VERSION 5.8 ;
BUSBITCHARS "[]" ;
DIVIDERCHAR "/" ;
UNITS
    DATABASE MICRONS 1000 ;
END UNITS

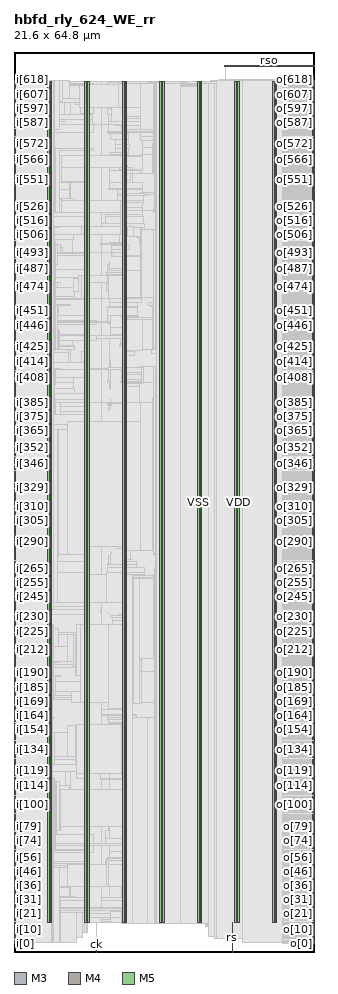
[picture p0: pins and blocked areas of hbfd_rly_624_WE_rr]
MACRO hbfd_rly_624_WE_rr
  FOREIGN hbfd_rly_624_WE_rr 0 0 ;
  CLASS BLOCK ;
  SIZE 21.6 BY 64.8 ;
  PIN ck
    DIRECTION INPUT ;
    USE SIGNAL ;
    PORT
      LAYER M3 ;
        RECT  5.904 0 5.922 0.038 ;
    END
    PORT
      LAYER M3 ;
        RECT  5.904 0.012 5.922 0.125 ;
    END
  END ck
  PIN i[0]
    DIRECTION INPUT ;
    USE SIGNAL ;
    PORT
      LAYER M4 ;
        RECT  0 0.624 0.084 0.648 ;
    END
  END i[0]
  PIN i[100]
    DIRECTION INPUT ;
    USE SIGNAL ;
    PORT
      LAYER M4 ;
        RECT  0 10.608 0.084 10.632 ;
    END
  END i[100]
  PIN i[101]
    DIRECTION INPUT ;
    USE SIGNAL ;
    PORT
      LAYER M4 ;
        RECT  0 10.704 0.084 10.728 ;
    END
  END i[101]
  PIN i[102]
    DIRECTION INPUT ;
    USE SIGNAL ;
    PORT
      LAYER M4 ;
        RECT  0 10.8 0.084 10.824 ;
    END
  END i[102]
  PIN i[103]
    DIRECTION INPUT ;
    USE SIGNAL ;
    PORT
      LAYER M4 ;
        RECT  0 10.896 0.084 10.92 ;
    END
  END i[103]
  PIN i[104]
    DIRECTION INPUT ;
    USE SIGNAL ;
    PORT
      LAYER M4 ;
        RECT  0 10.992 0.084 11.016 ;
    END
  END i[104]
  PIN i[105]
    DIRECTION INPUT ;
    USE SIGNAL ;
    PORT
      LAYER M4 ;
        RECT  0 11.088 0.084 11.112 ;
    END
  END i[105]
  PIN i[106]
    DIRECTION INPUT ;
    USE SIGNAL ;
    PORT
      LAYER M4 ;
        RECT  0 11.184 0.084 11.208 ;
    END
  END i[106]
  PIN i[107]
    DIRECTION INPUT ;
    USE SIGNAL ;
    PORT
      LAYER M4 ;
        RECT  0 11.328 0.084 11.352 ;
    END
  END i[107]
  PIN i[108]
    DIRECTION INPUT ;
    USE SIGNAL ;
    PORT
      LAYER M4 ;
        RECT  0 11.424 0.084 11.448 ;
    END
  END i[108]
  PIN i[109]
    DIRECTION INPUT ;
    USE SIGNAL ;
    PORT
      LAYER M4 ;
        RECT  0 11.52 0.084 11.544 ;
    END
  END i[109]
  PIN i[10]
    DIRECTION INPUT ;
    USE SIGNAL ;
    PORT
      LAYER M4 ;
        RECT  0 1.632 0.084 1.656 ;
    END
  END i[10]
  PIN i[110]
    DIRECTION INPUT ;
    USE SIGNAL ;
    PORT
      LAYER M4 ;
        RECT  0 11.616 0.084 11.64 ;
    END
  END i[110]
  PIN i[111]
    DIRECTION INPUT ;
    USE SIGNAL ;
    PORT
      LAYER M4 ;
        RECT  0 11.712 0.084 11.736 ;
    END
  END i[111]
  PIN i[112]
    DIRECTION INPUT ;
    USE SIGNAL ;
    PORT
      LAYER M4 ;
        RECT  0 11.808 0.084 11.832 ;
    END
  END i[112]
  PIN i[113]
    DIRECTION INPUT ;
    USE SIGNAL ;
    PORT
      LAYER M4 ;
        RECT  0 11.904 0.084 11.928 ;
    END
  END i[113]
  PIN i[114]
    DIRECTION INPUT ;
    USE SIGNAL ;
    PORT
      LAYER M4 ;
        RECT  0 12 0.084 12.024 ;
    END
  END i[114]
  PIN i[115]
    DIRECTION INPUT ;
    USE SIGNAL ;
    PORT
      LAYER M4 ;
        RECT  0 12.096 0.084 12.12 ;
    END
  END i[115]
  PIN i[116]
    DIRECTION INPUT ;
    USE SIGNAL ;
    PORT
      LAYER M4 ;
        RECT  0 12.192 0.084 12.216 ;
    END
  END i[116]
  PIN i[117]
    DIRECTION INPUT ;
    USE SIGNAL ;
    PORT
      LAYER M4 ;
        RECT  0 12.288 0.084 12.312 ;
    END
  END i[117]
  PIN i[118]
    DIRECTION INPUT ;
    USE SIGNAL ;
    PORT
      LAYER M4 ;
        RECT  0 12.384 0.084 12.408 ;
    END
  END i[118]
  PIN i[119]
    DIRECTION INPUT ;
    USE SIGNAL ;
    PORT
      LAYER M4 ;
        RECT  0 12.48 0.084 12.504 ;
    END
  END i[119]
  PIN i[11]
    DIRECTION INPUT ;
    USE SIGNAL ;
    PORT
      LAYER M4 ;
        RECT  0 1.728 0.084 1.752 ;
    END
  END i[11]
  PIN i[120]
    DIRECTION INPUT ;
    USE SIGNAL ;
    PORT
      LAYER M4 ;
        RECT  0 12.576 0.084 12.6 ;
    END
  END i[120]
  PIN i[121]
    DIRECTION INPUT ;
    USE SIGNAL ;
    PORT
      LAYER M4 ;
        RECT  0 12.72 0.084 12.744 ;
    END
  END i[121]
  PIN i[122]
    DIRECTION INPUT ;
    USE SIGNAL ;
    PORT
      LAYER M4 ;
        RECT  0 12.816 0.084 12.84 ;
    END
  END i[122]
  PIN i[123]
    DIRECTION INPUT ;
    USE SIGNAL ;
    PORT
      LAYER M4 ;
        RECT  0 12.912 0.084 12.936 ;
    END
  END i[123]
  PIN i[124]
    DIRECTION INPUT ;
    USE SIGNAL ;
    PORT
      LAYER M4 ;
        RECT  0 13.008 0.084 13.032 ;
    END
  END i[124]
  PIN i[125]
    DIRECTION INPUT ;
    USE SIGNAL ;
    PORT
      LAYER M4 ;
        RECT  0 13.104 0.084 13.128 ;
    END
  END i[125]
  PIN i[126]
    DIRECTION INPUT ;
    USE SIGNAL ;
    PORT
      LAYER M4 ;
        RECT  0 13.2 0.084 13.224 ;
    END
  END i[126]
  PIN i[127]
    DIRECTION INPUT ;
    USE SIGNAL ;
    PORT
      LAYER M4 ;
        RECT  0 13.296 0.084 13.32 ;
    END
  END i[127]
  PIN i[128]
    DIRECTION INPUT ;
    USE SIGNAL ;
    PORT
      LAYER M4 ;
        RECT  0 13.392 0.084 13.416 ;
    END
  END i[128]
  PIN i[129]
    DIRECTION INPUT ;
    USE SIGNAL ;
    PORT
      LAYER M4 ;
        RECT  0 13.488 0.084 13.512 ;
    END
  END i[129]
  PIN i[12]
    DIRECTION INPUT ;
    USE SIGNAL ;
    PORT
      LAYER M4 ;
        RECT  0 1.824 0.084 1.848 ;
    END
  END i[12]
  PIN i[130]
    DIRECTION INPUT ;
    USE SIGNAL ;
    PORT
      LAYER M4 ;
        RECT  0 13.584 0.084 13.608 ;
    END
  END i[130]
  PIN i[131]
    DIRECTION INPUT ;
    USE SIGNAL ;
    PORT
      LAYER M4 ;
        RECT  0 13.68 0.084 13.704 ;
    END
  END i[131]
  PIN i[132]
    DIRECTION INPUT ;
    USE SIGNAL ;
    PORT
      LAYER M4 ;
        RECT  0 13.776 0.084 13.8 ;
    END
  END i[132]
  PIN i[133]
    DIRECTION INPUT ;
    USE SIGNAL ;
    PORT
      LAYER M4 ;
        RECT  0 13.872 0.084 13.896 ;
    END
  END i[133]
  PIN i[134]
    DIRECTION INPUT ;
    USE SIGNAL ;
    PORT
      LAYER M4 ;
        RECT  0 14.016 0.084 14.04 ;
    END
  END i[134]
  PIN i[135]
    DIRECTION INPUT ;
    USE SIGNAL ;
    PORT
      LAYER M4 ;
        RECT  0 14.112 0.084 14.136 ;
    END
  END i[135]
  PIN i[136]
    DIRECTION INPUT ;
    USE SIGNAL ;
    PORT
      LAYER M4 ;
        RECT  0 14.208 0.084 14.232 ;
    END
  END i[136]
  PIN i[137]
    DIRECTION INPUT ;
    USE SIGNAL ;
    PORT
      LAYER M4 ;
        RECT  0 14.304 0.084 14.328 ;
    END
  END i[137]
  PIN i[138]
    DIRECTION INPUT ;
    USE SIGNAL ;
    PORT
      LAYER M4 ;
        RECT  0 14.4 0.084 14.424 ;
    END
  END i[138]
  PIN i[139]
    DIRECTION INPUT ;
    USE SIGNAL ;
    PORT
      LAYER M4 ;
        RECT  0 14.496 0.084 14.52 ;
    END
  END i[139]
  PIN i[13]
    DIRECTION INPUT ;
    USE SIGNAL ;
    PORT
      LAYER M4 ;
        RECT  0 1.92 0.084 1.944 ;
    END
  END i[13]
  PIN i[140]
    DIRECTION INPUT ;
    USE SIGNAL ;
    PORT
      LAYER M4 ;
        RECT  0 14.592 0.084 14.616 ;
    END
  END i[140]
  PIN i[141]
    DIRECTION INPUT ;
    USE SIGNAL ;
    PORT
      LAYER M4 ;
        RECT  0 14.688 0.084 14.712 ;
    END
  END i[141]
  PIN i[142]
    DIRECTION INPUT ;
    USE SIGNAL ;
    PORT
      LAYER M4 ;
        RECT  0 14.784 0.084 14.808 ;
    END
  END i[142]
  PIN i[143]
    DIRECTION INPUT ;
    USE SIGNAL ;
    PORT
      LAYER M4 ;
        RECT  0 14.88 0.084 14.904 ;
    END
  END i[143]
  PIN i[144]
    DIRECTION INPUT ;
    USE SIGNAL ;
    PORT
      LAYER M4 ;
        RECT  0 14.976 0.084 15 ;
    END
  END i[144]
  PIN i[145]
    DIRECTION INPUT ;
    USE SIGNAL ;
    PORT
      LAYER M4 ;
        RECT  0 15.072 0.084 15.096 ;
    END
  END i[145]
  PIN i[146]
    DIRECTION INPUT ;
    USE SIGNAL ;
    PORT
      LAYER M4 ;
        RECT  0 15.168 0.084 15.192 ;
    END
  END i[146]
  PIN i[147]
    DIRECTION INPUT ;
    USE SIGNAL ;
    PORT
      LAYER M4 ;
        RECT  0 15.312 0.084 15.336 ;
    END
  END i[147]
  PIN i[148]
    DIRECTION INPUT ;
    USE SIGNAL ;
    PORT
      LAYER M4 ;
        RECT  0 15.408 0.084 15.432 ;
    END
  END i[148]
  PIN i[149]
    DIRECTION INPUT ;
    USE SIGNAL ;
    PORT
      LAYER M4 ;
        RECT  0 15.504 0.084 15.528 ;
    END
  END i[149]
  PIN i[14]
    DIRECTION INPUT ;
    USE SIGNAL ;
    PORT
      LAYER M4 ;
        RECT  0 2.016 0.084 2.04 ;
    END
  END i[14]
  PIN i[150]
    DIRECTION INPUT ;
    USE SIGNAL ;
    PORT
      LAYER M4 ;
        RECT  0 15.6 0.084 15.624 ;
    END
  END i[150]
  PIN i[151]
    DIRECTION INPUT ;
    USE SIGNAL ;
    PORT
      LAYER M4 ;
        RECT  0 15.696 0.084 15.72 ;
    END
  END i[151]
  PIN i[152]
    DIRECTION INPUT ;
    USE SIGNAL ;
    PORT
      LAYER M4 ;
        RECT  0 15.792 0.084 15.816 ;
    END
  END i[152]
  PIN i[153]
    DIRECTION INPUT ;
    USE SIGNAL ;
    PORT
      LAYER M4 ;
        RECT  0 15.888 0.084 15.912 ;
    END
  END i[153]
  PIN i[154]
    DIRECTION INPUT ;
    USE SIGNAL ;
    PORT
      LAYER M4 ;
        RECT  0 15.984 0.084 16.008 ;
    END
  END i[154]
  PIN i[155]
    DIRECTION INPUT ;
    USE SIGNAL ;
    PORT
      LAYER M4 ;
        RECT  0 16.08 0.084 16.104 ;
    END
  END i[155]
  PIN i[156]
    DIRECTION INPUT ;
    USE SIGNAL ;
    PORT
      LAYER M4 ;
        RECT  0 16.176 0.084 16.2 ;
    END
  END i[156]
  PIN i[157]
    DIRECTION INPUT ;
    USE SIGNAL ;
    PORT
      LAYER M4 ;
        RECT  0 16.272 0.084 16.296 ;
    END
  END i[157]
  PIN i[158]
    DIRECTION INPUT ;
    USE SIGNAL ;
    PORT
      LAYER M4 ;
        RECT  0 16.368 0.084 16.392 ;
    END
  END i[158]
  PIN i[159]
    DIRECTION INPUT ;
    USE SIGNAL ;
    PORT
      LAYER M4 ;
        RECT  0 16.464 0.084 16.488 ;
    END
  END i[159]
  PIN i[15]
    DIRECTION INPUT ;
    USE SIGNAL ;
    PORT
      LAYER M4 ;
        RECT  0 2.112 0.084 2.136 ;
    END
  END i[15]
  PIN i[160]
    DIRECTION INPUT ;
    USE SIGNAL ;
    PORT
      LAYER M4 ;
        RECT  0 16.608 0.084 16.632 ;
    END
  END i[160]
  PIN i[161]
    DIRECTION INPUT ;
    USE SIGNAL ;
    PORT
      LAYER M4 ;
        RECT  0 16.704 0.084 16.728 ;
    END
  END i[161]
  PIN i[162]
    DIRECTION INPUT ;
    USE SIGNAL ;
    PORT
      LAYER M4 ;
        RECT  0 16.8 0.084 16.824 ;
    END
  END i[162]
  PIN i[163]
    DIRECTION INPUT ;
    USE SIGNAL ;
    PORT
      LAYER M4 ;
        RECT  0 16.896 0.084 16.92 ;
    END
  END i[163]
  PIN i[164]
    DIRECTION INPUT ;
    USE SIGNAL ;
    PORT
      LAYER M4 ;
        RECT  0 16.992 0.084 17.016 ;
    END
  END i[164]
  PIN i[165]
    DIRECTION INPUT ;
    USE SIGNAL ;
    PORT
      LAYER M4 ;
        RECT  0 17.088 0.084 17.112 ;
    END
  END i[165]
  PIN i[166]
    DIRECTION INPUT ;
    USE SIGNAL ;
    PORT
      LAYER M4 ;
        RECT  0 17.184 0.084 17.208 ;
    END
  END i[166]
  PIN i[167]
    DIRECTION INPUT ;
    USE SIGNAL ;
    PORT
      LAYER M4 ;
        RECT  0 17.28 0.084 17.304 ;
    END
  END i[167]
  PIN i[168]
    DIRECTION INPUT ;
    USE SIGNAL ;
    PORT
      LAYER M4 ;
        RECT  0 17.376 0.084 17.4 ;
    END
  END i[168]
  PIN i[169]
    DIRECTION INPUT ;
    USE SIGNAL ;
    PORT
      LAYER M4 ;
        RECT  0 17.472 0.084 17.496 ;
    END
  END i[169]
  PIN i[16]
    DIRECTION INPUT ;
    USE SIGNAL ;
    PORT
      LAYER M4 ;
        RECT  0 2.256 0.084 2.28 ;
    END
  END i[16]
  PIN i[170]
    DIRECTION INPUT ;
    USE SIGNAL ;
    PORT
      LAYER M4 ;
        RECT  0 17.568 0.084 17.592 ;
    END
  END i[170]
  PIN i[171]
    DIRECTION INPUT ;
    USE SIGNAL ;
    PORT
      LAYER M4 ;
        RECT  0 17.664 0.084 17.688 ;
    END
  END i[171]
  PIN i[172]
    DIRECTION INPUT ;
    USE SIGNAL ;
    PORT
      LAYER M4 ;
        RECT  0 17.76 0.084 17.784 ;
    END
  END i[172]
  PIN i[173]
    DIRECTION INPUT ;
    USE SIGNAL ;
    PORT
      LAYER M4 ;
        RECT  0 17.904 0.084 17.928 ;
    END
  END i[173]
  PIN i[174]
    DIRECTION INPUT ;
    USE SIGNAL ;
    PORT
      LAYER M4 ;
        RECT  0 18 0.084 18.024 ;
    END
  END i[174]
  PIN i[175]
    DIRECTION INPUT ;
    USE SIGNAL ;
    PORT
      LAYER M4 ;
        RECT  0 18.096 0.084 18.12 ;
    END
  END i[175]
  PIN i[176]
    DIRECTION INPUT ;
    USE SIGNAL ;
    PORT
      LAYER M4 ;
        RECT  0 18.192 0.084 18.216 ;
    END
  END i[176]
  PIN i[177]
    DIRECTION INPUT ;
    USE SIGNAL ;
    PORT
      LAYER M4 ;
        RECT  0 18.288 0.084 18.312 ;
    END
  END i[177]
  PIN i[178]
    DIRECTION INPUT ;
    USE SIGNAL ;
    PORT
      LAYER M4 ;
        RECT  0 18.384 0.084 18.408 ;
    END
  END i[178]
  PIN i[179]
    DIRECTION INPUT ;
    USE SIGNAL ;
    PORT
      LAYER M4 ;
        RECT  0 18.48 0.084 18.504 ;
    END
  END i[179]
  PIN i[17]
    DIRECTION INPUT ;
    USE SIGNAL ;
    PORT
      LAYER M4 ;
        RECT  0 2.352 0.084 2.376 ;
    END
  END i[17]
  PIN i[180]
    DIRECTION INPUT ;
    USE SIGNAL ;
    PORT
      LAYER M4 ;
        RECT  0 18.576 0.084 18.6 ;
    END
  END i[180]
  PIN i[181]
    DIRECTION INPUT ;
    USE SIGNAL ;
    PORT
      LAYER M4 ;
        RECT  0 18.672 0.084 18.696 ;
    END
  END i[181]
  PIN i[182]
    DIRECTION INPUT ;
    USE SIGNAL ;
    PORT
      LAYER M4 ;
        RECT  0 18.768 0.084 18.792 ;
    END
  END i[182]
  PIN i[183]
    DIRECTION INPUT ;
    USE SIGNAL ;
    PORT
      LAYER M4 ;
        RECT  0 18.864 0.084 18.888 ;
    END
  END i[183]
  PIN i[184]
    DIRECTION INPUT ;
    USE SIGNAL ;
    PORT
      LAYER M4 ;
        RECT  0 18.96 0.084 18.984 ;
    END
  END i[184]
  PIN i[185]
    DIRECTION INPUT ;
    USE SIGNAL ;
    PORT
      LAYER M4 ;
        RECT  0 19.056 0.084 19.08 ;
    END
  END i[185]
  PIN i[186]
    DIRECTION INPUT ;
    USE SIGNAL ;
    PORT
      LAYER M4 ;
        RECT  0 19.2 0.084 19.224 ;
    END
  END i[186]
  PIN i[187]
    DIRECTION INPUT ;
    USE SIGNAL ;
    PORT
      LAYER M4 ;
        RECT  0 19.296 0.084 19.32 ;
    END
  END i[187]
  PIN i[188]
    DIRECTION INPUT ;
    USE SIGNAL ;
    PORT
      LAYER M4 ;
        RECT  0 19.392 0.084 19.416 ;
    END
  END i[188]
  PIN i[189]
    DIRECTION INPUT ;
    USE SIGNAL ;
    PORT
      LAYER M4 ;
        RECT  0 19.488 0.084 19.512 ;
    END
  END i[189]
  PIN i[18]
    DIRECTION INPUT ;
    USE SIGNAL ;
    PORT
      LAYER M4 ;
        RECT  0 2.448 0.084 2.472 ;
    END
  END i[18]
  PIN i[190]
    DIRECTION INPUT ;
    USE SIGNAL ;
    PORT
      LAYER M4 ;
        RECT  0 19.584 0.084 19.608 ;
    END
  END i[190]
  PIN i[191]
    DIRECTION INPUT ;
    USE SIGNAL ;
    PORT
      LAYER M4 ;
        RECT  0 19.68 0.084 19.704 ;
    END
  END i[191]
  PIN i[192]
    DIRECTION INPUT ;
    USE SIGNAL ;
    PORT
      LAYER M4 ;
        RECT  0 19.776 0.084 19.8 ;
    END
  END i[192]
  PIN i[193]
    DIRECTION INPUT ;
    USE SIGNAL ;
    PORT
      LAYER M4 ;
        RECT  0 19.872 0.084 19.896 ;
    END
  END i[193]
  PIN i[194]
    DIRECTION INPUT ;
    USE SIGNAL ;
    PORT
      LAYER M4 ;
        RECT  0 19.968 0.084 19.992 ;
    END
  END i[194]
  PIN i[195]
    DIRECTION INPUT ;
    USE SIGNAL ;
    PORT
      LAYER M4 ;
        RECT  0 20.064 0.084 20.088 ;
    END
  END i[195]
  PIN i[196]
    DIRECTION INPUT ;
    USE SIGNAL ;
    PORT
      LAYER M4 ;
        RECT  0 20.16 0.084 20.184 ;
    END
  END i[196]
  PIN i[197]
    DIRECTION INPUT ;
    USE SIGNAL ;
    PORT
      LAYER M4 ;
        RECT  0 20.256 0.084 20.28 ;
    END
  END i[197]
  PIN i[198]
    DIRECTION INPUT ;
    USE SIGNAL ;
    PORT
      LAYER M4 ;
        RECT  0 20.352 0.084 20.376 ;
    END
  END i[198]
  PIN i[199]
    DIRECTION INPUT ;
    USE SIGNAL ;
    PORT
      LAYER M4 ;
        RECT  0 20.496 0.084 20.52 ;
    END
  END i[199]
  PIN i[19]
    DIRECTION INPUT ;
    USE SIGNAL ;
    PORT
      LAYER M4 ;
        RECT  0 2.544 0.084 2.568 ;
    END
  END i[19]
  PIN i[1]
    DIRECTION INPUT ;
    USE SIGNAL ;
    PORT
      LAYER M4 ;
        RECT  0 0.72 0.084 0.744 ;
    END
  END i[1]
  PIN i[200]
    DIRECTION INPUT ;
    USE SIGNAL ;
    PORT
      LAYER M4 ;
        RECT  0 20.592 0.084 20.616 ;
    END
  END i[200]
  PIN i[201]
    DIRECTION INPUT ;
    USE SIGNAL ;
    PORT
      LAYER M4 ;
        RECT  0 20.688 0.084 20.712 ;
    END
  END i[201]
  PIN i[202]
    DIRECTION INPUT ;
    USE SIGNAL ;
    PORT
      LAYER M4 ;
        RECT  0 20.784 0.084 20.808 ;
    END
  END i[202]
  PIN i[203]
    DIRECTION INPUT ;
    USE SIGNAL ;
    PORT
      LAYER M4 ;
        RECT  0 20.88 0.084 20.904 ;
    END
  END i[203]
  PIN i[204]
    DIRECTION INPUT ;
    USE SIGNAL ;
    PORT
      LAYER M4 ;
        RECT  0 20.976 0.084 21 ;
    END
  END i[204]
  PIN i[205]
    DIRECTION INPUT ;
    USE SIGNAL ;
    PORT
      LAYER M4 ;
        RECT  0 21.072 0.084 21.096 ;
    END
  END i[205]
  PIN i[206]
    DIRECTION INPUT ;
    USE SIGNAL ;
    PORT
      LAYER M4 ;
        RECT  0 21.168 0.084 21.192 ;
    END
  END i[206]
  PIN i[207]
    DIRECTION INPUT ;
    USE SIGNAL ;
    PORT
      LAYER M4 ;
        RECT  0 21.264 0.084 21.288 ;
    END
  END i[207]
  PIN i[208]
    DIRECTION INPUT ;
    USE SIGNAL ;
    PORT
      LAYER M4 ;
        RECT  0 21.36 0.084 21.384 ;
    END
  END i[208]
  PIN i[209]
    DIRECTION INPUT ;
    USE SIGNAL ;
    PORT
      LAYER M4 ;
        RECT  0 21.456 0.084 21.48 ;
    END
  END i[209]
  PIN i[20]
    DIRECTION INPUT ;
    USE SIGNAL ;
    PORT
      LAYER M4 ;
        RECT  0 2.64 0.084 2.664 ;
    END
  END i[20]
  PIN i[210]
    DIRECTION INPUT ;
    USE SIGNAL ;
    PORT
      LAYER M4 ;
        RECT  0 21.552 0.084 21.576 ;
    END
  END i[210]
  PIN i[211]
    DIRECTION INPUT ;
    USE SIGNAL ;
    PORT
      LAYER M4 ;
        RECT  0 21.648 0.084 21.672 ;
    END
  END i[211]
  PIN i[212]
    DIRECTION INPUT ;
    USE SIGNAL ;
    PORT
      LAYER M4 ;
        RECT  0 21.792 0.084 21.816 ;
    END
  END i[212]
  PIN i[213]
    DIRECTION INPUT ;
    USE SIGNAL ;
    PORT
      LAYER M4 ;
        RECT  0 21.888 0.084 21.912 ;
    END
  END i[213]
  PIN i[214]
    DIRECTION INPUT ;
    USE SIGNAL ;
    PORT
      LAYER M4 ;
        RECT  0 21.984 0.084 22.008 ;
    END
  END i[214]
  PIN i[215]
    DIRECTION INPUT ;
    USE SIGNAL ;
    PORT
      LAYER M4 ;
        RECT  0 22.08 0.084 22.104 ;
    END
  END i[215]
  PIN i[216]
    DIRECTION INPUT ;
    USE SIGNAL ;
    PORT
      LAYER M4 ;
        RECT  0 22.176 0.084 22.2 ;
    END
  END i[216]
  PIN i[217]
    DIRECTION INPUT ;
    USE SIGNAL ;
    PORT
      LAYER M4 ;
        RECT  0 22.272 0.084 22.296 ;
    END
  END i[217]
  PIN i[218]
    DIRECTION INPUT ;
    USE SIGNAL ;
    PORT
      LAYER M4 ;
        RECT  0 22.368 0.084 22.392 ;
    END
  END i[218]
  PIN i[219]
    DIRECTION INPUT ;
    USE SIGNAL ;
    PORT
      LAYER M4 ;
        RECT  0 22.464 0.084 22.488 ;
    END
  END i[219]
  PIN i[21]
    DIRECTION INPUT ;
    USE SIGNAL ;
    PORT
      LAYER M4 ;
        RECT  0 2.736 0.084 2.76 ;
    END
  END i[21]
  PIN i[220]
    DIRECTION INPUT ;
    USE SIGNAL ;
    PORT
      LAYER M4 ;
        RECT  0 22.56 0.084 22.584 ;
    END
  END i[220]
  PIN i[221]
    DIRECTION INPUT ;
    USE SIGNAL ;
    PORT
      LAYER M4 ;
        RECT  0 22.656 0.084 22.68 ;
    END
  END i[221]
  PIN i[222]
    DIRECTION INPUT ;
    USE SIGNAL ;
    PORT
      LAYER M4 ;
        RECT  0 22.752 0.084 22.776 ;
    END
  END i[222]
  PIN i[223]
    DIRECTION INPUT ;
    USE SIGNAL ;
    PORT
      LAYER M4 ;
        RECT  0 22.848 0.084 22.872 ;
    END
  END i[223]
  PIN i[224]
    DIRECTION INPUT ;
    USE SIGNAL ;
    PORT
      LAYER M4 ;
        RECT  0 22.944 0.084 22.968 ;
    END
  END i[224]
  PIN i[225]
    DIRECTION INPUT ;
    USE SIGNAL ;
    PORT
      LAYER M4 ;
        RECT  0 23.088 0.084 23.112 ;
    END
  END i[225]
  PIN i[226]
    DIRECTION INPUT ;
    USE SIGNAL ;
    PORT
      LAYER M4 ;
        RECT  0 23.184 0.084 23.208 ;
    END
  END i[226]
  PIN i[227]
    DIRECTION INPUT ;
    USE SIGNAL ;
    PORT
      LAYER M4 ;
        RECT  0 23.28 0.084 23.304 ;
    END
  END i[227]
  PIN i[228]
    DIRECTION INPUT ;
    USE SIGNAL ;
    PORT
      LAYER M4 ;
        RECT  0 23.376 0.084 23.4 ;
    END
  END i[228]
  PIN i[229]
    DIRECTION INPUT ;
    USE SIGNAL ;
    PORT
      LAYER M4 ;
        RECT  0 23.472 0.084 23.496 ;
    END
  END i[229]
  PIN i[22]
    DIRECTION INPUT ;
    USE SIGNAL ;
    PORT
      LAYER M4 ;
        RECT  0 2.832 0.084 2.856 ;
    END
  END i[22]
  PIN i[230]
    DIRECTION INPUT ;
    USE SIGNAL ;
    PORT
      LAYER M4 ;
        RECT  0 23.568 0.084 23.592 ;
    END
  END i[230]
  PIN i[231]
    DIRECTION INPUT ;
    USE SIGNAL ;
    PORT
      LAYER M4 ;
        RECT  0 23.664 0.084 23.688 ;
    END
  END i[231]
  PIN i[232]
    DIRECTION INPUT ;
    USE SIGNAL ;
    PORT
      LAYER M4 ;
        RECT  0 23.76 0.084 23.784 ;
    END
  END i[232]
  PIN i[233]
    DIRECTION INPUT ;
    USE SIGNAL ;
    PORT
      LAYER M4 ;
        RECT  0 23.856 0.084 23.88 ;
    END
  END i[233]
  PIN i[234]
    DIRECTION INPUT ;
    USE SIGNAL ;
    PORT
      LAYER M4 ;
        RECT  0 23.952 0.084 23.976 ;
    END
  END i[234]
  PIN i[235]
    DIRECTION INPUT ;
    USE SIGNAL ;
    PORT
      LAYER M4 ;
        RECT  0 24.048 0.084 24.072 ;
    END
  END i[235]
  PIN i[236]
    DIRECTION INPUT ;
    USE SIGNAL ;
    PORT
      LAYER M4 ;
        RECT  0 24.144 0.084 24.168 ;
    END
  END i[236]
  PIN i[237]
    DIRECTION INPUT ;
    USE SIGNAL ;
    PORT
      LAYER M4 ;
        RECT  0 24.24 0.084 24.264 ;
    END
  END i[237]
  PIN i[238]
    DIRECTION INPUT ;
    USE SIGNAL ;
    PORT
      LAYER M4 ;
        RECT  0 24.384 0.084 24.408 ;
    END
  END i[238]
  PIN i[239]
    DIRECTION INPUT ;
    USE SIGNAL ;
    PORT
      LAYER M4 ;
        RECT  0 24.48 0.084 24.504 ;
    END
  END i[239]
  PIN i[23]
    DIRECTION INPUT ;
    USE SIGNAL ;
    PORT
      LAYER M4 ;
        RECT  0 2.928 0.084 2.952 ;
    END
  END i[23]
  PIN i[240]
    DIRECTION INPUT ;
    USE SIGNAL ;
    PORT
      LAYER M4 ;
        RECT  0 24.576 0.084 24.6 ;
    END
  END i[240]
  PIN i[241]
    DIRECTION INPUT ;
    USE SIGNAL ;
    PORT
      LAYER M4 ;
        RECT  0 24.672 0.084 24.696 ;
    END
  END i[241]
  PIN i[242]
    DIRECTION INPUT ;
    USE SIGNAL ;
    PORT
      LAYER M4 ;
        RECT  0 24.768 0.084 24.792 ;
    END
  END i[242]
  PIN i[243]
    DIRECTION INPUT ;
    USE SIGNAL ;
    PORT
      LAYER M4 ;
        RECT  0 24.864 0.084 24.888 ;
    END
  END i[243]
  PIN i[244]
    DIRECTION INPUT ;
    USE SIGNAL ;
    PORT
      LAYER M4 ;
        RECT  0 24.96 0.084 24.984 ;
    END
  END i[244]
  PIN i[245]
    DIRECTION INPUT ;
    USE SIGNAL ;
    PORT
      LAYER M4 ;
        RECT  0 25.056 0.084 25.08 ;
    END
  END i[245]
  PIN i[246]
    DIRECTION INPUT ;
    USE SIGNAL ;
    PORT
      LAYER M4 ;
        RECT  0 25.152 0.084 25.176 ;
    END
  END i[246]
  PIN i[247]
    DIRECTION INPUT ;
    USE SIGNAL ;
    PORT
      LAYER M4 ;
        RECT  0 25.248 0.084 25.272 ;
    END
  END i[247]
  PIN i[248]
    DIRECTION INPUT ;
    USE SIGNAL ;
    PORT
      LAYER M4 ;
        RECT  0 25.344 0.084 25.368 ;
    END
  END i[248]
  PIN i[249]
    DIRECTION INPUT ;
    USE SIGNAL ;
    PORT
      LAYER M4 ;
        RECT  0 25.44 0.084 25.464 ;
    END
  END i[249]
  PIN i[24]
    DIRECTION INPUT ;
    USE SIGNAL ;
    PORT
      LAYER M4 ;
        RECT  0 3.024 0.084 3.048 ;
    END
  END i[24]
  PIN i[250]
    DIRECTION INPUT ;
    USE SIGNAL ;
    PORT
      LAYER M4 ;
        RECT  0 25.536 0.084 25.56 ;
    END
  END i[250]
  PIN i[251]
    DIRECTION INPUT ;
    USE SIGNAL ;
    PORT
      LAYER M4 ;
        RECT  0 25.68 0.084 25.704 ;
    END
  END i[251]
  PIN i[252]
    DIRECTION INPUT ;
    USE SIGNAL ;
    PORT
      LAYER M4 ;
        RECT  0 25.776 0.084 25.8 ;
    END
  END i[252]
  PIN i[253]
    DIRECTION INPUT ;
    USE SIGNAL ;
    PORT
      LAYER M4 ;
        RECT  0 25.872 0.084 25.896 ;
    END
  END i[253]
  PIN i[254]
    DIRECTION INPUT ;
    USE SIGNAL ;
    PORT
      LAYER M4 ;
        RECT  0 25.968 0.084 25.992 ;
    END
  END i[254]
  PIN i[255]
    DIRECTION INPUT ;
    USE SIGNAL ;
    PORT
      LAYER M4 ;
        RECT  0 26.064 0.084 26.088 ;
    END
  END i[255]
  PIN i[256]
    DIRECTION INPUT ;
    USE SIGNAL ;
    PORT
      LAYER M4 ;
        RECT  0 26.16 0.084 26.184 ;
    END
  END i[256]
  PIN i[257]
    DIRECTION INPUT ;
    USE SIGNAL ;
    PORT
      LAYER M4 ;
        RECT  0 26.256 0.084 26.28 ;
    END
  END i[257]
  PIN i[258]
    DIRECTION INPUT ;
    USE SIGNAL ;
    PORT
      LAYER M4 ;
        RECT  0 26.352 0.084 26.376 ;
    END
  END i[258]
  PIN i[259]
    DIRECTION INPUT ;
    USE SIGNAL ;
    PORT
      LAYER M4 ;
        RECT  0 26.448 0.084 26.472 ;
    END
  END i[259]
  PIN i[25]
    DIRECTION INPUT ;
    USE SIGNAL ;
    PORT
      LAYER M4 ;
        RECT  0 3.12 0.084 3.144 ;
    END
  END i[25]
  PIN i[260]
    DIRECTION INPUT ;
    USE SIGNAL ;
    PORT
      LAYER M4 ;
        RECT  0 26.544 0.084 26.568 ;
    END
  END i[260]
  PIN i[261]
    DIRECTION INPUT ;
    USE SIGNAL ;
    PORT
      LAYER M4 ;
        RECT  0 26.64 0.084 26.664 ;
    END
  END i[261]
  PIN i[262]
    DIRECTION INPUT ;
    USE SIGNAL ;
    PORT
      LAYER M4 ;
        RECT  0 26.736 0.084 26.76 ;
    END
  END i[262]
  PIN i[263]
    DIRECTION INPUT ;
    USE SIGNAL ;
    PORT
      LAYER M4 ;
        RECT  0 26.832 0.084 26.856 ;
    END
  END i[263]
  PIN i[264]
    DIRECTION INPUT ;
    USE SIGNAL ;
    PORT
      LAYER M4 ;
        RECT  0 26.976 0.084 27 ;
    END
  END i[264]
  PIN i[265]
    DIRECTION INPUT ;
    USE SIGNAL ;
    PORT
      LAYER M4 ;
        RECT  0 27.072 0.084 27.096 ;
    END
  END i[265]
  PIN i[266]
    DIRECTION INPUT ;
    USE SIGNAL ;
    PORT
      LAYER M4 ;
        RECT  0 27.168 0.084 27.192 ;
    END
  END i[266]
  PIN i[267]
    DIRECTION INPUT ;
    USE SIGNAL ;
    PORT
      LAYER M4 ;
        RECT  0 27.264 0.084 27.288 ;
    END
  END i[267]
  PIN i[268]
    DIRECTION INPUT ;
    USE SIGNAL ;
    PORT
      LAYER M4 ;
        RECT  0 27.36 0.084 27.384 ;
    END
  END i[268]
  PIN i[269]
    DIRECTION INPUT ;
    USE SIGNAL ;
    PORT
      LAYER M4 ;
        RECT  0 27.456 0.084 27.48 ;
    END
  END i[269]
  PIN i[26]
    DIRECTION INPUT ;
    USE SIGNAL ;
    PORT
      LAYER M4 ;
        RECT  0 3.216 0.084 3.24 ;
    END
  END i[26]
  PIN i[270]
    DIRECTION INPUT ;
    USE SIGNAL ;
    PORT
      LAYER M4 ;
        RECT  0 27.552 0.084 27.576 ;
    END
  END i[270]
  PIN i[271]
    DIRECTION INPUT ;
    USE SIGNAL ;
    PORT
      LAYER M4 ;
        RECT  0 27.648 0.084 27.672 ;
    END
  END i[271]
  PIN i[272]
    DIRECTION INPUT ;
    USE SIGNAL ;
    PORT
      LAYER M4 ;
        RECT  0 27.744 0.084 27.768 ;
    END
  END i[272]
  PIN i[273]
    DIRECTION INPUT ;
    USE SIGNAL ;
    PORT
      LAYER M4 ;
        RECT  0 27.84 0.084 27.864 ;
    END
  END i[273]
  PIN i[274]
    DIRECTION INPUT ;
    USE SIGNAL ;
    PORT
      LAYER M4 ;
        RECT  0 27.936 0.084 27.96 ;
    END
  END i[274]
  PIN i[275]
    DIRECTION INPUT ;
    USE SIGNAL ;
    PORT
      LAYER M4 ;
        RECT  0 28.032 0.084 28.056 ;
    END
  END i[275]
  PIN i[276]
    DIRECTION INPUT ;
    USE SIGNAL ;
    PORT
      LAYER M4 ;
        RECT  0 28.128 0.084 28.152 ;
    END
  END i[276]
  PIN i[277]
    DIRECTION INPUT ;
    USE SIGNAL ;
    PORT
      LAYER M4 ;
        RECT  0 28.272 0.084 28.296 ;
    END
  END i[277]
  PIN i[278]
    DIRECTION INPUT ;
    USE SIGNAL ;
    PORT
      LAYER M4 ;
        RECT  0 28.368 0.084 28.392 ;
    END
  END i[278]
  PIN i[279]
    DIRECTION INPUT ;
    USE SIGNAL ;
    PORT
      LAYER M4 ;
        RECT  0 28.464 0.084 28.488 ;
    END
  END i[279]
  PIN i[27]
    DIRECTION INPUT ;
    USE SIGNAL ;
    PORT
      LAYER M4 ;
        RECT  0 3.312 0.084 3.336 ;
    END
  END i[27]
  PIN i[280]
    DIRECTION INPUT ;
    USE SIGNAL ;
    PORT
      LAYER M4 ;
        RECT  0 28.56 0.084 28.584 ;
    END
  END i[280]
  PIN i[281]
    DIRECTION INPUT ;
    USE SIGNAL ;
    PORT
      LAYER M4 ;
        RECT  0 28.656 0.084 28.68 ;
    END
  END i[281]
  PIN i[282]
    DIRECTION INPUT ;
    USE SIGNAL ;
    PORT
      LAYER M4 ;
        RECT  0 28.752 0.084 28.776 ;
    END
  END i[282]
  PIN i[283]
    DIRECTION INPUT ;
    USE SIGNAL ;
    PORT
      LAYER M4 ;
        RECT  0 28.848 0.084 28.872 ;
    END
  END i[283]
  PIN i[284]
    DIRECTION INPUT ;
    USE SIGNAL ;
    PORT
      LAYER M4 ;
        RECT  0 28.944 0.084 28.968 ;
    END
  END i[284]
  PIN i[285]
    DIRECTION INPUT ;
    USE SIGNAL ;
    PORT
      LAYER M4 ;
        RECT  0 29.04 0.084 29.064 ;
    END
  END i[285]
  PIN i[286]
    DIRECTION INPUT ;
    USE SIGNAL ;
    PORT
      LAYER M4 ;
        RECT  0 29.136 0.084 29.16 ;
    END
  END i[286]
  PIN i[287]
    DIRECTION INPUT ;
    USE SIGNAL ;
    PORT
      LAYER M4 ;
        RECT  0 29.232 0.084 29.256 ;
    END
  END i[287]
  PIN i[288]
    DIRECTION INPUT ;
    USE SIGNAL ;
    PORT
      LAYER M4 ;
        RECT  0 29.328 0.084 29.352 ;
    END
  END i[288]
  PIN i[289]
    DIRECTION INPUT ;
    USE SIGNAL ;
    PORT
      LAYER M4 ;
        RECT  0 29.424 0.084 29.448 ;
    END
  END i[289]
  PIN i[28]
    DIRECTION INPUT ;
    USE SIGNAL ;
    PORT
      LAYER M4 ;
        RECT  0 3.408 0.084 3.432 ;
    END
  END i[28]
  PIN i[290]
    DIRECTION INPUT ;
    USE SIGNAL ;
    PORT
      LAYER M4 ;
        RECT  0 29.568 0.084 29.592 ;
    END
  END i[290]
  PIN i[291]
    DIRECTION INPUT ;
    USE SIGNAL ;
    PORT
      LAYER M4 ;
        RECT  0 29.664 0.084 29.688 ;
    END
  END i[291]
  PIN i[292]
    DIRECTION INPUT ;
    USE SIGNAL ;
    PORT
      LAYER M4 ;
        RECT  0 29.76 0.084 29.784 ;
    END
  END i[292]
  PIN i[293]
    DIRECTION INPUT ;
    USE SIGNAL ;
    PORT
      LAYER M4 ;
        RECT  0 29.856 0.084 29.88 ;
    END
  END i[293]
  PIN i[294]
    DIRECTION INPUT ;
    USE SIGNAL ;
    PORT
      LAYER M4 ;
        RECT  0 29.952 0.084 29.976 ;
    END
  END i[294]
  PIN i[295]
    DIRECTION INPUT ;
    USE SIGNAL ;
    PORT
      LAYER M4 ;
        RECT  0 30.048 0.084 30.072 ;
    END
  END i[295]
  PIN i[296]
    DIRECTION INPUT ;
    USE SIGNAL ;
    PORT
      LAYER M4 ;
        RECT  0 30.144 0.084 30.168 ;
    END
  END i[296]
  PIN i[297]
    DIRECTION INPUT ;
    USE SIGNAL ;
    PORT
      LAYER M4 ;
        RECT  0 30.24 0.084 30.264 ;
    END
  END i[297]
  PIN i[298]
    DIRECTION INPUT ;
    USE SIGNAL ;
    PORT
      LAYER M4 ;
        RECT  0 30.336 0.084 30.36 ;
    END
  END i[298]
  PIN i[299]
    DIRECTION INPUT ;
    USE SIGNAL ;
    PORT
      LAYER M4 ;
        RECT  0 30.432 0.084 30.456 ;
    END
  END i[299]
  PIN i[29]
    DIRECTION INPUT ;
    USE SIGNAL ;
    PORT
      LAYER M4 ;
        RECT  0 3.552 0.084 3.576 ;
    END
  END i[29]
  PIN i[2]
    DIRECTION INPUT ;
    USE SIGNAL ;
    PORT
      LAYER M4 ;
        RECT  0 0.816 0.084 0.84 ;
    END
  END i[2]
  PIN i[300]
    DIRECTION INPUT ;
    USE SIGNAL ;
    PORT
      LAYER M4 ;
        RECT  0 30.528 0.084 30.552 ;
    END
  END i[300]
  PIN i[301]
    DIRECTION INPUT ;
    USE SIGNAL ;
    PORT
      LAYER M4 ;
        RECT  0 30.624 0.084 30.648 ;
    END
  END i[301]
  PIN i[302]
    DIRECTION INPUT ;
    USE SIGNAL ;
    PORT
      LAYER M4 ;
        RECT  0 30.72 0.084 30.744 ;
    END
  END i[302]
  PIN i[303]
    DIRECTION INPUT ;
    USE SIGNAL ;
    PORT
      LAYER M4 ;
        RECT  0 30.864 0.084 30.888 ;
    END
  END i[303]
  PIN i[304]
    DIRECTION INPUT ;
    USE SIGNAL ;
    PORT
      LAYER M4 ;
        RECT  0 30.96 0.084 30.984 ;
    END
  END i[304]
  PIN i[305]
    DIRECTION INPUT ;
    USE SIGNAL ;
    PORT
      LAYER M4 ;
        RECT  0 31.056 0.084 31.08 ;
    END
  END i[305]
  PIN i[306]
    DIRECTION INPUT ;
    USE SIGNAL ;
    PORT
      LAYER M4 ;
        RECT  0 31.152 0.084 31.176 ;
    END
  END i[306]
  PIN i[307]
    DIRECTION INPUT ;
    USE SIGNAL ;
    PORT
      LAYER M4 ;
        RECT  0 31.248 0.084 31.272 ;
    END
  END i[307]
  PIN i[308]
    DIRECTION INPUT ;
    USE SIGNAL ;
    PORT
      LAYER M4 ;
        RECT  0 31.344 0.084 31.368 ;
    END
  END i[308]
  PIN i[309]
    DIRECTION INPUT ;
    USE SIGNAL ;
    PORT
      LAYER M4 ;
        RECT  0 31.44 0.084 31.464 ;
    END
  END i[309]
  PIN i[30]
    DIRECTION INPUT ;
    USE SIGNAL ;
    PORT
      LAYER M4 ;
        RECT  0 3.648 0.084 3.672 ;
    END
  END i[30]
  PIN i[310]
    DIRECTION INPUT ;
    USE SIGNAL ;
    PORT
      LAYER M4 ;
        RECT  0 31.536 0.084 31.56 ;
    END
  END i[310]
  PIN i[311]
    DIRECTION INPUT ;
    USE SIGNAL ;
    PORT
      LAYER M4 ;
        RECT  0 31.632 0.084 31.656 ;
    END
  END i[311]
  PIN i[312]
    DIRECTION INPUT ;
    USE SIGNAL ;
    PORT
      LAYER M4 ;
        RECT  0 31.728 0.084 31.752 ;
    END
  END i[312]
  PIN i[313]
    DIRECTION INPUT ;
    USE SIGNAL ;
    PORT
      LAYER M4 ;
        RECT  0 31.824 0.084 31.848 ;
    END
  END i[313]
  PIN i[314]
    DIRECTION INPUT ;
    USE SIGNAL ;
    PORT
      LAYER M4 ;
        RECT  0 31.92 0.084 31.944 ;
    END
  END i[314]
  PIN i[315]
    DIRECTION INPUT ;
    USE SIGNAL ;
    PORT
      LAYER M4 ;
        RECT  0 32.016 0.084 32.04 ;
    END
  END i[315]
  PIN i[316]
    DIRECTION INPUT ;
    USE SIGNAL ;
    PORT
      LAYER M4 ;
        RECT  0 32.16 0.084 32.184 ;
    END
  END i[316]
  PIN i[317]
    DIRECTION INPUT ;
    USE SIGNAL ;
    PORT
      LAYER M4 ;
        RECT  0 32.256 0.084 32.28 ;
    END
  END i[317]
  PIN i[318]
    DIRECTION INPUT ;
    USE SIGNAL ;
    PORT
      LAYER M4 ;
        RECT  0 32.352 0.084 32.376 ;
    END
  END i[318]
  PIN i[319]
    DIRECTION INPUT ;
    USE SIGNAL ;
    PORT
      LAYER M4 ;
        RECT  0 32.448 0.084 32.472 ;
    END
  END i[319]
  PIN i[31]
    DIRECTION INPUT ;
    USE SIGNAL ;
    PORT
      LAYER M4 ;
        RECT  0 3.744 0.084 3.768 ;
    END
  END i[31]
  PIN i[320]
    DIRECTION INPUT ;
    USE SIGNAL ;
    PORT
      LAYER M4 ;
        RECT  0 32.544 0.084 32.568 ;
    END
  END i[320]
  PIN i[321]
    DIRECTION INPUT ;
    USE SIGNAL ;
    PORT
      LAYER M4 ;
        RECT  0 32.64 0.084 32.664 ;
    END
  END i[321]
  PIN i[322]
    DIRECTION INPUT ;
    USE SIGNAL ;
    PORT
      LAYER M4 ;
        RECT  0 32.736 0.084 32.76 ;
    END
  END i[322]
  PIN i[323]
    DIRECTION INPUT ;
    USE SIGNAL ;
    PORT
      LAYER M4 ;
        RECT  0 32.832 0.084 32.856 ;
    END
  END i[323]
  PIN i[324]
    DIRECTION INPUT ;
    USE SIGNAL ;
    PORT
      LAYER M4 ;
        RECT  0 32.928 0.084 32.952 ;
    END
  END i[324]
  PIN i[325]
    DIRECTION INPUT ;
    USE SIGNAL ;
    PORT
      LAYER M4 ;
        RECT  0 33.024 0.084 33.048 ;
    END
  END i[325]
  PIN i[326]
    DIRECTION INPUT ;
    USE SIGNAL ;
    PORT
      LAYER M4 ;
        RECT  0 33.12 0.084 33.144 ;
    END
  END i[326]
  PIN i[327]
    DIRECTION INPUT ;
    USE SIGNAL ;
    PORT
      LAYER M4 ;
        RECT  0 33.216 0.084 33.24 ;
    END
  END i[327]
  PIN i[328]
    DIRECTION INPUT ;
    USE SIGNAL ;
    PORT
      LAYER M4 ;
        RECT  0 33.312 0.084 33.336 ;
    END
  END i[328]
  PIN i[329]
    DIRECTION INPUT ;
    USE SIGNAL ;
    PORT
      LAYER M4 ;
        RECT  0 33.456 0.084 33.48 ;
    END
  END i[329]
  PIN i[32]
    DIRECTION INPUT ;
    USE SIGNAL ;
    PORT
      LAYER M4 ;
        RECT  0 3.84 0.084 3.864 ;
    END
  END i[32]
  PIN i[330]
    DIRECTION INPUT ;
    USE SIGNAL ;
    PORT
      LAYER M4 ;
        RECT  0 33.552 0.084 33.576 ;
    END
  END i[330]
  PIN i[331]
    DIRECTION INPUT ;
    USE SIGNAL ;
    PORT
      LAYER M4 ;
        RECT  0 33.648 0.084 33.672 ;
    END
  END i[331]
  PIN i[332]
    DIRECTION INPUT ;
    USE SIGNAL ;
    PORT
      LAYER M4 ;
        RECT  0 33.744 0.084 33.768 ;
    END
  END i[332]
  PIN i[333]
    DIRECTION INPUT ;
    USE SIGNAL ;
    PORT
      LAYER M4 ;
        RECT  0 33.84 0.084 33.864 ;
    END
  END i[333]
  PIN i[334]
    DIRECTION INPUT ;
    USE SIGNAL ;
    PORT
      LAYER M4 ;
        RECT  0 33.936 0.084 33.96 ;
    END
  END i[334]
  PIN i[335]
    DIRECTION INPUT ;
    USE SIGNAL ;
    PORT
      LAYER M4 ;
        RECT  0 34.032 0.084 34.056 ;
    END
  END i[335]
  PIN i[336]
    DIRECTION INPUT ;
    USE SIGNAL ;
    PORT
      LAYER M4 ;
        RECT  0 34.128 0.084 34.152 ;
    END
  END i[336]
  PIN i[337]
    DIRECTION INPUT ;
    USE SIGNAL ;
    PORT
      LAYER M4 ;
        RECT  0 34.224 0.084 34.248 ;
    END
  END i[337]
  PIN i[338]
    DIRECTION INPUT ;
    USE SIGNAL ;
    PORT
      LAYER M4 ;
        RECT  0 34.32 0.084 34.344 ;
    END
  END i[338]
  PIN i[339]
    DIRECTION INPUT ;
    USE SIGNAL ;
    PORT
      LAYER M4 ;
        RECT  0 34.416 0.084 34.44 ;
    END
  END i[339]
  PIN i[33]
    DIRECTION INPUT ;
    USE SIGNAL ;
    PORT
      LAYER M4 ;
        RECT  0 3.936 0.084 3.96 ;
    END
  END i[33]
  PIN i[340]
    DIRECTION INPUT ;
    USE SIGNAL ;
    PORT
      LAYER M4 ;
        RECT  0 34.512 0.084 34.536 ;
    END
  END i[340]
  PIN i[341]
    DIRECTION INPUT ;
    USE SIGNAL ;
    PORT
      LAYER M4 ;
        RECT  0 34.608 0.084 34.632 ;
    END
  END i[341]
  PIN i[342]
    DIRECTION INPUT ;
    USE SIGNAL ;
    PORT
      LAYER M4 ;
        RECT  0 34.752 0.084 34.776 ;
    END
  END i[342]
  PIN i[343]
    DIRECTION INPUT ;
    USE SIGNAL ;
    PORT
      LAYER M4 ;
        RECT  0 34.848 0.084 34.872 ;
    END
  END i[343]
  PIN i[344]
    DIRECTION INPUT ;
    USE SIGNAL ;
    PORT
      LAYER M4 ;
        RECT  0 34.944 0.084 34.968 ;
    END
  END i[344]
  PIN i[345]
    DIRECTION INPUT ;
    USE SIGNAL ;
    PORT
      LAYER M4 ;
        RECT  0 35.04 0.084 35.064 ;
    END
  END i[345]
  PIN i[346]
    DIRECTION INPUT ;
    USE SIGNAL ;
    PORT
      LAYER M4 ;
        RECT  0 35.136 0.084 35.16 ;
    END
  END i[346]
  PIN i[347]
    DIRECTION INPUT ;
    USE SIGNAL ;
    PORT
      LAYER M4 ;
        RECT  0 35.232 0.084 35.256 ;
    END
  END i[347]
  PIN i[348]
    DIRECTION INPUT ;
    USE SIGNAL ;
    PORT
      LAYER M4 ;
        RECT  0 35.328 0.084 35.352 ;
    END
  END i[348]
  PIN i[349]
    DIRECTION INPUT ;
    USE SIGNAL ;
    PORT
      LAYER M4 ;
        RECT  0 35.424 0.084 35.448 ;
    END
  END i[349]
  PIN i[34]
    DIRECTION INPUT ;
    USE SIGNAL ;
    PORT
      LAYER M4 ;
        RECT  0 4.032 0.084 4.056 ;
    END
  END i[34]
  PIN i[350]
    DIRECTION INPUT ;
    USE SIGNAL ;
    PORT
      LAYER M4 ;
        RECT  0 35.52 0.084 35.544 ;
    END
  END i[350]
  PIN i[351]
    DIRECTION INPUT ;
    USE SIGNAL ;
    PORT
      LAYER M4 ;
        RECT  0 35.616 0.084 35.64 ;
    END
  END i[351]
  PIN i[352]
    DIRECTION INPUT ;
    USE SIGNAL ;
    PORT
      LAYER M4 ;
        RECT  0 35.712 0.084 35.736 ;
    END
  END i[352]
  PIN i[353]
    DIRECTION INPUT ;
    USE SIGNAL ;
    PORT
      LAYER M4 ;
        RECT  0 35.808 0.084 35.832 ;
    END
  END i[353]
  PIN i[354]
    DIRECTION INPUT ;
    USE SIGNAL ;
    PORT
      LAYER M4 ;
        RECT  0 35.904 0.084 35.928 ;
    END
  END i[354]
  PIN i[355]
    DIRECTION INPUT ;
    USE SIGNAL ;
    PORT
      LAYER M4 ;
        RECT  0 36.048 0.084 36.072 ;
    END
  END i[355]
  PIN i[356]
    DIRECTION INPUT ;
    USE SIGNAL ;
    PORT
      LAYER M4 ;
        RECT  0 36.144 0.084 36.168 ;
    END
  END i[356]
  PIN i[357]
    DIRECTION INPUT ;
    USE SIGNAL ;
    PORT
      LAYER M4 ;
        RECT  0 36.24 0.084 36.264 ;
    END
  END i[357]
  PIN i[358]
    DIRECTION INPUT ;
    USE SIGNAL ;
    PORT
      LAYER M4 ;
        RECT  0 36.336 0.084 36.36 ;
    END
  END i[358]
  PIN i[359]
    DIRECTION INPUT ;
    USE SIGNAL ;
    PORT
      LAYER M4 ;
        RECT  0 36.432 0.084 36.456 ;
    END
  END i[359]
  PIN i[35]
    DIRECTION INPUT ;
    USE SIGNAL ;
    PORT
      LAYER M4 ;
        RECT  0 4.128 0.084 4.152 ;
    END
  END i[35]
  PIN i[360]
    DIRECTION INPUT ;
    USE SIGNAL ;
    PORT
      LAYER M4 ;
        RECT  0 36.528 0.084 36.552 ;
    END
  END i[360]
  PIN i[361]
    DIRECTION INPUT ;
    USE SIGNAL ;
    PORT
      LAYER M4 ;
        RECT  0 36.624 0.084 36.648 ;
    END
  END i[361]
  PIN i[362]
    DIRECTION INPUT ;
    USE SIGNAL ;
    PORT
      LAYER M4 ;
        RECT  0 36.72 0.084 36.744 ;
    END
  END i[362]
  PIN i[363]
    DIRECTION INPUT ;
    USE SIGNAL ;
    PORT
      LAYER M4 ;
        RECT  0 36.816 0.084 36.84 ;
    END
  END i[363]
  PIN i[364]
    DIRECTION INPUT ;
    USE SIGNAL ;
    PORT
      LAYER M4 ;
        RECT  0 36.912 0.084 36.936 ;
    END
  END i[364]
  PIN i[365]
    DIRECTION INPUT ;
    USE SIGNAL ;
    PORT
      LAYER M4 ;
        RECT  0 37.008 0.084 37.032 ;
    END
  END i[365]
  PIN i[366]
    DIRECTION INPUT ;
    USE SIGNAL ;
    PORT
      LAYER M4 ;
        RECT  0 37.104 0.084 37.128 ;
    END
  END i[366]
  PIN i[367]
    DIRECTION INPUT ;
    USE SIGNAL ;
    PORT
      LAYER M4 ;
        RECT  0 37.2 0.084 37.224 ;
    END
  END i[367]
  PIN i[368]
    DIRECTION INPUT ;
    USE SIGNAL ;
    PORT
      LAYER M4 ;
        RECT  0 37.344 0.084 37.368 ;
    END
  END i[368]
  PIN i[369]
    DIRECTION INPUT ;
    USE SIGNAL ;
    PORT
      LAYER M4 ;
        RECT  0 37.44 0.084 37.464 ;
    END
  END i[369]
  PIN i[36]
    DIRECTION INPUT ;
    USE SIGNAL ;
    PORT
      LAYER M4 ;
        RECT  0 4.224 0.084 4.248 ;
    END
  END i[36]
  PIN i[370]
    DIRECTION INPUT ;
    USE SIGNAL ;
    PORT
      LAYER M4 ;
        RECT  0 37.536 0.084 37.56 ;
    END
  END i[370]
  PIN i[371]
    DIRECTION INPUT ;
    USE SIGNAL ;
    PORT
      LAYER M4 ;
        RECT  0 37.632 0.084 37.656 ;
    END
  END i[371]
  PIN i[372]
    DIRECTION INPUT ;
    USE SIGNAL ;
    PORT
      LAYER M4 ;
        RECT  0 37.728 0.084 37.752 ;
    END
  END i[372]
  PIN i[373]
    DIRECTION INPUT ;
    USE SIGNAL ;
    PORT
      LAYER M4 ;
        RECT  0 37.824 0.084 37.848 ;
    END
  END i[373]
  PIN i[374]
    DIRECTION INPUT ;
    USE SIGNAL ;
    PORT
      LAYER M4 ;
        RECT  0 37.92 0.084 37.944 ;
    END
  END i[374]
  PIN i[375]
    DIRECTION INPUT ;
    USE SIGNAL ;
    PORT
      LAYER M4 ;
        RECT  0 38.016 0.084 38.04 ;
    END
  END i[375]
  PIN i[376]
    DIRECTION INPUT ;
    USE SIGNAL ;
    PORT
      LAYER M4 ;
        RECT  0 38.112 0.084 38.136 ;
    END
  END i[376]
  PIN i[377]
    DIRECTION INPUT ;
    USE SIGNAL ;
    PORT
      LAYER M4 ;
        RECT  0 38.208 0.084 38.232 ;
    END
  END i[377]
  PIN i[378]
    DIRECTION INPUT ;
    USE SIGNAL ;
    PORT
      LAYER M4 ;
        RECT  0 38.304 0.084 38.328 ;
    END
  END i[378]
  PIN i[379]
    DIRECTION INPUT ;
    USE SIGNAL ;
    PORT
      LAYER M4 ;
        RECT  0 38.4 0.084 38.424 ;
    END
  END i[379]
  PIN i[37]
    DIRECTION INPUT ;
    USE SIGNAL ;
    PORT
      LAYER M4 ;
        RECT  0 4.32 0.084 4.344 ;
    END
  END i[37]
  PIN i[380]
    DIRECTION INPUT ;
    USE SIGNAL ;
    PORT
      LAYER M4 ;
        RECT  0 38.496 0.084 38.52 ;
    END
  END i[380]
  PIN i[381]
    DIRECTION INPUT ;
    USE SIGNAL ;
    PORT
      LAYER M4 ;
        RECT  0 38.64 0.084 38.664 ;
    END
  END i[381]
  PIN i[382]
    DIRECTION INPUT ;
    USE SIGNAL ;
    PORT
      LAYER M4 ;
        RECT  0 38.736 0.084 38.76 ;
    END
  END i[382]
  PIN i[383]
    DIRECTION INPUT ;
    USE SIGNAL ;
    PORT
      LAYER M4 ;
        RECT  0 38.832 0.084 38.856 ;
    END
  END i[383]
  PIN i[384]
    DIRECTION INPUT ;
    USE SIGNAL ;
    PORT
      LAYER M4 ;
        RECT  0 38.928 0.084 38.952 ;
    END
  END i[384]
  PIN i[385]
    DIRECTION INPUT ;
    USE SIGNAL ;
    PORT
      LAYER M4 ;
        RECT  0 39.024 0.084 39.048 ;
    END
  END i[385]
  PIN i[386]
    DIRECTION INPUT ;
    USE SIGNAL ;
    PORT
      LAYER M4 ;
        RECT  0 39.12 0.084 39.144 ;
    END
  END i[386]
  PIN i[387]
    DIRECTION INPUT ;
    USE SIGNAL ;
    PORT
      LAYER M4 ;
        RECT  0 39.216 0.084 39.24 ;
    END
  END i[387]
  PIN i[388]
    DIRECTION INPUT ;
    USE SIGNAL ;
    PORT
      LAYER M4 ;
        RECT  0 39.312 0.084 39.336 ;
    END
  END i[388]
  PIN i[389]
    DIRECTION INPUT ;
    USE SIGNAL ;
    PORT
      LAYER M4 ;
        RECT  0 39.408 0.084 39.432 ;
    END
  END i[389]
  PIN i[38]
    DIRECTION INPUT ;
    USE SIGNAL ;
    PORT
      LAYER M4 ;
        RECT  0 4.416 0.084 4.44 ;
    END
  END i[38]
  PIN i[390]
    DIRECTION INPUT ;
    USE SIGNAL ;
    PORT
      LAYER M4 ;
        RECT  0 39.504 0.084 39.528 ;
    END
  END i[390]
  PIN i[391]
    DIRECTION INPUT ;
    USE SIGNAL ;
    PORT
      LAYER M4 ;
        RECT  0 39.6 0.084 39.624 ;
    END
  END i[391]
  PIN i[392]
    DIRECTION INPUT ;
    USE SIGNAL ;
    PORT
      LAYER M4 ;
        RECT  0 39.696 0.084 39.72 ;
    END
  END i[392]
  PIN i[393]
    DIRECTION INPUT ;
    USE SIGNAL ;
    PORT
      LAYER M4 ;
        RECT  0 39.792 0.084 39.816 ;
    END
  END i[393]
  PIN i[394]
    DIRECTION INPUT ;
    USE SIGNAL ;
    PORT
      LAYER M4 ;
        RECT  0 39.936 0.084 39.96 ;
    END
  END i[394]
  PIN i[395]
    DIRECTION INPUT ;
    USE SIGNAL ;
    PORT
      LAYER M4 ;
        RECT  0 40.032 0.084 40.056 ;
    END
  END i[395]
  PIN i[396]
    DIRECTION INPUT ;
    USE SIGNAL ;
    PORT
      LAYER M4 ;
        RECT  0 40.128 0.084 40.152 ;
    END
  END i[396]
  PIN i[397]
    DIRECTION INPUT ;
    USE SIGNAL ;
    PORT
      LAYER M4 ;
        RECT  0 40.224 0.084 40.248 ;
    END
  END i[397]
  PIN i[398]
    DIRECTION INPUT ;
    USE SIGNAL ;
    PORT
      LAYER M4 ;
        RECT  0 40.32 0.084 40.344 ;
    END
  END i[398]
  PIN i[399]
    DIRECTION INPUT ;
    USE SIGNAL ;
    PORT
      LAYER M4 ;
        RECT  0 40.416 0.084 40.44 ;
    END
  END i[399]
  PIN i[39]
    DIRECTION INPUT ;
    USE SIGNAL ;
    PORT
      LAYER M4 ;
        RECT  0 4.512 0.084 4.536 ;
    END
  END i[39]
  PIN i[3]
    DIRECTION INPUT ;
    USE SIGNAL ;
    PORT
      LAYER M4 ;
        RECT  0 0.96 0.084 0.984 ;
    END
  END i[3]
  PIN i[400]
    DIRECTION INPUT ;
    USE SIGNAL ;
    PORT
      LAYER M4 ;
        RECT  0 40.512 0.084 40.536 ;
    END
  END i[400]
  PIN i[401]
    DIRECTION INPUT ;
    USE SIGNAL ;
    PORT
      LAYER M4 ;
        RECT  0 40.608 0.084 40.632 ;
    END
  END i[401]
  PIN i[402]
    DIRECTION INPUT ;
    USE SIGNAL ;
    PORT
      LAYER M4 ;
        RECT  0 40.704 0.084 40.728 ;
    END
  END i[402]
  PIN i[403]
    DIRECTION INPUT ;
    USE SIGNAL ;
    PORT
      LAYER M4 ;
        RECT  0 40.8 0.084 40.824 ;
    END
  END i[403]
  PIN i[404]
    DIRECTION INPUT ;
    USE SIGNAL ;
    PORT
      LAYER M4 ;
        RECT  0 40.896 0.084 40.92 ;
    END
  END i[404]
  PIN i[405]
    DIRECTION INPUT ;
    USE SIGNAL ;
    PORT
      LAYER M4 ;
        RECT  0 40.992 0.084 41.016 ;
    END
  END i[405]
  PIN i[406]
    DIRECTION INPUT ;
    USE SIGNAL ;
    PORT
      LAYER M4 ;
        RECT  0 41.088 0.084 41.112 ;
    END
  END i[406]
  PIN i[407]
    DIRECTION INPUT ;
    USE SIGNAL ;
    PORT
      LAYER M4 ;
        RECT  0 41.184 0.084 41.208 ;
    END
  END i[407]
  PIN i[408]
    DIRECTION INPUT ;
    USE SIGNAL ;
    PORT
      LAYER M4 ;
        RECT  0 41.328 0.084 41.352 ;
    END
  END i[408]
  PIN i[409]
    DIRECTION INPUT ;
    USE SIGNAL ;
    PORT
      LAYER M4 ;
        RECT  0 41.424 0.084 41.448 ;
    END
  END i[409]
  PIN i[40]
    DIRECTION INPUT ;
    USE SIGNAL ;
    PORT
      LAYER M4 ;
        RECT  0 4.608 0.084 4.632 ;
    END
  END i[40]
  PIN i[410]
    DIRECTION INPUT ;
    USE SIGNAL ;
    PORT
      LAYER M4 ;
        RECT  0 41.52 0.084 41.544 ;
    END
  END i[410]
  PIN i[411]
    DIRECTION INPUT ;
    USE SIGNAL ;
    PORT
      LAYER M4 ;
        RECT  0 41.616 0.084 41.64 ;
    END
  END i[411]
  PIN i[412]
    DIRECTION INPUT ;
    USE SIGNAL ;
    PORT
      LAYER M4 ;
        RECT  0 41.712 0.084 41.736 ;
    END
  END i[412]
  PIN i[413]
    DIRECTION INPUT ;
    USE SIGNAL ;
    PORT
      LAYER M4 ;
        RECT  0 41.808 0.084 41.832 ;
    END
  END i[413]
  PIN i[414]
    DIRECTION INPUT ;
    USE SIGNAL ;
    PORT
      LAYER M4 ;
        RECT  0 41.904 0.084 41.928 ;
    END
  END i[414]
  PIN i[415]
    DIRECTION INPUT ;
    USE SIGNAL ;
    PORT
      LAYER M4 ;
        RECT  0 42 0.084 42.024 ;
    END
  END i[415]
  PIN i[416]
    DIRECTION INPUT ;
    USE SIGNAL ;
    PORT
      LAYER M4 ;
        RECT  0 42.096 0.084 42.12 ;
    END
  END i[416]
  PIN i[417]
    DIRECTION INPUT ;
    USE SIGNAL ;
    PORT
      LAYER M4 ;
        RECT  0 42.192 0.084 42.216 ;
    END
  END i[417]
  PIN i[418]
    DIRECTION INPUT ;
    USE SIGNAL ;
    PORT
      LAYER M4 ;
        RECT  0 42.288 0.084 42.312 ;
    END
  END i[418]
  PIN i[419]
    DIRECTION INPUT ;
    USE SIGNAL ;
    PORT
      LAYER M4 ;
        RECT  0 42.384 0.084 42.408 ;
    END
  END i[419]
  PIN i[41]
    DIRECTION INPUT ;
    USE SIGNAL ;
    PORT
      LAYER M4 ;
        RECT  0 4.704 0.084 4.728 ;
    END
  END i[41]
  PIN i[420]
    DIRECTION INPUT ;
    USE SIGNAL ;
    PORT
      LAYER M4 ;
        RECT  0 42.48 0.084 42.504 ;
    END
  END i[420]
  PIN i[421]
    DIRECTION INPUT ;
    USE SIGNAL ;
    PORT
      LAYER M4 ;
        RECT  0 42.624 0.084 42.648 ;
    END
  END i[421]
  PIN i[422]
    DIRECTION INPUT ;
    USE SIGNAL ;
    PORT
      LAYER M4 ;
        RECT  0 42.72 0.084 42.744 ;
    END
  END i[422]
  PIN i[423]
    DIRECTION INPUT ;
    USE SIGNAL ;
    PORT
      LAYER M4 ;
        RECT  0 42.816 0.084 42.84 ;
    END
  END i[423]
  PIN i[424]
    DIRECTION INPUT ;
    USE SIGNAL ;
    PORT
      LAYER M4 ;
        RECT  0 42.912 0.084 42.936 ;
    END
  END i[424]
  PIN i[425]
    DIRECTION INPUT ;
    USE SIGNAL ;
    PORT
      LAYER M4 ;
        RECT  0 43.008 0.084 43.032 ;
    END
  END i[425]
  PIN i[426]
    DIRECTION INPUT ;
    USE SIGNAL ;
    PORT
      LAYER M4 ;
        RECT  0 43.104 0.084 43.128 ;
    END
  END i[426]
  PIN i[427]
    DIRECTION INPUT ;
    USE SIGNAL ;
    PORT
      LAYER M4 ;
        RECT  0 43.2 0.084 43.224 ;
    END
  END i[427]
  PIN i[428]
    DIRECTION INPUT ;
    USE SIGNAL ;
    PORT
      LAYER M4 ;
        RECT  0 43.296 0.084 43.32 ;
    END
  END i[428]
  PIN i[429]
    DIRECTION INPUT ;
    USE SIGNAL ;
    PORT
      LAYER M4 ;
        RECT  0 43.392 0.084 43.416 ;
    END
  END i[429]
  PIN i[42]
    DIRECTION INPUT ;
    USE SIGNAL ;
    PORT
      LAYER M4 ;
        RECT  0 4.848 0.084 4.872 ;
    END
  END i[42]
  PIN i[430]
    DIRECTION INPUT ;
    USE SIGNAL ;
    PORT
      LAYER M4 ;
        RECT  0 43.488 0.084 43.512 ;
    END
  END i[430]
  PIN i[431]
    DIRECTION INPUT ;
    USE SIGNAL ;
    PORT
      LAYER M4 ;
        RECT  0 43.584 0.084 43.608 ;
    END
  END i[431]
  PIN i[432]
    DIRECTION INPUT ;
    USE SIGNAL ;
    PORT
      LAYER M4 ;
        RECT  0 43.68 0.084 43.704 ;
    END
  END i[432]
  PIN i[433]
    DIRECTION INPUT ;
    USE SIGNAL ;
    PORT
      LAYER M4 ;
        RECT  0 43.776 0.084 43.8 ;
    END
  END i[433]
  PIN i[434]
    DIRECTION INPUT ;
    USE SIGNAL ;
    PORT
      LAYER M4 ;
        RECT  0 43.92 0.084 43.944 ;
    END
  END i[434]
  PIN i[435]
    DIRECTION INPUT ;
    USE SIGNAL ;
    PORT
      LAYER M4 ;
        RECT  0 44.016 0.084 44.04 ;
    END
  END i[435]
  PIN i[436]
    DIRECTION INPUT ;
    USE SIGNAL ;
    PORT
      LAYER M4 ;
        RECT  0 44.112 0.084 44.136 ;
    END
  END i[436]
  PIN i[437]
    DIRECTION INPUT ;
    USE SIGNAL ;
    PORT
      LAYER M4 ;
        RECT  0 44.208 0.084 44.232 ;
    END
  END i[437]
  PIN i[438]
    DIRECTION INPUT ;
    USE SIGNAL ;
    PORT
      LAYER M4 ;
        RECT  0 44.304 0.084 44.328 ;
    END
  END i[438]
  PIN i[439]
    DIRECTION INPUT ;
    USE SIGNAL ;
    PORT
      LAYER M4 ;
        RECT  0 44.4 0.084 44.424 ;
    END
  END i[439]
  PIN i[43]
    DIRECTION INPUT ;
    USE SIGNAL ;
    PORT
      LAYER M4 ;
        RECT  0 4.944 0.084 4.968 ;
    END
  END i[43]
  PIN i[440]
    DIRECTION INPUT ;
    USE SIGNAL ;
    PORT
      LAYER M4 ;
        RECT  0 44.496 0.084 44.52 ;
    END
  END i[440]
  PIN i[441]
    DIRECTION INPUT ;
    USE SIGNAL ;
    PORT
      LAYER M4 ;
        RECT  0 44.592 0.084 44.616 ;
    END
  END i[441]
  PIN i[442]
    DIRECTION INPUT ;
    USE SIGNAL ;
    PORT
      LAYER M4 ;
        RECT  0 44.688 0.084 44.712 ;
    END
  END i[442]
  PIN i[443]
    DIRECTION INPUT ;
    USE SIGNAL ;
    PORT
      LAYER M4 ;
        RECT  0 44.784 0.084 44.808 ;
    END
  END i[443]
  PIN i[444]
    DIRECTION INPUT ;
    USE SIGNAL ;
    PORT
      LAYER M4 ;
        RECT  0 44.88 0.084 44.904 ;
    END
  END i[444]
  PIN i[445]
    DIRECTION INPUT ;
    USE SIGNAL ;
    PORT
      LAYER M4 ;
        RECT  0 44.976 0.084 45 ;
    END
  END i[445]
  PIN i[446]
    DIRECTION INPUT ;
    USE SIGNAL ;
    PORT
      LAYER M4 ;
        RECT  0 45.072 0.084 45.096 ;
    END
  END i[446]
  PIN i[447]
    DIRECTION INPUT ;
    USE SIGNAL ;
    PORT
      LAYER M4 ;
        RECT  0 45.216 0.084 45.24 ;
    END
  END i[447]
  PIN i[448]
    DIRECTION INPUT ;
    USE SIGNAL ;
    PORT
      LAYER M4 ;
        RECT  0 45.312 0.084 45.336 ;
    END
  END i[448]
  PIN i[449]
    DIRECTION INPUT ;
    USE SIGNAL ;
    PORT
      LAYER M4 ;
        RECT  0 45.408 0.084 45.432 ;
    END
  END i[449]
  PIN i[44]
    DIRECTION INPUT ;
    USE SIGNAL ;
    PORT
      LAYER M4 ;
        RECT  0 5.04 0.084 5.064 ;
    END
  END i[44]
  PIN i[450]
    DIRECTION INPUT ;
    USE SIGNAL ;
    PORT
      LAYER M4 ;
        RECT  0 45.504 0.084 45.528 ;
    END
  END i[450]
  PIN i[451]
    DIRECTION INPUT ;
    USE SIGNAL ;
    PORT
      LAYER M4 ;
        RECT  0 45.6 0.084 45.624 ;
    END
  END i[451]
  PIN i[452]
    DIRECTION INPUT ;
    USE SIGNAL ;
    PORT
      LAYER M4 ;
        RECT  0 45.696 0.084 45.72 ;
    END
  END i[452]
  PIN i[453]
    DIRECTION INPUT ;
    USE SIGNAL ;
    PORT
      LAYER M4 ;
        RECT  0 45.792 0.084 45.816 ;
    END
  END i[453]
  PIN i[454]
    DIRECTION INPUT ;
    USE SIGNAL ;
    PORT
      LAYER M4 ;
        RECT  0 45.888 0.084 45.912 ;
    END
  END i[454]
  PIN i[455]
    DIRECTION INPUT ;
    USE SIGNAL ;
    PORT
      LAYER M4 ;
        RECT  0 45.984 0.084 46.008 ;
    END
  END i[455]
  PIN i[456]
    DIRECTION INPUT ;
    USE SIGNAL ;
    PORT
      LAYER M4 ;
        RECT  0 46.08 0.084 46.104 ;
    END
  END i[456]
  PIN i[457]
    DIRECTION INPUT ;
    USE SIGNAL ;
    PORT
      LAYER M4 ;
        RECT  0 46.176 0.084 46.2 ;
    END
  END i[457]
  PIN i[458]
    DIRECTION INPUT ;
    USE SIGNAL ;
    PORT
      LAYER M4 ;
        RECT  0 46.272 0.084 46.296 ;
    END
  END i[458]
  PIN i[459]
    DIRECTION INPUT ;
    USE SIGNAL ;
    PORT
      LAYER M4 ;
        RECT  0 46.368 0.084 46.392 ;
    END
  END i[459]
  PIN i[45]
    DIRECTION INPUT ;
    USE SIGNAL ;
    PORT
      LAYER M4 ;
        RECT  0 5.136 0.084 5.16 ;
    END
  END i[45]
  PIN i[460]
    DIRECTION INPUT ;
    USE SIGNAL ;
    PORT
      LAYER M4 ;
        RECT  0 46.512 0.084 46.536 ;
    END
  END i[460]
  PIN i[461]
    DIRECTION INPUT ;
    USE SIGNAL ;
    PORT
      LAYER M4 ;
        RECT  0 46.608 0.084 46.632 ;
    END
  END i[461]
  PIN i[462]
    DIRECTION INPUT ;
    USE SIGNAL ;
    PORT
      LAYER M4 ;
        RECT  0 46.704 0.084 46.728 ;
    END
  END i[462]
  PIN i[463]
    DIRECTION INPUT ;
    USE SIGNAL ;
    PORT
      LAYER M4 ;
        RECT  0 46.8 0.084 46.824 ;
    END
  END i[463]
  PIN i[464]
    DIRECTION INPUT ;
    USE SIGNAL ;
    PORT
      LAYER M4 ;
        RECT  0 46.896 0.084 46.92 ;
    END
  END i[464]
  PIN i[465]
    DIRECTION INPUT ;
    USE SIGNAL ;
    PORT
      LAYER M4 ;
        RECT  0 46.992 0.084 47.016 ;
    END
  END i[465]
  PIN i[466]
    DIRECTION INPUT ;
    USE SIGNAL ;
    PORT
      LAYER M4 ;
        RECT  0 47.088 0.084 47.112 ;
    END
  END i[466]
  PIN i[467]
    DIRECTION INPUT ;
    USE SIGNAL ;
    PORT
      LAYER M4 ;
        RECT  0 47.184 0.084 47.208 ;
    END
  END i[467]
  PIN i[468]
    DIRECTION INPUT ;
    USE SIGNAL ;
    PORT
      LAYER M4 ;
        RECT  0 47.28 0.084 47.304 ;
    END
  END i[468]
  PIN i[469]
    DIRECTION INPUT ;
    USE SIGNAL ;
    PORT
      LAYER M4 ;
        RECT  0 47.376 0.084 47.4 ;
    END
  END i[469]
  PIN i[46]
    DIRECTION INPUT ;
    USE SIGNAL ;
    PORT
      LAYER M4 ;
        RECT  0 5.232 0.084 5.256 ;
    END
  END i[46]
  PIN i[470]
    DIRECTION INPUT ;
    USE SIGNAL ;
    PORT
      LAYER M4 ;
        RECT  0 47.472 0.084 47.496 ;
    END
  END i[470]
  PIN i[471]
    DIRECTION INPUT ;
    USE SIGNAL ;
    PORT
      LAYER M4 ;
        RECT  0 47.568 0.084 47.592 ;
    END
  END i[471]
  PIN i[472]
    DIRECTION INPUT ;
    USE SIGNAL ;
    PORT
      LAYER M4 ;
        RECT  0 47.664 0.084 47.688 ;
    END
  END i[472]
  PIN i[473]
    DIRECTION INPUT ;
    USE SIGNAL ;
    PORT
      LAYER M4 ;
        RECT  0 47.808 0.084 47.832 ;
    END
  END i[473]
  PIN i[474]
    DIRECTION INPUT ;
    USE SIGNAL ;
    PORT
      LAYER M4 ;
        RECT  0 47.904 0.084 47.928 ;
    END
  END i[474]
  PIN i[475]
    DIRECTION INPUT ;
    USE SIGNAL ;
    PORT
      LAYER M4 ;
        RECT  0 48 0.084 48.024 ;
    END
  END i[475]
  PIN i[476]
    DIRECTION INPUT ;
    USE SIGNAL ;
    PORT
      LAYER M4 ;
        RECT  0 48.096 0.084 48.12 ;
    END
  END i[476]
  PIN i[477]
    DIRECTION INPUT ;
    USE SIGNAL ;
    PORT
      LAYER M4 ;
        RECT  0 48.192 0.084 48.216 ;
    END
  END i[477]
  PIN i[478]
    DIRECTION INPUT ;
    USE SIGNAL ;
    PORT
      LAYER M4 ;
        RECT  0 48.288 0.084 48.312 ;
    END
  END i[478]
  PIN i[479]
    DIRECTION INPUT ;
    USE SIGNAL ;
    PORT
      LAYER M4 ;
        RECT  0 48.384 0.084 48.408 ;
    END
  END i[479]
  PIN i[47]
    DIRECTION INPUT ;
    USE SIGNAL ;
    PORT
      LAYER M4 ;
        RECT  0 5.328 0.084 5.352 ;
    END
  END i[47]
  PIN i[480]
    DIRECTION INPUT ;
    USE SIGNAL ;
    PORT
      LAYER M4 ;
        RECT  0 48.48 0.084 48.504 ;
    END
  END i[480]
  PIN i[481]
    DIRECTION INPUT ;
    USE SIGNAL ;
    PORT
      LAYER M4 ;
        RECT  0 48.576 0.084 48.6 ;
    END
  END i[481]
  PIN i[482]
    DIRECTION INPUT ;
    USE SIGNAL ;
    PORT
      LAYER M4 ;
        RECT  0 48.672 0.084 48.696 ;
    END
  END i[482]
  PIN i[483]
    DIRECTION INPUT ;
    USE SIGNAL ;
    PORT
      LAYER M4 ;
        RECT  0 48.768 0.084 48.792 ;
    END
  END i[483]
  PIN i[484]
    DIRECTION INPUT ;
    USE SIGNAL ;
    PORT
      LAYER M4 ;
        RECT  0 48.864 0.084 48.888 ;
    END
  END i[484]
  PIN i[485]
    DIRECTION INPUT ;
    USE SIGNAL ;
    PORT
      LAYER M4 ;
        RECT  0 48.96 0.084 48.984 ;
    END
  END i[485]
  PIN i[486]
    DIRECTION INPUT ;
    USE SIGNAL ;
    PORT
      LAYER M4 ;
        RECT  0 49.104 0.084 49.128 ;
    END
  END i[486]
  PIN i[487]
    DIRECTION INPUT ;
    USE SIGNAL ;
    PORT
      LAYER M4 ;
        RECT  0 49.2 0.084 49.224 ;
    END
  END i[487]
  PIN i[488]
    DIRECTION INPUT ;
    USE SIGNAL ;
    PORT
      LAYER M4 ;
        RECT  0 49.296 0.084 49.32 ;
    END
  END i[488]
  PIN i[489]
    DIRECTION INPUT ;
    USE SIGNAL ;
    PORT
      LAYER M4 ;
        RECT  0 49.392 0.084 49.416 ;
    END
  END i[489]
  PIN i[48]
    DIRECTION INPUT ;
    USE SIGNAL ;
    PORT
      LAYER M4 ;
        RECT  0 5.424 0.084 5.448 ;
    END
  END i[48]
  PIN i[490]
    DIRECTION INPUT ;
    USE SIGNAL ;
    PORT
      LAYER M4 ;
        RECT  0 49.488 0.084 49.512 ;
    END
  END i[490]
  PIN i[491]
    DIRECTION INPUT ;
    USE SIGNAL ;
    PORT
      LAYER M4 ;
        RECT  0 49.584 0.084 49.608 ;
    END
  END i[491]
  PIN i[492]
    DIRECTION INPUT ;
    USE SIGNAL ;
    PORT
      LAYER M4 ;
        RECT  0 49.68 0.084 49.704 ;
    END
  END i[492]
  PIN i[493]
    DIRECTION INPUT ;
    USE SIGNAL ;
    PORT
      LAYER M4 ;
        RECT  0 49.776 0.084 49.8 ;
    END
  END i[493]
  PIN i[494]
    DIRECTION INPUT ;
    USE SIGNAL ;
    PORT
      LAYER M4 ;
        RECT  0 49.872 0.084 49.896 ;
    END
  END i[494]
  PIN i[495]
    DIRECTION INPUT ;
    USE SIGNAL ;
    PORT
      LAYER M4 ;
        RECT  0 49.968 0.084 49.992 ;
    END
  END i[495]
  PIN i[496]
    DIRECTION INPUT ;
    USE SIGNAL ;
    PORT
      LAYER M4 ;
        RECT  0 50.064 0.084 50.088 ;
    END
  END i[496]
  PIN i[497]
    DIRECTION INPUT ;
    USE SIGNAL ;
    PORT
      LAYER M4 ;
        RECT  0 50.16 0.084 50.184 ;
    END
  END i[497]
  PIN i[498]
    DIRECTION INPUT ;
    USE SIGNAL ;
    PORT
      LAYER M4 ;
        RECT  0 50.256 0.084 50.28 ;
    END
  END i[498]
  PIN i[499]
    DIRECTION INPUT ;
    USE SIGNAL ;
    PORT
      LAYER M4 ;
        RECT  0 50.4 0.084 50.424 ;
    END
  END i[499]
  PIN i[49]
    DIRECTION INPUT ;
    USE SIGNAL ;
    PORT
      LAYER M4 ;
        RECT  0 5.52 0.084 5.544 ;
    END
  END i[49]
  PIN i[4]
    DIRECTION INPUT ;
    USE SIGNAL ;
    PORT
      LAYER M4 ;
        RECT  0 1.056 0.084 1.08 ;
    END
  END i[4]
  PIN i[500]
    DIRECTION INPUT ;
    USE SIGNAL ;
    PORT
      LAYER M4 ;
        RECT  0 50.496 0.084 50.52 ;
    END
  END i[500]
  PIN i[501]
    DIRECTION INPUT ;
    USE SIGNAL ;
    PORT
      LAYER M4 ;
        RECT  0 50.592 0.084 50.616 ;
    END
  END i[501]
  PIN i[502]
    DIRECTION INPUT ;
    USE SIGNAL ;
    PORT
      LAYER M4 ;
        RECT  0 50.688 0.084 50.712 ;
    END
  END i[502]
  PIN i[503]
    DIRECTION INPUT ;
    USE SIGNAL ;
    PORT
      LAYER M4 ;
        RECT  0 50.784 0.084 50.808 ;
    END
  END i[503]
  PIN i[504]
    DIRECTION INPUT ;
    USE SIGNAL ;
    PORT
      LAYER M4 ;
        RECT  0 50.88 0.084 50.904 ;
    END
  END i[504]
  PIN i[505]
    DIRECTION INPUT ;
    USE SIGNAL ;
    PORT
      LAYER M4 ;
        RECT  0 50.976 0.084 51 ;
    END
  END i[505]
  PIN i[506]
    DIRECTION INPUT ;
    USE SIGNAL ;
    PORT
      LAYER M4 ;
        RECT  0 51.072 0.084 51.096 ;
    END
  END i[506]
  PIN i[507]
    DIRECTION INPUT ;
    USE SIGNAL ;
    PORT
      LAYER M4 ;
        RECT  0 51.168 0.084 51.192 ;
    END
  END i[507]
  PIN i[508]
    DIRECTION INPUT ;
    USE SIGNAL ;
    PORT
      LAYER M4 ;
        RECT  0 51.264 0.084 51.288 ;
    END
  END i[508]
  PIN i[509]
    DIRECTION INPUT ;
    USE SIGNAL ;
    PORT
      LAYER M4 ;
        RECT  0 51.36 0.084 51.384 ;
    END
  END i[509]
  PIN i[50]
    DIRECTION INPUT ;
    USE SIGNAL ;
    PORT
      LAYER M4 ;
        RECT  0 5.616 0.084 5.64 ;
    END
  END i[50]
  PIN i[510]
    DIRECTION INPUT ;
    USE SIGNAL ;
    PORT
      LAYER M4 ;
        RECT  0 51.456 0.084 51.48 ;
    END
  END i[510]
  PIN i[511]
    DIRECTION INPUT ;
    USE SIGNAL ;
    PORT
      LAYER M4 ;
        RECT  0 51.552 0.084 51.576 ;
    END
  END i[511]
  PIN i[512]
    DIRECTION INPUT ;
    USE SIGNAL ;
    PORT
      LAYER M4 ;
        RECT  0 51.696 0.084 51.72 ;
    END
  END i[512]
  PIN i[513]
    DIRECTION INPUT ;
    USE SIGNAL ;
    PORT
      LAYER M4 ;
        RECT  0 51.792 0.084 51.816 ;
    END
  END i[513]
  PIN i[514]
    DIRECTION INPUT ;
    USE SIGNAL ;
    PORT
      LAYER M4 ;
        RECT  0 51.888 0.084 51.912 ;
    END
  END i[514]
  PIN i[515]
    DIRECTION INPUT ;
    USE SIGNAL ;
    PORT
      LAYER M4 ;
        RECT  0 51.984 0.084 52.008 ;
    END
  END i[515]
  PIN i[516]
    DIRECTION INPUT ;
    USE SIGNAL ;
    PORT
      LAYER M4 ;
        RECT  0 52.08 0.084 52.104 ;
    END
  END i[516]
  PIN i[517]
    DIRECTION INPUT ;
    USE SIGNAL ;
    PORT
      LAYER M4 ;
        RECT  0 52.176 0.084 52.2 ;
    END
  END i[517]
  PIN i[518]
    DIRECTION INPUT ;
    USE SIGNAL ;
    PORT
      LAYER M4 ;
        RECT  0 52.272 0.084 52.296 ;
    END
  END i[518]
  PIN i[519]
    DIRECTION INPUT ;
    USE SIGNAL ;
    PORT
      LAYER M4 ;
        RECT  0 52.368 0.084 52.392 ;
    END
  END i[519]
  PIN i[51]
    DIRECTION INPUT ;
    USE SIGNAL ;
    PORT
      LAYER M4 ;
        RECT  0 5.712 0.084 5.736 ;
    END
  END i[51]
  PIN i[520]
    DIRECTION INPUT ;
    USE SIGNAL ;
    PORT
      LAYER M4 ;
        RECT  0 52.464 0.084 52.488 ;
    END
  END i[520]
  PIN i[521]
    DIRECTION INPUT ;
    USE SIGNAL ;
    PORT
      LAYER M4 ;
        RECT  0 52.56 0.084 52.584 ;
    END
  END i[521]
  PIN i[522]
    DIRECTION INPUT ;
    USE SIGNAL ;
    PORT
      LAYER M4 ;
        RECT  0 52.656 0.084 52.68 ;
    END
  END i[522]
  PIN i[523]
    DIRECTION INPUT ;
    USE SIGNAL ;
    PORT
      LAYER M4 ;
        RECT  0 52.752 0.084 52.776 ;
    END
  END i[523]
  PIN i[524]
    DIRECTION INPUT ;
    USE SIGNAL ;
    PORT
      LAYER M4 ;
        RECT  0 52.848 0.084 52.872 ;
    END
  END i[524]
  PIN i[525]
    DIRECTION INPUT ;
    USE SIGNAL ;
    PORT
      LAYER M4 ;
        RECT  0 52.992 0.084 53.016 ;
    END
  END i[525]
  PIN i[526]
    DIRECTION INPUT ;
    USE SIGNAL ;
    PORT
      LAYER M4 ;
        RECT  0 53.088 0.084 53.112 ;
    END
  END i[526]
  PIN i[527]
    DIRECTION INPUT ;
    USE SIGNAL ;
    PORT
      LAYER M4 ;
        RECT  0 53.184 0.084 53.208 ;
    END
  END i[527]
  PIN i[528]
    DIRECTION INPUT ;
    USE SIGNAL ;
    PORT
      LAYER M4 ;
        RECT  0 53.28 0.084 53.304 ;
    END
  END i[528]
  PIN i[529]
    DIRECTION INPUT ;
    USE SIGNAL ;
    PORT
      LAYER M4 ;
        RECT  0 53.376 0.084 53.4 ;
    END
  END i[529]
  PIN i[52]
    DIRECTION INPUT ;
    USE SIGNAL ;
    PORT
      LAYER M4 ;
        RECT  0 5.808 0.084 5.832 ;
    END
  END i[52]
  PIN i[530]
    DIRECTION INPUT ;
    USE SIGNAL ;
    PORT
      LAYER M4 ;
        RECT  0 53.472 0.084 53.496 ;
    END
  END i[530]
  PIN i[531]
    DIRECTION INPUT ;
    USE SIGNAL ;
    PORT
      LAYER M4 ;
        RECT  0 53.568 0.084 53.592 ;
    END
  END i[531]
  PIN i[532]
    DIRECTION INPUT ;
    USE SIGNAL ;
    PORT
      LAYER M4 ;
        RECT  0 53.664 0.084 53.688 ;
    END
  END i[532]
  PIN i[533]
    DIRECTION INPUT ;
    USE SIGNAL ;
    PORT
      LAYER M4 ;
        RECT  0 53.76 0.084 53.784 ;
    END
  END i[533]
  PIN i[534]
    DIRECTION INPUT ;
    USE SIGNAL ;
    PORT
      LAYER M4 ;
        RECT  0 53.856 0.084 53.88 ;
    END
  END i[534]
  PIN i[535]
    DIRECTION INPUT ;
    USE SIGNAL ;
    PORT
      LAYER M4 ;
        RECT  0 53.952 0.084 53.976 ;
    END
  END i[535]
  PIN i[536]
    DIRECTION INPUT ;
    USE SIGNAL ;
    PORT
      LAYER M4 ;
        RECT  0 54.048 0.084 54.072 ;
    END
  END i[536]
  PIN i[537]
    DIRECTION INPUT ;
    USE SIGNAL ;
    PORT
      LAYER M4 ;
        RECT  0 54.144 0.084 54.168 ;
    END
  END i[537]
  PIN i[538]
    DIRECTION INPUT ;
    USE SIGNAL ;
    PORT
      LAYER M4 ;
        RECT  0 54.288 0.084 54.312 ;
    END
  END i[538]
  PIN i[539]
    DIRECTION INPUT ;
    USE SIGNAL ;
    PORT
      LAYER M4 ;
        RECT  0 54.384 0.084 54.408 ;
    END
  END i[539]
  PIN i[53]
    DIRECTION INPUT ;
    USE SIGNAL ;
    PORT
      LAYER M4 ;
        RECT  0 5.904 0.084 5.928 ;
    END
  END i[53]
  PIN i[540]
    DIRECTION INPUT ;
    USE SIGNAL ;
    PORT
      LAYER M4 ;
        RECT  0 54.48 0.084 54.504 ;
    END
  END i[540]
  PIN i[541]
    DIRECTION INPUT ;
    USE SIGNAL ;
    PORT
      LAYER M4 ;
        RECT  0 54.576 0.084 54.6 ;
    END
  END i[541]
  PIN i[542]
    DIRECTION INPUT ;
    USE SIGNAL ;
    PORT
      LAYER M4 ;
        RECT  0 54.672 0.084 54.696 ;
    END
  END i[542]
  PIN i[543]
    DIRECTION INPUT ;
    USE SIGNAL ;
    PORT
      LAYER M4 ;
        RECT  0 54.768 0.084 54.792 ;
    END
  END i[543]
  PIN i[544]
    DIRECTION INPUT ;
    USE SIGNAL ;
    PORT
      LAYER M4 ;
        RECT  0 54.864 0.084 54.888 ;
    END
  END i[544]
  PIN i[545]
    DIRECTION INPUT ;
    USE SIGNAL ;
    PORT
      LAYER M4 ;
        RECT  0 54.96 0.084 54.984 ;
    END
  END i[545]
  PIN i[546]
    DIRECTION INPUT ;
    USE SIGNAL ;
    PORT
      LAYER M4 ;
        RECT  0 55.056 0.084 55.08 ;
    END
  END i[546]
  PIN i[547]
    DIRECTION INPUT ;
    USE SIGNAL ;
    PORT
      LAYER M4 ;
        RECT  0 55.152 0.084 55.176 ;
    END
  END i[547]
  PIN i[548]
    DIRECTION INPUT ;
    USE SIGNAL ;
    PORT
      LAYER M4 ;
        RECT  0 55.248 0.084 55.272 ;
    END
  END i[548]
  PIN i[549]
    DIRECTION INPUT ;
    USE SIGNAL ;
    PORT
      LAYER M4 ;
        RECT  0 55.344 0.084 55.368 ;
    END
  END i[549]
  PIN i[54]
    DIRECTION INPUT ;
    USE SIGNAL ;
    PORT
      LAYER M4 ;
        RECT  0 6 0.084 6.024 ;
    END
  END i[54]
  PIN i[550]
    DIRECTION INPUT ;
    USE SIGNAL ;
    PORT
      LAYER M4 ;
        RECT  0 55.44 0.084 55.464 ;
    END
  END i[550]
  PIN i[551]
    DIRECTION INPUT ;
    USE SIGNAL ;
    PORT
      LAYER M4 ;
        RECT  0 55.584 0.084 55.608 ;
    END
  END i[551]
  PIN i[552]
    DIRECTION INPUT ;
    USE SIGNAL ;
    PORT
      LAYER M4 ;
        RECT  0 55.68 0.084 55.704 ;
    END
  END i[552]
  PIN i[553]
    DIRECTION INPUT ;
    USE SIGNAL ;
    PORT
      LAYER M4 ;
        RECT  0 55.776 0.084 55.8 ;
    END
  END i[553]
  PIN i[554]
    DIRECTION INPUT ;
    USE SIGNAL ;
    PORT
      LAYER M4 ;
        RECT  0 55.872 0.084 55.896 ;
    END
  END i[554]
  PIN i[555]
    DIRECTION INPUT ;
    USE SIGNAL ;
    PORT
      LAYER M4 ;
        RECT  0 55.968 0.084 55.992 ;
    END
  END i[555]
  PIN i[556]
    DIRECTION INPUT ;
    USE SIGNAL ;
    PORT
      LAYER M4 ;
        RECT  0 56.064 0.084 56.088 ;
    END
  END i[556]
  PIN i[557]
    DIRECTION INPUT ;
    USE SIGNAL ;
    PORT
      LAYER M4 ;
        RECT  0 56.16 0.084 56.184 ;
    END
  END i[557]
  PIN i[558]
    DIRECTION INPUT ;
    USE SIGNAL ;
    PORT
      LAYER M4 ;
        RECT  0 56.256 0.084 56.28 ;
    END
  END i[558]
  PIN i[559]
    DIRECTION INPUT ;
    USE SIGNAL ;
    PORT
      LAYER M4 ;
        RECT  0 56.352 0.084 56.376 ;
    END
  END i[559]
  PIN i[55]
    DIRECTION INPUT ;
    USE SIGNAL ;
    PORT
      LAYER M4 ;
        RECT  0 6.144 0.084 6.168 ;
    END
  END i[55]
  PIN i[560]
    DIRECTION INPUT ;
    USE SIGNAL ;
    PORT
      LAYER M4 ;
        RECT  0 56.448 0.084 56.472 ;
    END
  END i[560]
  PIN i[561]
    DIRECTION INPUT ;
    USE SIGNAL ;
    PORT
      LAYER M4 ;
        RECT  0 56.544 0.084 56.568 ;
    END
  END i[561]
  PIN i[562]
    DIRECTION INPUT ;
    USE SIGNAL ;
    PORT
      LAYER M4 ;
        RECT  0 56.64 0.084 56.664 ;
    END
  END i[562]
  PIN i[563]
    DIRECTION INPUT ;
    USE SIGNAL ;
    PORT
      LAYER M4 ;
        RECT  0 56.736 0.084 56.76 ;
    END
  END i[563]
  PIN i[564]
    DIRECTION INPUT ;
    USE SIGNAL ;
    PORT
      LAYER M4 ;
        RECT  0 56.88 0.084 56.904 ;
    END
  END i[564]
  PIN i[565]
    DIRECTION INPUT ;
    USE SIGNAL ;
    PORT
      LAYER M4 ;
        RECT  0 56.976 0.084 57 ;
    END
  END i[565]
  PIN i[566]
    DIRECTION INPUT ;
    USE SIGNAL ;
    PORT
      LAYER M4 ;
        RECT  0 57.072 0.084 57.096 ;
    END
  END i[566]
  PIN i[567]
    DIRECTION INPUT ;
    USE SIGNAL ;
    PORT
      LAYER M4 ;
        RECT  0 57.168 0.084 57.192 ;
    END
  END i[567]
  PIN i[568]
    DIRECTION INPUT ;
    USE SIGNAL ;
    PORT
      LAYER M4 ;
        RECT  0 57.264 0.084 57.288 ;
    END
  END i[568]
  PIN i[569]
    DIRECTION INPUT ;
    USE SIGNAL ;
    PORT
      LAYER M4 ;
        RECT  0 57.36 0.084 57.384 ;
    END
  END i[569]
  PIN i[56]
    DIRECTION INPUT ;
    USE SIGNAL ;
    PORT
      LAYER M4 ;
        RECT  0 6.24 0.084 6.264 ;
    END
  END i[56]
  PIN i[570]
    DIRECTION INPUT ;
    USE SIGNAL ;
    PORT
      LAYER M4 ;
        RECT  0 57.456 0.084 57.48 ;
    END
  END i[570]
  PIN i[571]
    DIRECTION INPUT ;
    USE SIGNAL ;
    PORT
      LAYER M4 ;
        RECT  0 57.552 0.084 57.576 ;
    END
  END i[571]
  PIN i[572]
    DIRECTION INPUT ;
    USE SIGNAL ;
    PORT
      LAYER M4 ;
        RECT  0 57.648 0.084 57.672 ;
    END
  END i[572]
  PIN i[573]
    DIRECTION INPUT ;
    USE SIGNAL ;
    PORT
      LAYER M4 ;
        RECT  0 57.744 0.084 57.768 ;
    END
  END i[573]
  PIN i[574]
    DIRECTION INPUT ;
    USE SIGNAL ;
    PORT
      LAYER M4 ;
        RECT  0 57.84 0.084 57.864 ;
    END
  END i[574]
  PIN i[575]
    DIRECTION INPUT ;
    USE SIGNAL ;
    PORT
      LAYER M4 ;
        RECT  0 57.936 0.084 57.96 ;
    END
  END i[575]
  PIN i[576]
    DIRECTION INPUT ;
    USE SIGNAL ;
    PORT
      LAYER M4 ;
        RECT  0 58.032 0.084 58.056 ;
    END
  END i[576]
  PIN i[577]
    DIRECTION INPUT ;
    USE SIGNAL ;
    PORT
      LAYER M4 ;
        RECT  0 58.176 0.084 58.2 ;
    END
  END i[577]
  PIN i[578]
    DIRECTION INPUT ;
    USE SIGNAL ;
    PORT
      LAYER M4 ;
        RECT  0 58.272 0.084 58.296 ;
    END
  END i[578]
  PIN i[579]
    DIRECTION INPUT ;
    USE SIGNAL ;
    PORT
      LAYER M4 ;
        RECT  0 58.368 0.084 58.392 ;
    END
  END i[579]
  PIN i[57]
    DIRECTION INPUT ;
    USE SIGNAL ;
    PORT
      LAYER M4 ;
        RECT  0 6.336 0.084 6.36 ;
    END
  END i[57]
  PIN i[580]
    DIRECTION INPUT ;
    USE SIGNAL ;
    PORT
      LAYER M4 ;
        RECT  0 58.464 0.084 58.488 ;
    END
  END i[580]
  PIN i[581]
    DIRECTION INPUT ;
    USE SIGNAL ;
    PORT
      LAYER M4 ;
        RECT  0 58.56 0.084 58.584 ;
    END
  END i[581]
  PIN i[582]
    DIRECTION INPUT ;
    USE SIGNAL ;
    PORT
      LAYER M4 ;
        RECT  0 58.656 0.084 58.68 ;
    END
  END i[582]
  PIN i[583]
    DIRECTION INPUT ;
    USE SIGNAL ;
    PORT
      LAYER M4 ;
        RECT  0 58.752 0.084 58.776 ;
    END
  END i[583]
  PIN i[584]
    DIRECTION INPUT ;
    USE SIGNAL ;
    PORT
      LAYER M4 ;
        RECT  0 58.848 0.084 58.872 ;
    END
  END i[584]
  PIN i[585]
    DIRECTION INPUT ;
    USE SIGNAL ;
    PORT
      LAYER M4 ;
        RECT  0 58.944 0.084 58.968 ;
    END
  END i[585]
  PIN i[586]
    DIRECTION INPUT ;
    USE SIGNAL ;
    PORT
      LAYER M4 ;
        RECT  0 59.04 0.084 59.064 ;
    END
  END i[586]
  PIN i[587]
    DIRECTION INPUT ;
    USE SIGNAL ;
    PORT
      LAYER M4 ;
        RECT  0 59.136 0.084 59.16 ;
    END
  END i[587]
  PIN i[588]
    DIRECTION INPUT ;
    USE SIGNAL ;
    PORT
      LAYER M4 ;
        RECT  0 59.232 0.084 59.256 ;
    END
  END i[588]
  PIN i[589]
    DIRECTION INPUT ;
    USE SIGNAL ;
    PORT
      LAYER M4 ;
        RECT  0 59.328 0.084 59.352 ;
    END
  END i[589]
  PIN i[58]
    DIRECTION INPUT ;
    USE SIGNAL ;
    PORT
      LAYER M4 ;
        RECT  0 6.432 0.084 6.456 ;
    END
  END i[58]
  PIN i[590]
    DIRECTION INPUT ;
    USE SIGNAL ;
    PORT
      LAYER M4 ;
        RECT  0 59.472 0.084 59.496 ;
    END
  END i[590]
  PIN i[591]
    DIRECTION INPUT ;
    USE SIGNAL ;
    PORT
      LAYER M4 ;
        RECT  0 59.568 0.084 59.592 ;
    END
  END i[591]
  PIN i[592]
    DIRECTION INPUT ;
    USE SIGNAL ;
    PORT
      LAYER M4 ;
        RECT  0 59.664 0.084 59.688 ;
    END
  END i[592]
  PIN i[593]
    DIRECTION INPUT ;
    USE SIGNAL ;
    PORT
      LAYER M4 ;
        RECT  0 59.76 0.084 59.784 ;
    END
  END i[593]
  PIN i[594]
    DIRECTION INPUT ;
    USE SIGNAL ;
    PORT
      LAYER M4 ;
        RECT  0 59.856 0.084 59.88 ;
    END
  END i[594]
  PIN i[595]
    DIRECTION INPUT ;
    USE SIGNAL ;
    PORT
      LAYER M4 ;
        RECT  0 59.952 0.084 59.976 ;
    END
  END i[595]
  PIN i[596]
    DIRECTION INPUT ;
    USE SIGNAL ;
    PORT
      LAYER M4 ;
        RECT  0 60.048 0.084 60.072 ;
    END
  END i[596]
  PIN i[597]
    DIRECTION INPUT ;
    USE SIGNAL ;
    PORT
      LAYER M4 ;
        RECT  0 60.144 0.084 60.168 ;
    END
  END i[597]
  PIN i[598]
    DIRECTION INPUT ;
    USE SIGNAL ;
    PORT
      LAYER M4 ;
        RECT  0 60.24 0.084 60.264 ;
    END
  END i[598]
  PIN i[599]
    DIRECTION INPUT ;
    USE SIGNAL ;
    PORT
      LAYER M4 ;
        RECT  0 60.336 0.084 60.36 ;
    END
  END i[599]
  PIN i[59]
    DIRECTION INPUT ;
    USE SIGNAL ;
    PORT
      LAYER M4 ;
        RECT  0 6.528 0.084 6.552 ;
    END
  END i[59]
  PIN i[5]
    DIRECTION INPUT ;
    USE SIGNAL ;
    PORT
      LAYER M4 ;
        RECT  0 1.152 0.084 1.176 ;
    END
  END i[5]
  PIN i[600]
    DIRECTION INPUT ;
    USE SIGNAL ;
    PORT
      LAYER M4 ;
        RECT  0 60.432 0.084 60.456 ;
    END
  END i[600]
  PIN i[601]
    DIRECTION INPUT ;
    USE SIGNAL ;
    PORT
      LAYER M4 ;
        RECT  0 60.528 0.084 60.552 ;
    END
  END i[601]
  PIN i[602]
    DIRECTION INPUT ;
    USE SIGNAL ;
    PORT
      LAYER M4 ;
        RECT  0 60.624 0.084 60.648 ;
    END
  END i[602]
  PIN i[603]
    DIRECTION INPUT ;
    USE SIGNAL ;
    PORT
      LAYER M4 ;
        RECT  0 60.768 0.084 60.792 ;
    END
  END i[603]
  PIN i[604]
    DIRECTION INPUT ;
    USE SIGNAL ;
    PORT
      LAYER M4 ;
        RECT  0 60.864 0.084 60.888 ;
    END
  END i[604]
  PIN i[605]
    DIRECTION INPUT ;
    USE SIGNAL ;
    PORT
      LAYER M4 ;
        RECT  0 60.96 0.084 60.984 ;
    END
  END i[605]
  PIN i[606]
    DIRECTION INPUT ;
    USE SIGNAL ;
    PORT
      LAYER M4 ;
        RECT  0 61.056 0.084 61.08 ;
    END
  END i[606]
  PIN i[607]
    DIRECTION INPUT ;
    USE SIGNAL ;
    PORT
      LAYER M4 ;
        RECT  0 61.152 0.084 61.176 ;
    END
  END i[607]
  PIN i[608]
    DIRECTION INPUT ;
    USE SIGNAL ;
    PORT
      LAYER M4 ;
        RECT  0 61.248 0.084 61.272 ;
    END
  END i[608]
  PIN i[609]
    DIRECTION INPUT ;
    USE SIGNAL ;
    PORT
      LAYER M4 ;
        RECT  0 61.344 0.084 61.368 ;
    END
  END i[609]
  PIN i[60]
    DIRECTION INPUT ;
    USE SIGNAL ;
    PORT
      LAYER M4 ;
        RECT  0 6.624 0.084 6.648 ;
    END
  END i[60]
  PIN i[610]
    DIRECTION INPUT ;
    USE SIGNAL ;
    PORT
      LAYER M4 ;
        RECT  0 61.44 0.084 61.464 ;
    END
  END i[610]
  PIN i[611]
    DIRECTION INPUT ;
    USE SIGNAL ;
    PORT
      LAYER M4 ;
        RECT  0 61.536 0.084 61.56 ;
    END
  END i[611]
  PIN i[612]
    DIRECTION INPUT ;
    USE SIGNAL ;
    PORT
      LAYER M4 ;
        RECT  0 61.632 0.084 61.656 ;
    END
  END i[612]
  PIN i[613]
    DIRECTION INPUT ;
    USE SIGNAL ;
    PORT
      LAYER M4 ;
        RECT  0 61.728 0.084 61.752 ;
    END
  END i[613]
  PIN i[614]
    DIRECTION INPUT ;
    USE SIGNAL ;
    PORT
      LAYER M4 ;
        RECT  0 61.824 0.084 61.848 ;
    END
  END i[614]
  PIN i[615]
    DIRECTION INPUT ;
    USE SIGNAL ;
    PORT
      LAYER M4 ;
        RECT  0 61.92 0.084 61.944 ;
    END
  END i[615]
  PIN i[616]
    DIRECTION INPUT ;
    USE SIGNAL ;
    PORT
      LAYER M4 ;
        RECT  0 62.064 0.084 62.088 ;
    END
  END i[616]
  PIN i[617]
    DIRECTION INPUT ;
    USE SIGNAL ;
    PORT
      LAYER M4 ;
        RECT  0 62.16 0.084 62.184 ;
    END
  END i[617]
  PIN i[618]
    DIRECTION INPUT ;
    USE SIGNAL ;
    PORT
      LAYER M4 ;
        RECT  0 62.256 0.084 62.28 ;
    END
  END i[618]
  PIN i[619]
    DIRECTION INPUT ;
    USE SIGNAL ;
    PORT
      LAYER M4 ;
        RECT  0 62.352 0.084 62.376 ;
    END
  END i[619]
  PIN i[61]
    DIRECTION INPUT ;
    USE SIGNAL ;
    PORT
      LAYER M4 ;
        RECT  0 6.72 0.084 6.744 ;
    END
  END i[61]
  PIN i[620]
    DIRECTION INPUT ;
    USE SIGNAL ;
    PORT
      LAYER M4 ;
        RECT  0 62.448 0.084 62.472 ;
    END
  END i[620]
  PIN i[621]
    DIRECTION INPUT ;
    USE SIGNAL ;
    PORT
      LAYER M4 ;
        RECT  0 62.544 0.084 62.568 ;
    END
  END i[621]
  PIN i[622]
    DIRECTION INPUT ;
    USE SIGNAL ;
    PORT
      LAYER M4 ;
        RECT  0 62.64 0.084 62.664 ;
    END
  END i[622]
  PIN i[623]
    DIRECTION INPUT ;
    USE SIGNAL ;
    PORT
      LAYER M4 ;
        RECT  0 62.736 0.084 62.76 ;
    END
  END i[623]
  PIN i[62]
    DIRECTION INPUT ;
    USE SIGNAL ;
    PORT
      LAYER M4 ;
        RECT  0 6.816 0.084 6.84 ;
    END
  END i[62]
  PIN i[63]
    DIRECTION INPUT ;
    USE SIGNAL ;
    PORT
      LAYER M4 ;
        RECT  0 6.912 0.084 6.936 ;
    END
  END i[63]
  PIN i[64]
    DIRECTION INPUT ;
    USE SIGNAL ;
    PORT
      LAYER M4 ;
        RECT  0 7.008 0.084 7.032 ;
    END
  END i[64]
  PIN i[65]
    DIRECTION INPUT ;
    USE SIGNAL ;
    PORT
      LAYER M4 ;
        RECT  0 7.104 0.084 7.128 ;
    END
  END i[65]
  PIN i[66]
    DIRECTION INPUT ;
    USE SIGNAL ;
    PORT
      LAYER M4 ;
        RECT  0 7.2 0.084 7.224 ;
    END
  END i[66]
  PIN i[67]
    DIRECTION INPUT ;
    USE SIGNAL ;
    PORT
      LAYER M4 ;
        RECT  0 7.296 0.084 7.32 ;
    END
  END i[67]
  PIN i[68]
    DIRECTION INPUT ;
    USE SIGNAL ;
    PORT
      LAYER M4 ;
        RECT  0 7.44 0.084 7.464 ;
    END
  END i[68]
  PIN i[69]
    DIRECTION INPUT ;
    USE SIGNAL ;
    PORT
      LAYER M4 ;
        RECT  0 7.536 0.084 7.56 ;
    END
  END i[69]
  PIN i[6]
    DIRECTION INPUT ;
    USE SIGNAL ;
    PORT
      LAYER M4 ;
        RECT  0 1.248 0.084 1.272 ;
    END
  END i[6]
  PIN i[70]
    DIRECTION INPUT ;
    USE SIGNAL ;
    PORT
      LAYER M4 ;
        RECT  0 7.632 0.084 7.656 ;
    END
  END i[70]
  PIN i[71]
    DIRECTION INPUT ;
    USE SIGNAL ;
    PORT
      LAYER M4 ;
        RECT  0 7.728 0.084 7.752 ;
    END
  END i[71]
  PIN i[72]
    DIRECTION INPUT ;
    USE SIGNAL ;
    PORT
      LAYER M4 ;
        RECT  0 7.824 0.084 7.848 ;
    END
  END i[72]
  PIN i[73]
    DIRECTION INPUT ;
    USE SIGNAL ;
    PORT
      LAYER M4 ;
        RECT  0 7.92 0.084 7.944 ;
    END
  END i[73]
  PIN i[74]
    DIRECTION INPUT ;
    USE SIGNAL ;
    PORT
      LAYER M4 ;
        RECT  0 8.016 0.084 8.04 ;
    END
  END i[74]
  PIN i[75]
    DIRECTION INPUT ;
    USE SIGNAL ;
    PORT
      LAYER M4 ;
        RECT  0 8.112 0.084 8.136 ;
    END
  END i[75]
  PIN i[76]
    DIRECTION INPUT ;
    USE SIGNAL ;
    PORT
      LAYER M4 ;
        RECT  0 8.208 0.084 8.232 ;
    END
  END i[76]
  PIN i[77]
    DIRECTION INPUT ;
    USE SIGNAL ;
    PORT
      LAYER M4 ;
        RECT  0 8.304 0.084 8.328 ;
    END
  END i[77]
  PIN i[78]
    DIRECTION INPUT ;
    USE SIGNAL ;
    PORT
      LAYER M4 ;
        RECT  0 8.4 0.084 8.424 ;
    END
  END i[78]
  PIN i[79]
    DIRECTION INPUT ;
    USE SIGNAL ;
    PORT
      LAYER M4 ;
        RECT  0 8.496 0.084 8.52 ;
    END
  END i[79]
  PIN i[7]
    DIRECTION INPUT ;
    USE SIGNAL ;
    PORT
      LAYER M4 ;
        RECT  0 1.344 0.084 1.368 ;
    END
  END i[7]
  PIN i[80]
    DIRECTION INPUT ;
    USE SIGNAL ;
    PORT
      LAYER M4 ;
        RECT  0 8.592 0.084 8.616 ;
    END
  END i[80]
  PIN i[81]
    DIRECTION INPUT ;
    USE SIGNAL ;
    PORT
      LAYER M4 ;
        RECT  0 8.736 0.084 8.76 ;
    END
  END i[81]
  PIN i[82]
    DIRECTION INPUT ;
    USE SIGNAL ;
    PORT
      LAYER M4 ;
        RECT  0 8.832 0.084 8.856 ;
    END
  END i[82]
  PIN i[83]
    DIRECTION INPUT ;
    USE SIGNAL ;
    PORT
      LAYER M4 ;
        RECT  0 8.928 0.084 8.952 ;
    END
  END i[83]
  PIN i[84]
    DIRECTION INPUT ;
    USE SIGNAL ;
    PORT
      LAYER M4 ;
        RECT  0 9.024 0.084 9.048 ;
    END
  END i[84]
  PIN i[85]
    DIRECTION INPUT ;
    USE SIGNAL ;
    PORT
      LAYER M4 ;
        RECT  0 9.12 0.084 9.144 ;
    END
  END i[85]
  PIN i[86]
    DIRECTION INPUT ;
    USE SIGNAL ;
    PORT
      LAYER M4 ;
        RECT  0 9.216 0.084 9.24 ;
    END
  END i[86]
  PIN i[87]
    DIRECTION INPUT ;
    USE SIGNAL ;
    PORT
      LAYER M4 ;
        RECT  0 9.312 0.084 9.336 ;
    END
  END i[87]
  PIN i[88]
    DIRECTION INPUT ;
    USE SIGNAL ;
    PORT
      LAYER M4 ;
        RECT  0 9.408 0.084 9.432 ;
    END
  END i[88]
  PIN i[89]
    DIRECTION INPUT ;
    USE SIGNAL ;
    PORT
      LAYER M4 ;
        RECT  0 9.504 0.084 9.528 ;
    END
  END i[89]
  PIN i[8]
    DIRECTION INPUT ;
    USE SIGNAL ;
    PORT
      LAYER M4 ;
        RECT  0 1.44 0.084 1.464 ;
    END
  END i[8]
  PIN i[90]
    DIRECTION INPUT ;
    USE SIGNAL ;
    PORT
      LAYER M4 ;
        RECT  0 9.6 0.084 9.624 ;
    END
  END i[90]
  PIN i[91]
    DIRECTION INPUT ;
    USE SIGNAL ;
    PORT
      LAYER M4 ;
        RECT  0 9.696 0.084 9.72 ;
    END
  END i[91]
  PIN i[92]
    DIRECTION INPUT ;
    USE SIGNAL ;
    PORT
      LAYER M4 ;
        RECT  0 9.792 0.084 9.816 ;
    END
  END i[92]
  PIN i[93]
    DIRECTION INPUT ;
    USE SIGNAL ;
    PORT
      LAYER M4 ;
        RECT  0 9.888 0.084 9.912 ;
    END
  END i[93]
  PIN i[94]
    DIRECTION INPUT ;
    USE SIGNAL ;
    PORT
      LAYER M4 ;
        RECT  0 10.032 0.084 10.056 ;
    END
  END i[94]
  PIN i[95]
    DIRECTION INPUT ;
    USE SIGNAL ;
    PORT
      LAYER M4 ;
        RECT  0 10.128 0.084 10.152 ;
    END
  END i[95]
  PIN i[96]
    DIRECTION INPUT ;
    USE SIGNAL ;
    PORT
      LAYER M4 ;
        RECT  0 10.224 0.084 10.248 ;
    END
  END i[96]
  PIN i[97]
    DIRECTION INPUT ;
    USE SIGNAL ;
    PORT
      LAYER M4 ;
        RECT  0 10.32 0.084 10.344 ;
    END
  END i[97]
  PIN i[98]
    DIRECTION INPUT ;
    USE SIGNAL ;
    PORT
      LAYER M4 ;
        RECT  0 10.416 0.084 10.44 ;
    END
  END i[98]
  PIN i[99]
    DIRECTION INPUT ;
    USE SIGNAL ;
    PORT
      LAYER M4 ;
        RECT  0 10.512 0.084 10.536 ;
    END
  END i[99]
  PIN i[9]
    DIRECTION INPUT ;
    USE SIGNAL ;
    PORT
      LAYER M4 ;
        RECT  0 1.536 0.084 1.56 ;
    END
  END i[9]
  PIN o[0]
    DIRECTION OUTPUT ;
    USE SIGNAL ;
    PORT
      LAYER M4 ;
        RECT  21.516 0.624 21.6 0.648 ;
    END
  END o[0]
  PIN o[100]
    DIRECTION OUTPUT ;
    USE SIGNAL ;
    PORT
      LAYER M4 ;
        RECT  21.516 10.608 21.6 10.632 ;
    END
  END o[100]
  PIN o[101]
    DIRECTION OUTPUT ;
    USE SIGNAL ;
    PORT
      LAYER M4 ;
        RECT  21.516 10.704 21.6 10.728 ;
    END
  END o[101]
  PIN o[102]
    DIRECTION OUTPUT ;
    USE SIGNAL ;
    PORT
      LAYER M4 ;
        RECT  21.516 10.8 21.6 10.824 ;
    END
  END o[102]
  PIN o[103]
    DIRECTION OUTPUT ;
    USE SIGNAL ;
    PORT
      LAYER M4 ;
        RECT  21.516 10.896 21.6 10.92 ;
    END
  END o[103]
  PIN o[104]
    DIRECTION OUTPUT ;
    USE SIGNAL ;
    PORT
      LAYER M4 ;
        RECT  21.516 10.992 21.6 11.016 ;
    END
  END o[104]
  PIN o[105]
    DIRECTION OUTPUT ;
    USE SIGNAL ;
    PORT
      LAYER M4 ;
        RECT  21.516 11.088 21.6 11.112 ;
    END
  END o[105]
  PIN o[106]
    DIRECTION OUTPUT ;
    USE SIGNAL ;
    PORT
      LAYER M4 ;
        RECT  21.516 11.184 21.6 11.208 ;
    END
  END o[106]
  PIN o[107]
    DIRECTION OUTPUT ;
    USE SIGNAL ;
    PORT
      LAYER M4 ;
        RECT  21.516 11.328 21.6 11.352 ;
    END
  END o[107]
  PIN o[108]
    DIRECTION OUTPUT ;
    USE SIGNAL ;
    PORT
      LAYER M4 ;
        RECT  21.516 11.424 21.6 11.448 ;
    END
  END o[108]
  PIN o[109]
    DIRECTION OUTPUT ;
    USE SIGNAL ;
    PORT
      LAYER M4 ;
        RECT  21.516 11.52 21.6 11.544 ;
    END
  END o[109]
  PIN o[10]
    DIRECTION OUTPUT ;
    USE SIGNAL ;
    PORT
      LAYER M4 ;
        RECT  21.516 1.632 21.6 1.656 ;
    END
  END o[10]
  PIN o[110]
    DIRECTION OUTPUT ;
    USE SIGNAL ;
    PORT
      LAYER M4 ;
        RECT  21.516 11.616 21.6 11.64 ;
    END
  END o[110]
  PIN o[111]
    DIRECTION OUTPUT ;
    USE SIGNAL ;
    PORT
      LAYER M4 ;
        RECT  21.516 11.712 21.6 11.736 ;
    END
  END o[111]
  PIN o[112]
    DIRECTION OUTPUT ;
    USE SIGNAL ;
    PORT
      LAYER M4 ;
        RECT  21.516 11.808 21.6 11.832 ;
    END
  END o[112]
  PIN o[113]
    DIRECTION OUTPUT ;
    USE SIGNAL ;
    PORT
      LAYER M4 ;
        RECT  21.516 11.904 21.6 11.928 ;
    END
  END o[113]
  PIN o[114]
    DIRECTION OUTPUT ;
    USE SIGNAL ;
    PORT
      LAYER M4 ;
        RECT  21.516 12 21.6 12.024 ;
    END
  END o[114]
  PIN o[115]
    DIRECTION OUTPUT ;
    USE SIGNAL ;
    PORT
      LAYER M4 ;
        RECT  21.516 12.096 21.6 12.12 ;
    END
  END o[115]
  PIN o[116]
    DIRECTION OUTPUT ;
    USE SIGNAL ;
    PORT
      LAYER M4 ;
        RECT  21.516 12.192 21.6 12.216 ;
    END
  END o[116]
  PIN o[117]
    DIRECTION OUTPUT ;
    USE SIGNAL ;
    PORT
      LAYER M4 ;
        RECT  21.516 12.288 21.6 12.312 ;
    END
  END o[117]
  PIN o[118]
    DIRECTION OUTPUT ;
    USE SIGNAL ;
    PORT
      LAYER M4 ;
        RECT  21.516 12.384 21.6 12.408 ;
    END
  END o[118]
  PIN o[119]
    DIRECTION OUTPUT ;
    USE SIGNAL ;
    PORT
      LAYER M4 ;
        RECT  21.516 12.48 21.6 12.504 ;
    END
  END o[119]
  PIN o[11]
    DIRECTION OUTPUT ;
    USE SIGNAL ;
    PORT
      LAYER M4 ;
        RECT  21.516 1.728 21.6 1.752 ;
    END
  END o[11]
  PIN o[120]
    DIRECTION OUTPUT ;
    USE SIGNAL ;
    PORT
      LAYER M4 ;
        RECT  21.516 12.576 21.6 12.6 ;
    END
  END o[120]
  PIN o[121]
    DIRECTION OUTPUT ;
    USE SIGNAL ;
    PORT
      LAYER M4 ;
        RECT  21.516 12.72 21.6 12.744 ;
    END
  END o[121]
  PIN o[122]
    DIRECTION OUTPUT ;
    USE SIGNAL ;
    PORT
      LAYER M4 ;
        RECT  21.516 12.816 21.6 12.84 ;
    END
  END o[122]
  PIN o[123]
    DIRECTION OUTPUT ;
    USE SIGNAL ;
    PORT
      LAYER M4 ;
        RECT  21.516 12.912 21.6 12.936 ;
    END
  END o[123]
  PIN o[124]
    DIRECTION OUTPUT ;
    USE SIGNAL ;
    PORT
      LAYER M4 ;
        RECT  21.516 13.008 21.6 13.032 ;
    END
  END o[124]
  PIN o[125]
    DIRECTION OUTPUT ;
    USE SIGNAL ;
    PORT
      LAYER M4 ;
        RECT  21.516 13.104 21.6 13.128 ;
    END
  END o[125]
  PIN o[126]
    DIRECTION OUTPUT ;
    USE SIGNAL ;
    PORT
      LAYER M4 ;
        RECT  21.516 13.2 21.6 13.224 ;
    END
  END o[126]
  PIN o[127]
    DIRECTION OUTPUT ;
    USE SIGNAL ;
    PORT
      LAYER M4 ;
        RECT  21.516 13.296 21.6 13.32 ;
    END
  END o[127]
  PIN o[128]
    DIRECTION OUTPUT ;
    USE SIGNAL ;
    PORT
      LAYER M4 ;
        RECT  21.516 13.392 21.6 13.416 ;
    END
  END o[128]
  PIN o[129]
    DIRECTION OUTPUT ;
    USE SIGNAL ;
    PORT
      LAYER M4 ;
        RECT  21.516 13.488 21.6 13.512 ;
    END
  END o[129]
  PIN o[12]
    DIRECTION OUTPUT ;
    USE SIGNAL ;
    PORT
      LAYER M4 ;
        RECT  21.516 1.824 21.6 1.848 ;
    END
  END o[12]
  PIN o[130]
    DIRECTION OUTPUT ;
    USE SIGNAL ;
    PORT
      LAYER M4 ;
        RECT  21.516 13.584 21.6 13.608 ;
    END
  END o[130]
  PIN o[131]
    DIRECTION OUTPUT ;
    USE SIGNAL ;
    PORT
      LAYER M4 ;
        RECT  21.516 13.68 21.6 13.704 ;
    END
  END o[131]
  PIN o[132]
    DIRECTION OUTPUT ;
    USE SIGNAL ;
    PORT
      LAYER M4 ;
        RECT  21.516 13.776 21.6 13.8 ;
    END
  END o[132]
  PIN o[133]
    DIRECTION OUTPUT ;
    USE SIGNAL ;
    PORT
      LAYER M4 ;
        RECT  21.516 13.872 21.6 13.896 ;
    END
  END o[133]
  PIN o[134]
    DIRECTION OUTPUT ;
    USE SIGNAL ;
    PORT
      LAYER M4 ;
        RECT  21.516 14.016 21.6 14.04 ;
    END
  END o[134]
  PIN o[135]
    DIRECTION OUTPUT ;
    USE SIGNAL ;
    PORT
      LAYER M4 ;
        RECT  21.516 14.112 21.6 14.136 ;
    END
  END o[135]
  PIN o[136]
    DIRECTION OUTPUT ;
    USE SIGNAL ;
    PORT
      LAYER M4 ;
        RECT  21.516 14.208 21.6 14.232 ;
    END
  END o[136]
  PIN o[137]
    DIRECTION OUTPUT ;
    USE SIGNAL ;
    PORT
      LAYER M4 ;
        RECT  21.516 14.304 21.6 14.328 ;
    END
  END o[137]
  PIN o[138]
    DIRECTION OUTPUT ;
    USE SIGNAL ;
    PORT
      LAYER M4 ;
        RECT  21.516 14.4 21.6 14.424 ;
    END
  END o[138]
  PIN o[139]
    DIRECTION OUTPUT ;
    USE SIGNAL ;
    PORT
      LAYER M4 ;
        RECT  21.516 14.496 21.6 14.52 ;
    END
  END o[139]
  PIN o[13]
    DIRECTION OUTPUT ;
    USE SIGNAL ;
    PORT
      LAYER M4 ;
        RECT  21.516 1.92 21.6 1.944 ;
    END
  END o[13]
  PIN o[140]
    DIRECTION OUTPUT ;
    USE SIGNAL ;
    PORT
      LAYER M4 ;
        RECT  21.516 14.592 21.6 14.616 ;
    END
  END o[140]
  PIN o[141]
    DIRECTION OUTPUT ;
    USE SIGNAL ;
    PORT
      LAYER M4 ;
        RECT  21.516 14.688 21.6 14.712 ;
    END
  END o[141]
  PIN o[142]
    DIRECTION OUTPUT ;
    USE SIGNAL ;
    PORT
      LAYER M4 ;
        RECT  21.516 14.784 21.6 14.808 ;
    END
  END o[142]
  PIN o[143]
    DIRECTION OUTPUT ;
    USE SIGNAL ;
    PORT
      LAYER M4 ;
        RECT  21.516 14.88 21.6 14.904 ;
    END
  END o[143]
  PIN o[144]
    DIRECTION OUTPUT ;
    USE SIGNAL ;
    PORT
      LAYER M4 ;
        RECT  21.516 14.976 21.6 15 ;
    END
  END o[144]
  PIN o[145]
    DIRECTION OUTPUT ;
    USE SIGNAL ;
    PORT
      LAYER M4 ;
        RECT  21.516 15.072 21.6 15.096 ;
    END
  END o[145]
  PIN o[146]
    DIRECTION OUTPUT ;
    USE SIGNAL ;
    PORT
      LAYER M4 ;
        RECT  21.516 15.168 21.6 15.192 ;
    END
  END o[146]
  PIN o[147]
    DIRECTION OUTPUT ;
    USE SIGNAL ;
    PORT
      LAYER M4 ;
        RECT  21.516 15.312 21.6 15.336 ;
    END
  END o[147]
  PIN o[148]
    DIRECTION OUTPUT ;
    USE SIGNAL ;
    PORT
      LAYER M4 ;
        RECT  21.516 15.408 21.6 15.432 ;
    END
  END o[148]
  PIN o[149]
    DIRECTION OUTPUT ;
    USE SIGNAL ;
    PORT
      LAYER M4 ;
        RECT  21.516 15.504 21.6 15.528 ;
    END
  END o[149]
  PIN o[14]
    DIRECTION OUTPUT ;
    USE SIGNAL ;
    PORT
      LAYER M4 ;
        RECT  21.516 2.016 21.6 2.04 ;
    END
  END o[14]
  PIN o[150]
    DIRECTION OUTPUT ;
    USE SIGNAL ;
    PORT
      LAYER M4 ;
        RECT  21.516 15.6 21.6 15.624 ;
    END
  END o[150]
  PIN o[151]
    DIRECTION OUTPUT ;
    USE SIGNAL ;
    PORT
      LAYER M4 ;
        RECT  21.516 15.696 21.6 15.72 ;
    END
  END o[151]
  PIN o[152]
    DIRECTION OUTPUT ;
    USE SIGNAL ;
    PORT
      LAYER M4 ;
        RECT  21.516 15.792 21.6 15.816 ;
    END
  END o[152]
  PIN o[153]
    DIRECTION OUTPUT ;
    USE SIGNAL ;
    PORT
      LAYER M4 ;
        RECT  21.516 15.888 21.6 15.912 ;
    END
  END o[153]
  PIN o[154]
    DIRECTION OUTPUT ;
    USE SIGNAL ;
    PORT
      LAYER M4 ;
        RECT  21.516 15.984 21.6 16.008 ;
    END
  END o[154]
  PIN o[155]
    DIRECTION OUTPUT ;
    USE SIGNAL ;
    PORT
      LAYER M4 ;
        RECT  21.516 16.08 21.6 16.104 ;
    END
  END o[155]
  PIN o[156]
    DIRECTION OUTPUT ;
    USE SIGNAL ;
    PORT
      LAYER M4 ;
        RECT  21.516 16.176 21.6 16.2 ;
    END
  END o[156]
  PIN o[157]
    DIRECTION OUTPUT ;
    USE SIGNAL ;
    PORT
      LAYER M4 ;
        RECT  21.516 16.272 21.6 16.296 ;
    END
  END o[157]
  PIN o[158]
    DIRECTION OUTPUT ;
    USE SIGNAL ;
    PORT
      LAYER M4 ;
        RECT  21.516 16.368 21.6 16.392 ;
    END
  END o[158]
  PIN o[159]
    DIRECTION OUTPUT ;
    USE SIGNAL ;
    PORT
      LAYER M4 ;
        RECT  21.516 16.464 21.6 16.488 ;
    END
  END o[159]
  PIN o[15]
    DIRECTION OUTPUT ;
    USE SIGNAL ;
    PORT
      LAYER M4 ;
        RECT  21.516 2.112 21.6 2.136 ;
    END
  END o[15]
  PIN o[160]
    DIRECTION OUTPUT ;
    USE SIGNAL ;
    PORT
      LAYER M4 ;
        RECT  21.516 16.608 21.6 16.632 ;
    END
  END o[160]
  PIN o[161]
    DIRECTION OUTPUT ;
    USE SIGNAL ;
    PORT
      LAYER M4 ;
        RECT  21.516 16.704 21.6 16.728 ;
    END
  END o[161]
  PIN o[162]
    DIRECTION OUTPUT ;
    USE SIGNAL ;
    PORT
      LAYER M4 ;
        RECT  21.516 16.8 21.6 16.824 ;
    END
  END o[162]
  PIN o[163]
    DIRECTION OUTPUT ;
    USE SIGNAL ;
    PORT
      LAYER M4 ;
        RECT  21.516 16.896 21.6 16.92 ;
    END
  END o[163]
  PIN o[164]
    DIRECTION OUTPUT ;
    USE SIGNAL ;
    PORT
      LAYER M4 ;
        RECT  21.516 16.992 21.6 17.016 ;
    END
  END o[164]
  PIN o[165]
    DIRECTION OUTPUT ;
    USE SIGNAL ;
    PORT
      LAYER M4 ;
        RECT  21.516 17.088 21.6 17.112 ;
    END
  END o[165]
  PIN o[166]
    DIRECTION OUTPUT ;
    USE SIGNAL ;
    PORT
      LAYER M4 ;
        RECT  21.516 17.184 21.6 17.208 ;
    END
  END o[166]
  PIN o[167]
    DIRECTION OUTPUT ;
    USE SIGNAL ;
    PORT
      LAYER M4 ;
        RECT  21.516 17.28 21.6 17.304 ;
    END
  END o[167]
  PIN o[168]
    DIRECTION OUTPUT ;
    USE SIGNAL ;
    PORT
      LAYER M4 ;
        RECT  21.516 17.376 21.6 17.4 ;
    END
  END o[168]
  PIN o[169]
    DIRECTION OUTPUT ;
    USE SIGNAL ;
    PORT
      LAYER M4 ;
        RECT  21.516 17.472 21.6 17.496 ;
    END
  END o[169]
  PIN o[16]
    DIRECTION OUTPUT ;
    USE SIGNAL ;
    PORT
      LAYER M4 ;
        RECT  21.516 2.256 21.6 2.28 ;
    END
  END o[16]
  PIN o[170]
    DIRECTION OUTPUT ;
    USE SIGNAL ;
    PORT
      LAYER M4 ;
        RECT  21.516 17.568 21.6 17.592 ;
    END
  END o[170]
  PIN o[171]
    DIRECTION OUTPUT ;
    USE SIGNAL ;
    PORT
      LAYER M4 ;
        RECT  21.516 17.664 21.6 17.688 ;
    END
  END o[171]
  PIN o[172]
    DIRECTION OUTPUT ;
    USE SIGNAL ;
    PORT
      LAYER M4 ;
        RECT  21.516 17.76 21.6 17.784 ;
    END
  END o[172]
  PIN o[173]
    DIRECTION OUTPUT ;
    USE SIGNAL ;
    PORT
      LAYER M4 ;
        RECT  21.516 17.904 21.6 17.928 ;
    END
  END o[173]
  PIN o[174]
    DIRECTION OUTPUT ;
    USE SIGNAL ;
    PORT
      LAYER M4 ;
        RECT  21.516 18 21.6 18.024 ;
    END
  END o[174]
  PIN o[175]
    DIRECTION OUTPUT ;
    USE SIGNAL ;
    PORT
      LAYER M4 ;
        RECT  21.516 18.096 21.6 18.12 ;
    END
  END o[175]
  PIN o[176]
    DIRECTION OUTPUT ;
    USE SIGNAL ;
    PORT
      LAYER M4 ;
        RECT  21.516 18.192 21.6 18.216 ;
    END
  END o[176]
  PIN o[177]
    DIRECTION OUTPUT ;
    USE SIGNAL ;
    PORT
      LAYER M4 ;
        RECT  21.516 18.288 21.6 18.312 ;
    END
  END o[177]
  PIN o[178]
    DIRECTION OUTPUT ;
    USE SIGNAL ;
    PORT
      LAYER M4 ;
        RECT  21.516 18.384 21.6 18.408 ;
    END
  END o[178]
  PIN o[179]
    DIRECTION OUTPUT ;
    USE SIGNAL ;
    PORT
      LAYER M4 ;
        RECT  21.516 18.48 21.6 18.504 ;
    END
  END o[179]
  PIN o[17]
    DIRECTION OUTPUT ;
    USE SIGNAL ;
    PORT
      LAYER M4 ;
        RECT  21.516 2.352 21.6 2.376 ;
    END
  END o[17]
  PIN o[180]
    DIRECTION OUTPUT ;
    USE SIGNAL ;
    PORT
      LAYER M4 ;
        RECT  21.516 18.576 21.6 18.6 ;
    END
  END o[180]
  PIN o[181]
    DIRECTION OUTPUT ;
    USE SIGNAL ;
    PORT
      LAYER M4 ;
        RECT  21.516 18.672 21.6 18.696 ;
    END
  END o[181]
  PIN o[182]
    DIRECTION OUTPUT ;
    USE SIGNAL ;
    PORT
      LAYER M4 ;
        RECT  21.516 18.768 21.6 18.792 ;
    END
  END o[182]
  PIN o[183]
    DIRECTION OUTPUT ;
    USE SIGNAL ;
    PORT
      LAYER M4 ;
        RECT  21.516 18.864 21.6 18.888 ;
    END
  END o[183]
  PIN o[184]
    DIRECTION OUTPUT ;
    USE SIGNAL ;
    PORT
      LAYER M4 ;
        RECT  21.516 18.96 21.6 18.984 ;
    END
  END o[184]
  PIN o[185]
    DIRECTION OUTPUT ;
    USE SIGNAL ;
    PORT
      LAYER M4 ;
        RECT  21.516 19.056 21.6 19.08 ;
    END
  END o[185]
  PIN o[186]
    DIRECTION OUTPUT ;
    USE SIGNAL ;
    PORT
      LAYER M4 ;
        RECT  21.516 19.2 21.6 19.224 ;
    END
  END o[186]
  PIN o[187]
    DIRECTION OUTPUT ;
    USE SIGNAL ;
    PORT
      LAYER M4 ;
        RECT  21.516 19.296 21.6 19.32 ;
    END
  END o[187]
  PIN o[188]
    DIRECTION OUTPUT ;
    USE SIGNAL ;
    PORT
      LAYER M4 ;
        RECT  21.516 19.392 21.6 19.416 ;
    END
  END o[188]
  PIN o[189]
    DIRECTION OUTPUT ;
    USE SIGNAL ;
    PORT
      LAYER M4 ;
        RECT  21.516 19.488 21.6 19.512 ;
    END
  END o[189]
  PIN o[18]
    DIRECTION OUTPUT ;
    USE SIGNAL ;
    PORT
      LAYER M4 ;
        RECT  21.516 2.448 21.6 2.472 ;
    END
  END o[18]
  PIN o[190]
    DIRECTION OUTPUT ;
    USE SIGNAL ;
    PORT
      LAYER M4 ;
        RECT  21.516 19.584 21.6 19.608 ;
    END
  END o[190]
  PIN o[191]
    DIRECTION OUTPUT ;
    USE SIGNAL ;
    PORT
      LAYER M4 ;
        RECT  21.516 19.68 21.6 19.704 ;
    END
  END o[191]
  PIN o[192]
    DIRECTION OUTPUT ;
    USE SIGNAL ;
    PORT
      LAYER M4 ;
        RECT  21.516 19.776 21.6 19.8 ;
    END
  END o[192]
  PIN o[193]
    DIRECTION OUTPUT ;
    USE SIGNAL ;
    PORT
      LAYER M4 ;
        RECT  21.516 19.872 21.6 19.896 ;
    END
  END o[193]
  PIN o[194]
    DIRECTION OUTPUT ;
    USE SIGNAL ;
    PORT
      LAYER M4 ;
        RECT  21.516 19.968 21.6 19.992 ;
    END
  END o[194]
  PIN o[195]
    DIRECTION OUTPUT ;
    USE SIGNAL ;
    PORT
      LAYER M4 ;
        RECT  21.516 20.064 21.6 20.088 ;
    END
  END o[195]
  PIN o[196]
    DIRECTION OUTPUT ;
    USE SIGNAL ;
    PORT
      LAYER M4 ;
        RECT  21.516 20.16 21.6 20.184 ;
    END
  END o[196]
  PIN o[197]
    DIRECTION OUTPUT ;
    USE SIGNAL ;
    PORT
      LAYER M4 ;
        RECT  21.516 20.256 21.6 20.28 ;
    END
  END o[197]
  PIN o[198]
    DIRECTION OUTPUT ;
    USE SIGNAL ;
    PORT
      LAYER M4 ;
        RECT  21.516 20.352 21.6 20.376 ;
    END
  END o[198]
  PIN o[199]
    DIRECTION OUTPUT ;
    USE SIGNAL ;
    PORT
      LAYER M4 ;
        RECT  21.516 20.496 21.6 20.52 ;
    END
  END o[199]
  PIN o[19]
    DIRECTION OUTPUT ;
    USE SIGNAL ;
    PORT
      LAYER M4 ;
        RECT  21.516 2.544 21.6 2.568 ;
    END
  END o[19]
  PIN o[1]
    DIRECTION OUTPUT ;
    USE SIGNAL ;
    PORT
      LAYER M4 ;
        RECT  21.516 0.72 21.6 0.744 ;
    END
  END o[1]
  PIN o[200]
    DIRECTION OUTPUT ;
    USE SIGNAL ;
    PORT
      LAYER M4 ;
        RECT  21.516 20.592 21.6 20.616 ;
    END
  END o[200]
  PIN o[201]
    DIRECTION OUTPUT ;
    USE SIGNAL ;
    PORT
      LAYER M4 ;
        RECT  21.516 20.688 21.6 20.712 ;
    END
  END o[201]
  PIN o[202]
    DIRECTION OUTPUT ;
    USE SIGNAL ;
    PORT
      LAYER M4 ;
        RECT  21.516 20.784 21.6 20.808 ;
    END
  END o[202]
  PIN o[203]
    DIRECTION OUTPUT ;
    USE SIGNAL ;
    PORT
      LAYER M4 ;
        RECT  21.516 20.88 21.6 20.904 ;
    END
  END o[203]
  PIN o[204]
    DIRECTION OUTPUT ;
    USE SIGNAL ;
    PORT
      LAYER M4 ;
        RECT  21.516 20.976 21.6 21 ;
    END
  END o[204]
  PIN o[205]
    DIRECTION OUTPUT ;
    USE SIGNAL ;
    PORT
      LAYER M4 ;
        RECT  21.516 21.072 21.6 21.096 ;
    END
  END o[205]
  PIN o[206]
    DIRECTION OUTPUT ;
    USE SIGNAL ;
    PORT
      LAYER M4 ;
        RECT  21.516 21.168 21.6 21.192 ;
    END
  END o[206]
  PIN o[207]
    DIRECTION OUTPUT ;
    USE SIGNAL ;
    PORT
      LAYER M4 ;
        RECT  21.516 21.264 21.6 21.288 ;
    END
  END o[207]
  PIN o[208]
    DIRECTION OUTPUT ;
    USE SIGNAL ;
    PORT
      LAYER M4 ;
        RECT  21.516 21.36 21.6 21.384 ;
    END
  END o[208]
  PIN o[209]
    DIRECTION OUTPUT ;
    USE SIGNAL ;
    PORT
      LAYER M4 ;
        RECT  21.516 21.456 21.6 21.48 ;
    END
  END o[209]
  PIN o[20]
    DIRECTION OUTPUT ;
    USE SIGNAL ;
    PORT
      LAYER M4 ;
        RECT  21.516 2.64 21.6 2.664 ;
    END
  END o[20]
  PIN o[210]
    DIRECTION OUTPUT ;
    USE SIGNAL ;
    PORT
      LAYER M4 ;
        RECT  21.516 21.552 21.6 21.576 ;
    END
  END o[210]
  PIN o[211]
    DIRECTION OUTPUT ;
    USE SIGNAL ;
    PORT
      LAYER M4 ;
        RECT  21.516 21.648 21.6 21.672 ;
    END
  END o[211]
  PIN o[212]
    DIRECTION OUTPUT ;
    USE SIGNAL ;
    PORT
      LAYER M4 ;
        RECT  21.516 21.792 21.6 21.816 ;
    END
  END o[212]
  PIN o[213]
    DIRECTION OUTPUT ;
    USE SIGNAL ;
    PORT
      LAYER M4 ;
        RECT  21.516 21.888 21.6 21.912 ;
    END
  END o[213]
  PIN o[214]
    DIRECTION OUTPUT ;
    USE SIGNAL ;
    PORT
      LAYER M4 ;
        RECT  21.516 21.984 21.6 22.008 ;
    END
  END o[214]
  PIN o[215]
    DIRECTION OUTPUT ;
    USE SIGNAL ;
    PORT
      LAYER M4 ;
        RECT  21.516 22.08 21.6 22.104 ;
    END
  END o[215]
  PIN o[216]
    DIRECTION OUTPUT ;
    USE SIGNAL ;
    PORT
      LAYER M4 ;
        RECT  21.516 22.176 21.6 22.2 ;
    END
  END o[216]
  PIN o[217]
    DIRECTION OUTPUT ;
    USE SIGNAL ;
    PORT
      LAYER M4 ;
        RECT  21.516 22.272 21.6 22.296 ;
    END
  END o[217]
  PIN o[218]
    DIRECTION OUTPUT ;
    USE SIGNAL ;
    PORT
      LAYER M4 ;
        RECT  21.516 22.368 21.6 22.392 ;
    END
  END o[218]
  PIN o[219]
    DIRECTION OUTPUT ;
    USE SIGNAL ;
    PORT
      LAYER M4 ;
        RECT  21.516 22.464 21.6 22.488 ;
    END
  END o[219]
  PIN o[21]
    DIRECTION OUTPUT ;
    USE SIGNAL ;
    PORT
      LAYER M4 ;
        RECT  21.516 2.736 21.6 2.76 ;
    END
  END o[21]
  PIN o[220]
    DIRECTION OUTPUT ;
    USE SIGNAL ;
    PORT
      LAYER M4 ;
        RECT  21.516 22.56 21.6 22.584 ;
    END
  END o[220]
  PIN o[221]
    DIRECTION OUTPUT ;
    USE SIGNAL ;
    PORT
      LAYER M4 ;
        RECT  21.516 22.656 21.6 22.68 ;
    END
  END o[221]
  PIN o[222]
    DIRECTION OUTPUT ;
    USE SIGNAL ;
    PORT
      LAYER M4 ;
        RECT  21.516 22.752 21.6 22.776 ;
    END
  END o[222]
  PIN o[223]
    DIRECTION OUTPUT ;
    USE SIGNAL ;
    PORT
      LAYER M4 ;
        RECT  21.516 22.848 21.6 22.872 ;
    END
  END o[223]
  PIN o[224]
    DIRECTION OUTPUT ;
    USE SIGNAL ;
    PORT
      LAYER M4 ;
        RECT  21.516 22.944 21.6 22.968 ;
    END
  END o[224]
  PIN o[225]
    DIRECTION OUTPUT ;
    USE SIGNAL ;
    PORT
      LAYER M4 ;
        RECT  21.516 23.088 21.6 23.112 ;
    END
  END o[225]
  PIN o[226]
    DIRECTION OUTPUT ;
    USE SIGNAL ;
    PORT
      LAYER M4 ;
        RECT  21.516 23.184 21.6 23.208 ;
    END
  END o[226]
  PIN o[227]
    DIRECTION OUTPUT ;
    USE SIGNAL ;
    PORT
      LAYER M4 ;
        RECT  21.516 23.28 21.6 23.304 ;
    END
  END o[227]
  PIN o[228]
    DIRECTION OUTPUT ;
    USE SIGNAL ;
    PORT
      LAYER M4 ;
        RECT  21.516 23.376 21.6 23.4 ;
    END
  END o[228]
  PIN o[229]
    DIRECTION OUTPUT ;
    USE SIGNAL ;
    PORT
      LAYER M4 ;
        RECT  21.516 23.472 21.6 23.496 ;
    END
  END o[229]
  PIN o[22]
    DIRECTION OUTPUT ;
    USE SIGNAL ;
    PORT
      LAYER M4 ;
        RECT  21.516 2.832 21.6 2.856 ;
    END
  END o[22]
  PIN o[230]
    DIRECTION OUTPUT ;
    USE SIGNAL ;
    PORT
      LAYER M4 ;
        RECT  21.516 23.568 21.6 23.592 ;
    END
  END o[230]
  PIN o[231]
    DIRECTION OUTPUT ;
    USE SIGNAL ;
    PORT
      LAYER M4 ;
        RECT  21.516 23.664 21.6 23.688 ;
    END
  END o[231]
  PIN o[232]
    DIRECTION OUTPUT ;
    USE SIGNAL ;
    PORT
      LAYER M4 ;
        RECT  21.516 23.76 21.6 23.784 ;
    END
  END o[232]
  PIN o[233]
    DIRECTION OUTPUT ;
    USE SIGNAL ;
    PORT
      LAYER M4 ;
        RECT  21.516 23.856 21.6 23.88 ;
    END
  END o[233]
  PIN o[234]
    DIRECTION OUTPUT ;
    USE SIGNAL ;
    PORT
      LAYER M4 ;
        RECT  21.516 23.952 21.6 23.976 ;
    END
  END o[234]
  PIN o[235]
    DIRECTION OUTPUT ;
    USE SIGNAL ;
    PORT
      LAYER M4 ;
        RECT  21.516 24.048 21.6 24.072 ;
    END
  END o[235]
  PIN o[236]
    DIRECTION OUTPUT ;
    USE SIGNAL ;
    PORT
      LAYER M4 ;
        RECT  21.516 24.144 21.6 24.168 ;
    END
  END o[236]
  PIN o[237]
    DIRECTION OUTPUT ;
    USE SIGNAL ;
    PORT
      LAYER M4 ;
        RECT  21.516 24.24 21.6 24.264 ;
    END
  END o[237]
  PIN o[238]
    DIRECTION OUTPUT ;
    USE SIGNAL ;
    PORT
      LAYER M4 ;
        RECT  21.516 24.384 21.6 24.408 ;
    END
  END o[238]
  PIN o[239]
    DIRECTION OUTPUT ;
    USE SIGNAL ;
    PORT
      LAYER M4 ;
        RECT  21.516 24.48 21.6 24.504 ;
    END
  END o[239]
  PIN o[23]
    DIRECTION OUTPUT ;
    USE SIGNAL ;
    PORT
      LAYER M4 ;
        RECT  21.516 2.928 21.6 2.952 ;
    END
  END o[23]
  PIN o[240]
    DIRECTION OUTPUT ;
    USE SIGNAL ;
    PORT
      LAYER M4 ;
        RECT  21.516 24.576 21.6 24.6 ;
    END
  END o[240]
  PIN o[241]
    DIRECTION OUTPUT ;
    USE SIGNAL ;
    PORT
      LAYER M4 ;
        RECT  21.516 24.672 21.6 24.696 ;
    END
  END o[241]
  PIN o[242]
    DIRECTION OUTPUT ;
    USE SIGNAL ;
    PORT
      LAYER M4 ;
        RECT  21.516 24.768 21.6 24.792 ;
    END
  END o[242]
  PIN o[243]
    DIRECTION OUTPUT ;
    USE SIGNAL ;
    PORT
      LAYER M4 ;
        RECT  21.516 24.864 21.6 24.888 ;
    END
  END o[243]
  PIN o[244]
    DIRECTION OUTPUT ;
    USE SIGNAL ;
    PORT
      LAYER M4 ;
        RECT  21.516 24.96 21.6 24.984 ;
    END
  END o[244]
  PIN o[245]
    DIRECTION OUTPUT ;
    USE SIGNAL ;
    PORT
      LAYER M4 ;
        RECT  21.516 25.056 21.6 25.08 ;
    END
  END o[245]
  PIN o[246]
    DIRECTION OUTPUT ;
    USE SIGNAL ;
    PORT
      LAYER M4 ;
        RECT  21.516 25.152 21.6 25.176 ;
    END
  END o[246]
  PIN o[247]
    DIRECTION OUTPUT ;
    USE SIGNAL ;
    PORT
      LAYER M4 ;
        RECT  21.516 25.248 21.6 25.272 ;
    END
  END o[247]
  PIN o[248]
    DIRECTION OUTPUT ;
    USE SIGNAL ;
    PORT
      LAYER M4 ;
        RECT  21.516 25.344 21.6 25.368 ;
    END
  END o[248]
  PIN o[249]
    DIRECTION OUTPUT ;
    USE SIGNAL ;
    PORT
      LAYER M4 ;
        RECT  21.516 25.44 21.6 25.464 ;
    END
  END o[249]
  PIN o[24]
    DIRECTION OUTPUT ;
    USE SIGNAL ;
    PORT
      LAYER M4 ;
        RECT  21.516 3.024 21.6 3.048 ;
    END
  END o[24]
  PIN o[250]
    DIRECTION OUTPUT ;
    USE SIGNAL ;
    PORT
      LAYER M4 ;
        RECT  21.516 25.536 21.6 25.56 ;
    END
  END o[250]
  PIN o[251]
    DIRECTION OUTPUT ;
    USE SIGNAL ;
    PORT
      LAYER M4 ;
        RECT  21.516 25.68 21.6 25.704 ;
    END
  END o[251]
  PIN o[252]
    DIRECTION OUTPUT ;
    USE SIGNAL ;
    PORT
      LAYER M4 ;
        RECT  21.516 25.776 21.6 25.8 ;
    END
  END o[252]
  PIN o[253]
    DIRECTION OUTPUT ;
    USE SIGNAL ;
    PORT
      LAYER M4 ;
        RECT  21.516 25.872 21.6 25.896 ;
    END
  END o[253]
  PIN o[254]
    DIRECTION OUTPUT ;
    USE SIGNAL ;
    PORT
      LAYER M4 ;
        RECT  21.516 25.968 21.6 25.992 ;
    END
  END o[254]
  PIN o[255]
    DIRECTION OUTPUT ;
    USE SIGNAL ;
    PORT
      LAYER M4 ;
        RECT  21.516 26.064 21.6 26.088 ;
    END
  END o[255]
  PIN o[256]
    DIRECTION OUTPUT ;
    USE SIGNAL ;
    PORT
      LAYER M4 ;
        RECT  21.516 26.16 21.6 26.184 ;
    END
  END o[256]
  PIN o[257]
    DIRECTION OUTPUT ;
    USE SIGNAL ;
    PORT
      LAYER M4 ;
        RECT  21.516 26.256 21.6 26.28 ;
    END
  END o[257]
  PIN o[258]
    DIRECTION OUTPUT ;
    USE SIGNAL ;
    PORT
      LAYER M4 ;
        RECT  21.516 26.352 21.6 26.376 ;
    END
  END o[258]
  PIN o[259]
    DIRECTION OUTPUT ;
    USE SIGNAL ;
    PORT
      LAYER M4 ;
        RECT  21.516 26.448 21.6 26.472 ;
    END
  END o[259]
  PIN o[25]
    DIRECTION OUTPUT ;
    USE SIGNAL ;
    PORT
      LAYER M4 ;
        RECT  21.516 3.12 21.6 3.144 ;
    END
  END o[25]
  PIN o[260]
    DIRECTION OUTPUT ;
    USE SIGNAL ;
    PORT
      LAYER M4 ;
        RECT  21.516 26.544 21.6 26.568 ;
    END
  END o[260]
  PIN o[261]
    DIRECTION OUTPUT ;
    USE SIGNAL ;
    PORT
      LAYER M4 ;
        RECT  21.516 26.64 21.6 26.664 ;
    END
  END o[261]
  PIN o[262]
    DIRECTION OUTPUT ;
    USE SIGNAL ;
    PORT
      LAYER M4 ;
        RECT  21.516 26.736 21.6 26.76 ;
    END
  END o[262]
  PIN o[263]
    DIRECTION OUTPUT ;
    USE SIGNAL ;
    PORT
      LAYER M4 ;
        RECT  21.516 26.832 21.6 26.856 ;
    END
  END o[263]
  PIN o[264]
    DIRECTION OUTPUT ;
    USE SIGNAL ;
    PORT
      LAYER M4 ;
        RECT  21.516 26.976 21.6 27 ;
    END
  END o[264]
  PIN o[265]
    DIRECTION OUTPUT ;
    USE SIGNAL ;
    PORT
      LAYER M4 ;
        RECT  21.516 27.072 21.6 27.096 ;
    END
  END o[265]
  PIN o[266]
    DIRECTION OUTPUT ;
    USE SIGNAL ;
    PORT
      LAYER M4 ;
        RECT  21.516 27.168 21.6 27.192 ;
    END
  END o[266]
  PIN o[267]
    DIRECTION OUTPUT ;
    USE SIGNAL ;
    PORT
      LAYER M4 ;
        RECT  21.516 27.264 21.6 27.288 ;
    END
  END o[267]
  PIN o[268]
    DIRECTION OUTPUT ;
    USE SIGNAL ;
    PORT
      LAYER M4 ;
        RECT  21.516 27.36 21.6 27.384 ;
    END
  END o[268]
  PIN o[269]
    DIRECTION OUTPUT ;
    USE SIGNAL ;
    PORT
      LAYER M4 ;
        RECT  21.516 27.456 21.6 27.48 ;
    END
  END o[269]
  PIN o[26]
    DIRECTION OUTPUT ;
    USE SIGNAL ;
    PORT
      LAYER M4 ;
        RECT  21.516 3.216 21.6 3.24 ;
    END
  END o[26]
  PIN o[270]
    DIRECTION OUTPUT ;
    USE SIGNAL ;
    PORT
      LAYER M4 ;
        RECT  21.516 27.552 21.6 27.576 ;
    END
  END o[270]
  PIN o[271]
    DIRECTION OUTPUT ;
    USE SIGNAL ;
    PORT
      LAYER M4 ;
        RECT  21.516 27.648 21.6 27.672 ;
    END
  END o[271]
  PIN o[272]
    DIRECTION OUTPUT ;
    USE SIGNAL ;
    PORT
      LAYER M4 ;
        RECT  21.516 27.744 21.6 27.768 ;
    END
  END o[272]
  PIN o[273]
    DIRECTION OUTPUT ;
    USE SIGNAL ;
    PORT
      LAYER M4 ;
        RECT  21.516 27.84 21.6 27.864 ;
    END
  END o[273]
  PIN o[274]
    DIRECTION OUTPUT ;
    USE SIGNAL ;
    PORT
      LAYER M4 ;
        RECT  21.516 27.936 21.6 27.96 ;
    END
  END o[274]
  PIN o[275]
    DIRECTION OUTPUT ;
    USE SIGNAL ;
    PORT
      LAYER M4 ;
        RECT  21.516 28.032 21.6 28.056 ;
    END
  END o[275]
  PIN o[276]
    DIRECTION OUTPUT ;
    USE SIGNAL ;
    PORT
      LAYER M4 ;
        RECT  21.516 28.128 21.6 28.152 ;
    END
  END o[276]
  PIN o[277]
    DIRECTION OUTPUT ;
    USE SIGNAL ;
    PORT
      LAYER M4 ;
        RECT  21.516 28.272 21.6 28.296 ;
    END
  END o[277]
  PIN o[278]
    DIRECTION OUTPUT ;
    USE SIGNAL ;
    PORT
      LAYER M4 ;
        RECT  21.516 28.368 21.6 28.392 ;
    END
  END o[278]
  PIN o[279]
    DIRECTION OUTPUT ;
    USE SIGNAL ;
    PORT
      LAYER M4 ;
        RECT  21.516 28.464 21.6 28.488 ;
    END
  END o[279]
  PIN o[27]
    DIRECTION OUTPUT ;
    USE SIGNAL ;
    PORT
      LAYER M4 ;
        RECT  21.516 3.312 21.6 3.336 ;
    END
  END o[27]
  PIN o[280]
    DIRECTION OUTPUT ;
    USE SIGNAL ;
    PORT
      LAYER M4 ;
        RECT  21.516 28.56 21.6 28.584 ;
    END
  END o[280]
  PIN o[281]
    DIRECTION OUTPUT ;
    USE SIGNAL ;
    PORT
      LAYER M4 ;
        RECT  21.516 28.656 21.6 28.68 ;
    END
  END o[281]
  PIN o[282]
    DIRECTION OUTPUT ;
    USE SIGNAL ;
    PORT
      LAYER M4 ;
        RECT  21.516 28.752 21.6 28.776 ;
    END
  END o[282]
  PIN o[283]
    DIRECTION OUTPUT ;
    USE SIGNAL ;
    PORT
      LAYER M4 ;
        RECT  21.516 28.848 21.6 28.872 ;
    END
  END o[283]
  PIN o[284]
    DIRECTION OUTPUT ;
    USE SIGNAL ;
    PORT
      LAYER M4 ;
        RECT  21.516 28.944 21.6 28.968 ;
    END
  END o[284]
  PIN o[285]
    DIRECTION OUTPUT ;
    USE SIGNAL ;
    PORT
      LAYER M4 ;
        RECT  21.516 29.04 21.6 29.064 ;
    END
  END o[285]
  PIN o[286]
    DIRECTION OUTPUT ;
    USE SIGNAL ;
    PORT
      LAYER M4 ;
        RECT  21.516 29.136 21.6 29.16 ;
    END
  END o[286]
  PIN o[287]
    DIRECTION OUTPUT ;
    USE SIGNAL ;
    PORT
      LAYER M4 ;
        RECT  21.516 29.232 21.6 29.256 ;
    END
  END o[287]
  PIN o[288]
    DIRECTION OUTPUT ;
    USE SIGNAL ;
    PORT
      LAYER M4 ;
        RECT  21.516 29.328 21.6 29.352 ;
    END
  END o[288]
  PIN o[289]
    DIRECTION OUTPUT ;
    USE SIGNAL ;
    PORT
      LAYER M4 ;
        RECT  21.516 29.424 21.6 29.448 ;
    END
  END o[289]
  PIN o[28]
    DIRECTION OUTPUT ;
    USE SIGNAL ;
    PORT
      LAYER M4 ;
        RECT  21.516 3.408 21.6 3.432 ;
    END
  END o[28]
  PIN o[290]
    DIRECTION OUTPUT ;
    USE SIGNAL ;
    PORT
      LAYER M4 ;
        RECT  21.516 29.568 21.6 29.592 ;
    END
  END o[290]
  PIN o[291]
    DIRECTION OUTPUT ;
    USE SIGNAL ;
    PORT
      LAYER M4 ;
        RECT  21.516 29.664 21.6 29.688 ;
    END
  END o[291]
  PIN o[292]
    DIRECTION OUTPUT ;
    USE SIGNAL ;
    PORT
      LAYER M4 ;
        RECT  21.516 29.76 21.6 29.784 ;
    END
  END o[292]
  PIN o[293]
    DIRECTION OUTPUT ;
    USE SIGNAL ;
    PORT
      LAYER M4 ;
        RECT  21.516 29.856 21.6 29.88 ;
    END
  END o[293]
  PIN o[294]
    DIRECTION OUTPUT ;
    USE SIGNAL ;
    PORT
      LAYER M4 ;
        RECT  21.516 29.952 21.6 29.976 ;
    END
  END o[294]
  PIN o[295]
    DIRECTION OUTPUT ;
    USE SIGNAL ;
    PORT
      LAYER M4 ;
        RECT  21.516 30.048 21.6 30.072 ;
    END
  END o[295]
  PIN o[296]
    DIRECTION OUTPUT ;
    USE SIGNAL ;
    PORT
      LAYER M4 ;
        RECT  21.516 30.144 21.6 30.168 ;
    END
  END o[296]
  PIN o[297]
    DIRECTION OUTPUT ;
    USE SIGNAL ;
    PORT
      LAYER M4 ;
        RECT  21.516 30.24 21.6 30.264 ;
    END
  END o[297]
  PIN o[298]
    DIRECTION OUTPUT ;
    USE SIGNAL ;
    PORT
      LAYER M4 ;
        RECT  21.516 30.336 21.6 30.36 ;
    END
  END o[298]
  PIN o[299]
    DIRECTION OUTPUT ;
    USE SIGNAL ;
    PORT
      LAYER M4 ;
        RECT  21.516 30.432 21.6 30.456 ;
    END
  END o[299]
  PIN o[29]
    DIRECTION OUTPUT ;
    USE SIGNAL ;
    PORT
      LAYER M4 ;
        RECT  21.516 3.552 21.6 3.576 ;
    END
  END o[29]
  PIN o[2]
    DIRECTION OUTPUT ;
    USE SIGNAL ;
    PORT
      LAYER M4 ;
        RECT  21.516 0.816 21.6 0.84 ;
    END
  END o[2]
  PIN o[300]
    DIRECTION OUTPUT ;
    USE SIGNAL ;
    PORT
      LAYER M4 ;
        RECT  21.516 30.528 21.6 30.552 ;
    END
  END o[300]
  PIN o[301]
    DIRECTION OUTPUT ;
    USE SIGNAL ;
    PORT
      LAYER M4 ;
        RECT  21.516 30.624 21.6 30.648 ;
    END
  END o[301]
  PIN o[302]
    DIRECTION OUTPUT ;
    USE SIGNAL ;
    PORT
      LAYER M4 ;
        RECT  21.516 30.72 21.6 30.744 ;
    END
  END o[302]
  PIN o[303]
    DIRECTION OUTPUT ;
    USE SIGNAL ;
    PORT
      LAYER M4 ;
        RECT  21.516 30.864 21.6 30.888 ;
    END
  END o[303]
  PIN o[304]
    DIRECTION OUTPUT ;
    USE SIGNAL ;
    PORT
      LAYER M4 ;
        RECT  21.516 30.96 21.6 30.984 ;
    END
  END o[304]
  PIN o[305]
    DIRECTION OUTPUT ;
    USE SIGNAL ;
    PORT
      LAYER M4 ;
        RECT  21.516 31.056 21.6 31.08 ;
    END
  END o[305]
  PIN o[306]
    DIRECTION OUTPUT ;
    USE SIGNAL ;
    PORT
      LAYER M4 ;
        RECT  21.516 31.152 21.6 31.176 ;
    END
  END o[306]
  PIN o[307]
    DIRECTION OUTPUT ;
    USE SIGNAL ;
    PORT
      LAYER M4 ;
        RECT  21.516 31.248 21.6 31.272 ;
    END
  END o[307]
  PIN o[308]
    DIRECTION OUTPUT ;
    USE SIGNAL ;
    PORT
      LAYER M4 ;
        RECT  21.516 31.344 21.6 31.368 ;
    END
  END o[308]
  PIN o[309]
    DIRECTION OUTPUT ;
    USE SIGNAL ;
    PORT
      LAYER M4 ;
        RECT  21.516 31.44 21.6 31.464 ;
    END
  END o[309]
  PIN o[30]
    DIRECTION OUTPUT ;
    USE SIGNAL ;
    PORT
      LAYER M4 ;
        RECT  21.516 3.648 21.6 3.672 ;
    END
  END o[30]
  PIN o[310]
    DIRECTION OUTPUT ;
    USE SIGNAL ;
    PORT
      LAYER M4 ;
        RECT  21.516 31.536 21.6 31.56 ;
    END
  END o[310]
  PIN o[311]
    DIRECTION OUTPUT ;
    USE SIGNAL ;
    PORT
      LAYER M4 ;
        RECT  21.516 31.632 21.6 31.656 ;
    END
  END o[311]
  PIN o[312]
    DIRECTION OUTPUT ;
    USE SIGNAL ;
    PORT
      LAYER M4 ;
        RECT  21.516 31.728 21.6 31.752 ;
    END
  END o[312]
  PIN o[313]
    DIRECTION OUTPUT ;
    USE SIGNAL ;
    PORT
      LAYER M4 ;
        RECT  21.516 31.824 21.6 31.848 ;
    END
  END o[313]
  PIN o[314]
    DIRECTION OUTPUT ;
    USE SIGNAL ;
    PORT
      LAYER M4 ;
        RECT  21.516 31.92 21.6 31.944 ;
    END
  END o[314]
  PIN o[315]
    DIRECTION OUTPUT ;
    USE SIGNAL ;
    PORT
      LAYER M4 ;
        RECT  21.516 32.016 21.6 32.04 ;
    END
  END o[315]
  PIN o[316]
    DIRECTION OUTPUT ;
    USE SIGNAL ;
    PORT
      LAYER M4 ;
        RECT  21.516 32.16 21.6 32.184 ;
    END
  END o[316]
  PIN o[317]
    DIRECTION OUTPUT ;
    USE SIGNAL ;
    PORT
      LAYER M4 ;
        RECT  21.516 32.256 21.6 32.28 ;
    END
  END o[317]
  PIN o[318]
    DIRECTION OUTPUT ;
    USE SIGNAL ;
    PORT
      LAYER M4 ;
        RECT  21.516 32.352 21.6 32.376 ;
    END
  END o[318]
  PIN o[319]
    DIRECTION OUTPUT ;
    USE SIGNAL ;
    PORT
      LAYER M4 ;
        RECT  21.516 32.448 21.6 32.472 ;
    END
  END o[319]
  PIN o[31]
    DIRECTION OUTPUT ;
    USE SIGNAL ;
    PORT
      LAYER M4 ;
        RECT  21.516 3.744 21.6 3.768 ;
    END
  END o[31]
  PIN o[320]
    DIRECTION OUTPUT ;
    USE SIGNAL ;
    PORT
      LAYER M4 ;
        RECT  21.516 32.544 21.6 32.568 ;
    END
  END o[320]
  PIN o[321]
    DIRECTION OUTPUT ;
    USE SIGNAL ;
    PORT
      LAYER M4 ;
        RECT  21.516 32.64 21.6 32.664 ;
    END
  END o[321]
  PIN o[322]
    DIRECTION OUTPUT ;
    USE SIGNAL ;
    PORT
      LAYER M4 ;
        RECT  21.516 32.736 21.6 32.76 ;
    END
  END o[322]
  PIN o[323]
    DIRECTION OUTPUT ;
    USE SIGNAL ;
    PORT
      LAYER M4 ;
        RECT  21.516 32.832 21.6 32.856 ;
    END
  END o[323]
  PIN o[324]
    DIRECTION OUTPUT ;
    USE SIGNAL ;
    PORT
      LAYER M4 ;
        RECT  21.516 32.928 21.6 32.952 ;
    END
  END o[324]
  PIN o[325]
    DIRECTION OUTPUT ;
    USE SIGNAL ;
    PORT
      LAYER M4 ;
        RECT  21.516 33.024 21.6 33.048 ;
    END
  END o[325]
  PIN o[326]
    DIRECTION OUTPUT ;
    USE SIGNAL ;
    PORT
      LAYER M4 ;
        RECT  21.516 33.12 21.6 33.144 ;
    END
  END o[326]
  PIN o[327]
    DIRECTION OUTPUT ;
    USE SIGNAL ;
    PORT
      LAYER M4 ;
        RECT  21.516 33.216 21.6 33.24 ;
    END
  END o[327]
  PIN o[328]
    DIRECTION OUTPUT ;
    USE SIGNAL ;
    PORT
      LAYER M4 ;
        RECT  21.516 33.312 21.6 33.336 ;
    END
  END o[328]
  PIN o[329]
    DIRECTION OUTPUT ;
    USE SIGNAL ;
    PORT
      LAYER M4 ;
        RECT  21.516 33.456 21.6 33.48 ;
    END
  END o[329]
  PIN o[32]
    DIRECTION OUTPUT ;
    USE SIGNAL ;
    PORT
      LAYER M4 ;
        RECT  21.516 3.84 21.6 3.864 ;
    END
  END o[32]
  PIN o[330]
    DIRECTION OUTPUT ;
    USE SIGNAL ;
    PORT
      LAYER M4 ;
        RECT  21.516 33.552 21.6 33.576 ;
    END
  END o[330]
  PIN o[331]
    DIRECTION OUTPUT ;
    USE SIGNAL ;
    PORT
      LAYER M4 ;
        RECT  21.516 33.648 21.6 33.672 ;
    END
  END o[331]
  PIN o[332]
    DIRECTION OUTPUT ;
    USE SIGNAL ;
    PORT
      LAYER M4 ;
        RECT  21.516 33.744 21.6 33.768 ;
    END
  END o[332]
  PIN o[333]
    DIRECTION OUTPUT ;
    USE SIGNAL ;
    PORT
      LAYER M4 ;
        RECT  21.516 33.84 21.6 33.864 ;
    END
  END o[333]
  PIN o[334]
    DIRECTION OUTPUT ;
    USE SIGNAL ;
    PORT
      LAYER M4 ;
        RECT  21.516 33.936 21.6 33.96 ;
    END
  END o[334]
  PIN o[335]
    DIRECTION OUTPUT ;
    USE SIGNAL ;
    PORT
      LAYER M4 ;
        RECT  21.516 34.032 21.6 34.056 ;
    END
  END o[335]
  PIN o[336]
    DIRECTION OUTPUT ;
    USE SIGNAL ;
    PORT
      LAYER M4 ;
        RECT  21.516 34.128 21.6 34.152 ;
    END
  END o[336]
  PIN o[337]
    DIRECTION OUTPUT ;
    USE SIGNAL ;
    PORT
      LAYER M4 ;
        RECT  21.516 34.224 21.6 34.248 ;
    END
  END o[337]
  PIN o[338]
    DIRECTION OUTPUT ;
    USE SIGNAL ;
    PORT
      LAYER M4 ;
        RECT  21.516 34.32 21.6 34.344 ;
    END
  END o[338]
  PIN o[339]
    DIRECTION OUTPUT ;
    USE SIGNAL ;
    PORT
      LAYER M4 ;
        RECT  21.516 34.416 21.6 34.44 ;
    END
  END o[339]
  PIN o[33]
    DIRECTION OUTPUT ;
    USE SIGNAL ;
    PORT
      LAYER M4 ;
        RECT  21.516 3.936 21.6 3.96 ;
    END
  END o[33]
  PIN o[340]
    DIRECTION OUTPUT ;
    USE SIGNAL ;
    PORT
      LAYER M4 ;
        RECT  21.516 34.512 21.6 34.536 ;
    END
  END o[340]
  PIN o[341]
    DIRECTION OUTPUT ;
    USE SIGNAL ;
    PORT
      LAYER M4 ;
        RECT  21.516 34.608 21.6 34.632 ;
    END
  END o[341]
  PIN o[342]
    DIRECTION OUTPUT ;
    USE SIGNAL ;
    PORT
      LAYER M4 ;
        RECT  21.516 34.752 21.6 34.776 ;
    END
  END o[342]
  PIN o[343]
    DIRECTION OUTPUT ;
    USE SIGNAL ;
    PORT
      LAYER M4 ;
        RECT  21.516 34.848 21.6 34.872 ;
    END
  END o[343]
  PIN o[344]
    DIRECTION OUTPUT ;
    USE SIGNAL ;
    PORT
      LAYER M4 ;
        RECT  21.516 34.944 21.6 34.968 ;
    END
  END o[344]
  PIN o[345]
    DIRECTION OUTPUT ;
    USE SIGNAL ;
    PORT
      LAYER M4 ;
        RECT  21.516 35.04 21.6 35.064 ;
    END
  END o[345]
  PIN o[346]
    DIRECTION OUTPUT ;
    USE SIGNAL ;
    PORT
      LAYER M4 ;
        RECT  21.516 35.136 21.6 35.16 ;
    END
  END o[346]
  PIN o[347]
    DIRECTION OUTPUT ;
    USE SIGNAL ;
    PORT
      LAYER M4 ;
        RECT  21.516 35.232 21.6 35.256 ;
    END
  END o[347]
  PIN o[348]
    DIRECTION OUTPUT ;
    USE SIGNAL ;
    PORT
      LAYER M4 ;
        RECT  21.516 35.328 21.6 35.352 ;
    END
  END o[348]
  PIN o[349]
    DIRECTION OUTPUT ;
    USE SIGNAL ;
    PORT
      LAYER M4 ;
        RECT  21.516 35.424 21.6 35.448 ;
    END
  END o[349]
  PIN o[34]
    DIRECTION OUTPUT ;
    USE SIGNAL ;
    PORT
      LAYER M4 ;
        RECT  21.516 4.032 21.6 4.056 ;
    END
  END o[34]
  PIN o[350]
    DIRECTION OUTPUT ;
    USE SIGNAL ;
    PORT
      LAYER M4 ;
        RECT  21.516 35.52 21.6 35.544 ;
    END
  END o[350]
  PIN o[351]
    DIRECTION OUTPUT ;
    USE SIGNAL ;
    PORT
      LAYER M4 ;
        RECT  21.516 35.616 21.6 35.64 ;
    END
  END o[351]
  PIN o[352]
    DIRECTION OUTPUT ;
    USE SIGNAL ;
    PORT
      LAYER M4 ;
        RECT  21.516 35.712 21.6 35.736 ;
    END
  END o[352]
  PIN o[353]
    DIRECTION OUTPUT ;
    USE SIGNAL ;
    PORT
      LAYER M4 ;
        RECT  21.516 35.808 21.6 35.832 ;
    END
  END o[353]
  PIN o[354]
    DIRECTION OUTPUT ;
    USE SIGNAL ;
    PORT
      LAYER M4 ;
        RECT  21.516 35.904 21.6 35.928 ;
    END
  END o[354]
  PIN o[355]
    DIRECTION OUTPUT ;
    USE SIGNAL ;
    PORT
      LAYER M4 ;
        RECT  21.516 36.048 21.6 36.072 ;
    END
  END o[355]
  PIN o[356]
    DIRECTION OUTPUT ;
    USE SIGNAL ;
    PORT
      LAYER M4 ;
        RECT  21.516 36.144 21.6 36.168 ;
    END
  END o[356]
  PIN o[357]
    DIRECTION OUTPUT ;
    USE SIGNAL ;
    PORT
      LAYER M4 ;
        RECT  21.516 36.24 21.6 36.264 ;
    END
  END o[357]
  PIN o[358]
    DIRECTION OUTPUT ;
    USE SIGNAL ;
    PORT
      LAYER M4 ;
        RECT  21.516 36.336 21.6 36.36 ;
    END
  END o[358]
  PIN o[359]
    DIRECTION OUTPUT ;
    USE SIGNAL ;
    PORT
      LAYER M4 ;
        RECT  21.516 36.432 21.6 36.456 ;
    END
  END o[359]
  PIN o[35]
    DIRECTION OUTPUT ;
    USE SIGNAL ;
    PORT
      LAYER M4 ;
        RECT  21.516 4.128 21.6 4.152 ;
    END
  END o[35]
  PIN o[360]
    DIRECTION OUTPUT ;
    USE SIGNAL ;
    PORT
      LAYER M4 ;
        RECT  21.516 36.528 21.6 36.552 ;
    END
  END o[360]
  PIN o[361]
    DIRECTION OUTPUT ;
    USE SIGNAL ;
    PORT
      LAYER M4 ;
        RECT  21.516 36.624 21.6 36.648 ;
    END
  END o[361]
  PIN o[362]
    DIRECTION OUTPUT ;
    USE SIGNAL ;
    PORT
      LAYER M4 ;
        RECT  21.516 36.72 21.6 36.744 ;
    END
  END o[362]
  PIN o[363]
    DIRECTION OUTPUT ;
    USE SIGNAL ;
    PORT
      LAYER M4 ;
        RECT  21.516 36.816 21.6 36.84 ;
    END
  END o[363]
  PIN o[364]
    DIRECTION OUTPUT ;
    USE SIGNAL ;
    PORT
      LAYER M4 ;
        RECT  21.516 36.912 21.6 36.936 ;
    END
  END o[364]
  PIN o[365]
    DIRECTION OUTPUT ;
    USE SIGNAL ;
    PORT
      LAYER M4 ;
        RECT  21.516 37.008 21.6 37.032 ;
    END
  END o[365]
  PIN o[366]
    DIRECTION OUTPUT ;
    USE SIGNAL ;
    PORT
      LAYER M4 ;
        RECT  21.516 37.104 21.6 37.128 ;
    END
  END o[366]
  PIN o[367]
    DIRECTION OUTPUT ;
    USE SIGNAL ;
    PORT
      LAYER M4 ;
        RECT  21.516 37.2 21.6 37.224 ;
    END
  END o[367]
  PIN o[368]
    DIRECTION OUTPUT ;
    USE SIGNAL ;
    PORT
      LAYER M4 ;
        RECT  21.516 37.344 21.6 37.368 ;
    END
  END o[368]
  PIN o[369]
    DIRECTION OUTPUT ;
    USE SIGNAL ;
    PORT
      LAYER M4 ;
        RECT  21.516 37.44 21.6 37.464 ;
    END
  END o[369]
  PIN o[36]
    DIRECTION OUTPUT ;
    USE SIGNAL ;
    PORT
      LAYER M4 ;
        RECT  21.516 4.224 21.6 4.248 ;
    END
  END o[36]
  PIN o[370]
    DIRECTION OUTPUT ;
    USE SIGNAL ;
    PORT
      LAYER M4 ;
        RECT  21.516 37.536 21.6 37.56 ;
    END
  END o[370]
  PIN o[371]
    DIRECTION OUTPUT ;
    USE SIGNAL ;
    PORT
      LAYER M4 ;
        RECT  21.516 37.632 21.6 37.656 ;
    END
  END o[371]
  PIN o[372]
    DIRECTION OUTPUT ;
    USE SIGNAL ;
    PORT
      LAYER M4 ;
        RECT  21.516 37.728 21.6 37.752 ;
    END
  END o[372]
  PIN o[373]
    DIRECTION OUTPUT ;
    USE SIGNAL ;
    PORT
      LAYER M4 ;
        RECT  21.516 37.824 21.6 37.848 ;
    END
  END o[373]
  PIN o[374]
    DIRECTION OUTPUT ;
    USE SIGNAL ;
    PORT
      LAYER M4 ;
        RECT  21.516 37.92 21.6 37.944 ;
    END
  END o[374]
  PIN o[375]
    DIRECTION OUTPUT ;
    USE SIGNAL ;
    PORT
      LAYER M4 ;
        RECT  21.516 38.016 21.6 38.04 ;
    END
  END o[375]
  PIN o[376]
    DIRECTION OUTPUT ;
    USE SIGNAL ;
    PORT
      LAYER M4 ;
        RECT  21.516 38.112 21.6 38.136 ;
    END
  END o[376]
  PIN o[377]
    DIRECTION OUTPUT ;
    USE SIGNAL ;
    PORT
      LAYER M4 ;
        RECT  21.516 38.208 21.6 38.232 ;
    END
  END o[377]
  PIN o[378]
    DIRECTION OUTPUT ;
    USE SIGNAL ;
    PORT
      LAYER M4 ;
        RECT  21.516 38.304 21.6 38.328 ;
    END
  END o[378]
  PIN o[379]
    DIRECTION OUTPUT ;
    USE SIGNAL ;
    PORT
      LAYER M4 ;
        RECT  21.516 38.4 21.6 38.424 ;
    END
  END o[379]
  PIN o[37]
    DIRECTION OUTPUT ;
    USE SIGNAL ;
    PORT
      LAYER M4 ;
        RECT  21.516 4.32 21.6 4.344 ;
    END
  END o[37]
  PIN o[380]
    DIRECTION OUTPUT ;
    USE SIGNAL ;
    PORT
      LAYER M4 ;
        RECT  21.516 38.496 21.6 38.52 ;
    END
  END o[380]
  PIN o[381]
    DIRECTION OUTPUT ;
    USE SIGNAL ;
    PORT
      LAYER M4 ;
        RECT  21.516 38.64 21.6 38.664 ;
    END
  END o[381]
  PIN o[382]
    DIRECTION OUTPUT ;
    USE SIGNAL ;
    PORT
      LAYER M4 ;
        RECT  21.516 38.736 21.6 38.76 ;
    END
  END o[382]
  PIN o[383]
    DIRECTION OUTPUT ;
    USE SIGNAL ;
    PORT
      LAYER M4 ;
        RECT  21.516 38.832 21.6 38.856 ;
    END
  END o[383]
  PIN o[384]
    DIRECTION OUTPUT ;
    USE SIGNAL ;
    PORT
      LAYER M4 ;
        RECT  21.516 38.928 21.6 38.952 ;
    END
  END o[384]
  PIN o[385]
    DIRECTION OUTPUT ;
    USE SIGNAL ;
    PORT
      LAYER M4 ;
        RECT  21.516 39.024 21.6 39.048 ;
    END
  END o[385]
  PIN o[386]
    DIRECTION OUTPUT ;
    USE SIGNAL ;
    PORT
      LAYER M4 ;
        RECT  21.516 39.12 21.6 39.144 ;
    END
  END o[386]
  PIN o[387]
    DIRECTION OUTPUT ;
    USE SIGNAL ;
    PORT
      LAYER M4 ;
        RECT  21.516 39.216 21.6 39.24 ;
    END
  END o[387]
  PIN o[388]
    DIRECTION OUTPUT ;
    USE SIGNAL ;
    PORT
      LAYER M4 ;
        RECT  21.516 39.312 21.6 39.336 ;
    END
  END o[388]
  PIN o[389]
    DIRECTION OUTPUT ;
    USE SIGNAL ;
    PORT
      LAYER M4 ;
        RECT  21.516 39.408 21.6 39.432 ;
    END
  END o[389]
  PIN o[38]
    DIRECTION OUTPUT ;
    USE SIGNAL ;
    PORT
      LAYER M4 ;
        RECT  21.516 4.416 21.6 4.44 ;
    END
  END o[38]
  PIN o[390]
    DIRECTION OUTPUT ;
    USE SIGNAL ;
    PORT
      LAYER M4 ;
        RECT  21.516 39.504 21.6 39.528 ;
    END
  END o[390]
  PIN o[391]
    DIRECTION OUTPUT ;
    USE SIGNAL ;
    PORT
      LAYER M4 ;
        RECT  21.516 39.6 21.6 39.624 ;
    END
  END o[391]
  PIN o[392]
    DIRECTION OUTPUT ;
    USE SIGNAL ;
    PORT
      LAYER M4 ;
        RECT  21.516 39.696 21.6 39.72 ;
    END
  END o[392]
  PIN o[393]
    DIRECTION OUTPUT ;
    USE SIGNAL ;
    PORT
      LAYER M4 ;
        RECT  21.516 39.792 21.6 39.816 ;
    END
  END o[393]
  PIN o[394]
    DIRECTION OUTPUT ;
    USE SIGNAL ;
    PORT
      LAYER M4 ;
        RECT  21.516 39.936 21.6 39.96 ;
    END
  END o[394]
  PIN o[395]
    DIRECTION OUTPUT ;
    USE SIGNAL ;
    PORT
      LAYER M4 ;
        RECT  21.516 40.032 21.6 40.056 ;
    END
  END o[395]
  PIN o[396]
    DIRECTION OUTPUT ;
    USE SIGNAL ;
    PORT
      LAYER M4 ;
        RECT  21.516 40.128 21.6 40.152 ;
    END
  END o[396]
  PIN o[397]
    DIRECTION OUTPUT ;
    USE SIGNAL ;
    PORT
      LAYER M4 ;
        RECT  21.516 40.224 21.6 40.248 ;
    END
  END o[397]
  PIN o[398]
    DIRECTION OUTPUT ;
    USE SIGNAL ;
    PORT
      LAYER M4 ;
        RECT  21.516 40.32 21.6 40.344 ;
    END
  END o[398]
  PIN o[399]
    DIRECTION OUTPUT ;
    USE SIGNAL ;
    PORT
      LAYER M4 ;
        RECT  21.516 40.416 21.6 40.44 ;
    END
  END o[399]
  PIN o[39]
    DIRECTION OUTPUT ;
    USE SIGNAL ;
    PORT
      LAYER M4 ;
        RECT  21.516 4.512 21.6 4.536 ;
    END
  END o[39]
  PIN o[3]
    DIRECTION OUTPUT ;
    USE SIGNAL ;
    PORT
      LAYER M4 ;
        RECT  21.516 0.96 21.6 0.984 ;
    END
  END o[3]
  PIN o[400]
    DIRECTION OUTPUT ;
    USE SIGNAL ;
    PORT
      LAYER M4 ;
        RECT  21.516 40.512 21.6 40.536 ;
    END
  END o[400]
  PIN o[401]
    DIRECTION OUTPUT ;
    USE SIGNAL ;
    PORT
      LAYER M4 ;
        RECT  21.516 40.608 21.6 40.632 ;
    END
  END o[401]
  PIN o[402]
    DIRECTION OUTPUT ;
    USE SIGNAL ;
    PORT
      LAYER M4 ;
        RECT  21.516 40.704 21.6 40.728 ;
    END
  END o[402]
  PIN o[403]
    DIRECTION OUTPUT ;
    USE SIGNAL ;
    PORT
      LAYER M4 ;
        RECT  21.516 40.8 21.6 40.824 ;
    END
  END o[403]
  PIN o[404]
    DIRECTION OUTPUT ;
    USE SIGNAL ;
    PORT
      LAYER M4 ;
        RECT  21.516 40.896 21.6 40.92 ;
    END
  END o[404]
  PIN o[405]
    DIRECTION OUTPUT ;
    USE SIGNAL ;
    PORT
      LAYER M4 ;
        RECT  21.516 40.992 21.6 41.016 ;
    END
  END o[405]
  PIN o[406]
    DIRECTION OUTPUT ;
    USE SIGNAL ;
    PORT
      LAYER M4 ;
        RECT  21.516 41.088 21.6 41.112 ;
    END
  END o[406]
  PIN o[407]
    DIRECTION OUTPUT ;
    USE SIGNAL ;
    PORT
      LAYER M4 ;
        RECT  21.516 41.184 21.6 41.208 ;
    END
  END o[407]
  PIN o[408]
    DIRECTION OUTPUT ;
    USE SIGNAL ;
    PORT
      LAYER M4 ;
        RECT  21.516 41.328 21.6 41.352 ;
    END
  END o[408]
  PIN o[409]
    DIRECTION OUTPUT ;
    USE SIGNAL ;
    PORT
      LAYER M4 ;
        RECT  21.516 41.424 21.6 41.448 ;
    END
  END o[409]
  PIN o[40]
    DIRECTION OUTPUT ;
    USE SIGNAL ;
    PORT
      LAYER M4 ;
        RECT  21.516 4.608 21.6 4.632 ;
    END
  END o[40]
  PIN o[410]
    DIRECTION OUTPUT ;
    USE SIGNAL ;
    PORT
      LAYER M4 ;
        RECT  21.516 41.52 21.6 41.544 ;
    END
  END o[410]
  PIN o[411]
    DIRECTION OUTPUT ;
    USE SIGNAL ;
    PORT
      LAYER M4 ;
        RECT  21.516 41.616 21.6 41.64 ;
    END
  END o[411]
  PIN o[412]
    DIRECTION OUTPUT ;
    USE SIGNAL ;
    PORT
      LAYER M4 ;
        RECT  21.516 41.712 21.6 41.736 ;
    END
  END o[412]
  PIN o[413]
    DIRECTION OUTPUT ;
    USE SIGNAL ;
    PORT
      LAYER M4 ;
        RECT  21.516 41.808 21.6 41.832 ;
    END
  END o[413]
  PIN o[414]
    DIRECTION OUTPUT ;
    USE SIGNAL ;
    PORT
      LAYER M4 ;
        RECT  21.516 41.904 21.6 41.928 ;
    END
  END o[414]
  PIN o[415]
    DIRECTION OUTPUT ;
    USE SIGNAL ;
    PORT
      LAYER M4 ;
        RECT  21.516 42 21.6 42.024 ;
    END
  END o[415]
  PIN o[416]
    DIRECTION OUTPUT ;
    USE SIGNAL ;
    PORT
      LAYER M4 ;
        RECT  21.516 42.096 21.6 42.12 ;
    END
  END o[416]
  PIN o[417]
    DIRECTION OUTPUT ;
    USE SIGNAL ;
    PORT
      LAYER M4 ;
        RECT  21.516 42.192 21.6 42.216 ;
    END
  END o[417]
  PIN o[418]
    DIRECTION OUTPUT ;
    USE SIGNAL ;
    PORT
      LAYER M4 ;
        RECT  21.516 42.288 21.6 42.312 ;
    END
  END o[418]
  PIN o[419]
    DIRECTION OUTPUT ;
    USE SIGNAL ;
    PORT
      LAYER M4 ;
        RECT  21.516 42.384 21.6 42.408 ;
    END
  END o[419]
  PIN o[41]
    DIRECTION OUTPUT ;
    USE SIGNAL ;
    PORT
      LAYER M4 ;
        RECT  21.516 4.704 21.6 4.728 ;
    END
  END o[41]
  PIN o[420]
    DIRECTION OUTPUT ;
    USE SIGNAL ;
    PORT
      LAYER M4 ;
        RECT  21.516 42.48 21.6 42.504 ;
    END
  END o[420]
  PIN o[421]
    DIRECTION OUTPUT ;
    USE SIGNAL ;
    PORT
      LAYER M4 ;
        RECT  21.516 42.624 21.6 42.648 ;
    END
  END o[421]
  PIN o[422]
    DIRECTION OUTPUT ;
    USE SIGNAL ;
    PORT
      LAYER M4 ;
        RECT  21.516 42.72 21.6 42.744 ;
    END
  END o[422]
  PIN o[423]
    DIRECTION OUTPUT ;
    USE SIGNAL ;
    PORT
      LAYER M4 ;
        RECT  21.516 42.816 21.6 42.84 ;
    END
  END o[423]
  PIN o[424]
    DIRECTION OUTPUT ;
    USE SIGNAL ;
    PORT
      LAYER M4 ;
        RECT  21.516 42.912 21.6 42.936 ;
    END
  END o[424]
  PIN o[425]
    DIRECTION OUTPUT ;
    USE SIGNAL ;
    PORT
      LAYER M4 ;
        RECT  21.516 43.008 21.6 43.032 ;
    END
  END o[425]
  PIN o[426]
    DIRECTION OUTPUT ;
    USE SIGNAL ;
    PORT
      LAYER M4 ;
        RECT  21.516 43.104 21.6 43.128 ;
    END
  END o[426]
  PIN o[427]
    DIRECTION OUTPUT ;
    USE SIGNAL ;
    PORT
      LAYER M4 ;
        RECT  21.516 43.2 21.6 43.224 ;
    END
  END o[427]
  PIN o[428]
    DIRECTION OUTPUT ;
    USE SIGNAL ;
    PORT
      LAYER M4 ;
        RECT  21.516 43.296 21.6 43.32 ;
    END
  END o[428]
  PIN o[429]
    DIRECTION OUTPUT ;
    USE SIGNAL ;
    PORT
      LAYER M4 ;
        RECT  21.516 43.392 21.6 43.416 ;
    END
  END o[429]
  PIN o[42]
    DIRECTION OUTPUT ;
    USE SIGNAL ;
    PORT
      LAYER M4 ;
        RECT  21.516 4.848 21.6 4.872 ;
    END
  END o[42]
  PIN o[430]
    DIRECTION OUTPUT ;
    USE SIGNAL ;
    PORT
      LAYER M4 ;
        RECT  21.516 43.488 21.6 43.512 ;
    END
  END o[430]
  PIN o[431]
    DIRECTION OUTPUT ;
    USE SIGNAL ;
    PORT
      LAYER M4 ;
        RECT  21.516 43.584 21.6 43.608 ;
    END
  END o[431]
  PIN o[432]
    DIRECTION OUTPUT ;
    USE SIGNAL ;
    PORT
      LAYER M4 ;
        RECT  21.516 43.68 21.6 43.704 ;
    END
  END o[432]
  PIN o[433]
    DIRECTION OUTPUT ;
    USE SIGNAL ;
    PORT
      LAYER M4 ;
        RECT  21.516 43.776 21.6 43.8 ;
    END
  END o[433]
  PIN o[434]
    DIRECTION OUTPUT ;
    USE SIGNAL ;
    PORT
      LAYER M4 ;
        RECT  21.516 43.92 21.6 43.944 ;
    END
  END o[434]
  PIN o[435]
    DIRECTION OUTPUT ;
    USE SIGNAL ;
    PORT
      LAYER M4 ;
        RECT  21.516 44.016 21.6 44.04 ;
    END
  END o[435]
  PIN o[436]
    DIRECTION OUTPUT ;
    USE SIGNAL ;
    PORT
      LAYER M4 ;
        RECT  21.516 44.112 21.6 44.136 ;
    END
  END o[436]
  PIN o[437]
    DIRECTION OUTPUT ;
    USE SIGNAL ;
    PORT
      LAYER M4 ;
        RECT  21.516 44.208 21.6 44.232 ;
    END
  END o[437]
  PIN o[438]
    DIRECTION OUTPUT ;
    USE SIGNAL ;
    PORT
      LAYER M4 ;
        RECT  21.516 44.304 21.6 44.328 ;
    END
  END o[438]
  PIN o[439]
    DIRECTION OUTPUT ;
    USE SIGNAL ;
    PORT
      LAYER M4 ;
        RECT  21.516 44.4 21.6 44.424 ;
    END
  END o[439]
  PIN o[43]
    DIRECTION OUTPUT ;
    USE SIGNAL ;
    PORT
      LAYER M4 ;
        RECT  21.516 4.944 21.6 4.968 ;
    END
  END o[43]
  PIN o[440]
    DIRECTION OUTPUT ;
    USE SIGNAL ;
    PORT
      LAYER M4 ;
        RECT  21.516 44.496 21.6 44.52 ;
    END
  END o[440]
  PIN o[441]
    DIRECTION OUTPUT ;
    USE SIGNAL ;
    PORT
      LAYER M4 ;
        RECT  21.516 44.592 21.6 44.616 ;
    END
  END o[441]
  PIN o[442]
    DIRECTION OUTPUT ;
    USE SIGNAL ;
    PORT
      LAYER M4 ;
        RECT  21.516 44.688 21.6 44.712 ;
    END
  END o[442]
  PIN o[443]
    DIRECTION OUTPUT ;
    USE SIGNAL ;
    PORT
      LAYER M4 ;
        RECT  21.516 44.784 21.6 44.808 ;
    END
  END o[443]
  PIN o[444]
    DIRECTION OUTPUT ;
    USE SIGNAL ;
    PORT
      LAYER M4 ;
        RECT  21.516 44.88 21.6 44.904 ;
    END
  END o[444]
  PIN o[445]
    DIRECTION OUTPUT ;
    USE SIGNAL ;
    PORT
      LAYER M4 ;
        RECT  21.516 44.976 21.6 45 ;
    END
  END o[445]
  PIN o[446]
    DIRECTION OUTPUT ;
    USE SIGNAL ;
    PORT
      LAYER M4 ;
        RECT  21.516 45.072 21.6 45.096 ;
    END
  END o[446]
  PIN o[447]
    DIRECTION OUTPUT ;
    USE SIGNAL ;
    PORT
      LAYER M4 ;
        RECT  21.516 45.216 21.6 45.24 ;
    END
  END o[447]
  PIN o[448]
    DIRECTION OUTPUT ;
    USE SIGNAL ;
    PORT
      LAYER M4 ;
        RECT  21.516 45.312 21.6 45.336 ;
    END
  END o[448]
  PIN o[449]
    DIRECTION OUTPUT ;
    USE SIGNAL ;
    PORT
      LAYER M4 ;
        RECT  21.516 45.408 21.6 45.432 ;
    END
  END o[449]
  PIN o[44]
    DIRECTION OUTPUT ;
    USE SIGNAL ;
    PORT
      LAYER M4 ;
        RECT  21.516 5.04 21.6 5.064 ;
    END
  END o[44]
  PIN o[450]
    DIRECTION OUTPUT ;
    USE SIGNAL ;
    PORT
      LAYER M4 ;
        RECT  21.516 45.504 21.6 45.528 ;
    END
  END o[450]
  PIN o[451]
    DIRECTION OUTPUT ;
    USE SIGNAL ;
    PORT
      LAYER M4 ;
        RECT  21.516 45.6 21.6 45.624 ;
    END
  END o[451]
  PIN o[452]
    DIRECTION OUTPUT ;
    USE SIGNAL ;
    PORT
      LAYER M4 ;
        RECT  21.516 45.696 21.6 45.72 ;
    END
  END o[452]
  PIN o[453]
    DIRECTION OUTPUT ;
    USE SIGNAL ;
    PORT
      LAYER M4 ;
        RECT  21.516 45.792 21.6 45.816 ;
    END
  END o[453]
  PIN o[454]
    DIRECTION OUTPUT ;
    USE SIGNAL ;
    PORT
      LAYER M4 ;
        RECT  21.516 45.888 21.6 45.912 ;
    END
  END o[454]
  PIN o[455]
    DIRECTION OUTPUT ;
    USE SIGNAL ;
    PORT
      LAYER M4 ;
        RECT  21.516 45.984 21.6 46.008 ;
    END
  END o[455]
  PIN o[456]
    DIRECTION OUTPUT ;
    USE SIGNAL ;
    PORT
      LAYER M4 ;
        RECT  21.516 46.08 21.6 46.104 ;
    END
  END o[456]
  PIN o[457]
    DIRECTION OUTPUT ;
    USE SIGNAL ;
    PORT
      LAYER M4 ;
        RECT  21.516 46.176 21.6 46.2 ;
    END
  END o[457]
  PIN o[458]
    DIRECTION OUTPUT ;
    USE SIGNAL ;
    PORT
      LAYER M4 ;
        RECT  21.516 46.272 21.6 46.296 ;
    END
  END o[458]
  PIN o[459]
    DIRECTION OUTPUT ;
    USE SIGNAL ;
    PORT
      LAYER M4 ;
        RECT  21.516 46.368 21.6 46.392 ;
    END
  END o[459]
  PIN o[45]
    DIRECTION OUTPUT ;
    USE SIGNAL ;
    PORT
      LAYER M4 ;
        RECT  21.516 5.136 21.6 5.16 ;
    END
  END o[45]
  PIN o[460]
    DIRECTION OUTPUT ;
    USE SIGNAL ;
    PORT
      LAYER M4 ;
        RECT  21.516 46.512 21.6 46.536 ;
    END
  END o[460]
  PIN o[461]
    DIRECTION OUTPUT ;
    USE SIGNAL ;
    PORT
      LAYER M4 ;
        RECT  21.516 46.608 21.6 46.632 ;
    END
  END o[461]
  PIN o[462]
    DIRECTION OUTPUT ;
    USE SIGNAL ;
    PORT
      LAYER M4 ;
        RECT  21.516 46.704 21.6 46.728 ;
    END
  END o[462]
  PIN o[463]
    DIRECTION OUTPUT ;
    USE SIGNAL ;
    PORT
      LAYER M4 ;
        RECT  21.516 46.8 21.6 46.824 ;
    END
  END o[463]
  PIN o[464]
    DIRECTION OUTPUT ;
    USE SIGNAL ;
    PORT
      LAYER M4 ;
        RECT  21.516 46.896 21.6 46.92 ;
    END
  END o[464]
  PIN o[465]
    DIRECTION OUTPUT ;
    USE SIGNAL ;
    PORT
      LAYER M4 ;
        RECT  21.516 46.992 21.6 47.016 ;
    END
  END o[465]
  PIN o[466]
    DIRECTION OUTPUT ;
    USE SIGNAL ;
    PORT
      LAYER M4 ;
        RECT  21.516 47.088 21.6 47.112 ;
    END
  END o[466]
  PIN o[467]
    DIRECTION OUTPUT ;
    USE SIGNAL ;
    PORT
      LAYER M4 ;
        RECT  21.516 47.184 21.6 47.208 ;
    END
  END o[467]
  PIN o[468]
    DIRECTION OUTPUT ;
    USE SIGNAL ;
    PORT
      LAYER M4 ;
        RECT  21.516 47.28 21.6 47.304 ;
    END
  END o[468]
  PIN o[469]
    DIRECTION OUTPUT ;
    USE SIGNAL ;
    PORT
      LAYER M4 ;
        RECT  21.516 47.376 21.6 47.4 ;
    END
  END o[469]
  PIN o[46]
    DIRECTION OUTPUT ;
    USE SIGNAL ;
    PORT
      LAYER M4 ;
        RECT  21.516 5.232 21.6 5.256 ;
    END
  END o[46]
  PIN o[470]
    DIRECTION OUTPUT ;
    USE SIGNAL ;
    PORT
      LAYER M4 ;
        RECT  21.516 47.472 21.6 47.496 ;
    END
  END o[470]
  PIN o[471]
    DIRECTION OUTPUT ;
    USE SIGNAL ;
    PORT
      LAYER M4 ;
        RECT  21.516 47.568 21.6 47.592 ;
    END
  END o[471]
  PIN o[472]
    DIRECTION OUTPUT ;
    USE SIGNAL ;
    PORT
      LAYER M4 ;
        RECT  21.516 47.664 21.6 47.688 ;
    END
  END o[472]
  PIN o[473]
    DIRECTION OUTPUT ;
    USE SIGNAL ;
    PORT
      LAYER M4 ;
        RECT  21.516 47.808 21.6 47.832 ;
    END
  END o[473]
  PIN o[474]
    DIRECTION OUTPUT ;
    USE SIGNAL ;
    PORT
      LAYER M4 ;
        RECT  21.516 47.904 21.6 47.928 ;
    END
  END o[474]
  PIN o[475]
    DIRECTION OUTPUT ;
    USE SIGNAL ;
    PORT
      LAYER M4 ;
        RECT  21.516 48 21.6 48.024 ;
    END
  END o[475]
  PIN o[476]
    DIRECTION OUTPUT ;
    USE SIGNAL ;
    PORT
      LAYER M4 ;
        RECT  21.516 48.096 21.6 48.12 ;
    END
  END o[476]
  PIN o[477]
    DIRECTION OUTPUT ;
    USE SIGNAL ;
    PORT
      LAYER M4 ;
        RECT  21.516 48.192 21.6 48.216 ;
    END
  END o[477]
  PIN o[478]
    DIRECTION OUTPUT ;
    USE SIGNAL ;
    PORT
      LAYER M4 ;
        RECT  21.516 48.288 21.6 48.312 ;
    END
  END o[478]
  PIN o[479]
    DIRECTION OUTPUT ;
    USE SIGNAL ;
    PORT
      LAYER M4 ;
        RECT  21.516 48.384 21.6 48.408 ;
    END
  END o[479]
  PIN o[47]
    DIRECTION OUTPUT ;
    USE SIGNAL ;
    PORT
      LAYER M4 ;
        RECT  21.516 5.328 21.6 5.352 ;
    END
  END o[47]
  PIN o[480]
    DIRECTION OUTPUT ;
    USE SIGNAL ;
    PORT
      LAYER M4 ;
        RECT  21.516 48.48 21.6 48.504 ;
    END
  END o[480]
  PIN o[481]
    DIRECTION OUTPUT ;
    USE SIGNAL ;
    PORT
      LAYER M4 ;
        RECT  21.516 48.576 21.6 48.6 ;
    END
  END o[481]
  PIN o[482]
    DIRECTION OUTPUT ;
    USE SIGNAL ;
    PORT
      LAYER M4 ;
        RECT  21.516 48.672 21.6 48.696 ;
    END
  END o[482]
  PIN o[483]
    DIRECTION OUTPUT ;
    USE SIGNAL ;
    PORT
      LAYER M4 ;
        RECT  21.516 48.768 21.6 48.792 ;
    END
  END o[483]
  PIN o[484]
    DIRECTION OUTPUT ;
    USE SIGNAL ;
    PORT
      LAYER M4 ;
        RECT  21.516 48.864 21.6 48.888 ;
    END
  END o[484]
  PIN o[485]
    DIRECTION OUTPUT ;
    USE SIGNAL ;
    PORT
      LAYER M4 ;
        RECT  21.516 48.96 21.6 48.984 ;
    END
  END o[485]
  PIN o[486]
    DIRECTION OUTPUT ;
    USE SIGNAL ;
    PORT
      LAYER M4 ;
        RECT  21.516 49.104 21.6 49.128 ;
    END
  END o[486]
  PIN o[487]
    DIRECTION OUTPUT ;
    USE SIGNAL ;
    PORT
      LAYER M4 ;
        RECT  21.516 49.2 21.6 49.224 ;
    END
  END o[487]
  PIN o[488]
    DIRECTION OUTPUT ;
    USE SIGNAL ;
    PORT
      LAYER M4 ;
        RECT  21.516 49.296 21.6 49.32 ;
    END
  END o[488]
  PIN o[489]
    DIRECTION OUTPUT ;
    USE SIGNAL ;
    PORT
      LAYER M4 ;
        RECT  21.516 49.392 21.6 49.416 ;
    END
  END o[489]
  PIN o[48]
    DIRECTION OUTPUT ;
    USE SIGNAL ;
    PORT
      LAYER M4 ;
        RECT  21.516 5.424 21.6 5.448 ;
    END
  END o[48]
  PIN o[490]
    DIRECTION OUTPUT ;
    USE SIGNAL ;
    PORT
      LAYER M4 ;
        RECT  21.516 49.488 21.6 49.512 ;
    END
  END o[490]
  PIN o[491]
    DIRECTION OUTPUT ;
    USE SIGNAL ;
    PORT
      LAYER M4 ;
        RECT  21.516 49.584 21.6 49.608 ;
    END
  END o[491]
  PIN o[492]
    DIRECTION OUTPUT ;
    USE SIGNAL ;
    PORT
      LAYER M4 ;
        RECT  21.516 49.68 21.6 49.704 ;
    END
  END o[492]
  PIN o[493]
    DIRECTION OUTPUT ;
    USE SIGNAL ;
    PORT
      LAYER M4 ;
        RECT  21.516 49.776 21.6 49.8 ;
    END
  END o[493]
  PIN o[494]
    DIRECTION OUTPUT ;
    USE SIGNAL ;
    PORT
      LAYER M4 ;
        RECT  21.516 49.872 21.6 49.896 ;
    END
  END o[494]
  PIN o[495]
    DIRECTION OUTPUT ;
    USE SIGNAL ;
    PORT
      LAYER M4 ;
        RECT  21.516 49.968 21.6 49.992 ;
    END
  END o[495]
  PIN o[496]
    DIRECTION OUTPUT ;
    USE SIGNAL ;
    PORT
      LAYER M4 ;
        RECT  21.516 50.064 21.6 50.088 ;
    END
  END o[496]
  PIN o[497]
    DIRECTION OUTPUT ;
    USE SIGNAL ;
    PORT
      LAYER M4 ;
        RECT  21.516 50.16 21.6 50.184 ;
    END
  END o[497]
  PIN o[498]
    DIRECTION OUTPUT ;
    USE SIGNAL ;
    PORT
      LAYER M4 ;
        RECT  21.516 50.256 21.6 50.28 ;
    END
  END o[498]
  PIN o[499]
    DIRECTION OUTPUT ;
    USE SIGNAL ;
    PORT
      LAYER M4 ;
        RECT  21.516 50.4 21.6 50.424 ;
    END
  END o[499]
  PIN o[49]
    DIRECTION OUTPUT ;
    USE SIGNAL ;
    PORT
      LAYER M4 ;
        RECT  21.516 5.52 21.6 5.544 ;
    END
  END o[49]
  PIN o[4]
    DIRECTION OUTPUT ;
    USE SIGNAL ;
    PORT
      LAYER M4 ;
        RECT  21.516 1.056 21.6 1.08 ;
    END
  END o[4]
  PIN o[500]
    DIRECTION OUTPUT ;
    USE SIGNAL ;
    PORT
      LAYER M4 ;
        RECT  21.516 50.496 21.6 50.52 ;
    END
  END o[500]
  PIN o[501]
    DIRECTION OUTPUT ;
    USE SIGNAL ;
    PORT
      LAYER M4 ;
        RECT  21.516 50.592 21.6 50.616 ;
    END
  END o[501]
  PIN o[502]
    DIRECTION OUTPUT ;
    USE SIGNAL ;
    PORT
      LAYER M4 ;
        RECT  21.516 50.688 21.6 50.712 ;
    END
  END o[502]
  PIN o[503]
    DIRECTION OUTPUT ;
    USE SIGNAL ;
    PORT
      LAYER M4 ;
        RECT  21.516 50.784 21.6 50.808 ;
    END
  END o[503]
  PIN o[504]
    DIRECTION OUTPUT ;
    USE SIGNAL ;
    PORT
      LAYER M4 ;
        RECT  21.516 50.88 21.6 50.904 ;
    END
  END o[504]
  PIN o[505]
    DIRECTION OUTPUT ;
    USE SIGNAL ;
    PORT
      LAYER M4 ;
        RECT  21.516 50.976 21.6 51 ;
    END
  END o[505]
  PIN o[506]
    DIRECTION OUTPUT ;
    USE SIGNAL ;
    PORT
      LAYER M4 ;
        RECT  21.516 51.072 21.6 51.096 ;
    END
  END o[506]
  PIN o[507]
    DIRECTION OUTPUT ;
    USE SIGNAL ;
    PORT
      LAYER M4 ;
        RECT  21.516 51.168 21.6 51.192 ;
    END
  END o[507]
  PIN o[508]
    DIRECTION OUTPUT ;
    USE SIGNAL ;
    PORT
      LAYER M4 ;
        RECT  21.516 51.264 21.6 51.288 ;
    END
  END o[508]
  PIN o[509]
    DIRECTION OUTPUT ;
    USE SIGNAL ;
    PORT
      LAYER M4 ;
        RECT  21.516 51.36 21.6 51.384 ;
    END
  END o[509]
  PIN o[50]
    DIRECTION OUTPUT ;
    USE SIGNAL ;
    PORT
      LAYER M4 ;
        RECT  21.516 5.616 21.6 5.64 ;
    END
  END o[50]
  PIN o[510]
    DIRECTION OUTPUT ;
    USE SIGNAL ;
    PORT
      LAYER M4 ;
        RECT  21.516 51.456 21.6 51.48 ;
    END
  END o[510]
  PIN o[511]
    DIRECTION OUTPUT ;
    USE SIGNAL ;
    PORT
      LAYER M4 ;
        RECT  21.516 51.552 21.6 51.576 ;
    END
  END o[511]
  PIN o[512]
    DIRECTION OUTPUT ;
    USE SIGNAL ;
    PORT
      LAYER M4 ;
        RECT  21.516 51.696 21.6 51.72 ;
    END
  END o[512]
  PIN o[513]
    DIRECTION OUTPUT ;
    USE SIGNAL ;
    PORT
      LAYER M4 ;
        RECT  21.516 51.792 21.6 51.816 ;
    END
  END o[513]
  PIN o[514]
    DIRECTION OUTPUT ;
    USE SIGNAL ;
    PORT
      LAYER M4 ;
        RECT  21.516 51.888 21.6 51.912 ;
    END
  END o[514]
  PIN o[515]
    DIRECTION OUTPUT ;
    USE SIGNAL ;
    PORT
      LAYER M4 ;
        RECT  21.516 51.984 21.6 52.008 ;
    END
  END o[515]
  PIN o[516]
    DIRECTION OUTPUT ;
    USE SIGNAL ;
    PORT
      LAYER M4 ;
        RECT  21.516 52.08 21.6 52.104 ;
    END
  END o[516]
  PIN o[517]
    DIRECTION OUTPUT ;
    USE SIGNAL ;
    PORT
      LAYER M4 ;
        RECT  21.516 52.176 21.6 52.2 ;
    END
  END o[517]
  PIN o[518]
    DIRECTION OUTPUT ;
    USE SIGNAL ;
    PORT
      LAYER M4 ;
        RECT  21.516 52.272 21.6 52.296 ;
    END
  END o[518]
  PIN o[519]
    DIRECTION OUTPUT ;
    USE SIGNAL ;
    PORT
      LAYER M4 ;
        RECT  21.516 52.368 21.6 52.392 ;
    END
  END o[519]
  PIN o[51]
    DIRECTION OUTPUT ;
    USE SIGNAL ;
    PORT
      LAYER M4 ;
        RECT  21.516 5.712 21.6 5.736 ;
    END
  END o[51]
  PIN o[520]
    DIRECTION OUTPUT ;
    USE SIGNAL ;
    PORT
      LAYER M4 ;
        RECT  21.516 52.464 21.6 52.488 ;
    END
  END o[520]
  PIN o[521]
    DIRECTION OUTPUT ;
    USE SIGNAL ;
    PORT
      LAYER M4 ;
        RECT  21.516 52.56 21.6 52.584 ;
    END
  END o[521]
  PIN o[522]
    DIRECTION OUTPUT ;
    USE SIGNAL ;
    PORT
      LAYER M4 ;
        RECT  21.516 52.656 21.6 52.68 ;
    END
  END o[522]
  PIN o[523]
    DIRECTION OUTPUT ;
    USE SIGNAL ;
    PORT
      LAYER M4 ;
        RECT  21.516 52.752 21.6 52.776 ;
    END
  END o[523]
  PIN o[524]
    DIRECTION OUTPUT ;
    USE SIGNAL ;
    PORT
      LAYER M4 ;
        RECT  21.516 52.848 21.6 52.872 ;
    END
  END o[524]
  PIN o[525]
    DIRECTION OUTPUT ;
    USE SIGNAL ;
    PORT
      LAYER M4 ;
        RECT  21.516 52.992 21.6 53.016 ;
    END
  END o[525]
  PIN o[526]
    DIRECTION OUTPUT ;
    USE SIGNAL ;
    PORT
      LAYER M4 ;
        RECT  21.516 53.088 21.6 53.112 ;
    END
  END o[526]
  PIN o[527]
    DIRECTION OUTPUT ;
    USE SIGNAL ;
    PORT
      LAYER M4 ;
        RECT  21.516 53.184 21.6 53.208 ;
    END
  END o[527]
  PIN o[528]
    DIRECTION OUTPUT ;
    USE SIGNAL ;
    PORT
      LAYER M4 ;
        RECT  21.516 53.28 21.6 53.304 ;
    END
  END o[528]
  PIN o[529]
    DIRECTION OUTPUT ;
    USE SIGNAL ;
    PORT
      LAYER M4 ;
        RECT  21.516 53.376 21.6 53.4 ;
    END
  END o[529]
  PIN o[52]
    DIRECTION OUTPUT ;
    USE SIGNAL ;
    PORT
      LAYER M4 ;
        RECT  21.516 5.808 21.6 5.832 ;
    END
  END o[52]
  PIN o[530]
    DIRECTION OUTPUT ;
    USE SIGNAL ;
    PORT
      LAYER M4 ;
        RECT  21.516 53.472 21.6 53.496 ;
    END
  END o[530]
  PIN o[531]
    DIRECTION OUTPUT ;
    USE SIGNAL ;
    PORT
      LAYER M4 ;
        RECT  21.516 53.568 21.6 53.592 ;
    END
  END o[531]
  PIN o[532]
    DIRECTION OUTPUT ;
    USE SIGNAL ;
    PORT
      LAYER M4 ;
        RECT  21.516 53.664 21.6 53.688 ;
    END
  END o[532]
  PIN o[533]
    DIRECTION OUTPUT ;
    USE SIGNAL ;
    PORT
      LAYER M4 ;
        RECT  21.516 53.76 21.6 53.784 ;
    END
  END o[533]
  PIN o[534]
    DIRECTION OUTPUT ;
    USE SIGNAL ;
    PORT
      LAYER M4 ;
        RECT  21.516 53.856 21.6 53.88 ;
    END
  END o[534]
  PIN o[535]
    DIRECTION OUTPUT ;
    USE SIGNAL ;
    PORT
      LAYER M4 ;
        RECT  21.516 53.952 21.6 53.976 ;
    END
  END o[535]
  PIN o[536]
    DIRECTION OUTPUT ;
    USE SIGNAL ;
    PORT
      LAYER M4 ;
        RECT  21.516 54.048 21.6 54.072 ;
    END
  END o[536]
  PIN o[537]
    DIRECTION OUTPUT ;
    USE SIGNAL ;
    PORT
      LAYER M4 ;
        RECT  21.516 54.144 21.6 54.168 ;
    END
  END o[537]
  PIN o[538]
    DIRECTION OUTPUT ;
    USE SIGNAL ;
    PORT
      LAYER M4 ;
        RECT  21.516 54.288 21.6 54.312 ;
    END
  END o[538]
  PIN o[539]
    DIRECTION OUTPUT ;
    USE SIGNAL ;
    PORT
      LAYER M4 ;
        RECT  21.516 54.384 21.6 54.408 ;
    END
  END o[539]
  PIN o[53]
    DIRECTION OUTPUT ;
    USE SIGNAL ;
    PORT
      LAYER M4 ;
        RECT  21.516 5.904 21.6 5.928 ;
    END
  END o[53]
  PIN o[540]
    DIRECTION OUTPUT ;
    USE SIGNAL ;
    PORT
      LAYER M4 ;
        RECT  21.516 54.48 21.6 54.504 ;
    END
  END o[540]
  PIN o[541]
    DIRECTION OUTPUT ;
    USE SIGNAL ;
    PORT
      LAYER M4 ;
        RECT  21.516 54.576 21.6 54.6 ;
    END
  END o[541]
  PIN o[542]
    DIRECTION OUTPUT ;
    USE SIGNAL ;
    PORT
      LAYER M4 ;
        RECT  21.516 54.672 21.6 54.696 ;
    END
  END o[542]
  PIN o[543]
    DIRECTION OUTPUT ;
    USE SIGNAL ;
    PORT
      LAYER M4 ;
        RECT  21.516 54.768 21.6 54.792 ;
    END
  END o[543]
  PIN o[544]
    DIRECTION OUTPUT ;
    USE SIGNAL ;
    PORT
      LAYER M4 ;
        RECT  21.516 54.864 21.6 54.888 ;
    END
  END o[544]
  PIN o[545]
    DIRECTION OUTPUT ;
    USE SIGNAL ;
    PORT
      LAYER M4 ;
        RECT  21.516 54.96 21.6 54.984 ;
    END
  END o[545]
  PIN o[546]
    DIRECTION OUTPUT ;
    USE SIGNAL ;
    PORT
      LAYER M4 ;
        RECT  21.516 55.056 21.6 55.08 ;
    END
  END o[546]
  PIN o[547]
    DIRECTION OUTPUT ;
    USE SIGNAL ;
    PORT
      LAYER M4 ;
        RECT  21.516 55.152 21.6 55.176 ;
    END
  END o[547]
  PIN o[548]
    DIRECTION OUTPUT ;
    USE SIGNAL ;
    PORT
      LAYER M4 ;
        RECT  21.516 55.248 21.6 55.272 ;
    END
  END o[548]
  PIN o[549]
    DIRECTION OUTPUT ;
    USE SIGNAL ;
    PORT
      LAYER M4 ;
        RECT  21.516 55.344 21.6 55.368 ;
    END
  END o[549]
  PIN o[54]
    DIRECTION OUTPUT ;
    USE SIGNAL ;
    PORT
      LAYER M4 ;
        RECT  21.516 6 21.6 6.024 ;
    END
  END o[54]
  PIN o[550]
    DIRECTION OUTPUT ;
    USE SIGNAL ;
    PORT
      LAYER M4 ;
        RECT  21.516 55.44 21.6 55.464 ;
    END
  END o[550]
  PIN o[551]
    DIRECTION OUTPUT ;
    USE SIGNAL ;
    PORT
      LAYER M4 ;
        RECT  21.516 55.584 21.6 55.608 ;
    END
  END o[551]
  PIN o[552]
    DIRECTION OUTPUT ;
    USE SIGNAL ;
    PORT
      LAYER M4 ;
        RECT  21.516 55.68 21.6 55.704 ;
    END
  END o[552]
  PIN o[553]
    DIRECTION OUTPUT ;
    USE SIGNAL ;
    PORT
      LAYER M4 ;
        RECT  21.516 55.776 21.6 55.8 ;
    END
  END o[553]
  PIN o[554]
    DIRECTION OUTPUT ;
    USE SIGNAL ;
    PORT
      LAYER M4 ;
        RECT  21.516 55.872 21.6 55.896 ;
    END
  END o[554]
  PIN o[555]
    DIRECTION OUTPUT ;
    USE SIGNAL ;
    PORT
      LAYER M4 ;
        RECT  21.516 55.968 21.6 55.992 ;
    END
  END o[555]
  PIN o[556]
    DIRECTION OUTPUT ;
    USE SIGNAL ;
    PORT
      LAYER M4 ;
        RECT  21.516 56.064 21.6 56.088 ;
    END
  END o[556]
  PIN o[557]
    DIRECTION OUTPUT ;
    USE SIGNAL ;
    PORT
      LAYER M4 ;
        RECT  21.516 56.16 21.6 56.184 ;
    END
  END o[557]
  PIN o[558]
    DIRECTION OUTPUT ;
    USE SIGNAL ;
    PORT
      LAYER M4 ;
        RECT  21.516 56.256 21.6 56.28 ;
    END
  END o[558]
  PIN o[559]
    DIRECTION OUTPUT ;
    USE SIGNAL ;
    PORT
      LAYER M4 ;
        RECT  21.516 56.352 21.6 56.376 ;
    END
  END o[559]
  PIN o[55]
    DIRECTION OUTPUT ;
    USE SIGNAL ;
    PORT
      LAYER M4 ;
        RECT  21.516 6.144 21.6 6.168 ;
    END
  END o[55]
  PIN o[560]
    DIRECTION OUTPUT ;
    USE SIGNAL ;
    PORT
      LAYER M4 ;
        RECT  21.516 56.448 21.6 56.472 ;
    END
  END o[560]
  PIN o[561]
    DIRECTION OUTPUT ;
    USE SIGNAL ;
    PORT
      LAYER M4 ;
        RECT  21.516 56.544 21.6 56.568 ;
    END
  END o[561]
  PIN o[562]
    DIRECTION OUTPUT ;
    USE SIGNAL ;
    PORT
      LAYER M4 ;
        RECT  21.516 56.64 21.6 56.664 ;
    END
  END o[562]
  PIN o[563]
    DIRECTION OUTPUT ;
    USE SIGNAL ;
    PORT
      LAYER M4 ;
        RECT  21.516 56.736 21.6 56.76 ;
    END
  END o[563]
  PIN o[564]
    DIRECTION OUTPUT ;
    USE SIGNAL ;
    PORT
      LAYER M4 ;
        RECT  21.516 56.88 21.6 56.904 ;
    END
  END o[564]
  PIN o[565]
    DIRECTION OUTPUT ;
    USE SIGNAL ;
    PORT
      LAYER M4 ;
        RECT  21.516 56.976 21.6 57 ;
    END
  END o[565]
  PIN o[566]
    DIRECTION OUTPUT ;
    USE SIGNAL ;
    PORT
      LAYER M4 ;
        RECT  21.516 57.072 21.6 57.096 ;
    END
  END o[566]
  PIN o[567]
    DIRECTION OUTPUT ;
    USE SIGNAL ;
    PORT
      LAYER M4 ;
        RECT  21.516 57.168 21.6 57.192 ;
    END
  END o[567]
  PIN o[568]
    DIRECTION OUTPUT ;
    USE SIGNAL ;
    PORT
      LAYER M4 ;
        RECT  21.516 57.264 21.6 57.288 ;
    END
  END o[568]
  PIN o[569]
    DIRECTION OUTPUT ;
    USE SIGNAL ;
    PORT
      LAYER M4 ;
        RECT  21.516 57.36 21.6 57.384 ;
    END
  END o[569]
  PIN o[56]
    DIRECTION OUTPUT ;
    USE SIGNAL ;
    PORT
      LAYER M4 ;
        RECT  21.516 6.24 21.6 6.264 ;
    END
  END o[56]
  PIN o[570]
    DIRECTION OUTPUT ;
    USE SIGNAL ;
    PORT
      LAYER M4 ;
        RECT  21.516 57.456 21.6 57.48 ;
    END
  END o[570]
  PIN o[571]
    DIRECTION OUTPUT ;
    USE SIGNAL ;
    PORT
      LAYER M4 ;
        RECT  21.516 57.552 21.6 57.576 ;
    END
  END o[571]
  PIN o[572]
    DIRECTION OUTPUT ;
    USE SIGNAL ;
    PORT
      LAYER M4 ;
        RECT  21.516 57.648 21.6 57.672 ;
    END
  END o[572]
  PIN o[573]
    DIRECTION OUTPUT ;
    USE SIGNAL ;
    PORT
      LAYER M4 ;
        RECT  21.516 57.744 21.6 57.768 ;
    END
  END o[573]
  PIN o[574]
    DIRECTION OUTPUT ;
    USE SIGNAL ;
    PORT
      LAYER M4 ;
        RECT  21.516 57.84 21.6 57.864 ;
    END
  END o[574]
  PIN o[575]
    DIRECTION OUTPUT ;
    USE SIGNAL ;
    PORT
      LAYER M4 ;
        RECT  21.516 57.936 21.6 57.96 ;
    END
  END o[575]
  PIN o[576]
    DIRECTION OUTPUT ;
    USE SIGNAL ;
    PORT
      LAYER M4 ;
        RECT  21.516 58.032 21.6 58.056 ;
    END
  END o[576]
  PIN o[577]
    DIRECTION OUTPUT ;
    USE SIGNAL ;
    PORT
      LAYER M4 ;
        RECT  21.516 58.176 21.6 58.2 ;
    END
  END o[577]
  PIN o[578]
    DIRECTION OUTPUT ;
    USE SIGNAL ;
    PORT
      LAYER M4 ;
        RECT  21.516 58.272 21.6 58.296 ;
    END
  END o[578]
  PIN o[579]
    DIRECTION OUTPUT ;
    USE SIGNAL ;
    PORT
      LAYER M4 ;
        RECT  21.516 58.368 21.6 58.392 ;
    END
  END o[579]
  PIN o[57]
    DIRECTION OUTPUT ;
    USE SIGNAL ;
    PORT
      LAYER M4 ;
        RECT  21.516 6.336 21.6 6.36 ;
    END
  END o[57]
  PIN o[580]
    DIRECTION OUTPUT ;
    USE SIGNAL ;
    PORT
      LAYER M4 ;
        RECT  21.516 58.464 21.6 58.488 ;
    END
  END o[580]
  PIN o[581]
    DIRECTION OUTPUT ;
    USE SIGNAL ;
    PORT
      LAYER M4 ;
        RECT  21.516 58.56 21.6 58.584 ;
    END
  END o[581]
  PIN o[582]
    DIRECTION OUTPUT ;
    USE SIGNAL ;
    PORT
      LAYER M4 ;
        RECT  21.516 58.656 21.6 58.68 ;
    END
  END o[582]
  PIN o[583]
    DIRECTION OUTPUT ;
    USE SIGNAL ;
    PORT
      LAYER M4 ;
        RECT  21.516 58.752 21.6 58.776 ;
    END
  END o[583]
  PIN o[584]
    DIRECTION OUTPUT ;
    USE SIGNAL ;
    PORT
      LAYER M4 ;
        RECT  21.516 58.848 21.6 58.872 ;
    END
  END o[584]
  PIN o[585]
    DIRECTION OUTPUT ;
    USE SIGNAL ;
    PORT
      LAYER M4 ;
        RECT  21.516 58.944 21.6 58.968 ;
    END
  END o[585]
  PIN o[586]
    DIRECTION OUTPUT ;
    USE SIGNAL ;
    PORT
      LAYER M4 ;
        RECT  21.516 59.04 21.6 59.064 ;
    END
  END o[586]
  PIN o[587]
    DIRECTION OUTPUT ;
    USE SIGNAL ;
    PORT
      LAYER M4 ;
        RECT  21.516 59.136 21.6 59.16 ;
    END
  END o[587]
  PIN o[588]
    DIRECTION OUTPUT ;
    USE SIGNAL ;
    PORT
      LAYER M4 ;
        RECT  21.516 59.232 21.6 59.256 ;
    END
  END o[588]
  PIN o[589]
    DIRECTION OUTPUT ;
    USE SIGNAL ;
    PORT
      LAYER M4 ;
        RECT  21.516 59.328 21.6 59.352 ;
    END
  END o[589]
  PIN o[58]
    DIRECTION OUTPUT ;
    USE SIGNAL ;
    PORT
      LAYER M4 ;
        RECT  21.516 6.432 21.6 6.456 ;
    END
  END o[58]
  PIN o[590]
    DIRECTION OUTPUT ;
    USE SIGNAL ;
    PORT
      LAYER M4 ;
        RECT  21.516 59.472 21.6 59.496 ;
    END
  END o[590]
  PIN o[591]
    DIRECTION OUTPUT ;
    USE SIGNAL ;
    PORT
      LAYER M4 ;
        RECT  21.516 59.568 21.6 59.592 ;
    END
  END o[591]
  PIN o[592]
    DIRECTION OUTPUT ;
    USE SIGNAL ;
    PORT
      LAYER M4 ;
        RECT  21.516 59.664 21.6 59.688 ;
    END
  END o[592]
  PIN o[593]
    DIRECTION OUTPUT ;
    USE SIGNAL ;
    PORT
      LAYER M4 ;
        RECT  21.516 59.76 21.6 59.784 ;
    END
  END o[593]
  PIN o[594]
    DIRECTION OUTPUT ;
    USE SIGNAL ;
    PORT
      LAYER M4 ;
        RECT  21.516 59.856 21.6 59.88 ;
    END
  END o[594]
  PIN o[595]
    DIRECTION OUTPUT ;
    USE SIGNAL ;
    PORT
      LAYER M4 ;
        RECT  21.516 59.952 21.6 59.976 ;
    END
  END o[595]
  PIN o[596]
    DIRECTION OUTPUT ;
    USE SIGNAL ;
    PORT
      LAYER M4 ;
        RECT  21.516 60.048 21.6 60.072 ;
    END
  END o[596]
  PIN o[597]
    DIRECTION OUTPUT ;
    USE SIGNAL ;
    PORT
      LAYER M4 ;
        RECT  21.516 60.144 21.6 60.168 ;
    END
  END o[597]
  PIN o[598]
    DIRECTION OUTPUT ;
    USE SIGNAL ;
    PORT
      LAYER M4 ;
        RECT  21.516 60.24 21.6 60.264 ;
    END
  END o[598]
  PIN o[599]
    DIRECTION OUTPUT ;
    USE SIGNAL ;
    PORT
      LAYER M4 ;
        RECT  21.516 60.336 21.6 60.36 ;
    END
  END o[599]
  PIN o[59]
    DIRECTION OUTPUT ;
    USE SIGNAL ;
    PORT
      LAYER M4 ;
        RECT  21.516 6.528 21.6 6.552 ;
    END
  END o[59]
  PIN o[5]
    DIRECTION OUTPUT ;
    USE SIGNAL ;
    PORT
      LAYER M4 ;
        RECT  21.516 1.152 21.6 1.176 ;
    END
  END o[5]
  PIN o[600]
    DIRECTION OUTPUT ;
    USE SIGNAL ;
    PORT
      LAYER M4 ;
        RECT  21.516 60.432 21.6 60.456 ;
    END
  END o[600]
  PIN o[601]
    DIRECTION OUTPUT ;
    USE SIGNAL ;
    PORT
      LAYER M4 ;
        RECT  21.516 60.528 21.6 60.552 ;
    END
  END o[601]
  PIN o[602]
    DIRECTION OUTPUT ;
    USE SIGNAL ;
    PORT
      LAYER M4 ;
        RECT  21.516 60.624 21.6 60.648 ;
    END
  END o[602]
  PIN o[603]
    DIRECTION OUTPUT ;
    USE SIGNAL ;
    PORT
      LAYER M4 ;
        RECT  21.516 60.768 21.6 60.792 ;
    END
  END o[603]
  PIN o[604]
    DIRECTION OUTPUT ;
    USE SIGNAL ;
    PORT
      LAYER M4 ;
        RECT  21.516 60.864 21.6 60.888 ;
    END
  END o[604]
  PIN o[605]
    DIRECTION OUTPUT ;
    USE SIGNAL ;
    PORT
      LAYER M4 ;
        RECT  21.516 60.96 21.6 60.984 ;
    END
  END o[605]
  PIN o[606]
    DIRECTION OUTPUT ;
    USE SIGNAL ;
    PORT
      LAYER M4 ;
        RECT  21.516 61.056 21.6 61.08 ;
    END
  END o[606]
  PIN o[607]
    DIRECTION OUTPUT ;
    USE SIGNAL ;
    PORT
      LAYER M4 ;
        RECT  21.516 61.152 21.6 61.176 ;
    END
  END o[607]
  PIN o[608]
    DIRECTION OUTPUT ;
    USE SIGNAL ;
    PORT
      LAYER M4 ;
        RECT  21.516 61.248 21.6 61.272 ;
    END
  END o[608]
  PIN o[609]
    DIRECTION OUTPUT ;
    USE SIGNAL ;
    PORT
      LAYER M4 ;
        RECT  21.516 61.344 21.6 61.368 ;
    END
  END o[609]
  PIN o[60]
    DIRECTION OUTPUT ;
    USE SIGNAL ;
    PORT
      LAYER M4 ;
        RECT  21.516 6.624 21.6 6.648 ;
    END
  END o[60]
  PIN o[610]
    DIRECTION OUTPUT ;
    USE SIGNAL ;
    PORT
      LAYER M4 ;
        RECT  21.516 61.44 21.6 61.464 ;
    END
  END o[610]
  PIN o[611]
    DIRECTION OUTPUT ;
    USE SIGNAL ;
    PORT
      LAYER M4 ;
        RECT  21.516 61.536 21.6 61.56 ;
    END
  END o[611]
  PIN o[612]
    DIRECTION OUTPUT ;
    USE SIGNAL ;
    PORT
      LAYER M4 ;
        RECT  21.516 61.632 21.6 61.656 ;
    END
  END o[612]
  PIN o[613]
    DIRECTION OUTPUT ;
    USE SIGNAL ;
    PORT
      LAYER M4 ;
        RECT  21.516 61.728 21.6 61.752 ;
    END
  END o[613]
  PIN o[614]
    DIRECTION OUTPUT ;
    USE SIGNAL ;
    PORT
      LAYER M4 ;
        RECT  21.516 61.824 21.6 61.848 ;
    END
  END o[614]
  PIN o[615]
    DIRECTION OUTPUT ;
    USE SIGNAL ;
    PORT
      LAYER M4 ;
        RECT  21.516 61.92 21.6 61.944 ;
    END
  END o[615]
  PIN o[616]
    DIRECTION OUTPUT ;
    USE SIGNAL ;
    PORT
      LAYER M4 ;
        RECT  21.516 62.064 21.6 62.088 ;
    END
  END o[616]
  PIN o[617]
    DIRECTION OUTPUT ;
    USE SIGNAL ;
    PORT
      LAYER M4 ;
        RECT  21.516 62.16 21.6 62.184 ;
    END
  END o[617]
  PIN o[618]
    DIRECTION OUTPUT ;
    USE SIGNAL ;
    PORT
      LAYER M4 ;
        RECT  21.516 62.256 21.6 62.28 ;
    END
  END o[618]
  PIN o[619]
    DIRECTION OUTPUT ;
    USE SIGNAL ;
    PORT
      LAYER M4 ;
        RECT  21.516 62.352 21.6 62.376 ;
    END
  END o[619]
  PIN o[61]
    DIRECTION OUTPUT ;
    USE SIGNAL ;
    PORT
      LAYER M4 ;
        RECT  21.516 6.72 21.6 6.744 ;
    END
  END o[61]
  PIN o[620]
    DIRECTION OUTPUT ;
    USE SIGNAL ;
    PORT
      LAYER M4 ;
        RECT  21.516 62.448 21.6 62.472 ;
    END
  END o[620]
  PIN o[621]
    DIRECTION OUTPUT ;
    USE SIGNAL ;
    PORT
      LAYER M4 ;
        RECT  21.516 62.544 21.6 62.568 ;
    END
  END o[621]
  PIN o[622]
    DIRECTION OUTPUT ;
    USE SIGNAL ;
    PORT
      LAYER M4 ;
        RECT  21.516 62.64 21.6 62.664 ;
    END
  END o[622]
  PIN o[623]
    DIRECTION OUTPUT ;
    USE SIGNAL ;
    PORT
      LAYER M4 ;
        RECT  21.516 62.736 21.6 62.76 ;
    END
  END o[623]
  PIN o[62]
    DIRECTION OUTPUT ;
    USE SIGNAL ;
    PORT
      LAYER M4 ;
        RECT  21.516 6.816 21.6 6.84 ;
    END
  END o[62]
  PIN o[63]
    DIRECTION OUTPUT ;
    USE SIGNAL ;
    PORT
      LAYER M4 ;
        RECT  21.516 6.912 21.6 6.936 ;
    END
  END o[63]
  PIN o[64]
    DIRECTION OUTPUT ;
    USE SIGNAL ;
    PORT
      LAYER M4 ;
        RECT  21.516 7.008 21.6 7.032 ;
    END
  END o[64]
  PIN o[65]
    DIRECTION OUTPUT ;
    USE SIGNAL ;
    PORT
      LAYER M4 ;
        RECT  21.516 7.104 21.6 7.128 ;
    END
  END o[65]
  PIN o[66]
    DIRECTION OUTPUT ;
    USE SIGNAL ;
    PORT
      LAYER M4 ;
        RECT  21.516 7.2 21.6 7.224 ;
    END
  END o[66]
  PIN o[67]
    DIRECTION OUTPUT ;
    USE SIGNAL ;
    PORT
      LAYER M4 ;
        RECT  21.516 7.296 21.6 7.32 ;
    END
  END o[67]
  PIN o[68]
    DIRECTION OUTPUT ;
    USE SIGNAL ;
    PORT
      LAYER M4 ;
        RECT  21.516 7.44 21.6 7.464 ;
    END
  END o[68]
  PIN o[69]
    DIRECTION OUTPUT ;
    USE SIGNAL ;
    PORT
      LAYER M4 ;
        RECT  21.516 7.536 21.6 7.56 ;
    END
  END o[69]
  PIN o[6]
    DIRECTION OUTPUT ;
    USE SIGNAL ;
    PORT
      LAYER M4 ;
        RECT  21.516 1.248 21.6 1.272 ;
    END
  END o[6]
  PIN o[70]
    DIRECTION OUTPUT ;
    USE SIGNAL ;
    PORT
      LAYER M4 ;
        RECT  21.516 7.632 21.6 7.656 ;
    END
  END o[70]
  PIN o[71]
    DIRECTION OUTPUT ;
    USE SIGNAL ;
    PORT
      LAYER M4 ;
        RECT  21.516 7.728 21.6 7.752 ;
    END
  END o[71]
  PIN o[72]
    DIRECTION OUTPUT ;
    USE SIGNAL ;
    PORT
      LAYER M4 ;
        RECT  21.516 7.824 21.6 7.848 ;
    END
  END o[72]
  PIN o[73]
    DIRECTION OUTPUT ;
    USE SIGNAL ;
    PORT
      LAYER M4 ;
        RECT  21.516 7.92 21.6 7.944 ;
    END
  END o[73]
  PIN o[74]
    DIRECTION OUTPUT ;
    USE SIGNAL ;
    PORT
      LAYER M4 ;
        RECT  21.516 8.016 21.6 8.04 ;
    END
  END o[74]
  PIN o[75]
    DIRECTION OUTPUT ;
    USE SIGNAL ;
    PORT
      LAYER M4 ;
        RECT  21.516 8.112 21.6 8.136 ;
    END
  END o[75]
  PIN o[76]
    DIRECTION OUTPUT ;
    USE SIGNAL ;
    PORT
      LAYER M4 ;
        RECT  21.516 8.208 21.6 8.232 ;
    END
  END o[76]
  PIN o[77]
    DIRECTION OUTPUT ;
    USE SIGNAL ;
    PORT
      LAYER M4 ;
        RECT  21.516 8.304 21.6 8.328 ;
    END
  END o[77]
  PIN o[78]
    DIRECTION OUTPUT ;
    USE SIGNAL ;
    PORT
      LAYER M4 ;
        RECT  21.516 8.4 21.6 8.424 ;
    END
  END o[78]
  PIN o[79]
    DIRECTION OUTPUT ;
    USE SIGNAL ;
    PORT
      LAYER M4 ;
        RECT  21.516 8.496 21.6 8.52 ;
    END
  END o[79]
  PIN o[7]
    DIRECTION OUTPUT ;
    USE SIGNAL ;
    PORT
      LAYER M4 ;
        RECT  21.516 1.344 21.6 1.368 ;
    END
  END o[7]
  PIN o[80]
    DIRECTION OUTPUT ;
    USE SIGNAL ;
    PORT
      LAYER M4 ;
        RECT  21.516 8.592 21.6 8.616 ;
    END
  END o[80]
  PIN o[81]
    DIRECTION OUTPUT ;
    USE SIGNAL ;
    PORT
      LAYER M4 ;
        RECT  21.516 8.736 21.6 8.76 ;
    END
  END o[81]
  PIN o[82]
    DIRECTION OUTPUT ;
    USE SIGNAL ;
    PORT
      LAYER M4 ;
        RECT  21.516 8.832 21.6 8.856 ;
    END
  END o[82]
  PIN o[83]
    DIRECTION OUTPUT ;
    USE SIGNAL ;
    PORT
      LAYER M4 ;
        RECT  21.516 8.928 21.6 8.952 ;
    END
  END o[83]
  PIN o[84]
    DIRECTION OUTPUT ;
    USE SIGNAL ;
    PORT
      LAYER M4 ;
        RECT  21.516 9.024 21.6 9.048 ;
    END
  END o[84]
  PIN o[85]
    DIRECTION OUTPUT ;
    USE SIGNAL ;
    PORT
      LAYER M4 ;
        RECT  21.516 9.12 21.6 9.144 ;
    END
  END o[85]
  PIN o[86]
    DIRECTION OUTPUT ;
    USE SIGNAL ;
    PORT
      LAYER M4 ;
        RECT  21.516 9.216 21.6 9.24 ;
    END
  END o[86]
  PIN o[87]
    DIRECTION OUTPUT ;
    USE SIGNAL ;
    PORT
      LAYER M4 ;
        RECT  21.516 9.312 21.6 9.336 ;
    END
  END o[87]
  PIN o[88]
    DIRECTION OUTPUT ;
    USE SIGNAL ;
    PORT
      LAYER M4 ;
        RECT  21.516 9.408 21.6 9.432 ;
    END
  END o[88]
  PIN o[89]
    DIRECTION OUTPUT ;
    USE SIGNAL ;
    PORT
      LAYER M4 ;
        RECT  21.516 9.504 21.6 9.528 ;
    END
  END o[89]
  PIN o[8]
    DIRECTION OUTPUT ;
    USE SIGNAL ;
    PORT
      LAYER M4 ;
        RECT  21.516 1.44 21.6 1.464 ;
    END
  END o[8]
  PIN o[90]
    DIRECTION OUTPUT ;
    USE SIGNAL ;
    PORT
      LAYER M4 ;
        RECT  21.516 9.6 21.6 9.624 ;
    END
  END o[90]
  PIN o[91]
    DIRECTION OUTPUT ;
    USE SIGNAL ;
    PORT
      LAYER M4 ;
        RECT  21.516 9.696 21.6 9.72 ;
    END
  END o[91]
  PIN o[92]
    DIRECTION OUTPUT ;
    USE SIGNAL ;
    PORT
      LAYER M4 ;
        RECT  21.516 9.792 21.6 9.816 ;
    END
  END o[92]
  PIN o[93]
    DIRECTION OUTPUT ;
    USE SIGNAL ;
    PORT
      LAYER M4 ;
        RECT  21.516 9.888 21.6 9.912 ;
    END
  END o[93]
  PIN o[94]
    DIRECTION OUTPUT ;
    USE SIGNAL ;
    PORT
      LAYER M4 ;
        RECT  21.516 10.032 21.6 10.056 ;
    END
  END o[94]
  PIN o[95]
    DIRECTION OUTPUT ;
    USE SIGNAL ;
    PORT
      LAYER M4 ;
        RECT  21.516 10.128 21.6 10.152 ;
    END
  END o[95]
  PIN o[96]
    DIRECTION OUTPUT ;
    USE SIGNAL ;
    PORT
      LAYER M4 ;
        RECT  21.516 10.224 21.6 10.248 ;
    END
  END o[96]
  PIN o[97]
    DIRECTION OUTPUT ;
    USE SIGNAL ;
    PORT
      LAYER M4 ;
        RECT  21.516 10.32 21.6 10.344 ;
    END
  END o[97]
  PIN o[98]
    DIRECTION OUTPUT ;
    USE SIGNAL ;
    PORT
      LAYER M4 ;
        RECT  21.516 10.416 21.6 10.44 ;
    END
  END o[98]
  PIN o[99]
    DIRECTION OUTPUT ;
    USE SIGNAL ;
    PORT
      LAYER M4 ;
        RECT  21.516 10.512 21.6 10.536 ;
    END
  END o[99]
  PIN o[9]
    DIRECTION OUTPUT ;
    USE SIGNAL ;
    PORT
      LAYER M4 ;
        RECT  21.516 1.536 21.6 1.56 ;
    END
  END o[9]
  PIN rs
    DIRECTION INPUT ;
    USE SIGNAL ;
    PORT
      LAYER M5 ;
        RECT  15.696 0 15.72 0.084 ;
    END
    PORT
      LAYER M5 ;
        RECT  15.696 0.016 15.72 2.137 ;
    END
  END rs
  PIN rso
    DIRECTION OUTPUT ;
    USE SIGNAL ;
    PORT
      LAYER M4 ;
        RECT  21.516 63.792 21.6 63.816 ;
    END
    PORT
      LAYER M4 ;
        RECT  15.181 63.792 21.564 63.816 ;
    END
  END rso
  PIN VDD
    DIRECTION INOUT ;
    USE POWER ;
    PORT
      LAYER M5 ;
        RECT  18.792 2.151 18.912 62.649 ;
        RECT  16.092 2.151 16.212 62.649 ;
        RECT  13.392 2.151 13.512 62.649 ;
        RECT  10.692 2.151 10.812 62.649 ;
        RECT  7.992 2.151 8.112 62.649 ;
        RECT  5.292 2.151 5.412 62.649 ;
        RECT  2.592 2.151 2.712 62.649 ;
    END
  END VDD
  PIN VSS
    DIRECTION INOUT ;
    USE GROUND ;
    PORT
      LAYER M5 ;
        RECT  18.6 2.137 18.72 62.663 ;
        RECT  15.9 2.137 16.02 62.663 ;
        RECT  13.2 2.137 13.32 62.663 ;
        RECT  10.5 2.137 10.62 62.663 ;
        RECT  7.8 2.137 7.92 62.663 ;
        RECT  5.1 2.137 5.22 62.663 ;
        RECT  2.4 2.137 2.52 62.663 ;
    END
  END VSS
  # OT_OBS_CLOSED layer=M5 d_um=1.536 added=194
  OBS
    LAYER RVTN ;
     RECT  2.16 2.16 19.44 2.295 ;
     RECT  2.16 2.565 19.44 2.835 ;
     RECT  2.16 3.105 19.44 3.375 ;
     RECT  2.16 3.645 19.44 3.915 ;
     RECT  2.16 4.185 19.44 4.455 ;
     RECT  2.16 4.725 19.44 4.995 ;
     RECT  2.16 5.265 19.44 5.535 ;
     RECT  2.16 5.805 19.44 6.075 ;
     RECT  2.16 6.345 19.44 6.615 ;
     RECT  2.16 6.885 19.44 7.155 ;
     RECT  2.16 7.425 19.44 7.695 ;
     RECT  2.16 7.965 19.44 8.235 ;
     RECT  2.16 8.505 19.44 8.775 ;
     RECT  2.16 9.045 19.44 9.315 ;
     RECT  2.16 9.585 19.44 9.855 ;
     RECT  2.16 10.125 19.44 10.395 ;
     RECT  2.16 10.665 19.44 10.935 ;
     RECT  2.16 11.205 19.44 11.475 ;
     RECT  2.16 11.745 19.44 12.015 ;
     RECT  2.16 12.285 19.44 12.555 ;
     RECT  2.16 12.825 19.44 13.095 ;
     RECT  2.16 13.365 19.44 13.635 ;
     RECT  2.16 13.905 19.44 14.175 ;
     RECT  2.16 14.445 19.44 14.715 ;
     RECT  2.16 14.985 19.44 15.255 ;
     RECT  2.16 15.525 19.44 15.795 ;
     RECT  2.16 16.065 19.44 16.335 ;
     RECT  2.16 16.605 19.44 16.875 ;
     RECT  2.16 17.145 19.44 17.415 ;
     RECT  2.16 17.685 19.44 17.955 ;
     RECT  2.16 18.225 19.44 18.495 ;
     RECT  2.16 18.765 19.44 19.035 ;
     RECT  2.16 19.305 19.44 19.575 ;
     RECT  2.16 19.845 19.44 20.115 ;
     RECT  2.16 20.385 19.44 20.655 ;
     RECT  2.16 20.925 19.44 21.195 ;
     RECT  2.16 21.465 19.44 21.735 ;
     RECT  2.16 22.005 19.44 22.275 ;
     RECT  2.16 22.545 19.44 22.815 ;
     RECT  2.16 23.085 19.44 23.355 ;
     RECT  2.16 23.625 19.44 23.895 ;
     RECT  2.16 24.165 19.44 24.435 ;
     RECT  2.16 24.705 19.44 24.975 ;
     RECT  2.16 25.245 19.44 25.515 ;
     RECT  2.16 25.785 19.44 26.055 ;
     RECT  2.16 26.325 19.44 26.595 ;
     RECT  2.16 26.865 19.44 27.135 ;
     RECT  2.16 27.405 19.44 27.675 ;
     RECT  2.16 27.945 19.44 28.215 ;
     RECT  2.16 28.485 19.44 28.755 ;
     RECT  2.16 29.025 19.44 29.295 ;
     RECT  2.16 29.565 19.44 29.835 ;
     RECT  2.16 30.105 19.44 30.375 ;
     RECT  2.16 30.645 19.44 30.915 ;
     RECT  2.16 31.185 19.44 31.455 ;
     RECT  2.16 31.725 19.44 31.995 ;
     RECT  2.16 32.265 19.44 32.535 ;
     RECT  2.16 32.805 19.44 33.075 ;
     RECT  2.16 33.345 19.44 33.615 ;
     RECT  2.16 33.885 19.44 34.155 ;
     RECT  2.16 34.425 19.44 34.695 ;
     RECT  2.16 34.965 19.44 35.235 ;
     RECT  2.16 35.505 19.44 35.775 ;
     RECT  2.16 36.045 19.44 36.315 ;
     RECT  2.16 36.585 19.44 36.855 ;
     RECT  2.16 37.125 19.44 37.395 ;
     RECT  2.16 37.665 19.44 37.935 ;
     RECT  2.16 38.205 19.44 38.475 ;
     RECT  2.16 38.745 19.44 39.015 ;
     RECT  2.16 39.285 19.44 39.555 ;
     RECT  2.16 39.825 19.44 40.095 ;
     RECT  2.16 40.365 19.44 40.635 ;
     RECT  2.16 40.905 19.44 41.175 ;
     RECT  2.16 41.445 19.44 41.715 ;
     RECT  2.16 41.985 19.44 42.255 ;
     RECT  2.16 42.525 19.44 42.795 ;
     RECT  2.16 43.065 19.44 43.335 ;
     RECT  2.16 43.605 19.44 43.875 ;
     RECT  2.16 44.145 19.44 44.415 ;
     RECT  2.16 44.685 19.44 44.955 ;
     RECT  2.16 45.225 19.44 45.495 ;
     RECT  2.16 45.765 19.44 46.035 ;
     RECT  2.16 46.305 19.44 46.575 ;
     RECT  2.16 46.845 19.44 47.115 ;
     RECT  2.16 47.385 19.44 47.655 ;
     RECT  2.16 47.925 19.44 48.195 ;
     RECT  2.16 48.465 19.44 48.735 ;
     RECT  2.16 49.005 19.44 49.275 ;
     RECT  2.16 49.545 19.44 49.815 ;
     RECT  2.16 50.085 19.44 50.355 ;
     RECT  2.16 50.625 19.44 50.895 ;
     RECT  2.16 51.165 19.44 51.435 ;
     RECT  2.16 51.705 19.44 51.975 ;
     RECT  2.16 52.245 19.44 52.515 ;
     RECT  2.16 52.785 19.44 53.055 ;
     RECT  2.16 53.325 19.44 53.595 ;
     RECT  2.16 53.865 19.44 54.135 ;
     RECT  2.16 54.405 19.44 54.675 ;
     RECT  2.16 54.945 19.44 55.215 ;
     RECT  2.16 55.485 19.44 55.755 ;
     RECT  2.16 56.025 19.44 56.295 ;
     RECT  2.16 56.565 19.44 56.835 ;
     RECT  2.16 57.105 19.44 57.375 ;
     RECT  2.16 57.645 19.44 57.915 ;
     RECT  2.16 58.185 19.44 58.455 ;
     RECT  2.16 58.725 19.44 58.995 ;
     RECT  2.16 59.265 19.44 59.535 ;
     RECT  2.16 59.805 19.44 60.075 ;
     RECT  2.16 60.345 19.44 60.615 ;
     RECT  2.16 60.885 19.44 61.155 ;
     RECT  2.16 61.425 19.44 61.695 ;
     RECT  2.16 61.965 19.44 62.235 ;
     RECT  2.16 62.505 19.44 62.64 ;
    LAYER RVTP ;
     RECT  2.16 2.295 19.44 2.565 ;
     RECT  2.16 2.835 19.44 3.105 ;
     RECT  2.16 3.375 19.44 3.645 ;
     RECT  2.16 3.915 19.44 4.185 ;
     RECT  2.16 4.455 19.44 4.725 ;
     RECT  2.16 4.995 19.44 5.265 ;
     RECT  2.16 5.535 19.44 5.805 ;
     RECT  2.16 6.075 19.44 6.345 ;
     RECT  2.16 6.615 19.44 6.885 ;
     RECT  2.16 7.155 19.44 7.425 ;
     RECT  2.16 7.695 19.44 7.965 ;
     RECT  2.16 8.235 19.44 8.505 ;
     RECT  2.16 8.775 19.44 9.045 ;
     RECT  2.16 9.315 19.44 9.585 ;
     RECT  2.16 9.855 19.44 10.125 ;
     RECT  2.16 10.395 19.44 10.665 ;
     RECT  2.16 10.935 19.44 11.205 ;
     RECT  2.16 11.475 19.44 11.745 ;
     RECT  2.16 12.015 19.44 12.285 ;
     RECT  2.16 12.555 19.44 12.825 ;
     RECT  2.16 13.095 19.44 13.365 ;
     RECT  2.16 13.635 19.44 13.905 ;
     RECT  2.16 14.175 19.44 14.445 ;
     RECT  2.16 14.715 19.44 14.985 ;
     RECT  2.16 15.255 19.44 15.525 ;
     RECT  2.16 15.795 19.44 16.065 ;
     RECT  2.16 16.335 19.44 16.605 ;
     RECT  2.16 16.875 19.44 17.145 ;
     RECT  2.16 17.415 19.44 17.685 ;
     RECT  2.16 17.955 19.44 18.225 ;
     RECT  2.16 18.495 19.44 18.765 ;
     RECT  2.16 19.035 19.44 19.305 ;
     RECT  2.16 19.575 19.44 19.845 ;
     RECT  2.16 20.115 19.44 20.385 ;
     RECT  2.16 20.655 19.44 20.925 ;
     RECT  2.16 21.195 19.44 21.465 ;
     RECT  2.16 21.735 19.44 22.005 ;
     RECT  2.16 22.275 19.44 22.545 ;
     RECT  2.16 22.815 19.44 23.085 ;
     RECT  2.16 23.355 19.44 23.625 ;
     RECT  2.16 23.895 19.44 24.165 ;
     RECT  2.16 24.435 19.44 24.705 ;
     RECT  2.16 24.975 19.44 25.245 ;
     RECT  2.16 25.515 19.44 25.785 ;
     RECT  2.16 26.055 19.44 26.325 ;
     RECT  2.16 26.595 19.44 26.865 ;
     RECT  2.16 27.135 19.44 27.405 ;
     RECT  2.16 27.675 19.44 27.945 ;
     RECT  2.16 28.215 19.44 28.485 ;
     RECT  2.16 28.755 19.44 29.025 ;
     RECT  2.16 29.295 19.44 29.565 ;
     RECT  2.16 29.835 19.44 30.105 ;
     RECT  2.16 30.375 19.44 30.645 ;
     RECT  2.16 30.915 19.44 31.185 ;
     RECT  2.16 31.455 19.44 31.725 ;
     RECT  2.16 31.995 19.44 32.265 ;
     RECT  2.16 32.535 19.44 32.805 ;
     RECT  2.16 33.075 19.44 33.345 ;
     RECT  2.16 33.615 19.44 33.885 ;
     RECT  2.16 34.155 19.44 34.425 ;
     RECT  2.16 34.695 19.44 34.965 ;
     RECT  2.16 35.235 19.44 35.505 ;
     RECT  2.16 35.775 19.44 36.045 ;
     RECT  2.16 36.315 19.44 36.585 ;
     RECT  2.16 36.855 19.44 37.125 ;
     RECT  2.16 37.395 19.44 37.665 ;
     RECT  2.16 37.935 19.44 38.205 ;
     RECT  2.16 38.475 19.44 38.745 ;
     RECT  2.16 39.015 19.44 39.285 ;
     RECT  2.16 39.555 19.44 39.825 ;
     RECT  2.16 40.095 19.44 40.365 ;
     RECT  2.16 40.635 19.44 40.905 ;
     RECT  2.16 41.175 19.44 41.445 ;
     RECT  2.16 41.715 19.44 41.985 ;
     RECT  2.16 42.255 19.44 42.525 ;
     RECT  2.16 42.795 19.44 43.065 ;
     RECT  2.16 43.335 19.44 43.605 ;
     RECT  2.16 43.875 19.44 44.145 ;
     RECT  2.16 44.415 19.44 44.685 ;
     RECT  2.16 44.955 19.44 45.225 ;
     RECT  2.16 45.495 19.44 45.765 ;
     RECT  2.16 46.035 19.44 46.305 ;
     RECT  2.16 46.575 19.44 46.845 ;
     RECT  2.16 47.115 19.44 47.385 ;
     RECT  2.16 47.655 19.44 47.925 ;
     RECT  2.16 48.195 19.44 48.465 ;
     RECT  2.16 48.735 19.44 49.005 ;
     RECT  2.16 49.275 19.44 49.545 ;
     RECT  2.16 49.815 19.44 50.085 ;
     RECT  2.16 50.355 19.44 50.625 ;
     RECT  2.16 50.895 19.44 51.165 ;
     RECT  2.16 51.435 19.44 51.705 ;
     RECT  2.16 51.975 19.44 52.245 ;
     RECT  2.16 52.515 19.44 52.785 ;
     RECT  2.16 53.055 19.44 53.325 ;
     RECT  2.16 53.595 19.44 53.865 ;
     RECT  2.16 54.135 19.44 54.405 ;
     RECT  2.16 54.675 19.44 54.945 ;
     RECT  2.16 55.215 19.44 55.485 ;
     RECT  2.16 55.755 19.44 56.025 ;
     RECT  2.16 56.295 19.44 56.565 ;
     RECT  2.16 56.835 19.44 57.105 ;
     RECT  2.16 57.375 19.44 57.645 ;
     RECT  2.16 57.915 19.44 58.185 ;
     RECT  2.16 58.455 19.44 58.725 ;
     RECT  2.16 58.995 19.44 59.265 ;
     RECT  2.16 59.535 19.44 59.805 ;
     RECT  2.16 60.075 19.44 60.345 ;
     RECT  2.16 60.615 19.44 60.885 ;
     RECT  2.16 61.155 19.44 61.425 ;
     RECT  2.16 61.695 19.44 61.965 ;
     RECT  2.16 62.235 19.44 62.505 ;
    LAYER M1 ;
     RECT  2.16 2.151 19.44 62.649 ;
    LAYER M2 ;
     RECT  0.103 3.312 0.175 3.33 ;
     RECT  0.103 35.091 0.203 35.424 ;
     RECT  0.103 30.654 0.211 30.672 ;
     RECT  0.211 30.654 0.239 30.978 ;
     RECT  0.139 62.442 0.239 62.532 ;
     RECT  0.103 7.704 0.347 7.722 ;
     RECT  0.211 14.76 0.347 14.778 ;
     RECT  0.203 35.316 0.347 35.424 ;
     RECT  0.103 52.254 0.347 52.272 ;
     RECT  0.175 3.312 0.383 3.87 ;
     RECT  0.211 45.81 0.383 45.828 ;
     RECT  0.175 55.692 0.383 55.71 ;
     RECT  0.239 62.442 0.383 62.46 ;
     RECT  0.383 3.312 1.687 3.33 ;
     RECT  1.687 3.114 1.723 3.33 ;
     RECT  1.723 3.114 2.16 3.708 ;
     RECT  0.103 17.082 2.16 17.1 ;
     RECT  2.155 24.642 2.16 24.66 ;
     RECT  0.239 30.96 2.16 30.978 ;
     RECT  2.16 2.151 2.839 62.649 ;
     RECT  2.839 1.962 3.055 62.649 ;
     RECT  3.055 1.962 4.091 62.694 ;
     RECT  4.091 2.034 5.099 62.694 ;
     RECT  5.099 2.106 6.287 62.694 ;
     RECT  6.287 2.151 10.363 62.694 ;
     RECT  10.363 2.034 13.783 62.694 ;
     RECT  13.783 1.836 14.143 62.694 ;
     RECT  14.143 1.836 14.359 62.73 ;
     RECT  14.359 1.152 14.495 62.73 ;
     RECT  14.495 1.764 14.827 62.73 ;
     RECT  14.827 1.764 16.051 62.802 ;
     RECT  16.051 1.728 18.527 62.802 ;
     RECT  18.527 1.764 19.679 62.802 ;
     RECT  19.679 1.764 19.823 59.184 ;
     RECT  19.823 1.764 19.895 58.914 ;
     RECT  19.895 1.764 19.931 52.848 ;
     RECT  19.895 53.766 19.931 58.914 ;
     RECT  19.931 3.816 19.967 52.848 ;
     RECT  19.679 59.976 19.967 62.802 ;
     RECT  19.931 1.764 20.039 2.826 ;
     RECT  19.967 22.986 20.183 52.848 ;
     RECT  19.931 53.766 20.219 58.104 ;
     RECT  19.967 60.786 20.219 62.694 ;
     RECT  19.967 3.816 20.255 22.194 ;
     RECT  20.255 20.826 20.399 22.194 ;
     RECT  20.255 3.816 20.435 20.034 ;
     RECT  20.399 20.826 20.435 21.762 ;
     RECT  20.183 22.986 20.435 40.284 ;
     RECT  19.931 58.896 20.435 58.914 ;
     RECT  20.435 3.816 20.471 14.544 ;
     RECT  20.435 15.426 20.471 19.224 ;
     RECT  20.435 22.986 20.471 23.544 ;
     RECT  20.435 24.336 20.471 40.284 ;
     RECT  20.183 41.076 20.471 52.848 ;
     RECT  20.219 60.786 20.471 61.884 ;
     RECT  20.471 3.816 20.507 8.964 ;
     RECT  20.471 9.756 20.507 14.544 ;
     RECT  20.471 15.696 20.507 19.224 ;
     RECT  20.435 20.826 20.507 21.564 ;
     RECT  20.471 24.336 20.507 24.894 ;
     RECT  20.471 25.686 20.507 34.614 ;
     RECT  20.471 44.316 20.507 47.844 ;
     RECT  20.471 48.978 20.507 49.302 ;
     RECT  20.471 50.166 20.507 52.776 ;
     RECT  20.219 53.766 20.507 56.664 ;
     RECT  19.967 59.976 20.507 59.994 ;
     RECT  20.507 4.266 20.543 8.964 ;
     RECT  20.507 9.756 20.543 14.436 ;
     RECT  20.507 15.696 20.543 17.406 ;
     RECT  20.507 21.546 20.543 21.564 ;
     RECT  20.507 25.686 20.543 26.964 ;
     RECT  20.507 27.918 20.543 29.052 ;
     RECT  20.507 31.806 20.543 34.416 ;
     RECT  20.471 41.076 20.543 43.524 ;
     RECT  20.507 48.978 20.543 48.996 ;
     RECT  20.507 54.036 20.543 55.134 ;
     RECT  20.039 1.764 20.579 2.754 ;
     RECT  20.507 44.46 20.579 47.682 ;
     RECT  20.507 51.336 20.579 52.776 ;
     RECT  20.543 31.806 20.615 34.074 ;
     RECT  20.471 61.164 21.235 61.884 ;
     RECT  20.543 9.756 21.335 14.274 ;
     RECT  20.615 31.806 21.335 32.292 ;
     RECT  20.471 35.514 21.335 40.284 ;
     RECT  21.235 61.011 21.335 61.884 ;
     RECT  21.335 35.514 21.371 39.114 ;
     RECT  20.543 41.076 21.371 42.012 ;
     RECT  20.435 20.016 21.379 20.034 ;
     RECT  20.507 24.336 21.379 24.624 ;
     RECT  20.543 25.686 21.379 25.704 ;
     RECT  20.507 18.666 21.407 19.134 ;
     RECT  21.371 35.514 21.407 38.808 ;
     RECT  20.543 43.236 21.407 43.524 ;
     RECT  21.379 24.336 21.415 25.704 ;
     RECT  20.543 28.386 21.415 28.404 ;
     RECT  21.335 61.164 21.415 61.884 ;
     RECT  20.219 62.676 21.415 62.694 ;
     RECT  21.335 10.521 21.443 14.274 ;
     RECT  21.379 19.971 21.443 20.034 ;
     RECT  21.407 35.514 21.443 37.044 ;
     RECT  21.371 41.076 21.443 41.094 ;
     RECT  20.507 50.4 21.443 50.454 ;
     RECT  20.219 57.42 21.443 58.104 ;
     RECT  20.579 2.376 21.479 2.754 ;
     RECT  20.543 4.356 21.479 8.964 ;
     RECT  21.443 10.521 21.479 11.808 ;
     RECT  20.543 15.696 21.479 16.866 ;
     RECT  21.407 18.936 21.479 19.134 ;
     RECT  21.443 19.971 21.479 19.989 ;
     RECT  20.471 22.986 21.479 23.382 ;
     RECT  21.415 24.336 21.479 25.776 ;
     RECT  20.543 26.766 21.479 26.964 ;
     RECT  20.507 30.276 21.479 30.402 ;
     RECT  21.335 32.202 21.479 32.292 ;
     RECT  20.615 33.156 21.479 34.074 ;
     RECT  21.443 35.514 21.479 36.504 ;
     RECT  21.335 40.104 21.479 40.284 ;
     RECT  21.371 41.994 21.479 42.012 ;
     RECT  20.579 44.496 21.479 47.682 ;
     RECT  20.579 51.336 21.479 52.614 ;
     RECT  20.543 55.116 21.479 55.134 ;
     RECT  20.507 56.196 21.479 56.664 ;
     RECT  21.443 57.42 21.479 58.014 ;
     RECT  21.415 61.164 21.479 62.694 ;
     RECT  21.479 2.574 21.515 2.754 ;
     RECT  21.479 4.356 21.515 4.374 ;
     RECT  21.479 5.31 21.515 5.526 ;
     RECT  21.479 6.624 21.515 7.146 ;
     RECT  21.479 8.244 21.515 8.964 ;
     RECT  21.335 9.756 21.515 9.774 ;
     RECT  21.479 10.521 21.515 10.539 ;
     RECT  21.479 11.376 21.515 11.808 ;
     RECT  21.443 12.996 21.515 14.274 ;
     RECT  21.479 15.696 21.515 15.714 ;
     RECT  21.479 16.506 21.515 16.524 ;
     RECT  21.479 18.936 21.515 18.954 ;
     RECT  21.479 22.986 21.515 23.004 ;
     RECT  21.479 24.336 21.515 24.354 ;
     RECT  21.479 25.758 21.515 25.776 ;
     RECT  21.479 26.766 21.515 26.784 ;
     RECT  21.415 28.386 21.515 28.854 ;
     RECT  21.479 30.384 21.515 30.402 ;
     RECT  21.479 32.274 21.515 32.292 ;
     RECT  21.479 33.318 21.515 33.336 ;
     RECT  21.479 35.514 21.515 35.532 ;
     RECT  21.479 36.486 21.515 36.504 ;
     RECT  21.407 38.106 21.515 38.808 ;
     RECT  21.479 40.104 21.515 40.122 ;
     RECT  21.407 43.236 21.515 43.254 ;
     RECT  21.479 44.496 21.515 46.224 ;
     RECT  21.479 47.088 21.515 47.682 ;
     RECT  21.443 50.436 21.515 50.454 ;
     RECT  21.479 51.876 21.515 52.614 ;
     RECT  20.543 54.036 21.515 54.054 ;
     RECT  21.479 56.646 21.515 56.664 ;
     RECT  21.479 57.42 21.515 57.708 ;
     RECT  21.479 61.866 21.515 62.496 ;
     RECT  21.515 2.574 21.587 2.592 ;
     RECT  21.515 5.31 21.587 5.328 ;
     RECT  21.343 49.59 21.587 49.608 ;
     RECT  21.515 51.876 21.587 51.894 ;
    LAYER M3 ;
     RECT  4.5 0.715 4.518 0.811 ;
     RECT  19.368 0.619 19.386 0.811 ;
     RECT  3.852 0.811 4.518 0.955 ;
     RECT  3.708 0.955 4.518 1.051 ;
     RECT  14.472 0.955 14.49 1.147 ;
     RECT  16.452 0.715 16.47 1.243 ;
     RECT  17.496 1.051 17.514 1.243 ;
     RECT  3.708 1.051 4.95 1.435 ;
     RECT  14.004 1.147 14.49 1.435 ;
     RECT  16.452 1.243 17.514 1.531 ;
     RECT  3.708 1.435 5.274 1.627 ;
     RECT  16.452 1.531 17.55 1.627 ;
     RECT  1.692 1.531 1.71 1.723 ;
     RECT  16.452 1.627 17.586 1.723 ;
     RECT  18.72 0.811 19.386 1.723 ;
     RECT  20.484 1.723 20.502 1.759 ;
     RECT  1.692 1.723 2.322 1.819 ;
     RECT  3.168 1.627 5.274 1.819 ;
     RECT  14.004 1.435 15.174 1.831 ;
     RECT  16.056 1.723 17.586 1.876 ;
     RECT  18.504 1.723 19.386 1.915 ;
     RECT  20.484 1.759 20.574 1.915 ;
     RECT  13.788 1.831 15.174 1.921 ;
     RECT  16.056 1.876 17.622 1.921 ;
     RECT  21.492 1.819 21.51 1.963 ;
     RECT  13.788 1.921 17.622 1.993 ;
     RECT  18.504 1.915 20.574 1.993 ;
     RECT  13.788 1.993 20.574 2.065 ;
     RECT  12.06 2.059 12.438 2.101 ;
     RECT  0.108 0.619 0.126 2.107 ;
     RECT  7.776 2.059 7.794 2.143 ;
     RECT  10.368 2.029 10.386 2.143 ;
     RECT  6.264 2.101 6.282 2.191 ;
     RECT  7.776 2.143 7.905 2.227 ;
     RECT  0.108 2.107 0.342 2.285 ;
     RECT  7.776 2.227 8.442 2.299 ;
     RECT  11.772 2.101 12.438 2.299 ;
     RECT  13.176 2.065 20.574 2.299 ;
     RECT  7.776 2.299 8.694 2.335 ;
     RECT  9.576 2.299 9.594 2.335 ;
     RECT  10.368 2.143 10.605 2.335 ;
     RECT  11.376 2.299 20.574 2.335 ;
     RECT  6.264 2.191 6.93 2.371 ;
     RECT  1.692 1.819 5.274 2.413 ;
     RECT  6.264 2.371 6.966 2.488 ;
     RECT  7.776 2.335 20.574 2.488 ;
     RECT  21.42 1.963 21.51 2.539 ;
     RECT  21.312 2.539 21.51 2.569 ;
     RECT  1.692 2.413 5.397 2.641 ;
     RECT  6.264 2.488 20.574 2.641 ;
     RECT  21.312 2.569 21.582 2.765 ;
     RECT  21.42 2.765 21.582 2.813 ;
     RECT  1.692 2.641 20.574 2.957 ;
     RECT  1.692 2.957 20.538 3.137 ;
     RECT  1.728 3.137 20.538 3.209 ;
     RECT  0.108 2.285 0.234 3.211 ;
     RECT  0.108 3.211 0.342 3.335 ;
     RECT  21.456 2.813 21.582 3.643 ;
     RECT  6.264 3.209 20.538 3.691 ;
     RECT  1.728 3.209 5.397 3.713 ;
     RECT  21.42 3.643 21.582 3.739 ;
     RECT  0.144 3.335 0.342 3.847 ;
     RECT  2.268 3.713 5.397 3.947 ;
     RECT  6.264 3.691 20.61 3.947 ;
     RECT  0.144 3.847 0.378 3.965 ;
     RECT  2.268 3.947 4.338 3.983 ;
     RECT  21.384 3.739 21.582 4.315 ;
     RECT  21.348 4.315 21.582 4.493 ;
     RECT  7.704 3.947 20.61 4.637 ;
     RECT  2.268 3.983 3.978 4.649 ;
     RECT  7.704 4.637 20.574 4.765 ;
     RECT  6.264 3.947 6.858 4.793 ;
     RECT  5.115 3.947 5.397 4.801 ;
     RECT  6.588 4.793 6.858 4.919 ;
     RECT  6.66 4.919 6.858 4.927 ;
     RECT  7.632 4.765 20.574 4.927 ;
     RECT  6.66 4.927 20.574 4.955 ;
     RECT  0.324 4.843 0.342 4.973 ;
     RECT  6.804 4.955 20.574 5.063 ;
     RECT  21.384 4.493 21.582 5.323 ;
     RECT  21.348 5.323 21.582 5.333 ;
     RECT  2.268 4.649 3.906 5.419 ;
     RECT  2.232 5.419 3.906 5.431 ;
     RECT  5.115 4.801 5.742 5.431 ;
     RECT  0.144 5.323 0.162 5.501 ;
     RECT  4.86 5.431 5.742 5.549 ;
     RECT  2.232 5.431 3.978 5.603 ;
     RECT  6.804 5.063 20.538 5.701 ;
     RECT  5.115 5.549 5.742 5.773 ;
     RECT  6.768 5.701 20.538 5.773 ;
     RECT  5.115 5.773 20.538 5.999 ;
     RECT  0.324 5.899 0.342 6.029 ;
     RECT  5.115 5.999 19.062 6.035 ;
     RECT  2.304 5.603 3.978 6.043 ;
     RECT  2.304 6.043 4.086 6.241 ;
     RECT  6.264 6.035 19.062 6.305 ;
     RECT  2.304 6.241 4.122 6.385 ;
     RECT  5.115 6.035 5.397 6.385 ;
     RECT  2.304 6.385 5.397 6.523 ;
     RECT  21.348 5.333 21.51 6.523 ;
     RECT  6.552 6.305 19.062 6.575 ;
     RECT  6.66 6.575 19.062 6.701 ;
     RECT  6.696 6.701 19.062 6.809 ;
     RECT  21.312 6.523 21.51 7.151 ;
     RECT  2.268 6.523 5.397 7.195 ;
     RECT  21.312 7.151 21.474 7.195 ;
     RECT  6.84 6.809 19.062 7.231 ;
     RECT  19.836 5.999 20.538 7.231 ;
     RECT  0.144 7.291 0.162 7.531 ;
     RECT  0.144 7.531 0.342 7.627 ;
     RECT  2.268 7.195 5.742 7.663 ;
     RECT  6.84 7.231 20.538 7.663 ;
     RECT  2.268 7.663 20.538 7.691 ;
     RECT  0.108 7.627 0.342 7.727 ;
     RECT  2.268 7.691 20.466 7.799 ;
     RECT  21.276 7.195 21.474 8.011 ;
     RECT  6.552 7.799 20.466 8.195 ;
     RECT  0.144 7.727 0.342 8.285 ;
     RECT  2.268 7.799 5.742 8.465 ;
     RECT  21.276 8.011 21.51 8.621 ;
     RECT  6.552 8.195 6.858 8.735 ;
     RECT  6.768 8.735 6.858 9.013 ;
     RECT  7.815 8.195 20.466 9.013 ;
     RECT  0.324 8.285 0.342 9.053 ;
     RECT  2.268 8.465 5.397 9.211 ;
     RECT  21.312 8.621 21.51 9.499 ;
     RECT  6.768 9.013 20.466 9.509 ;
     RECT  2.268 9.211 5.742 9.545 ;
     RECT  4.536 9.545 5.742 9.581 ;
     RECT  9 9.509 20.466 9.581 ;
     RECT  4.68 9.581 5.742 9.661 ;
     RECT  6.768 9.509 8.154 9.661 ;
     RECT  9.072 9.581 20.466 9.851 ;
     RECT  4.68 9.661 8.154 9.923 ;
     RECT  20.196 9.851 20.466 9.931 ;
     RECT  20.196 9.931 20.538 10.121 ;
     RECT  0.324 10.027 0.342 10.157 ;
     RECT  2.268 9.545 3.726 10.315 ;
     RECT  4.68 9.923 5.397 10.315 ;
     RECT  2.268 10.315 5.397 10.427 ;
     RECT  9.072 9.851 19.314 10.435 ;
     RECT  21.276 9.499 21.51 10.637 ;
     RECT  6.372 9.923 8.154 10.661 ;
     RECT  6.768 10.661 8.154 10.669 ;
     RECT  9 10.435 19.314 10.733 ;
     RECT  21.312 10.637 21.51 10.733 ;
     RECT  9.9 10.733 19.314 10.795 ;
     RECT  6.768 10.669 8.226 10.939 ;
     RECT  9 10.733 9.162 10.939 ;
     RECT  20.52 10.121 20.538 11.011 ;
     RECT  9.9 10.795 19.71 11.213 ;
     RECT  2.304 10.427 5.397 11.309 ;
     RECT  21.348 10.733 21.51 11.309 ;
     RECT  2.304 11.309 4.086 11.399 ;
     RECT  6.768 10.939 9.162 11.407 ;
     RECT  6.696 11.407 9.162 11.453 ;
     RECT  6.804 11.453 9.162 11.507 ;
     RECT  10.152 11.213 19.71 11.551 ;
     RECT  20.484 11.011 20.538 11.551 ;
     RECT  6.804 11.507 8.406 11.693 ;
     RECT  6.876 11.693 8.406 11.705 ;
     RECT  2.304 11.399 4.014 11.975 ;
     RECT  0.144 10.363 0.162 11.981 ;
     RECT  10.152 11.551 20.538 11.983 ;
     RECT  21.384 11.309 21.51 12.029 ;
     RECT  9.18 11.947 9.198 12.091 ;
     RECT  10.116 11.983 20.538 12.091 ;
     RECT  21.384 12.029 21.438 12.235 ;
     RECT  9.18 12.091 20.538 12.281 ;
     RECT  6.876 11.705 8.298 12.451 ;
     RECT  5.115 11.309 5.397 12.487 ;
     RECT  6.228 12.451 8.298 12.515 ;
     RECT  9.18 12.281 20.502 12.56 ;
     RECT  21.348 12.235 21.438 12.571 ;
     RECT  7.776 12.515 8.298 12.631 ;
     RECT  21.24 12.571 21.438 12.749 ;
     RECT  9.936 12.56 20.502 12.821 ;
     RECT  6.228 12.515 6.894 12.893 ;
     RECT  2.304 11.975 3.69 13.003 ;
     RECT  2.268 13.003 3.69 13.027 ;
     RECT  4.464 12.487 5.397 13.027 ;
     RECT  7.776 12.631 9.162 13.085 ;
     RECT  6.696 12.893 6.894 13.261 ;
     RECT  6.696 13.261 7.038 13.433 ;
     RECT  2.268 13.027 5.397 13.483 ;
     RECT  6.732 13.433 7.038 13.567 ;
     RECT  7.776 13.085 8.694 13.567 ;
     RECT  6.732 13.567 8.694 13.595 ;
     RECT  6.732 13.595 8.097 13.631 ;
     RECT  10.044 12.821 20.502 13.675 ;
     RECT  21.492 12.907 21.51 13.771 ;
     RECT  2.232 13.483 5.397 13.865 ;
     RECT  21.42 13.771 21.51 14.011 ;
     RECT  8.856 13.867 9.162 14.045 ;
     RECT  2.268 13.865 5.397 14.099 ;
     RECT  21.348 14.011 21.51 14.141 ;
     RECT  6.84 13.631 8.097 14.377 ;
     RECT  10.044 13.675 20.538 14.377 ;
     RECT  5.115 14.099 5.397 14.521 ;
     RECT  6.804 14.377 8.097 14.521 ;
     RECT  8.856 14.045 9.018 14.521 ;
     RECT  0.324 14.587 0.342 14.683 ;
     RECT  9.936 14.377 20.538 14.755 ;
     RECT  0.216 14.683 0.342 14.813 ;
     RECT  9.9 14.755 20.538 14.909 ;
     RECT  2.268 14.099 4.05 14.923 ;
     RECT  5.115 14.521 5.742 14.945 ;
     RECT  6.804 14.521 9.018 14.953 ;
     RECT  6.768 14.953 9.018 15.061 ;
     RECT  2.268 14.923 4.158 15.187 ;
     RECT  5.115 14.945 5.397 15.187 ;
     RECT  21.42 14.141 21.51 15.211 ;
     RECT  0.144 15.067 0.162 15.293 ;
     RECT  2.268 15.187 5.397 15.592 ;
     RECT  10.224 14.909 20.538 15.595 ;
     RECT  6.768 15.061 9.198 15.727 ;
     RECT  2.232 15.592 5.397 15.755 ;
     RECT  6.732 15.727 9.198 15.787 ;
     RECT  10.224 15.595 20.574 15.787 ;
     RECT  0.216 15.691 0.342 15.821 ;
     RECT  6.732 15.787 20.574 15.827 ;
     RECT  0.216 15.821 0.234 15.917 ;
     RECT  21.348 15.211 21.51 16.027 ;
     RECT  6.768 15.827 20.574 16.075 ;
     RECT  21.312 16.027 21.51 16.075 ;
     RECT  6.768 16.075 21.51 16.301 ;
     RECT  21.312 16.301 21.51 16.397 ;
     RECT  6.768 16.301 20.538 16.439 ;
     RECT  10.008 16.439 20.538 16.529 ;
     RECT  21.348 16.397 21.51 16.529 ;
     RECT  6.768 16.439 9.234 16.541 ;
     RECT  6.768 16.541 9.162 16.771 ;
     RECT  10.116 16.529 20.538 16.835 ;
     RECT  6.732 16.771 9.162 16.877 ;
     RECT  6.732 16.877 8.838 17.041 ;
     RECT  6.264 17.041 8.838 17.105 ;
     RECT  0.108 17.077 0.126 17.117 ;
     RECT  10.152 16.835 20.538 17.339 ;
     RECT  21.348 16.529 21.474 17.371 ;
     RECT  19.872 17.339 20.538 17.411 ;
     RECT  6.264 17.105 8.55 17.483 ;
     RECT  6.84 17.483 8.55 17.549 ;
     RECT  7.092 17.549 8.55 17.651 ;
     RECT  21.348 17.371 21.51 17.755 ;
     RECT  7.164 17.651 8.55 17.899 ;
     RECT  7.164 17.899 9.162 17.947 ;
     RECT  19.872 17.411 20.502 18.091 ;
     RECT  7.164 17.947 9.234 18.173 ;
     RECT  8.82 18.173 9.234 18.185 ;
     RECT  2.268 15.755 5.397 18.187 ;
     RECT  2.196 18.187 5.397 18.293 ;
     RECT  9.036 18.185 9.234 18.427 ;
     RECT  0.144 18.283 0.162 18.461 ;
     RECT  2.268 18.293 5.397 18.491 ;
     RECT  21.276 17.755 21.51 18.509 ;
     RECT  9.036 18.427 9.27 18.571 ;
     RECT  10.152 17.339 19.062 18.571 ;
     RECT  9.036 18.571 19.062 18.619 ;
     RECT  19.836 18.091 20.502 18.619 ;
     RECT  7.164 18.173 8.097 18.667 ;
     RECT  21.348 18.509 21.51 18.701 ;
     RECT  6.732 18.667 8.097 18.797 ;
     RECT  9.036 18.619 20.502 18.931 ;
     RECT  21.384 18.701 21.51 18.959 ;
     RECT  0.216 18.859 0.342 18.989 ;
     RECT  0.216 18.989 0.234 19.133 ;
     RECT  21.384 18.959 21.474 19.139 ;
     RECT  8.82 18.931 20.502 19.291 ;
     RECT  2.304 18.491 5.397 19.483 ;
     RECT  6.516 19.381 6.534 19.543 ;
     RECT  7.38 18.797 8.097 19.543 ;
     RECT  8.82 19.291 20.538 19.607 ;
     RECT  10.08 19.607 20.538 19.679 ;
     RECT  6.516 19.543 8.097 19.813 ;
     RECT  8.82 19.607 9.234 19.813 ;
     RECT  6.516 19.813 9.234 19.921 ;
     RECT  21.384 19.139 21.438 19.96 ;
     RECT  21.384 19.96 21.474 19.997 ;
     RECT  6.264 19.921 9.234 20.039 ;
     RECT  21.384 19.997 21.438 20.059 ;
     RECT  6.264 20.039 9.198 20.075 ;
     RECT  6.768 20.075 9.198 20.189 ;
     RECT  21.312 20.059 21.438 20.189 ;
     RECT  6.768 20.189 9.162 20.309 ;
     RECT  10.152 19.679 20.538 20.381 ;
     RECT  6.768 20.309 6.894 20.462 ;
     RECT  2.268 19.483 5.397 20.491 ;
     RECT  6.804 20.462 6.894 20.615 ;
     RECT  2.232 20.491 5.397 20.687 ;
     RECT  6.84 20.615 6.894 21.091 ;
     RECT  7.815 20.309 9.162 21.091 ;
     RECT  0.144 20.923 0.162 21.101 ;
     RECT  10.26 20.381 20.538 21.163 ;
     RECT  10.26 21.163 20.574 21.271 ;
     RECT  21.42 20.189 21.438 21.355 ;
     RECT  6.84 21.091 9.162 21.451 ;
     RECT  10.008 21.271 20.574 21.451 ;
     RECT  6.84 21.451 20.574 21.461 ;
     RECT  21.312 21.355 21.438 21.547 ;
     RECT  19.8 21.461 20.574 21.787 ;
     RECT  21.312 21.547 21.51 21.787 ;
     RECT  6.84 21.461 19.026 21.965 ;
     RECT  0.324 21.547 0.342 22.012 ;
     RECT  19.8 21.787 21.51 22.013 ;
     RECT  6.84 21.965 6.858 22.027 ;
     RECT  6.804 22.027 6.858 22.081 ;
     RECT  6.768 22.081 6.858 22.109 ;
     RECT  0.18 22.012 0.342 22.205 ;
     RECT  7.704 21.965 19.026 22.235 ;
     RECT  6.768 22.109 6.822 22.315 ;
     RECT  21.348 22.013 21.51 22.397 ;
     RECT  7.815 22.235 19.026 22.459 ;
     RECT  19.8 22.013 20.61 22.459 ;
     RECT  7.815 22.459 20.61 22.469 ;
     RECT  6.696 22.315 6.822 22.513 ;
     RECT  6.516 22.513 6.822 22.649 ;
     RECT  0.324 22.205 0.342 22.781 ;
     RECT  19.872 22.469 20.61 22.781 ;
     RECT  6.804 22.649 6.822 22.811 ;
     RECT  2.268 20.687 5.397 22.843 ;
     RECT  2.268 22.843 5.49 23.021 ;
     RECT  19.872 22.781 20.574 23.081 ;
     RECT  6.84 22.987 6.858 23.117 ;
     RECT  19.872 23.081 20.538 23.351 ;
     RECT  7.056 23.287 7.074 23.431 ;
     RECT  7.815 22.469 19.134 23.431 ;
     RECT  21.384 22.397 21.51 23.789 ;
     RECT  7.056 23.431 19.134 23.851 ;
     RECT  19.872 23.351 20.502 23.851 ;
     RECT  7.056 23.851 20.502 24.097 ;
     RECT  6.912 24.097 20.502 24.233 ;
     RECT  7.524 24.233 20.502 24.269 ;
     RECT  0.324 24.235 0.342 24.283 ;
     RECT  2.268 23.021 5.397 24.283 ;
     RECT  7.815 24.269 19.098 24.359 ;
     RECT  21.42 23.789 21.51 24.359 ;
     RECT  0.144 24.283 0.342 24.413 ;
     RECT  6.768 24.367 6.786 24.467 ;
     RECT  9.108 24.359 9.45 24.503 ;
     RECT  10.224 24.359 19.098 24.509 ;
     RECT  2.16 24.283 5.397 24.665 ;
     RECT  6.228 24.475 6.246 24.665 ;
     RECT  21.42 24.359 21.474 24.667 ;
     RECT  2.196 24.665 5.397 24.893 ;
     RECT  9.108 24.503 9.234 24.941 ;
     RECT  0.144 24.413 0.162 24.989 ;
     RECT  21.24 24.667 21.474 24.989 ;
     RECT  10.26 24.509 19.098 25.003 ;
     RECT  19.836 24.269 20.502 25.003 ;
     RECT  21.312 24.989 21.474 25.085 ;
     RECT  9.108 24.941 9.162 25.169 ;
     RECT  7.815 24.359 8.298 25.195 ;
     RECT  10.26 25.003 20.502 25.243 ;
     RECT  2.232 24.893 5.397 25.277 ;
     RECT  7.815 25.195 8.982 25.285 ;
     RECT  10.224 25.243 20.502 25.349 ;
     RECT  7.2 25.285 8.982 25.411 ;
     RECT  10.26 25.349 20.502 25.435 ;
     RECT  21.384 25.085 21.474 25.675 ;
     RECT  6.912 25.411 8.982 25.753 ;
     RECT  6.768 25.753 8.982 25.979 ;
     RECT  7.704 25.979 8.982 25.997 ;
     RECT  10.26 25.435 20.538 26.051 ;
     RECT  21.384 25.675 21.51 26.093 ;
     RECT  7.815 25.997 8.982 26.095 ;
     RECT  6.768 25.979 6.93 26.131 ;
     RECT  7.815 26.095 9.234 26.131 ;
     RECT  10.26 26.051 20.502 26.198 ;
     RECT  6.264 26.131 6.93 26.357 ;
     RECT  21.42 26.093 21.51 26.477 ;
     RECT  0.144 26.443 0.162 26.621 ;
     RECT  2.268 25.277 5.397 26.635 ;
     RECT  7.815 26.131 9.378 26.671 ;
     RECT  10.188 26.198 20.502 26.671 ;
     RECT  2.232 26.635 5.397 26.672 ;
     RECT  21.456 26.477 21.51 26.789 ;
     RECT  21.456 26.789 21.474 26.969 ;
     RECT  7.815 26.671 20.502 26.971 ;
     RECT  7.815 26.971 20.538 27.131 ;
     RECT  6.84 26.357 6.93 27.139 ;
     RECT  7.815 27.131 9.378 27.139 ;
     RECT  6.84 27.139 9.378 27.163 ;
     RECT  2.268 26.672 5.397 27.167 ;
     RECT  6.696 27.163 9.378 27.341 ;
     RECT  21.312 27.355 21.33 27.485 ;
     RECT  10.116 27.131 20.538 27.599 ;
     RECT  6.732 27.341 9.378 27.707 ;
     RECT  6.732 27.707 8.802 27.869 ;
     RECT  6.732 27.869 7.002 27.905 ;
     RECT  21.384 27.739 21.402 27.917 ;
     RECT  6.732 27.905 6.966 27.941 ;
     RECT  2.304 27.167 5.397 28.123 ;
     RECT  7.815 27.869 8.802 28.139 ;
     RECT  7.815 28.139 8.55 28.247 ;
     RECT  0.144 27.739 0.162 28.253 ;
     RECT  6.768 27.941 6.966 28.445 ;
     RECT  2.268 28.123 5.397 28.589 ;
     RECT  10.188 27.599 20.538 28.651 ;
     RECT  6.948 28.445 6.966 28.687 ;
     RECT  6.948 28.687 7.038 28.715 ;
     RECT  10.044 28.651 20.538 28.733 ;
     RECT  21.492 27.931 21.51 28.795 ;
     RECT  7.02 28.715 7.038 28.859 ;
     RECT  21.42 28.795 21.51 28.859 ;
     RECT  10.116 28.733 20.538 29.062 ;
     RECT  7.815 28.247 8.406 29.065 ;
     RECT  7.38 29.065 8.406 29.335 ;
     RECT  9.144 28.939 9.162 29.335 ;
     RECT  10.116 29.062 20.502 29.497 ;
     RECT  7.38 29.335 9.162 29.563 ;
     RECT  10.08 29.497 20.502 29.563 ;
     RECT  0.324 28.651 0.342 29.597 ;
     RECT  7.38 29.563 20.502 29.597 ;
     RECT  21.492 28.859 21.51 29.659 ;
     RECT  7.38 29.597 9.486 29.731 ;
     RECT  6.84 29.731 9.486 29.795 ;
     RECT  6.84 29.795 6.966 29.867 ;
     RECT  7.815 29.795 9.486 30.077 ;
     RECT  7.815 30.077 8.226 30.101 ;
     RECT  8.964 30.077 9.486 30.379 ;
     RECT  10.26 29.597 20.502 30.379 ;
     RECT  0.144 30.235 0.162 30.523 ;
     RECT  6.948 29.867 6.966 30.577 ;
     RECT  7.815 30.101 8.097 30.577 ;
     RECT  0.144 30.523 0.342 30.619 ;
     RECT  0.108 30.619 0.342 30.653 ;
     RECT  0.108 30.653 0.27 30.677 ;
     RECT  6.948 30.577 8.097 30.713 ;
     RECT  0.144 30.677 0.27 30.749 ;
     RECT  6.948 30.713 6.966 30.763 ;
     RECT  7.815 30.713 8.097 30.955 ;
     RECT  8.964 30.379 20.502 30.955 ;
     RECT  0.144 30.749 0.234 31.085 ;
     RECT  6.696 30.763 6.966 31.261 ;
     RECT  21.312 29.659 21.51 31.339 ;
     RECT  6.264 31.261 6.966 31.415 ;
     RECT  6.804 31.415 6.966 31.459 ;
     RECT  7.815 30.955 20.502 31.459 ;
     RECT  0.216 31.085 0.234 31.627 ;
     RECT  0.216 31.627 0.342 31.757 ;
     RECT  0.216 31.757 0.234 31.853 ;
     RECT  6.804 31.459 20.502 32.197 ;
     RECT  6.732 32.197 20.502 32.251 ;
     RECT  2.304 28.589 5.397 32.341 ;
     RECT  2.304 32.341 5.706 32.347 ;
     RECT  6.66 32.251 20.502 32.443 ;
     RECT  21.276 31.339 21.51 32.443 ;
     RECT  2.268 32.347 5.706 32.467 ;
     RECT  0.144 32.299 0.162 32.477 ;
     RECT  6.66 32.443 21.51 32.477 ;
     RECT  6.804 32.477 21.51 32.495 ;
     RECT  2.268 32.467 5.742 32.567 ;
     RECT  9.324 32.495 21.51 32.567 ;
     RECT  2.304 32.567 5.742 32.837 ;
     RECT  6.804 32.495 8.406 33.259 ;
     RECT  6.768 33.259 8.406 33.305 ;
     RECT  6.84 33.305 8.406 33.341 ;
     RECT  21.312 32.567 21.51 33.341 ;
     RECT  9.324 32.567 20.502 33.355 ;
     RECT  2.304 32.837 5.706 33.377 ;
     RECT  2.304 33.377 5.397 33.451 ;
     RECT  7.416 33.341 8.406 33.485 ;
     RECT  7.815 33.485 8.406 33.547 ;
     RECT  9.144 33.355 20.502 33.547 ;
     RECT  21.312 33.341 21.474 33.581 ;
     RECT  7.815 33.547 20.502 33.739 ;
     RECT  2.232 33.451 5.397 33.845 ;
     RECT  21.42 33.581 21.474 34.079 ;
     RECT  0.324 32.923 0.342 34.157 ;
     RECT  7.815 33.739 20.538 34.231 ;
     RECT  21.42 34.079 21.438 34.315 ;
     RECT  7.776 34.231 20.538 34.421 ;
     RECT  21.348 34.315 21.438 34.493 ;
     RECT  6.804 34.357 6.822 34.501 ;
     RECT  6.804 34.501 6.894 34.591 ;
     RECT  7.776 34.421 20.502 34.591 ;
     RECT  6.804 34.591 20.502 34.619 ;
     RECT  21.42 34.493 21.438 34.843 ;
     RECT  0.108 34.843 0.126 34.891 ;
     RECT  0.108 34.891 0.198 35.131 ;
     RECT  2.268 33.845 5.397 35.213 ;
     RECT  6.804 34.619 20.466 35.267 ;
     RECT  21.42 34.843 21.51 35.323 ;
     RECT  6.804 35.267 6.822 35.339 ;
     RECT  7.815 35.267 20.466 35.357 ;
     RECT  10.008 35.357 20.466 35.419 ;
     RECT  0.108 35.131 0.342 35.429 ;
     RECT  7.815 35.357 8.982 35.429 ;
     RECT  7.815 35.429 8.802 35.465 ;
     RECT  0.18 35.429 0.342 35.837 ;
     RECT  10.008 35.419 20.502 35.969 ;
     RECT  2.268 35.213 3.978 36.005 ;
     RECT  21.384 35.323 21.51 36.043 ;
     RECT  2.304 36.005 3.978 36.211 ;
     RECT  7.815 35.465 8.73 36.235 ;
     RECT  12.888 35.969 20.502 36.239 ;
     RECT  10.008 35.969 12.114 36.247 ;
     RECT  7.632 36.235 9.09 36.275 ;
     RECT  21.312 36.043 21.51 36.509 ;
     RECT  7.815 36.275 9.09 36.517 ;
     RECT  20.232 36.239 20.502 36.517 ;
     RECT  2.304 36.211 4.338 36.589 ;
     RECT  5.115 35.213 5.397 36.589 ;
     RECT  9.936 36.247 12.114 36.625 ;
     RECT  9.9 36.625 12.114 36.763 ;
     RECT  12.888 36.239 19.314 36.763 ;
     RECT  0.324 35.837 0.342 36.845 ;
     RECT  6.912 36.553 6.93 36.859 ;
     RECT  7.815 36.517 9.126 36.859 ;
     RECT  9.9 36.763 19.314 36.859 ;
     RECT  6.804 36.859 6.93 36.959 ;
     RECT  6.84 36.959 6.93 37.051 ;
     RECT  7.815 36.859 19.314 37.051 ;
     RECT  20.232 36.517 20.574 37.099 ;
     RECT  21.312 36.509 21.438 37.099 ;
     RECT  2.304 36.589 5.397 37.192 ;
     RECT  6.84 37.051 19.314 37.291 ;
     RECT  20.232 37.099 21.438 37.291 ;
     RECT  6.84 37.291 21.438 37.339 ;
     RECT  6.84 37.339 21.51 37.469 ;
     RECT  7.776 37.469 21.51 37.565 ;
     RECT  21.312 37.565 21.51 37.613 ;
     RECT  6.84 37.469 6.966 37.867 ;
     RECT  7.776 37.565 20.538 37.895 ;
     RECT  7.815 37.895 20.538 37.931 ;
     RECT  2.268 37.192 5.397 37.967 ;
     RECT  6.768 37.867 6.966 37.967 ;
     RECT  0.144 37.387 0.162 37.997 ;
     RECT  6.948 37.967 6.966 38.129 ;
     RECT  7.815 37.931 8.19 38.129 ;
     RECT  9 37.931 20.538 38.189 ;
     RECT  9.072 38.189 20.538 38.471 ;
     RECT  0.324 38.299 0.342 38.525 ;
     RECT  2.304 37.967 5.397 38.713 ;
     RECT  21.348 37.613 21.51 38.731 ;
     RECT  2.268 38.713 5.397 38.923 ;
     RECT  6.768 38.911 6.786 39.091 ;
     RECT  2.232 38.923 5.397 39.245 ;
     RECT  6.768 39.091 6.93 39.325 ;
     RECT  9.072 38.471 9.234 39.341 ;
     RECT  6.768 39.325 7.002 39.451 ;
     RECT  6.732 39.451 7.002 39.515 ;
     RECT  21.312 38.731 21.51 39.551 ;
     RECT  6.732 39.515 6.966 39.581 ;
     RECT  10.116 38.471 20.538 39.757 ;
     RECT  2.268 39.245 5.397 39.785 ;
     RECT  9.972 39.757 20.538 39.821 ;
     RECT  6.948 39.581 6.966 39.857 ;
     RECT  0.324 39.931 0.342 40.027 ;
     RECT  0.216 40.027 0.342 40.061 ;
     RECT  21.348 39.551 21.51 40.127 ;
     RECT  2.304 39.785 5.397 40.199 ;
     RECT  0.216 40.061 0.234 40.205 ;
     RECT  2.304 40.199 4.338 40.559 ;
     RECT  6.912 40.531 6.93 40.603 ;
     RECT  7.815 38.129 8.097 40.711 ;
     RECT  9.036 39.595 9.054 40.711 ;
     RECT  21.348 40.127 21.474 40.795 ;
     RECT  7.815 40.711 9.054 40.909 ;
     RECT  10.044 39.821 20.538 40.973 ;
     RECT  2.304 40.559 4.302 40.981 ;
     RECT  6.876 40.603 6.93 40.981 ;
     RECT  7.815 40.909 9.27 40.981 ;
     RECT  19.836 40.973 20.538 40.987 ;
     RECT  2.268 40.981 4.302 41.021 ;
     RECT  10.044 40.973 19.026 41.071 ;
     RECT  19.836 40.987 20.574 41.083 ;
     RECT  21.312 40.795 21.474 41.083 ;
     RECT  7.668 40.981 9.27 41.099 ;
     RECT  5.115 40.199 5.397 41.143 ;
     RECT  6.732 40.981 6.93 41.171 ;
     RECT  0.324 41.083 0.342 41.213 ;
     RECT  7.74 41.099 9.27 41.251 ;
     RECT  10.008 41.071 19.026 41.251 ;
     RECT  2.304 41.021 4.302 41.341 ;
     RECT  5.112 41.143 5.397 41.341 ;
     RECT  0.144 41.371 0.162 41.549 ;
     RECT  7.74 41.251 19.026 41.549 ;
     RECT  19.836 41.083 21.474 41.611 ;
     RECT  7.74 41.549 8.097 41.899 ;
     RECT  7.704 41.899 8.097 41.945 ;
     RECT  6.768 41.171 6.93 41.947 ;
     RECT  19.836 41.611 21.51 41.981 ;
     RECT  21.276 41.981 21.51 42.029 ;
     RECT  6.732 41.947 6.93 42.077 ;
     RECT  9.036 41.549 19.026 42.125 ;
     RECT  9.36 42.125 9.378 42.173 ;
     RECT  10.152 42.125 19.026 42.179 ;
     RECT  10.26 42.179 19.026 42.223 ;
     RECT  19.836 41.981 20.538 42.223 ;
     RECT  10.26 42.223 20.538 42.269 ;
     RECT  21.312 42.029 21.51 42.317 ;
     RECT  2.304 41.341 5.397 42.449 ;
     RECT  10.296 42.269 20.538 42.557 ;
     RECT  6.84 42.077 6.93 42.629 ;
     RECT  7.815 41.945 8.097 42.961 ;
     RECT  10.296 42.557 20.502 43.105 ;
     RECT  2.304 42.449 3.942 43.195 ;
     RECT  7.815 42.961 8.694 43.231 ;
     RECT  4.824 42.449 5.397 43.259 ;
     RECT  7.776 43.231 8.694 43.339 ;
     RECT  2.268 43.195 3.942 43.411 ;
     RECT  7.776 43.339 9.018 43.411 ;
     RECT  9.864 43.105 20.502 43.411 ;
     RECT  5.076 43.259 5.397 43.529 ;
     RECT  21.384 42.317 21.51 43.529 ;
     RECT  7.776 43.411 20.502 43.579 ;
     RECT  2.268 43.411 4.338 43.601 ;
     RECT  7.776 43.579 20.538 43.609 ;
     RECT  2.304 43.601 4.338 43.673 ;
     RECT  7.596 43.609 20.538 43.709 ;
     RECT  7.668 43.709 20.538 43.835 ;
     RECT  5.115 43.529 5.397 44.059 ;
     RECT  6.84 42.629 6.858 44.221 ;
     RECT  5.115 44.059 5.922 44.375 ;
     RECT  0.144 43.675 0.162 44.381 ;
     RECT  6.768 44.221 6.858 44.383 ;
     RECT  6.12 44.383 6.858 44.411 ;
     RECT  8.856 43.835 20.538 44.411 ;
     RECT  6.12 44.411 6.138 44.429 ;
     RECT  2.304 43.673 4.23 44.455 ;
     RECT  5.115 44.375 5.397 44.455 ;
     RECT  9 44.411 20.538 44.455 ;
     RECT  7.668 43.835 8.097 44.491 ;
     RECT  21.42 43.529 21.51 44.491 ;
     RECT  0.18 44.491 0.45 44.669 ;
     RECT  0.18 44.669 0.378 44.717 ;
     RECT  0.18 44.717 0.342 44.909 ;
     RECT  6.912 44.491 8.097 44.951 ;
     RECT  9 44.455 20.574 45.101 ;
     RECT  2.304 44.455 5.397 45.193 ;
     RECT  21.384 44.491 21.51 45.259 ;
     RECT  6.912 44.951 6.93 45.265 ;
     RECT  9 45.101 20.538 45.293 ;
     RECT  2.304 45.193 5.922 45.301 ;
     RECT  6.732 45.265 6.93 45.301 ;
     RECT  7.815 44.951 8.097 45.301 ;
     RECT  9 45.293 20.502 45.301 ;
     RECT  2.304 45.301 6.93 45.403 ;
     RECT  2.268 45.403 6.93 45.419 ;
     RECT  2.268 45.419 5.958 45.491 ;
     RECT  7.815 45.301 20.502 45.689 ;
     RECT  7.815 45.689 8.946 45.725 ;
     RECT  7.815 45.725 8.874 45.769 ;
     RECT  0.144 45.307 0.162 45.787 ;
     RECT  21.348 45.259 21.51 45.787 ;
     RECT  2.268 45.491 5.397 45.797 ;
     RECT  0.144 45.787 0.234 45.805 ;
     RECT  6.732 45.419 6.93 45.841 ;
     RECT  7.704 45.769 8.874 45.841 ;
     RECT  0.144 45.805 0.378 46.013 ;
     RECT  21.312 45.787 21.51 46.157 ;
     RECT  6.732 45.841 8.874 46.409 ;
     RECT  9.972 45.689 20.502 46.471 ;
     RECT  6.804 46.409 8.874 46.499 ;
     RECT  9.9 46.471 20.502 46.543 ;
     RECT  0.144 46.013 0.342 46.637 ;
     RECT  0.144 46.637 0.162 46.733 ;
     RECT  9.684 46.543 20.502 46.769 ;
     RECT  6.84 46.499 8.874 46.777 ;
     RECT  21.384 46.157 21.51 46.877 ;
     RECT  2.304 45.797 5.397 46.987 ;
     RECT  2.268 46.987 5.397 47.069 ;
     RECT  6.84 46.777 9.162 47.075 ;
     RECT  2.268 47.069 4.338 47.183 ;
     RECT  6.84 47.075 8.838 47.183 ;
     RECT  6.84 47.183 8.55 47.587 ;
     RECT  6.732 47.587 8.55 47.623 ;
     RECT  21.42 46.877 21.51 47.659 ;
     RECT  21.348 47.659 21.51 47.687 ;
     RECT  2.304 47.183 4.338 47.857 ;
     RECT  5.076 47.069 5.397 47.857 ;
     RECT  21.348 47.687 21.366 47.885 ;
     RECT  10.116 46.769 20.502 47.899 ;
     RECT  0.324 47.563 0.342 47.995 ;
     RECT  6.66 47.623 8.55 48.091 ;
     RECT  0.324 47.995 0.45 48.173 ;
     RECT  0.324 48.173 0.378 48.221 ;
     RECT  0.324 48.221 0.342 48.235 ;
     RECT  6.66 48.091 8.622 48.263 ;
     RECT  10.116 47.899 20.538 48.271 ;
     RECT  0.18 48.235 0.342 48.413 ;
     RECT  9.936 48.271 20.538 48.425 ;
     RECT  9.144 48.427 9.162 48.467 ;
     RECT  2.304 47.857 5.397 48.541 ;
     RECT  10.116 48.425 20.538 48.569 ;
     RECT  6.66 48.263 8.19 48.811 ;
     RECT  6.624 48.811 8.19 48.929 ;
     RECT  10.152 48.569 20.538 49.001 ;
     RECT  6.732 48.929 8.19 49.085 ;
     RECT  2.268 48.541 5.397 49.133 ;
     RECT  6.732 49.085 8.097 49.199 ;
     RECT  6.732 49.199 6.966 49.235 ;
     RECT  9.108 49.279 9.126 49.291 ;
     RECT  9.108 49.291 9.306 49.351 ;
     RECT  9.108 49.351 9.378 49.387 ;
     RECT  10.152 49.001 20.502 49.387 ;
     RECT  21.42 48.715 21.438 49.483 ;
     RECT  6.732 49.235 6.858 49.505 ;
     RECT  9.108 49.387 20.502 49.505 ;
     RECT  0.324 49.387 0.342 49.517 ;
     RECT  9.108 49.505 9.45 49.565 ;
     RECT  21.42 49.483 21.51 49.576 ;
     RECT  9.144 49.565 9.45 49.577 ;
     RECT  21.348 49.576 21.51 49.585 ;
     RECT  6.84 49.505 6.858 49.739 ;
     RECT  21.348 49.585 21.582 49.867 ;
     RECT  7.815 49.199 8.097 50.107 ;
     RECT  2.304 49.133 5.397 50.152 ;
     RECT  10.188 49.505 20.502 50.251 ;
     RECT  2.268 50.152 5.397 50.279 ;
     RECT  9.144 49.577 9.162 50.323 ;
     RECT  10.08 50.251 20.502 50.323 ;
     RECT  9.144 50.323 20.502 50.381 ;
     RECT  6.984 50.107 8.097 50.593 ;
     RECT  9.144 50.381 9.234 50.621 ;
     RECT  21.312 49.867 21.582 50.717 ;
     RECT  6.984 50.593 8.298 50.855 ;
     RECT  9.144 50.621 9.162 50.935 ;
     RECT  6.228 50.899 6.246 50.971 ;
     RECT  6.984 50.855 8.097 50.971 ;
     RECT  6.228 50.971 8.097 50.999 ;
     RECT  6.876 50.999 8.097 51.089 ;
     RECT  0.144 50.923 0.162 51.115 ;
     RECT  0.144 51.115 0.234 51.197 ;
     RECT  2.268 50.279 4.23 51.331 ;
     RECT  9.036 50.935 9.162 51.439 ;
     RECT  10.008 50.381 20.502 51.475 ;
     RECT  8.82 51.439 9.162 51.511 ;
     RECT  9.9 51.475 20.502 51.511 ;
     RECT  8.82 51.511 20.502 51.547 ;
     RECT  2.268 51.331 4.266 51.691 ;
     RECT  5.115 50.279 5.397 51.691 ;
     RECT  7.596 51.089 8.097 51.871 ;
     RECT  8.82 51.547 20.538 51.871 ;
     RECT  0.216 51.197 0.234 51.883 ;
     RECT  7.596 51.871 20.538 51.883 ;
     RECT  21.42 50.717 21.582 51.899 ;
     RECT  7.596 51.883 20.574 51.907 ;
     RECT  6.84 51.907 20.574 51.943 ;
     RECT  6.372 51.943 20.574 51.971 ;
     RECT  21.42 51.899 21.51 51.979 ;
     RECT  10.116 51.971 20.574 52.043 ;
     RECT  6.372 51.971 9.378 52.141 ;
     RECT  0.216 51.883 0.342 52.171 ;
     RECT  2.268 51.691 5.397 52.205 ;
     RECT  21.312 51.979 21.51 52.205 ;
     RECT  10.188 52.043 20.574 52.249 ;
     RECT  0.108 52.171 0.342 52.277 ;
     RECT  0.18 52.277 0.342 52.301 ;
     RECT  0.18 52.301 0.198 52.397 ;
     RECT  6.3 52.141 9.378 52.439 ;
     RECT  6.552 52.439 9.342 52.979 ;
     RECT  2.304 52.205 5.397 52.987 ;
     RECT  6.552 52.979 9.27 53.087 ;
     RECT  2.196 52.987 5.397 53.249 ;
     RECT  10.188 52.249 20.61 53.275 ;
     RECT  2.196 53.249 3.402 53.285 ;
     RECT  10.044 53.275 20.61 53.405 ;
     RECT  4.212 53.249 5.397 53.491 ;
     RECT  6.804 53.087 9.27 53.591 ;
     RECT  10.044 53.405 20.538 53.591 ;
     RECT  0.324 53.467 0.342 53.597 ;
     RECT  21.384 52.205 21.51 53.611 ;
     RECT  4.212 53.491 5.742 53.825 ;
     RECT  6.84 53.591 9.27 53.941 ;
     RECT  2.304 53.285 3.402 54.043 ;
     RECT  4.212 53.825 5.397 54.059 ;
     RECT  21.348 53.611 21.51 54.059 ;
     RECT  2.268 54.043 3.402 54.091 ;
     RECT  4.212 54.059 4.338 54.091 ;
     RECT  6.84 53.941 9.306 54.131 ;
     RECT  2.268 54.091 4.338 54.239 ;
     RECT  10.152 53.591 20.538 54.239 ;
     RECT  7.416 54.131 9.306 54.445 ;
     RECT  7.416 54.445 9.594 54.599 ;
     RECT  10.332 54.239 20.538 54.671 ;
     RECT  21.348 54.059 21.474 54.859 ;
     RECT  7.416 54.599 9.27 54.877 ;
     RECT  2.268 54.239 3.978 54.905 ;
     RECT  6.768 54.877 9.27 54.977 ;
     RECT  0.144 54.475 0.162 55.051 ;
     RECT  10.332 54.671 20.502 55.195 ;
     RECT  21.348 54.859 21.51 55.339 ;
     RECT  10.26 55.195 20.502 55.381 ;
     RECT  2.304 54.905 3.978 55.387 ;
     RECT  6.84 54.977 9.27 55.409 ;
     RECT  2.304 55.387 4.158 55.453 ;
     RECT  5.115 54.059 5.397 55.453 ;
     RECT  21.312 55.339 21.51 55.469 ;
     RECT  0.144 55.051 0.342 55.517 ;
     RECT  10.152 55.381 20.502 55.531 ;
     RECT  0.18 55.517 0.342 55.687 ;
     RECT  0.18 55.687 0.378 55.715 ;
     RECT  0.216 55.715 0.378 55.805 ;
     RECT  10.152 55.531 20.538 55.993 ;
     RECT  10.08 55.993 20.538 56.093 ;
     RECT  6.84 55.409 8.55 56.255 ;
     RECT  0.324 55.805 0.342 56.285 ;
     RECT  7.596 56.255 8.55 56.299 ;
     RECT  10.08 56.093 20.502 56.335 ;
     RECT  7.596 56.299 9.126 56.363 ;
     RECT  7.596 56.363 8.514 56.489 ;
     RECT  21.384 55.469 21.51 56.491 ;
     RECT  7.596 56.489 8.154 56.633 ;
     RECT  0.144 56.635 0.234 56.813 ;
     RECT  21.312 56.491 21.51 56.827 ;
     RECT  0.216 56.813 0.234 56.861 ;
     RECT  9.252 56.461 9.306 57.001 ;
     RECT  10.044 56.335 20.502 57.001 ;
     RECT  21.276 56.827 21.51 57.005 ;
     RECT  6.84 56.255 6.858 57.145 ;
     RECT  7.596 56.633 8.097 57.145 ;
     RECT  9.252 57.001 20.502 57.163 ;
     RECT  2.304 55.453 5.397 57.259 ;
     RECT  9.252 57.163 20.538 57.307 ;
     RECT  6.84 57.145 8.097 57.415 ;
     RECT  9.144 57.307 20.538 57.437 ;
     RECT  6.84 57.415 8.226 57.569 ;
     RECT  2.268 57.259 5.397 57.721 ;
     RECT  2.268 57.721 5.742 57.875 ;
     RECT  7.308 57.569 8.226 57.883 ;
     RECT  9.216 57.437 20.538 57.947 ;
     RECT  21.312 57.005 21.51 57.965 ;
     RECT  21.312 57.965 21.474 58.019 ;
     RECT  7.308 57.883 8.334 58.109 ;
     RECT  21.312 58.019 21.438 58.301 ;
     RECT  9.216 57.947 20.43 58.459 ;
     RECT  7.308 58.109 8.226 58.531 ;
     RECT  0.324 58.555 0.342 58.685 ;
     RECT  9.108 58.459 20.43 58.693 ;
     RECT  9.072 58.693 20.43 58.699 ;
     RECT  6.912 58.531 8.226 58.927 ;
     RECT  6.732 58.927 8.226 58.999 ;
     RECT  9.072 58.699 20.538 58.999 ;
     RECT  2.268 57.875 5.397 59.027 ;
     RECT  2.304 59.027 5.397 59.035 ;
     RECT  6.732 58.999 20.538 59.083 ;
     RECT  21.348 58.301 21.438 59.083 ;
     RECT  6.732 59.083 21.438 59.099 ;
     RECT  2.304 59.035 5.742 59.603 ;
     RECT  6.804 59.099 21.438 59.765 ;
     RECT  2.304 59.603 5.67 59.947 ;
     RECT  7.815 59.765 21.438 60.043 ;
     RECT  7.815 60.043 21.51 60.173 ;
     RECT  2.268 59.947 5.67 60.305 ;
     RECT  6.804 59.765 7.038 60.313 ;
     RECT  4.752 60.305 5.67 60.349 ;
     RECT  6.732 60.313 7.038 60.719 ;
     RECT  7.815 60.173 20.466 60.809 ;
     RECT  6.768 60.719 7.038 60.817 ;
     RECT  7.815 60.809 20.43 60.817 ;
     RECT  6.768 60.817 20.43 60.845 ;
     RECT  0.144 59.515 0.162 60.989 ;
     RECT  4.752 60.349 5.706 61.051 ;
     RECT  2.268 60.305 3.618 61.151 ;
     RECT  2.304 61.151 3.618 61.159 ;
     RECT  4.428 61.051 5.706 61.159 ;
     RECT  0.216 61.243 0.342 61.373 ;
     RECT  0.216 61.373 0.234 61.565 ;
     RECT  6.768 60.845 20.25 61.591 ;
     RECT  2.304 61.159 5.706 61.627 ;
     RECT  6.66 61.591 20.25 61.627 ;
     RECT  2.304 61.627 20.25 61.819 ;
     RECT  21.204 60.173 21.51 61.819 ;
     RECT  2.304 61.819 21.51 62.069 ;
     RECT  6.732 62.069 21.51 62.159 ;
     RECT  6.732 62.159 18.954 62.189 ;
     RECT  6.732 62.189 18.897 62.267 ;
     RECT  19.764 62.159 21.51 62.339 ;
     RECT  0.144 61.963 0.198 62.347 ;
     RECT  6.732 62.267 8.097 62.387 ;
     RECT  8.928 62.267 18.897 62.387 ;
     RECT  2.304 62.069 5.706 62.429 ;
     RECT  19.8 62.339 21.51 62.429 ;
     RECT  0.144 62.347 0.342 62.437 ;
     RECT  8.928 62.387 18.81 62.465 ;
     RECT  8.928 62.465 11.034 62.477 ;
     RECT  2.415 62.429 5.706 62.501 ;
     RECT  9.036 62.477 11.034 62.501 ;
     RECT  11.952 62.465 18.81 62.501 ;
     RECT  19.944 62.429 21.51 62.501 ;
     RECT  9.036 62.501 10.998 62.525 ;
     RECT  13.215 62.501 18.81 62.537 ;
     RECT  0.144 62.437 0.378 62.573 ;
     RECT  2.415 62.501 3.978 62.573 ;
     RECT  6.732 62.387 7.905 62.573 ;
     RECT  11.952 62.501 12.402 62.573 ;
     RECT  19.944 62.501 21.474 62.573 ;
     RECT  2.415 62.573 3.15 62.609 ;
     RECT  5.076 62.501 5.205 62.609 ;
     RECT  9.576 62.525 10.605 62.609 ;
     RECT  12.384 62.573 12.402 62.609 ;
     RECT  2.415 62.609 3.078 62.657 ;
     RECT  5.115 62.609 5.205 62.657 ;
     RECT  7.815 62.573 7.905 62.657 ;
     RECT  10.188 62.609 10.605 62.657 ;
     RECT  13.215 62.537 13.305 62.657 ;
     RECT  14.148 62.537 18.81 62.657 ;
     RECT  0.18 62.573 0.198 62.669 ;
     RECT  16.056 62.657 18.81 62.669 ;
     RECT  3.06 62.657 3.078 62.699 ;
     RECT  6.732 62.573 7.002 62.699 ;
     RECT  10.188 62.657 10.278 62.699 ;
     RECT  16.056 62.669 18.09 62.699 ;
     RECT  21.456 62.573 21.474 62.699 ;
     RECT  14.148 62.657 15.21 62.735 ;
     RECT  16.056 62.699 17.226 62.735 ;
     RECT  3.96 62.573 3.978 62.765 ;
     RECT  14.58 62.735 15.21 62.765 ;
     RECT  14.832 62.765 15.21 62.807 ;
     RECT  16.956 62.735 17.226 62.807 ;
     RECT  19.944 62.573 19.962 62.807 ;
     RECT  15.192 62.807 15.21 63.821 ;
    LAYER M4 ;
     RECT  0.084 0.624 0.137 0.648 ;
     RECT  0.06 0.648 0.137 0.72 ;
     RECT  0.084 0.72 0.137 0.744 ;
     RECT  0.06 0.744 0.137 0.816 ;
     RECT  0.084 0.816 0.137 0.84 ;
     RECT  0.06 0.84 0.137 0.96 ;
     RECT  0.084 0.96 0.137 0.984 ;
     RECT  0.06 0.984 0.137 1.056 ;
     RECT  0.084 1.056 0.137 1.08 ;
     RECT  0.06 1.08 0.137 1.152 ;
     RECT  0.084 1.152 0.137 1.176 ;
     RECT  0.06 1.176 0.137 1.248 ;
     RECT  0.084 1.248 0.137 1.272 ;
     RECT  0.06 1.272 0.137 1.344 ;
     RECT  0.084 1.344 0.137 1.368 ;
     RECT  0.06 1.368 0.137 1.44 ;
     RECT  0.084 1.44 0.137 1.464 ;
     RECT  0.06 1.464 0.137 1.536 ;
     RECT  0.084 1.536 0.137 1.56 ;
     RECT  0.06 1.56 0.137 1.632 ;
     RECT  0.084 1.632 0.137 1.656 ;
     RECT  0.06 1.656 0.137 1.728 ;
     RECT  0.084 1.728 0.137 1.752 ;
     RECT  0.06 1.752 0.137 1.824 ;
     RECT  0.084 1.824 0.137 1.848 ;
     RECT  0.06 1.848 0.137 1.92 ;
     RECT  0.084 1.92 0.137 1.944 ;
     RECT  0.06 1.944 0.137 2.016 ;
     RECT  0.084 2.016 0.137 2.04 ;
     RECT  0.06 2.04 0.137 2.112 ;
     RECT  0.084 2.112 0.137 2.136 ;
     RECT  0.06 2.136 0.137 2.256 ;
     RECT  0.084 2.256 0.137 2.28 ;
     RECT  0.06 2.28 0.137 2.352 ;
     RECT  0.084 2.352 0.137 2.376 ;
     RECT  0.06 2.376 0.137 2.448 ;
     RECT  0.084 2.448 0.137 2.472 ;
     RECT  0.06 2.472 0.137 2.544 ;
     RECT  0.084 2.544 0.137 2.568 ;
     RECT  0.06 2.568 0.137 2.64 ;
     RECT  0.084 2.64 0.137 2.664 ;
     RECT  0.06 2.664 0.137 2.736 ;
     RECT  0.084 2.736 0.137 2.76 ;
     RECT  0.06 2.76 0.137 2.832 ;
     RECT  0.084 2.832 0.137 2.856 ;
     RECT  0.06 2.856 0.137 2.928 ;
     RECT  0.084 2.928 0.137 2.952 ;
     RECT  0.06 2.952 0.137 3.024 ;
     RECT  0.084 3.024 0.137 3.048 ;
     RECT  0.06 3.048 0.137 3.12 ;
     RECT  0.084 3.12 0.137 3.144 ;
     RECT  0.06 3.144 0.137 3.216 ;
     RECT  0.084 3.216 0.137 3.24 ;
     RECT  0.06 3.24 0.137 3.312 ;
     RECT  0.084 3.312 0.137 3.336 ;
     RECT  0.06 3.336 0.137 3.408 ;
     RECT  0.084 3.408 0.137 3.432 ;
     RECT  0.06 3.432 0.137 3.552 ;
     RECT  0.084 3.552 0.137 3.576 ;
     RECT  0.06 3.576 0.137 3.648 ;
     RECT  0.084 3.648 0.137 3.672 ;
     RECT  0.06 3.672 0.137 3.744 ;
     RECT  0.084 3.744 0.137 3.768 ;
     RECT  0.06 3.768 0.137 3.84 ;
     RECT  0.084 3.84 0.137 3.864 ;
     RECT  0.06 3.864 0.137 3.936 ;
     RECT  0.084 3.936 0.137 3.96 ;
     RECT  0.06 3.96 0.137 4.032 ;
     RECT  0.084 4.032 0.137 4.056 ;
     RECT  0.06 4.056 0.137 4.128 ;
     RECT  0.084 4.128 0.137 4.152 ;
     RECT  0.06 4.152 0.137 4.224 ;
     RECT  0.084 4.224 0.137 4.248 ;
     RECT  0.06 4.248 0.137 4.32 ;
     RECT  0.084 4.32 0.137 4.344 ;
     RECT  0.06 4.344 0.137 4.416 ;
     RECT  0.084 4.416 0.137 4.44 ;
     RECT  0.06 4.44 0.137 4.512 ;
     RECT  0.084 4.512 0.137 4.536 ;
     RECT  0.06 4.536 0.137 4.608 ;
     RECT  0.084 4.608 0.137 4.632 ;
     RECT  0.06 4.632 0.137 4.704 ;
     RECT  0.084 4.704 0.137 4.728 ;
     RECT  0.06 4.728 0.137 4.848 ;
     RECT  0.084 4.848 0.137 4.872 ;
     RECT  0.06 4.872 0.137 4.944 ;
     RECT  0.084 4.944 0.137 4.968 ;
     RECT  0.06 4.968 0.137 5.04 ;
     RECT  0.084 5.04 0.137 5.064 ;
     RECT  0.06 5.064 0.137 5.136 ;
     RECT  0.084 5.136 0.137 5.16 ;
     RECT  0.06 5.16 0.137 5.232 ;
     RECT  0.084 5.232 0.137 5.256 ;
     RECT  0.06 5.256 0.137 5.328 ;
     RECT  0.084 5.328 0.137 5.352 ;
     RECT  0.06 5.352 0.137 5.424 ;
     RECT  0.084 5.424 0.137 5.448 ;
     RECT  0.06 5.448 0.137 5.52 ;
     RECT  0.084 5.52 0.137 5.544 ;
     RECT  0.06 5.544 0.137 5.616 ;
     RECT  0.084 5.616 0.137 5.64 ;
     RECT  0.06 5.64 0.137 5.712 ;
     RECT  0.084 5.712 0.137 5.736 ;
     RECT  0.06 5.736 0.137 5.808 ;
     RECT  0.084 5.808 0.137 5.832 ;
     RECT  0.06 5.832 0.137 5.904 ;
     RECT  0.084 5.904 0.137 5.928 ;
     RECT  0.06 5.928 0.137 6 ;
     RECT  0.084 6 0.137 6.024 ;
     RECT  0.06 6.024 0.137 6.144 ;
     RECT  0.084 6.144 0.137 6.168 ;
     RECT  0.06 6.168 0.137 6.24 ;
     RECT  0.084 6.24 0.137 6.264 ;
     RECT  0.06 6.264 0.137 6.336 ;
     RECT  0.084 6.336 0.137 6.36 ;
     RECT  0.06 6.36 0.137 6.432 ;
     RECT  0.084 6.432 0.137 6.456 ;
     RECT  0.06 6.456 0.137 6.528 ;
     RECT  0.084 6.528 0.137 6.552 ;
     RECT  0.06 6.552 0.137 6.624 ;
     RECT  0.084 6.624 0.137 6.648 ;
     RECT  0.06 6.648 0.137 6.72 ;
     RECT  0.084 6.72 0.137 6.744 ;
     RECT  0.06 6.744 0.137 6.816 ;
     RECT  0.084 6.816 0.137 6.84 ;
     RECT  0.06 6.84 0.137 6.912 ;
     RECT  0.084 6.912 0.137 6.936 ;
     RECT  0.06 6.936 0.137 7.008 ;
     RECT  0.084 7.008 0.137 7.032 ;
     RECT  0.06 7.032 0.137 7.104 ;
     RECT  0.084 7.104 0.137 7.128 ;
     RECT  0.06 7.128 0.137 7.2 ;
     RECT  0.084 7.2 0.137 7.224 ;
     RECT  0.06 7.224 0.137 7.296 ;
     RECT  0.084 7.296 0.137 7.32 ;
     RECT  0.06 7.32 0.137 7.44 ;
     RECT  0.084 7.44 0.137 7.464 ;
     RECT  0.06 7.464 0.137 7.536 ;
     RECT  0.084 7.536 0.137 7.56 ;
     RECT  0.06 7.56 0.137 7.632 ;
     RECT  0.084 7.632 0.137 7.656 ;
     RECT  0.06 7.656 0.137 7.728 ;
     RECT  0.084 7.728 0.137 7.752 ;
     RECT  0.06 7.752 0.137 7.824 ;
     RECT  0.084 7.824 0.137 7.848 ;
     RECT  0.06 7.848 0.137 7.92 ;
     RECT  0.084 7.92 0.137 7.944 ;
     RECT  0.06 7.944 0.137 8.016 ;
     RECT  0.084 8.016 0.137 8.04 ;
     RECT  0.06 8.04 0.137 8.112 ;
     RECT  0.084 8.112 0.137 8.136 ;
     RECT  0.06 8.136 0.137 8.208 ;
     RECT  0.084 8.208 0.137 8.232 ;
     RECT  0.06 8.232 0.137 8.304 ;
     RECT  0.084 8.304 0.137 8.328 ;
     RECT  0.06 8.328 0.137 8.4 ;
     RECT  0.084 8.4 0.137 8.424 ;
     RECT  0.06 8.424 0.137 8.496 ;
     RECT  0.084 8.496 0.137 8.52 ;
     RECT  0.06 8.52 0.137 8.592 ;
     RECT  0.084 8.592 0.137 8.616 ;
     RECT  0.06 8.616 0.137 8.736 ;
     RECT  0.084 8.736 0.137 8.76 ;
     RECT  0.06 8.76 0.137 8.832 ;
     RECT  0.084 8.832 0.137 8.856 ;
     RECT  0.06 8.856 0.137 8.928 ;
     RECT  0.084 8.928 0.137 8.952 ;
     RECT  0.06 8.952 0.137 9.024 ;
     RECT  0.084 9.024 0.137 9.048 ;
     RECT  0.06 9.048 0.137 9.12 ;
     RECT  0.084 9.12 0.137 9.144 ;
     RECT  0.06 9.144 0.137 9.216 ;
     RECT  0.084 9.216 0.137 9.24 ;
     RECT  0.06 9.24 0.137 9.312 ;
     RECT  0.084 9.312 0.137 9.336 ;
     RECT  0.06 9.336 0.137 9.408 ;
     RECT  0.084 9.408 0.137 9.432 ;
     RECT  0.06 9.432 0.137 9.504 ;
     RECT  0.084 9.504 0.137 9.528 ;
     RECT  0.06 9.528 0.137 9.6 ;
     RECT  0.084 9.6 0.137 9.624 ;
     RECT  0.06 9.624 0.137 9.696 ;
     RECT  0.084 9.696 0.137 9.72 ;
     RECT  0.06 9.72 0.137 9.792 ;
     RECT  0.084 9.792 0.137 9.816 ;
     RECT  0.06 9.816 0.137 9.888 ;
     RECT  0.084 9.888 0.137 9.912 ;
     RECT  0.06 9.912 0.137 10.032 ;
     RECT  0.084 10.032 0.137 10.056 ;
     RECT  0.06 10.056 0.137 10.128 ;
     RECT  0.084 10.128 0.137 10.152 ;
     RECT  0.06 10.152 0.137 10.224 ;
     RECT  0.084 10.224 0.137 10.248 ;
     RECT  0.06 10.248 0.137 10.32 ;
     RECT  0.084 10.32 0.137 10.344 ;
     RECT  0.06 10.344 0.137 10.416 ;
     RECT  0.084 10.416 0.137 10.44 ;
     RECT  0.06 10.44 0.137 10.512 ;
     RECT  0.084 10.512 0.137 10.536 ;
     RECT  0.06 10.536 0.137 10.608 ;
     RECT  0.084 10.608 0.137 10.632 ;
     RECT  0.06 10.632 0.137 10.704 ;
     RECT  0.084 10.704 0.137 10.728 ;
     RECT  0.06 10.728 0.137 10.8 ;
     RECT  0.084 10.8 0.137 10.824 ;
     RECT  0.06 10.824 0.137 10.896 ;
     RECT  0.084 10.896 0.137 10.92 ;
     RECT  0.06 10.92 0.137 10.992 ;
     RECT  0.084 10.992 0.137 11.016 ;
     RECT  0.06 11.016 0.137 11.088 ;
     RECT  0.084 11.088 0.137 11.112 ;
     RECT  0.06 11.112 0.137 11.184 ;
     RECT  0.084 11.184 0.137 11.208 ;
     RECT  0.06 11.208 0.137 11.328 ;
     RECT  0.084 11.328 0.137 11.352 ;
     RECT  0.06 11.352 0.137 11.424 ;
     RECT  0.084 11.424 0.137 11.448 ;
     RECT  0.06 11.448 0.137 11.52 ;
     RECT  0.084 11.52 0.137 11.544 ;
     RECT  0.06 11.544 0.137 11.616 ;
     RECT  0.084 11.616 0.137 11.64 ;
     RECT  0.06 11.64 0.137 11.712 ;
     RECT  0.084 11.712 0.137 11.736 ;
     RECT  0.06 11.736 0.137 11.808 ;
     RECT  0.084 11.808 0.137 11.832 ;
     RECT  0.06 11.832 0.137 11.904 ;
     RECT  0.084 11.904 0.137 11.928 ;
     RECT  0.06 11.928 0.137 12 ;
     RECT  0.084 12 0.137 12.024 ;
     RECT  0.06 12.024 0.137 12.096 ;
     RECT  0.084 12.096 0.137 12.12 ;
     RECT  0.06 12.12 0.137 12.192 ;
     RECT  0.084 12.192 0.137 12.216 ;
     RECT  0.06 12.216 0.137 12.288 ;
     RECT  0.084 12.288 0.137 12.312 ;
     RECT  0.06 12.312 0.137 12.384 ;
     RECT  0.084 12.384 0.137 12.408 ;
     RECT  0.06 12.408 0.137 12.48 ;
     RECT  0.084 12.48 0.137 12.504 ;
     RECT  0.06 12.504 0.137 12.576 ;
     RECT  0.084 12.576 0.137 12.6 ;
     RECT  0.06 12.6 0.137 12.72 ;
     RECT  0.084 12.72 0.137 12.744 ;
     RECT  0.06 12.744 0.137 12.816 ;
     RECT  0.084 12.816 0.137 12.84 ;
     RECT  0.06 12.84 0.137 12.912 ;
     RECT  0.084 12.912 0.137 12.936 ;
     RECT  0.06 12.936 0.137 13.008 ;
     RECT  0.084 13.008 0.137 13.032 ;
     RECT  0.06 13.032 0.137 13.104 ;
     RECT  0.084 13.104 0.137 13.128 ;
     RECT  0.06 13.128 0.137 13.2 ;
     RECT  0.084 13.2 0.137 13.224 ;
     RECT  0.06 13.224 0.137 13.296 ;
     RECT  0.084 13.296 0.137 13.32 ;
     RECT  0.06 13.32 0.137 13.392 ;
     RECT  0.084 13.392 0.137 13.416 ;
     RECT  0.06 13.416 0.137 13.488 ;
     RECT  0.084 13.488 0.137 13.512 ;
     RECT  0.06 13.512 0.137 13.584 ;
     RECT  0.084 13.584 0.137 13.608 ;
     RECT  0.06 13.608 0.137 13.68 ;
     RECT  0.084 13.68 0.137 13.704 ;
     RECT  0.06 13.704 0.137 13.776 ;
     RECT  0.084 13.776 0.137 13.8 ;
     RECT  0.06 13.8 0.137 13.872 ;
     RECT  0.084 13.872 0.137 13.896 ;
     RECT  0.06 13.896 0.137 14.016 ;
     RECT  0.084 14.016 0.137 14.04 ;
     RECT  0.06 14.04 0.137 14.112 ;
     RECT  0.084 14.112 0.137 14.136 ;
     RECT  0.06 14.136 0.137 14.208 ;
     RECT  0.084 14.208 0.137 14.232 ;
     RECT  0.06 14.232 0.137 14.304 ;
     RECT  0.084 14.304 0.137 14.328 ;
     RECT  0.06 14.328 0.137 14.4 ;
     RECT  0.084 14.4 0.137 14.424 ;
     RECT  0.06 14.424 0.137 14.496 ;
     RECT  0.084 14.496 0.137 14.52 ;
     RECT  0.06 14.52 0.137 14.592 ;
     RECT  0.084 14.592 0.137 14.616 ;
     RECT  0.06 14.616 0.137 14.688 ;
     RECT  0.084 14.688 0.137 14.712 ;
     RECT  0.06 14.712 0.137 14.784 ;
     RECT  0.084 14.784 0.137 14.808 ;
     RECT  0.06 14.808 0.137 14.88 ;
     RECT  0.084 14.88 0.137 14.904 ;
     RECT  0.06 14.904 0.137 14.976 ;
     RECT  0.084 14.976 0.137 15 ;
     RECT  0.06 15 0.137 15.072 ;
     RECT  0.084 15.072 0.137 15.096 ;
     RECT  0.06 15.096 0.137 15.168 ;
     RECT  0.084 15.168 0.137 15.192 ;
     RECT  0.06 15.192 0.137 15.312 ;
     RECT  0.084 15.312 0.137 15.336 ;
     RECT  0.06 15.336 0.137 15.408 ;
     RECT  0.084 15.408 0.137 15.432 ;
     RECT  0.06 15.432 0.137 15.504 ;
     RECT  0.084 15.504 0.137 15.528 ;
     RECT  0.06 15.528 0.137 15.6 ;
     RECT  0.084 15.6 0.137 15.624 ;
     RECT  0.06 15.624 0.137 15.696 ;
     RECT  0.084 15.696 0.137 15.72 ;
     RECT  0.06 15.72 0.137 15.792 ;
     RECT  0.084 15.792 0.137 15.816 ;
     RECT  0.06 15.816 0.137 15.888 ;
     RECT  0.084 15.888 0.137 15.912 ;
     RECT  0.06 15.912 0.137 15.984 ;
     RECT  0.084 15.984 0.137 16.008 ;
     RECT  0.06 16.008 0.137 16.08 ;
     RECT  0.084 16.08 0.137 16.104 ;
     RECT  0.06 16.104 0.137 16.176 ;
     RECT  0.084 16.176 0.137 16.2 ;
     RECT  0.06 16.2 0.137 16.272 ;
     RECT  0.084 16.272 0.137 16.296 ;
     RECT  0.06 16.296 0.137 16.368 ;
     RECT  0.084 16.368 0.137 16.392 ;
     RECT  0.06 16.392 0.137 16.464 ;
     RECT  0.084 16.464 0.137 16.488 ;
     RECT  0.06 16.488 0.137 16.608 ;
     RECT  0.084 16.608 0.137 16.632 ;
     RECT  0.06 16.632 0.137 16.704 ;
     RECT  0.084 16.704 0.137 16.728 ;
     RECT  0.06 16.728 0.137 16.8 ;
     RECT  0.084 16.8 0.137 16.824 ;
     RECT  0.06 16.824 0.137 16.896 ;
     RECT  0.084 16.896 0.137 16.92 ;
     RECT  0.06 16.92 0.137 16.992 ;
     RECT  0.084 16.992 0.137 17.016 ;
     RECT  0.06 17.016 0.137 17.088 ;
     RECT  0.084 17.088 0.137 17.112 ;
     RECT  0.06 17.112 0.137 17.184 ;
     RECT  0.084 17.184 0.137 17.208 ;
     RECT  0.06 17.208 0.137 17.28 ;
     RECT  0.084 17.28 0.137 17.304 ;
     RECT  0.06 17.304 0.137 17.376 ;
     RECT  0.084 17.376 0.137 17.4 ;
     RECT  0.06 17.4 0.137 17.472 ;
     RECT  0.084 17.472 0.137 17.496 ;
     RECT  0.06 17.496 0.137 17.568 ;
     RECT  0.084 17.568 0.137 17.592 ;
     RECT  0.06 17.592 0.137 17.664 ;
     RECT  0.084 17.664 0.137 17.688 ;
     RECT  0.06 17.688 0.137 17.76 ;
     RECT  0.084 17.76 0.137 17.784 ;
     RECT  0.06 17.784 0.137 17.904 ;
     RECT  0.084 17.904 0.137 17.928 ;
     RECT  0.06 17.928 0.137 18 ;
     RECT  0.084 18 0.137 18.024 ;
     RECT  0.06 18.024 0.137 18.096 ;
     RECT  0.084 18.096 0.137 18.12 ;
     RECT  0.06 18.12 0.137 18.192 ;
     RECT  0.084 18.192 0.137 18.216 ;
     RECT  0.06 18.216 0.137 18.288 ;
     RECT  0.084 18.288 0.137 18.312 ;
     RECT  0.06 18.312 0.137 18.384 ;
     RECT  0.084 18.384 0.137 18.408 ;
     RECT  0.06 18.408 0.137 18.48 ;
     RECT  0.084 18.48 0.137 18.504 ;
     RECT  0.06 18.504 0.137 18.576 ;
     RECT  0.084 18.576 0.137 18.6 ;
     RECT  0.06 18.6 0.137 18.672 ;
     RECT  0.084 18.672 0.137 18.696 ;
     RECT  0.06 18.696 0.137 18.768 ;
     RECT  0.084 18.768 0.137 18.792 ;
     RECT  0.06 18.792 0.137 18.864 ;
     RECT  0.084 18.864 0.137 18.888 ;
     RECT  0.06 18.888 0.137 18.96 ;
     RECT  0.084 18.96 0.137 18.984 ;
     RECT  0.06 18.984 0.137 19.056 ;
     RECT  0.084 19.056 0.137 19.08 ;
     RECT  0.06 19.08 0.137 19.2 ;
     RECT  0.084 19.2 0.137 19.224 ;
     RECT  0.06 19.224 0.137 19.296 ;
     RECT  0.084 19.296 0.137 19.32 ;
     RECT  0.06 19.32 0.137 19.392 ;
     RECT  0.084 19.392 0.137 19.416 ;
     RECT  0.06 19.416 0.137 19.488 ;
     RECT  0.084 19.488 0.137 19.512 ;
     RECT  0.06 19.512 0.137 19.584 ;
     RECT  0.084 19.584 0.137 19.608 ;
     RECT  0.06 19.608 0.137 19.68 ;
     RECT  0.084 19.68 0.137 19.704 ;
     RECT  0.06 19.704 0.137 19.776 ;
     RECT  0.084 19.776 0.137 19.8 ;
     RECT  0.06 19.8 0.137 19.872 ;
     RECT  0.084 19.872 0.137 19.896 ;
     RECT  0.06 19.896 0.137 19.968 ;
     RECT  0.084 19.968 0.137 19.992 ;
     RECT  0.06 19.992 0.137 20.064 ;
     RECT  0.084 20.064 0.137 20.088 ;
     RECT  0.06 20.088 0.137 20.16 ;
     RECT  0.084 20.16 0.137 20.184 ;
     RECT  0.06 20.184 0.137 20.256 ;
     RECT  0.084 20.256 0.137 20.28 ;
     RECT  0.06 20.28 0.137 20.352 ;
     RECT  0.084 20.352 0.137 20.376 ;
     RECT  0.06 20.376 0.137 20.496 ;
     RECT  0.084 20.496 0.137 20.52 ;
     RECT  0.06 20.52 0.137 20.592 ;
     RECT  0.084 20.592 0.137 20.616 ;
     RECT  0.06 20.616 0.137 20.688 ;
     RECT  0.084 20.688 0.137 20.712 ;
     RECT  0.06 20.712 0.137 20.784 ;
     RECT  0.084 20.784 0.137 20.808 ;
     RECT  0.06 20.808 0.137 20.88 ;
     RECT  0.084 20.88 0.137 20.904 ;
     RECT  0.06 20.904 0.137 20.976 ;
     RECT  0.084 20.976 0.137 21 ;
     RECT  0.06 21 0.137 21.072 ;
     RECT  0.084 21.072 0.137 21.096 ;
     RECT  0.06 21.096 0.137 21.168 ;
     RECT  0.084 21.168 0.137 21.192 ;
     RECT  0.06 21.192 0.137 21.264 ;
     RECT  0.084 21.264 0.137 21.288 ;
     RECT  0.06 21.288 0.137 21.36 ;
     RECT  0.084 21.36 0.137 21.384 ;
     RECT  0.06 21.384 0.137 21.456 ;
     RECT  0.084 21.456 0.137 21.48 ;
     RECT  0.06 21.48 0.137 21.552 ;
     RECT  0.084 21.552 0.137 21.576 ;
     RECT  0.06 21.576 0.137 21.648 ;
     RECT  0.084 21.648 0.137 21.672 ;
     RECT  0.06 21.672 0.137 21.792 ;
     RECT  0.084 21.792 0.137 21.816 ;
     RECT  0.06 21.816 0.137 21.888 ;
     RECT  0.084 21.888 0.137 21.912 ;
     RECT  0.06 21.912 0.137 21.984 ;
     RECT  0.084 21.984 0.137 22.008 ;
     RECT  0.06 22.008 0.137 22.08 ;
     RECT  0.084 22.08 0.137 22.104 ;
     RECT  0.06 22.104 0.137 22.176 ;
     RECT  0.084 22.176 0.137 22.2 ;
     RECT  0.06 22.2 0.137 22.272 ;
     RECT  0.084 22.272 0.137 22.296 ;
     RECT  0.06 22.296 0.137 22.368 ;
     RECT  0.084 22.368 0.137 22.392 ;
     RECT  0.06 22.392 0.137 22.464 ;
     RECT  0.084 22.464 0.137 22.488 ;
     RECT  0.06 22.488 0.137 22.56 ;
     RECT  0.084 22.56 0.137 22.584 ;
     RECT  0.06 22.584 0.137 22.656 ;
     RECT  0.084 22.656 0.137 22.68 ;
     RECT  0.06 22.68 0.137 22.752 ;
     RECT  0.084 22.752 0.137 22.776 ;
     RECT  0.06 22.776 0.137 22.848 ;
     RECT  0.084 22.848 0.137 22.872 ;
     RECT  0.06 22.872 0.137 22.944 ;
     RECT  0.084 22.944 0.137 22.968 ;
     RECT  0.06 22.968 0.137 23.088 ;
     RECT  0.084 23.088 0.137 23.112 ;
     RECT  0.06 23.112 0.137 23.184 ;
     RECT  0.084 23.184 0.137 23.208 ;
     RECT  0.06 23.208 0.137 23.28 ;
     RECT  0.084 23.28 0.137 23.304 ;
     RECT  0.06 23.304 0.137 23.376 ;
     RECT  0.084 23.376 0.137 23.4 ;
     RECT  0.06 23.4 0.137 23.472 ;
     RECT  0.084 23.472 0.137 23.496 ;
     RECT  0.06 23.496 0.137 23.568 ;
     RECT  0.084 23.568 0.137 23.592 ;
     RECT  0.06 23.592 0.137 23.664 ;
     RECT  0.084 23.664 0.137 23.688 ;
     RECT  0.06 23.688 0.137 23.76 ;
     RECT  0.084 23.76 0.137 23.784 ;
     RECT  0.06 23.784 0.137 23.856 ;
     RECT  0.084 23.856 0.137 23.88 ;
     RECT  0.06 23.88 0.137 23.952 ;
     RECT  0.084 23.952 0.137 23.976 ;
     RECT  0.06 23.976 0.137 24.048 ;
     RECT  0.084 24.048 0.137 24.072 ;
     RECT  0.06 24.072 0.137 24.144 ;
     RECT  0.084 24.144 0.137 24.168 ;
     RECT  0.06 24.168 0.137 24.24 ;
     RECT  0.084 24.24 0.137 24.264 ;
     RECT  0.06 24.264 0.137 24.384 ;
     RECT  0.084 24.384 0.137 24.408 ;
     RECT  0.06 24.408 0.137 24.48 ;
     RECT  0.084 24.48 0.137 24.504 ;
     RECT  0.06 24.504 0.137 24.576 ;
     RECT  0.084 24.576 0.137 24.6 ;
     RECT  0.06 24.6 0.137 24.672 ;
     RECT  0.084 24.672 0.137 24.696 ;
     RECT  0.06 24.696 0.137 24.768 ;
     RECT  0.084 24.768 0.137 24.792 ;
     RECT  0.06 24.792 0.137 24.864 ;
     RECT  0.084 24.864 0.137 24.888 ;
     RECT  0.06 24.888 0.137 24.96 ;
     RECT  0.084 24.96 0.137 24.984 ;
     RECT  0.06 24.984 0.137 25.056 ;
     RECT  0.084 25.056 0.137 25.08 ;
     RECT  0.06 25.08 0.137 25.152 ;
     RECT  0.084 25.152 0.137 25.176 ;
     RECT  0.06 25.176 0.137 25.248 ;
     RECT  0.084 25.248 0.137 25.272 ;
     RECT  0.06 25.272 0.137 25.344 ;
     RECT  0.084 25.344 0.137 25.368 ;
     RECT  0.06 25.368 0.137 25.44 ;
     RECT  0.084 25.44 0.137 25.464 ;
     RECT  0.06 25.464 0.137 25.536 ;
     RECT  0.084 25.536 0.137 25.56 ;
     RECT  0.06 25.56 0.137 25.68 ;
     RECT  0.084 25.68 0.137 25.704 ;
     RECT  0.06 25.704 0.137 25.776 ;
     RECT  0.084 25.776 0.137 25.8 ;
     RECT  0.06 25.8 0.137 25.872 ;
     RECT  0.084 25.872 0.137 25.896 ;
     RECT  0.06 25.896 0.137 25.968 ;
     RECT  0.084 25.968 0.137 25.992 ;
     RECT  0.06 25.992 0.137 26.064 ;
     RECT  0.084 26.064 0.137 26.088 ;
     RECT  0.06 26.088 0.137 26.16 ;
     RECT  0.084 26.16 0.137 26.184 ;
     RECT  0.06 26.184 0.137 26.256 ;
     RECT  0.084 26.256 0.137 26.28 ;
     RECT  0.06 26.28 0.137 26.352 ;
     RECT  0.084 26.352 0.137 26.376 ;
     RECT  0.06 26.376 0.137 26.448 ;
     RECT  0.084 26.448 0.137 26.472 ;
     RECT  0.06 26.472 0.137 26.544 ;
     RECT  0.084 26.544 0.137 26.568 ;
     RECT  0.06 26.568 0.137 26.64 ;
     RECT  0.084 26.64 0.137 26.664 ;
     RECT  0.06 26.664 0.137 26.736 ;
     RECT  0.084 26.736 0.137 26.76 ;
     RECT  0.06 26.76 0.137 26.832 ;
     RECT  0.084 26.832 0.137 26.856 ;
     RECT  0.06 26.856 0.137 26.976 ;
     RECT  0.084 26.976 0.137 27 ;
     RECT  0.06 27 0.137 27.072 ;
     RECT  0.084 27.072 0.137 27.096 ;
     RECT  0.06 27.096 0.137 27.168 ;
     RECT  0.084 27.168 0.137 27.192 ;
     RECT  0.06 27.192 0.137 27.264 ;
     RECT  0.084 27.264 0.137 27.288 ;
     RECT  0.06 27.288 0.137 27.36 ;
     RECT  0.084 27.36 0.137 27.384 ;
     RECT  0.06 27.384 0.137 27.456 ;
     RECT  0.084 27.456 0.137 27.48 ;
     RECT  0.06 27.48 0.137 27.552 ;
     RECT  0.084 27.552 0.137 27.576 ;
     RECT  0.06 27.576 0.137 27.648 ;
     RECT  0.084 27.648 0.137 27.672 ;
     RECT  0.06 27.672 0.137 27.744 ;
     RECT  0.084 27.744 0.137 27.768 ;
     RECT  0.06 27.768 0.137 27.84 ;
     RECT  0.084 27.84 0.137 27.864 ;
     RECT  0.06 27.864 0.137 27.936 ;
     RECT  0.084 27.936 0.137 27.96 ;
     RECT  0.06 27.96 0.137 28.032 ;
     RECT  0.084 28.032 0.137 28.056 ;
     RECT  0.06 28.056 0.137 28.128 ;
     RECT  0.084 28.128 0.137 28.152 ;
     RECT  0.06 28.152 0.137 28.272 ;
     RECT  0.084 28.272 0.137 28.296 ;
     RECT  0.06 28.296 0.137 28.368 ;
     RECT  0.084 28.368 0.137 28.392 ;
     RECT  0.06 28.392 0.137 28.464 ;
     RECT  0.084 28.464 0.137 28.488 ;
     RECT  0.06 28.488 0.137 28.56 ;
     RECT  0.084 28.56 0.137 28.584 ;
     RECT  0.06 28.584 0.137 28.656 ;
     RECT  0.084 28.656 0.137 28.68 ;
     RECT  0.06 28.68 0.137 28.752 ;
     RECT  0.084 28.752 0.137 28.776 ;
     RECT  0.06 28.776 0.137 28.848 ;
     RECT  0.084 28.848 0.137 28.872 ;
     RECT  0.06 28.872 0.137 28.944 ;
     RECT  0.084 28.944 0.137 28.968 ;
     RECT  0.06 28.968 0.137 29.04 ;
     RECT  0.084 29.04 0.137 29.064 ;
     RECT  0.06 29.064 0.137 29.136 ;
     RECT  0.084 29.136 0.137 29.16 ;
     RECT  0.06 29.16 0.137 29.232 ;
     RECT  0.084 29.232 0.137 29.256 ;
     RECT  0.06 29.256 0.137 29.328 ;
     RECT  0.084 29.328 0.137 29.352 ;
     RECT  0.06 29.352 0.137 29.424 ;
     RECT  0.084 29.424 0.137 29.448 ;
     RECT  0.06 29.448 0.137 29.568 ;
     RECT  0.084 29.568 0.137 29.592 ;
     RECT  0.06 29.592 0.137 29.664 ;
     RECT  0.084 29.664 0.137 29.688 ;
     RECT  0.06 29.688 0.137 29.76 ;
     RECT  0.084 29.76 0.137 29.784 ;
     RECT  0.06 29.784 0.137 29.856 ;
     RECT  0.084 29.856 0.137 29.88 ;
     RECT  0.06 29.88 0.137 29.952 ;
     RECT  0.084 29.952 0.137 29.976 ;
     RECT  0.06 29.976 0.137 30.048 ;
     RECT  0.084 30.048 0.137 30.072 ;
     RECT  0.06 30.072 0.137 30.144 ;
     RECT  0.084 30.144 0.137 30.168 ;
     RECT  0.06 30.168 0.137 30.24 ;
     RECT  0.084 30.24 0.137 30.264 ;
     RECT  0.06 30.264 0.137 30.336 ;
     RECT  0.084 30.336 0.137 30.36 ;
     RECT  0.06 30.36 0.137 30.432 ;
     RECT  0.084 30.432 0.137 30.456 ;
     RECT  0.06 30.456 0.137 30.528 ;
     RECT  0.084 30.528 0.137 30.552 ;
     RECT  0.06 30.552 0.137 30.624 ;
     RECT  0.084 30.624 0.137 30.648 ;
     RECT  0.06 30.648 0.137 30.72 ;
     RECT  0.084 30.72 0.137 30.744 ;
     RECT  0.06 30.744 0.137 30.864 ;
     RECT  0.084 30.864 0.137 30.888 ;
     RECT  0.06 30.888 0.137 30.96 ;
     RECT  0.084 30.96 0.137 30.984 ;
     RECT  0.06 30.984 0.137 31.056 ;
     RECT  0.084 31.056 0.137 31.08 ;
     RECT  0.06 31.08 0.137 31.152 ;
     RECT  0.084 31.152 0.137 31.176 ;
     RECT  0.06 31.176 0.137 31.248 ;
     RECT  0.084 31.248 0.137 31.272 ;
     RECT  0.06 31.272 0.137 31.344 ;
     RECT  0.084 31.344 0.137 31.368 ;
     RECT  0.06 31.368 0.137 31.44 ;
     RECT  0.084 31.44 0.137 31.464 ;
     RECT  0.06 31.464 0.137 31.536 ;
     RECT  0.084 31.536 0.137 31.56 ;
     RECT  0.06 31.56 0.137 31.632 ;
     RECT  0.084 31.632 0.137 31.656 ;
     RECT  0.06 31.656 0.137 31.728 ;
     RECT  0.084 31.728 0.137 31.752 ;
     RECT  0.06 31.752 0.137 31.824 ;
     RECT  0.084 31.824 0.137 31.848 ;
     RECT  0.06 31.848 0.137 31.92 ;
     RECT  0.084 31.92 0.137 31.944 ;
     RECT  0.06 31.944 0.137 32.016 ;
     RECT  0.084 32.016 0.137 32.04 ;
     RECT  0.06 32.04 0.137 32.16 ;
     RECT  0.084 32.16 0.137 32.184 ;
     RECT  0.06 32.184 0.137 32.256 ;
     RECT  0.084 32.256 0.137 32.28 ;
     RECT  0.06 32.28 0.137 32.352 ;
     RECT  0.084 32.352 0.137 32.376 ;
     RECT  0.06 32.376 0.137 32.448 ;
     RECT  0.084 32.448 0.137 32.472 ;
     RECT  0.06 32.472 0.137 32.544 ;
     RECT  0.084 32.544 0.137 32.568 ;
     RECT  0.06 32.568 0.137 32.64 ;
     RECT  0.084 32.64 0.137 32.664 ;
     RECT  0.06 32.664 0.137 32.736 ;
     RECT  0.084 32.736 0.137 32.76 ;
     RECT  0.06 32.76 0.137 32.832 ;
     RECT  0.084 32.832 0.137 32.856 ;
     RECT  0.06 32.856 0.137 32.928 ;
     RECT  0.084 32.928 0.137 32.952 ;
     RECT  0.06 32.952 0.137 33.024 ;
     RECT  0.084 33.024 0.137 33.048 ;
     RECT  0.06 33.048 0.137 33.12 ;
     RECT  0.084 33.12 0.137 33.144 ;
     RECT  0.06 33.144 0.137 33.216 ;
     RECT  0.084 33.216 0.137 33.24 ;
     RECT  0.06 33.24 0.137 33.312 ;
     RECT  0.084 33.312 0.137 33.336 ;
     RECT  0.06 33.336 0.137 33.456 ;
     RECT  0.084 33.456 0.137 33.48 ;
     RECT  0.06 33.48 0.137 33.552 ;
     RECT  0.084 33.552 0.137 33.576 ;
     RECT  0.06 33.576 0.137 33.648 ;
     RECT  0.084 33.648 0.137 33.672 ;
     RECT  0.06 33.672 0.137 33.744 ;
     RECT  0.084 33.744 0.137 33.768 ;
     RECT  0.06 33.768 0.137 33.84 ;
     RECT  0.084 33.84 0.137 33.864 ;
     RECT  0.06 33.864 0.137 33.936 ;
     RECT  0.084 33.936 0.137 33.96 ;
     RECT  0.06 33.96 0.137 34.032 ;
     RECT  0.084 34.032 0.137 34.056 ;
     RECT  0.06 34.056 0.137 34.128 ;
     RECT  0.084 34.128 0.137 34.152 ;
     RECT  0.06 34.152 0.137 34.224 ;
     RECT  0.084 34.224 0.137 34.248 ;
     RECT  0.06 34.248 0.137 34.32 ;
     RECT  0.084 34.32 0.137 34.344 ;
     RECT  0.06 34.344 0.137 34.416 ;
     RECT  0.084 34.416 0.137 34.44 ;
     RECT  0.06 34.44 0.137 34.512 ;
     RECT  0.084 34.512 0.137 34.536 ;
     RECT  0.06 34.536 0.137 34.608 ;
     RECT  0.084 34.608 0.137 34.632 ;
     RECT  0.06 34.632 0.137 34.752 ;
     RECT  0.084 34.752 0.137 34.776 ;
     RECT  0.06 34.776 0.137 34.848 ;
     RECT  0.084 34.848 0.137 34.872 ;
     RECT  0.06 34.872 0.137 34.944 ;
     RECT  0.084 34.944 0.137 34.968 ;
     RECT  0.06 34.968 0.137 35.04 ;
     RECT  0.084 35.04 0.137 35.064 ;
     RECT  0.06 35.064 0.137 35.136 ;
     RECT  0.084 35.136 0.137 35.16 ;
     RECT  0.06 35.16 0.137 35.232 ;
     RECT  0.084 35.232 0.137 35.256 ;
     RECT  0.06 35.256 0.137 35.328 ;
     RECT  0.084 35.328 0.137 35.352 ;
     RECT  0.06 35.352 0.137 35.424 ;
     RECT  0.084 35.424 0.137 35.448 ;
     RECT  0.06 35.448 0.137 35.52 ;
     RECT  0.084 35.52 0.137 35.544 ;
     RECT  0.06 35.544 0.137 35.616 ;
     RECT  0.084 35.616 0.137 35.64 ;
     RECT  0.06 35.64 0.137 35.712 ;
     RECT  0.084 35.712 0.137 35.736 ;
     RECT  0.06 35.736 0.137 35.808 ;
     RECT  0.084 35.808 0.137 35.832 ;
     RECT  0.06 35.832 0.137 35.904 ;
     RECT  0.084 35.904 0.137 35.928 ;
     RECT  0.06 35.928 0.137 36.048 ;
     RECT  0.084 36.048 0.137 36.072 ;
     RECT  0.06 36.072 0.137 36.144 ;
     RECT  0.084 36.144 0.137 36.168 ;
     RECT  0.06 36.168 0.137 36.24 ;
     RECT  0.084 36.24 0.137 36.264 ;
     RECT  0.06 36.264 0.137 36.336 ;
     RECT  0.084 36.336 0.137 36.36 ;
     RECT  0.06 36.36 0.137 36.432 ;
     RECT  0.084 36.432 0.137 36.456 ;
     RECT  0.06 36.456 0.137 36.528 ;
     RECT  0.084 36.528 0.137 36.552 ;
     RECT  0.06 36.552 0.137 36.624 ;
     RECT  0.084 36.624 0.137 36.648 ;
     RECT  0.06 36.648 0.137 36.72 ;
     RECT  0.084 36.72 0.137 36.744 ;
     RECT  0.06 36.744 0.137 36.816 ;
     RECT  0.084 36.816 0.137 36.84 ;
     RECT  0.06 36.84 0.137 36.912 ;
     RECT  0.084 36.912 0.137 36.936 ;
     RECT  0.06 36.936 0.137 37.008 ;
     RECT  0.084 37.008 0.137 37.032 ;
     RECT  0.06 37.032 0.137 37.104 ;
     RECT  0.084 37.104 0.137 37.128 ;
     RECT  0.06 37.128 0.137 37.2 ;
     RECT  0.084 37.2 0.137 37.224 ;
     RECT  0.06 37.224 0.137 37.344 ;
     RECT  0.084 37.344 0.137 37.368 ;
     RECT  0.06 37.368 0.137 37.44 ;
     RECT  0.084 37.44 0.137 37.464 ;
     RECT  0.06 37.464 0.137 37.536 ;
     RECT  0.084 37.536 0.137 37.56 ;
     RECT  0.06 37.56 0.137 37.632 ;
     RECT  0.084 37.632 0.137 37.656 ;
     RECT  0.06 37.656 0.137 37.728 ;
     RECT  0.084 37.728 0.137 37.752 ;
     RECT  0.06 37.752 0.137 37.824 ;
     RECT  0.084 37.824 0.137 37.848 ;
     RECT  0.06 37.848 0.137 37.92 ;
     RECT  0.084 37.92 0.137 37.944 ;
     RECT  0.06 37.944 0.137 38.016 ;
     RECT  0.084 38.016 0.137 38.04 ;
     RECT  0.06 38.04 0.137 38.112 ;
     RECT  0.084 38.112 0.137 38.136 ;
     RECT  0.06 38.136 0.137 38.208 ;
     RECT  0.084 38.208 0.137 38.232 ;
     RECT  0.06 38.232 0.137 38.304 ;
     RECT  0.084 38.304 0.137 38.328 ;
     RECT  0.06 38.328 0.137 38.4 ;
     RECT  0.084 38.4 0.137 38.424 ;
     RECT  0.06 38.424 0.137 38.496 ;
     RECT  0.084 38.496 0.137 38.52 ;
     RECT  0.06 38.52 0.137 38.64 ;
     RECT  0.084 38.64 0.137 38.664 ;
     RECT  0.06 38.664 0.137 38.736 ;
     RECT  0.084 38.736 0.137 38.76 ;
     RECT  0.06 38.76 0.137 38.832 ;
     RECT  0.084 38.832 0.137 38.856 ;
     RECT  0.06 38.856 0.137 38.928 ;
     RECT  0.084 38.928 0.137 38.952 ;
     RECT  0.06 38.952 0.137 39.024 ;
     RECT  0.084 39.024 0.137 39.048 ;
     RECT  0.06 39.048 0.137 39.12 ;
     RECT  0.084 39.12 0.137 39.144 ;
     RECT  0.06 39.144 0.137 39.216 ;
     RECT  0.084 39.216 0.137 39.24 ;
     RECT  0.06 39.24 0.137 39.312 ;
     RECT  0.084 39.312 0.137 39.336 ;
     RECT  0.06 39.336 0.137 39.408 ;
     RECT  0.084 39.408 0.137 39.432 ;
     RECT  0.06 39.432 0.137 39.504 ;
     RECT  0.084 39.504 0.137 39.528 ;
     RECT  0.06 39.528 0.137 39.6 ;
     RECT  0.084 39.6 0.137 39.624 ;
     RECT  0.06 39.624 0.137 39.696 ;
     RECT  0.084 39.696 0.137 39.72 ;
     RECT  0.06 39.72 0.137 39.792 ;
     RECT  0.084 39.792 0.137 39.816 ;
     RECT  0.06 39.816 0.137 39.936 ;
     RECT  0.084 39.936 0.137 39.96 ;
     RECT  0.06 39.96 0.137 40.032 ;
     RECT  0.084 40.032 0.137 40.056 ;
     RECT  0.06 40.056 0.137 40.128 ;
     RECT  0.084 40.128 0.137 40.152 ;
     RECT  0.06 40.152 0.137 40.224 ;
     RECT  0.084 40.224 0.137 40.248 ;
     RECT  0.06 40.248 0.137 40.32 ;
     RECT  0.084 40.32 0.137 40.344 ;
     RECT  0.06 40.344 0.137 40.416 ;
     RECT  0.084 40.416 0.137 40.44 ;
     RECT  0.06 40.44 0.137 40.512 ;
     RECT  0.084 40.512 0.137 40.536 ;
     RECT  0.06 40.536 0.137 40.608 ;
     RECT  0.084 40.608 0.137 40.632 ;
     RECT  0.06 40.632 0.137 40.704 ;
     RECT  0.084 40.704 0.137 40.728 ;
     RECT  0.06 40.728 0.137 40.8 ;
     RECT  0.084 40.8 0.137 40.824 ;
     RECT  0.06 40.824 0.137 40.896 ;
     RECT  0.084 40.896 0.137 40.92 ;
     RECT  0.06 40.92 0.137 40.992 ;
     RECT  0.084 40.992 0.137 41.016 ;
     RECT  0.06 41.016 0.137 41.088 ;
     RECT  0.084 41.088 0.137 41.112 ;
     RECT  0.06 41.112 0.137 41.184 ;
     RECT  0.084 41.184 0.137 41.208 ;
     RECT  0.06 41.208 0.137 41.328 ;
     RECT  0.084 41.328 0.137 41.352 ;
     RECT  0.06 41.352 0.137 41.424 ;
     RECT  0.084 41.424 0.137 41.448 ;
     RECT  0.06 41.448 0.137 41.52 ;
     RECT  0.084 41.52 0.137 41.544 ;
     RECT  0.06 41.544 0.137 41.616 ;
     RECT  0.084 41.616 0.137 41.64 ;
     RECT  0.06 41.64 0.137 41.712 ;
     RECT  0.084 41.712 0.137 41.736 ;
     RECT  0.06 41.736 0.137 41.808 ;
     RECT  0.084 41.808 0.137 41.832 ;
     RECT  0.06 41.832 0.137 41.904 ;
     RECT  0.084 41.904 0.137 41.928 ;
     RECT  0.06 41.928 0.137 42 ;
     RECT  0.084 42 0.137 42.024 ;
     RECT  0.06 42.024 0.137 42.096 ;
     RECT  0.084 42.096 0.137 42.12 ;
     RECT  0.06 42.12 0.137 42.192 ;
     RECT  0.084 42.192 0.137 42.216 ;
     RECT  0.06 42.216 0.137 42.288 ;
     RECT  0.084 42.288 0.137 42.312 ;
     RECT  0.06 42.312 0.137 42.384 ;
     RECT  0.084 42.384 0.137 42.408 ;
     RECT  0.06 42.408 0.137 42.48 ;
     RECT  0.084 42.48 0.137 42.504 ;
     RECT  0.06 42.504 0.137 42.624 ;
     RECT  0.084 42.624 0.137 42.648 ;
     RECT  0.06 42.648 0.137 42.72 ;
     RECT  0.084 42.72 0.137 42.744 ;
     RECT  0.06 42.744 0.137 42.816 ;
     RECT  0.084 42.816 0.137 42.84 ;
     RECT  0.06 42.84 0.137 42.912 ;
     RECT  0.084 42.912 0.137 42.936 ;
     RECT  0.06 42.936 0.137 43.008 ;
     RECT  0.084 43.008 0.137 43.032 ;
     RECT  0.06 43.032 0.137 43.104 ;
     RECT  0.084 43.104 0.137 43.128 ;
     RECT  0.06 43.128 0.137 43.2 ;
     RECT  0.084 43.2 0.137 43.224 ;
     RECT  0.06 43.224 0.137 43.296 ;
     RECT  0.084 43.296 0.137 43.32 ;
     RECT  0.06 43.32 0.137 43.392 ;
     RECT  0.084 43.392 0.137 43.416 ;
     RECT  0.06 43.416 0.137 43.488 ;
     RECT  0.084 43.488 0.137 43.512 ;
     RECT  0.06 43.512 0.137 43.584 ;
     RECT  0.084 43.584 0.137 43.608 ;
     RECT  0.06 43.608 0.137 43.68 ;
     RECT  0.084 43.68 0.137 43.704 ;
     RECT  0.06 43.704 0.137 43.776 ;
     RECT  0.084 43.776 0.137 43.8 ;
     RECT  0.06 43.8 0.137 43.92 ;
     RECT  0.084 43.92 0.137 43.944 ;
     RECT  0.06 43.944 0.137 44.016 ;
     RECT  0.084 44.016 0.137 44.04 ;
     RECT  0.06 44.04 0.137 44.112 ;
     RECT  0.084 44.112 0.137 44.136 ;
     RECT  0.06 44.136 0.137 44.208 ;
     RECT  0.084 44.208 0.137 44.232 ;
     RECT  0.06 44.232 0.137 44.304 ;
     RECT  0.084 44.304 0.137 44.328 ;
     RECT  0.06 44.328 0.137 44.4 ;
     RECT  0.084 44.4 0.137 44.424 ;
     RECT  0.06 44.424 0.137 44.496 ;
     RECT  0.084 44.496 0.137 44.52 ;
     RECT  0.06 44.52 0.137 44.592 ;
     RECT  0.084 44.592 0.137 44.616 ;
     RECT  0.06 44.616 0.137 44.688 ;
     RECT  0.084 44.688 0.137 44.712 ;
     RECT  0.06 44.712 0.137 44.784 ;
     RECT  0.084 44.784 0.137 44.808 ;
     RECT  0.06 44.808 0.137 44.88 ;
     RECT  0.084 44.88 0.137 44.904 ;
     RECT  0.06 44.904 0.137 44.976 ;
     RECT  0.084 44.976 0.137 45 ;
     RECT  0.06 45 0.137 45.072 ;
     RECT  0.084 45.072 0.137 45.096 ;
     RECT  0.06 45.096 0.137 45.216 ;
     RECT  0.084 45.216 0.137 45.24 ;
     RECT  0.06 45.24 0.137 45.312 ;
     RECT  0.084 45.312 0.137 45.336 ;
     RECT  0.06 45.336 0.137 45.408 ;
     RECT  0.084 45.408 0.137 45.432 ;
     RECT  0.06 45.432 0.137 45.504 ;
     RECT  0.084 45.504 0.137 45.528 ;
     RECT  0.06 45.528 0.137 45.6 ;
     RECT  0.084 45.6 0.137 45.624 ;
     RECT  0.06 45.624 0.137 45.696 ;
     RECT  0.084 45.696 0.137 45.72 ;
     RECT  0.06 45.72 0.137 45.792 ;
     RECT  0.084 45.792 0.137 45.816 ;
     RECT  0.06 45.816 0.137 45.888 ;
     RECT  0.084 45.888 0.137 45.912 ;
     RECT  0.06 45.912 0.137 45.984 ;
     RECT  0.084 45.984 0.137 46.008 ;
     RECT  0.06 46.008 0.137 46.08 ;
     RECT  0.084 46.08 0.137 46.104 ;
     RECT  0.06 46.104 0.137 46.176 ;
     RECT  0.084 46.176 0.137 46.2 ;
     RECT  0.06 46.2 0.137 46.272 ;
     RECT  0.084 46.272 0.137 46.296 ;
     RECT  0.06 46.296 0.137 46.368 ;
     RECT  0.084 46.368 0.137 46.392 ;
     RECT  0.06 46.392 0.137 46.512 ;
     RECT  0.084 46.512 0.137 46.536 ;
     RECT  0.06 46.536 0.137 46.608 ;
     RECT  0.084 46.608 0.137 46.632 ;
     RECT  0.06 46.632 0.137 46.704 ;
     RECT  0.084 46.704 0.137 46.728 ;
     RECT  0.06 46.728 0.137 46.8 ;
     RECT  0.084 46.8 0.137 46.824 ;
     RECT  0.06 46.824 0.137 46.896 ;
     RECT  0.084 46.896 0.137 46.92 ;
     RECT  0.06 46.92 0.137 46.992 ;
     RECT  0.084 46.992 0.137 47.016 ;
     RECT  0.06 47.016 0.137 47.088 ;
     RECT  0.084 47.088 0.137 47.112 ;
     RECT  0.06 47.112 0.137 47.184 ;
     RECT  0.084 47.184 0.137 47.208 ;
     RECT  0.06 47.208 0.137 47.28 ;
     RECT  0.084 47.28 0.137 47.304 ;
     RECT  0.06 47.304 0.137 47.376 ;
     RECT  0.084 47.376 0.137 47.4 ;
     RECT  0.06 47.4 0.137 47.472 ;
     RECT  0.084 47.472 0.137 47.496 ;
     RECT  0.06 47.496 0.137 47.568 ;
     RECT  0.084 47.568 0.137 47.592 ;
     RECT  0.06 47.592 0.137 47.664 ;
     RECT  0.084 47.664 0.137 47.688 ;
     RECT  0.06 47.688 0.137 47.808 ;
     RECT  0.084 47.808 0.137 47.832 ;
     RECT  0.06 47.832 0.137 47.904 ;
     RECT  0.084 47.904 0.137 47.928 ;
     RECT  0.06 47.928 0.137 48 ;
     RECT  0.084 48 0.137 48.024 ;
     RECT  0.06 48.024 0.137 48.096 ;
     RECT  0.084 48.096 0.137 48.12 ;
     RECT  0.06 48.12 0.137 48.192 ;
     RECT  0.084 48.192 0.137 48.216 ;
     RECT  0.06 48.216 0.137 48.288 ;
     RECT  0.084 48.288 0.137 48.312 ;
     RECT  0.06 48.312 0.137 48.384 ;
     RECT  0.084 48.384 0.137 48.408 ;
     RECT  0.06 48.408 0.137 48.48 ;
     RECT  0.084 48.48 0.137 48.504 ;
     RECT  0.06 48.504 0.137 48.576 ;
     RECT  0.084 48.576 0.137 48.6 ;
     RECT  0.06 48.6 0.137 48.672 ;
     RECT  0.084 48.672 0.137 48.696 ;
     RECT  0.06 48.696 0.137 48.768 ;
     RECT  0.084 48.768 0.137 48.792 ;
     RECT  0.06 48.792 0.137 48.864 ;
     RECT  0.084 48.864 0.137 48.888 ;
     RECT  0.06 48.888 0.137 48.96 ;
     RECT  0.084 48.96 0.137 48.984 ;
     RECT  0.06 48.984 0.137 49.104 ;
     RECT  0.084 49.104 0.137 49.128 ;
     RECT  0.06 49.128 0.137 49.2 ;
     RECT  0.084 49.2 0.137 49.224 ;
     RECT  0.06 49.224 0.137 49.296 ;
     RECT  0.084 49.296 0.137 49.32 ;
     RECT  0.06 49.32 0.137 49.392 ;
     RECT  0.084 49.392 0.137 49.416 ;
     RECT  0.06 49.416 0.137 49.488 ;
     RECT  0.084 49.488 0.137 49.512 ;
     RECT  0.06 49.512 0.137 49.584 ;
     RECT  0.084 49.584 0.137 49.608 ;
     RECT  0.06 49.608 0.137 49.68 ;
     RECT  0.084 49.68 0.137 49.704 ;
     RECT  0.06 49.704 0.137 49.776 ;
     RECT  0.084 49.776 0.137 49.8 ;
     RECT  0.06 49.8 0.137 49.872 ;
     RECT  0.084 49.872 0.137 49.896 ;
     RECT  0.06 49.896 0.137 49.968 ;
     RECT  0.084 49.968 0.137 49.992 ;
     RECT  0.06 49.992 0.137 50.064 ;
     RECT  0.084 50.064 0.137 50.088 ;
     RECT  0.06 50.088 0.137 50.16 ;
     RECT  0.084 50.16 0.137 50.184 ;
     RECT  0.06 50.184 0.137 50.256 ;
     RECT  0.084 50.256 0.137 50.28 ;
     RECT  0.06 50.28 0.137 50.4 ;
     RECT  0.084 50.4 0.137 50.424 ;
     RECT  0.06 50.424 0.137 50.496 ;
     RECT  0.084 50.496 0.137 50.52 ;
     RECT  0.06 50.52 0.137 50.592 ;
     RECT  0.084 50.592 0.137 50.616 ;
     RECT  0.06 50.616 0.137 50.688 ;
     RECT  0.084 50.688 0.137 50.712 ;
     RECT  0.06 50.712 0.137 50.784 ;
     RECT  0.084 50.784 0.137 50.808 ;
     RECT  0.06 50.808 0.137 50.88 ;
     RECT  0.084 50.88 0.137 50.904 ;
     RECT  0.06 50.904 0.137 50.976 ;
     RECT  0.084 50.976 0.137 51 ;
     RECT  0.06 51 0.137 51.072 ;
     RECT  0.084 51.072 0.137 51.096 ;
     RECT  0.06 51.096 0.137 51.168 ;
     RECT  0.084 51.168 0.137 51.192 ;
     RECT  0.06 51.192 0.137 51.264 ;
     RECT  0.084 51.264 0.137 51.288 ;
     RECT  0.06 51.288 0.137 51.36 ;
     RECT  0.084 51.36 0.137 51.384 ;
     RECT  0.06 51.384 0.137 51.456 ;
     RECT  0.084 51.456 0.137 51.48 ;
     RECT  0.06 51.48 0.137 51.552 ;
     RECT  0.084 51.552 0.137 51.576 ;
     RECT  0.06 51.576 0.137 51.696 ;
     RECT  0.084 51.696 0.137 51.72 ;
     RECT  0.06 51.72 0.137 51.792 ;
     RECT  0.084 51.792 0.137 51.816 ;
     RECT  0.06 51.816 0.137 51.888 ;
     RECT  0.084 51.888 0.137 51.912 ;
     RECT  0.06 51.912 0.137 51.984 ;
     RECT  0.084 51.984 0.137 52.008 ;
     RECT  0.06 52.008 0.137 52.08 ;
     RECT  0.084 52.08 0.137 52.104 ;
     RECT  0.06 52.104 0.137 52.176 ;
     RECT  0.084 52.176 0.137 52.2 ;
     RECT  0.06 52.2 0.137 52.272 ;
     RECT  0.084 52.272 0.137 52.296 ;
     RECT  0.06 52.296 0.137 52.368 ;
     RECT  0.084 52.368 0.137 52.392 ;
     RECT  0.06 52.392 0.137 52.464 ;
     RECT  0.084 52.464 0.137 52.488 ;
     RECT  0.06 52.488 0.137 52.56 ;
     RECT  0.084 52.56 0.137 52.584 ;
     RECT  0.06 52.584 0.137 52.656 ;
     RECT  0.084 52.656 0.137 52.68 ;
     RECT  0.06 52.68 0.137 52.752 ;
     RECT  0.084 52.752 0.137 52.776 ;
     RECT  0.06 52.776 0.137 52.848 ;
     RECT  0.084 52.848 0.137 52.872 ;
     RECT  0.06 52.872 0.137 52.992 ;
     RECT  0.084 52.992 0.137 53.016 ;
     RECT  0.06 53.016 0.137 53.088 ;
     RECT  0.084 53.088 0.137 53.112 ;
     RECT  0.06 53.112 0.137 53.184 ;
     RECT  0.084 53.184 0.137 53.208 ;
     RECT  0.06 53.208 0.137 53.28 ;
     RECT  0.084 53.28 0.137 53.304 ;
     RECT  0.06 53.304 0.137 53.376 ;
     RECT  0.084 53.376 0.137 53.4 ;
     RECT  0.06 53.4 0.137 53.472 ;
     RECT  0.084 53.472 0.137 53.496 ;
     RECT  0.06 53.496 0.137 53.568 ;
     RECT  0.084 53.568 0.137 53.592 ;
     RECT  0.06 53.592 0.137 53.664 ;
     RECT  0.084 53.664 0.137 53.688 ;
     RECT  0.06 53.688 0.137 53.76 ;
     RECT  0.084 53.76 0.137 53.784 ;
     RECT  0.06 53.784 0.137 53.856 ;
     RECT  0.084 53.856 0.137 53.88 ;
     RECT  0.06 53.88 0.137 53.952 ;
     RECT  0.084 53.952 0.137 53.976 ;
     RECT  0.06 53.976 0.137 54.048 ;
     RECT  0.084 54.048 0.137 54.072 ;
     RECT  0.06 54.072 0.137 54.144 ;
     RECT  0.084 54.144 0.137 54.168 ;
     RECT  0.06 54.168 0.137 54.288 ;
     RECT  0.084 54.288 0.137 54.312 ;
     RECT  0.06 54.312 0.137 54.384 ;
     RECT  0.084 54.384 0.137 54.408 ;
     RECT  0.06 54.408 0.137 54.48 ;
     RECT  0.084 54.48 0.137 54.504 ;
     RECT  0.06 54.504 0.137 54.576 ;
     RECT  0.084 54.576 0.137 54.6 ;
     RECT  0.06 54.6 0.137 54.672 ;
     RECT  0.084 54.672 0.137 54.696 ;
     RECT  0.06 54.696 0.137 54.768 ;
     RECT  0.084 54.768 0.137 54.792 ;
     RECT  0.06 54.792 0.137 54.864 ;
     RECT  0.084 54.864 0.137 54.888 ;
     RECT  0.06 54.888 0.137 54.96 ;
     RECT  0.084 54.96 0.137 54.984 ;
     RECT  0.06 54.984 0.137 55.056 ;
     RECT  0.084 55.056 0.137 55.08 ;
     RECT  0.06 55.08 0.137 55.152 ;
     RECT  0.084 55.152 0.137 55.176 ;
     RECT  0.06 55.176 0.137 55.248 ;
     RECT  0.084 55.248 0.137 55.272 ;
     RECT  0.06 55.272 0.137 55.344 ;
     RECT  0.084 55.344 0.137 55.368 ;
     RECT  0.06 55.368 0.137 55.44 ;
     RECT  0.084 55.44 0.137 55.464 ;
     RECT  0.06 55.464 0.137 55.584 ;
     RECT  0.084 55.584 0.137 55.608 ;
     RECT  0.06 55.608 0.137 55.68 ;
     RECT  0.084 55.68 0.137 55.704 ;
     RECT  0.06 55.704 0.137 55.776 ;
     RECT  0.084 55.776 0.137 55.8 ;
     RECT  0.06 55.8 0.137 55.872 ;
     RECT  0.084 55.872 0.137 55.896 ;
     RECT  0.06 55.896 0.137 55.968 ;
     RECT  0.084 55.968 0.137 55.992 ;
     RECT  0.06 55.992 0.137 56.064 ;
     RECT  0.084 56.064 0.137 56.088 ;
     RECT  0.06 56.088 0.137 56.16 ;
     RECT  0.084 56.16 0.137 56.184 ;
     RECT  0.06 56.184 0.137 56.256 ;
     RECT  0.084 56.256 0.137 56.28 ;
     RECT  0.06 56.28 0.137 56.352 ;
     RECT  0.084 56.352 0.137 56.376 ;
     RECT  0.06 56.376 0.137 56.448 ;
     RECT  0.084 56.448 0.137 56.472 ;
     RECT  0.06 56.472 0.137 56.544 ;
     RECT  0.084 56.544 0.137 56.568 ;
     RECT  0.06 56.568 0.137 56.64 ;
     RECT  0.084 56.64 0.137 56.664 ;
     RECT  0.06 56.664 0.137 56.736 ;
     RECT  0.084 56.736 0.137 56.76 ;
     RECT  0.06 56.76 0.137 56.88 ;
     RECT  0.084 56.88 0.137 56.904 ;
     RECT  0.06 56.904 0.137 56.976 ;
     RECT  0.084 56.976 0.137 57 ;
     RECT  0.06 57 0.137 57.072 ;
     RECT  0.084 57.072 0.137 57.096 ;
     RECT  0.06 57.096 0.137 57.168 ;
     RECT  0.084 57.168 0.137 57.192 ;
     RECT  0.06 57.192 0.137 57.264 ;
     RECT  0.084 57.264 0.137 57.288 ;
     RECT  0.06 57.288 0.137 57.36 ;
     RECT  0.084 57.36 0.137 57.384 ;
     RECT  0.06 57.384 0.137 57.456 ;
     RECT  0.084 57.456 0.137 57.48 ;
     RECT  0.06 57.48 0.137 57.552 ;
     RECT  0.084 57.552 0.137 57.576 ;
     RECT  0.06 57.576 0.137 57.648 ;
     RECT  0.084 57.648 0.137 57.672 ;
     RECT  0.06 57.672 0.137 57.744 ;
     RECT  0.084 57.744 0.137 57.768 ;
     RECT  0.06 57.768 0.137 57.84 ;
     RECT  0.084 57.84 0.137 57.864 ;
     RECT  0.06 57.864 0.137 57.936 ;
     RECT  0.084 57.936 0.137 57.96 ;
     RECT  0.06 57.96 0.137 58.032 ;
     RECT  0.084 58.032 0.137 58.056 ;
     RECT  0.06 58.056 0.137 58.176 ;
     RECT  0.084 58.176 0.137 58.2 ;
     RECT  0.06 58.2 0.137 58.272 ;
     RECT  0.084 58.272 0.137 58.296 ;
     RECT  0.06 58.296 0.137 58.368 ;
     RECT  0.084 58.368 0.137 58.392 ;
     RECT  0.06 58.392 0.137 58.464 ;
     RECT  0.084 58.464 0.137 58.488 ;
     RECT  0.06 58.488 0.137 58.56 ;
     RECT  0.084 58.56 0.137 58.584 ;
     RECT  0.06 58.584 0.137 58.656 ;
     RECT  0.084 58.656 0.137 58.68 ;
     RECT  0.06 58.68 0.137 58.752 ;
     RECT  0.084 58.752 0.137 58.776 ;
     RECT  0.06 58.776 0.137 58.848 ;
     RECT  0.084 58.848 0.137 58.872 ;
     RECT  0.06 58.872 0.137 58.944 ;
     RECT  0.084 58.944 0.137 58.968 ;
     RECT  0.06 58.968 0.137 59.04 ;
     RECT  0.084 59.04 0.137 59.064 ;
     RECT  0.06 59.064 0.137 59.136 ;
     RECT  0.084 59.136 0.137 59.16 ;
     RECT  0.06 59.16 0.137 59.232 ;
     RECT  0.084 59.232 0.137 59.256 ;
     RECT  0.06 59.256 0.137 59.328 ;
     RECT  0.084 59.328 0.137 59.352 ;
     RECT  0.06 59.352 0.137 59.472 ;
     RECT  0.084 59.472 0.137 59.496 ;
     RECT  0.06 59.496 0.137 59.568 ;
     RECT  0.084 59.568 0.137 59.592 ;
     RECT  0.06 59.592 0.137 59.664 ;
     RECT  0.084 59.664 0.137 59.688 ;
     RECT  0.06 59.688 0.137 59.76 ;
     RECT  0.084 59.76 0.137 59.784 ;
     RECT  0.06 59.784 0.137 59.856 ;
     RECT  0.084 59.856 0.137 59.88 ;
     RECT  0.06 59.88 0.137 59.952 ;
     RECT  0.084 59.952 0.137 59.976 ;
     RECT  0.06 59.976 0.137 60.048 ;
     RECT  0.084 60.048 0.137 60.072 ;
     RECT  0.06 60.072 0.137 60.144 ;
     RECT  0.084 60.144 0.137 60.168 ;
     RECT  0.06 60.168 0.137 60.24 ;
     RECT  0.084 60.24 0.137 60.264 ;
     RECT  0.06 60.264 0.137 60.336 ;
     RECT  0.084 60.336 0.137 60.36 ;
     RECT  0.06 60.36 0.137 60.432 ;
     RECT  0.084 60.432 0.137 60.456 ;
     RECT  0.06 60.456 0.137 60.528 ;
     RECT  0.084 60.528 0.137 60.552 ;
     RECT  0.06 60.552 0.137 60.624 ;
     RECT  0.084 60.624 0.137 60.648 ;
     RECT  0.06 60.648 0.137 60.768 ;
     RECT  0.084 60.768 0.137 60.792 ;
     RECT  0.06 60.792 0.137 60.864 ;
     RECT  0.084 60.864 0.137 60.888 ;
     RECT  0.06 60.888 0.137 60.96 ;
     RECT  0.084 60.96 0.137 60.984 ;
     RECT  0.06 60.984 0.137 61.056 ;
     RECT  0.084 61.056 0.137 61.08 ;
     RECT  0.06 61.08 0.137 61.152 ;
     RECT  0.084 61.152 0.137 61.176 ;
     RECT  0.06 61.176 0.137 61.248 ;
     RECT  0.084 61.248 0.137 61.272 ;
     RECT  0.06 61.272 0.137 61.344 ;
     RECT  0.084 61.344 0.137 61.368 ;
     RECT  0.06 61.368 0.137 61.44 ;
     RECT  0.084 61.44 0.137 61.464 ;
     RECT  0.06 61.464 0.137 61.536 ;
     RECT  0.084 61.536 0.137 61.56 ;
     RECT  0.06 61.56 0.137 61.632 ;
     RECT  0.084 61.632 0.137 61.656 ;
     RECT  0.06 61.656 0.137 61.728 ;
     RECT  0.084 61.728 0.137 61.752 ;
     RECT  0.06 61.752 0.137 61.824 ;
     RECT  0.084 61.824 0.137 61.848 ;
     RECT  0.06 61.848 0.137 61.92 ;
     RECT  0.084 61.92 0.137 61.944 ;
     RECT  0.06 61.944 0.137 62.064 ;
     RECT  0.084 62.064 0.137 62.088 ;
     RECT  0.06 62.088 0.137 62.16 ;
     RECT  0.084 62.16 0.137 62.184 ;
     RECT  0.06 62.184 0.137 62.256 ;
     RECT  0.084 62.256 0.137 62.28 ;
     RECT  0.06 62.28 0.137 62.352 ;
     RECT  0.084 62.352 0.137 62.376 ;
     RECT  0.06 62.376 0.137 62.448 ;
     RECT  0.084 62.448 0.137 62.472 ;
     RECT  0.06 62.472 0.137 62.544 ;
     RECT  0.084 62.544 0.137 62.568 ;
     RECT  0.06 62.568 0.137 62.64 ;
     RECT  0.084 62.64 0.137 62.664 ;
     RECT  0.06 62.664 0.137 62.736 ;
     RECT  0.084 62.736 0.137 62.76 ;
     RECT  0.137 0.72 2.704 62.76 ;
     RECT  2.704 0.72 2.765 23.592 ;
     RECT  2.765 0.72 2.837 12.6 ;
     RECT  2.765 18.192 2.837 23.592 ;
     RECT  2.704 24.72 2.837 62.76 ;
     RECT  2.837 0.72 2.873 12.504 ;
     RECT  2.765 16.8 2.873 16.92 ;
     RECT  2.837 18.192 2.873 23.304 ;
     RECT  2.837 24.72 2.873 42.024 ;
     RECT  2.873 7.344 2.909 12.504 ;
     RECT  2.873 16.896 2.909 16.92 ;
     RECT  2.873 38.736 2.909 42.024 ;
     RECT  2.837 43.296 2.909 52.248 ;
     RECT  2.837 53.28 2.909 62.76 ;
     RECT  2.765 13.584 2.945 15.816 ;
     RECT  2.909 38.736 2.945 39.768 ;
     RECT  2.909 7.344 2.981 12.312 ;
     RECT  2.909 43.296 2.981 51.144 ;
     RECT  2.873 18.48 3.017 19.896 ;
     RECT  2.945 38.736 3.017 39.624 ;
     RECT  2.909 40.896 3.017 42.024 ;
     RECT  2.981 43.392 3.017 50.952 ;
     RECT  2.909 53.28 3.017 57.96 ;
     RECT  2.981 8.496 3.053 12.312 ;
     RECT  2.873 25.152 3.125 37.608 ;
     RECT  3.017 43.392 3.125 46.632 ;
     RECT  3.017 49.488 3.125 50.952 ;
     RECT  3.017 47.856 3.161 48.216 ;
     RECT  2.873 20.88 3.197 20.952 ;
     RECT  3.125 28.464 3.197 37.608 ;
     RECT  3.125 45.984 3.197 46.632 ;
     RECT  2.873 21.984 3.233 23.304 ;
     RECT  3.125 43.392 3.233 44.856 ;
     RECT  2.909 52.176 3.233 52.248 ;
     RECT  3.233 43.392 3.269 44.712 ;
     RECT  3.017 53.28 3.269 57.864 ;
     RECT  2.909 59.232 3.269 62.76 ;
     RECT  2.873 0.72 3.305 6.12 ;
     RECT  2.981 7.344 3.305 7.416 ;
     RECT  3.053 8.784 3.305 12.312 ;
     RECT  3.269 43.392 3.305 44.376 ;
     RECT  3.197 46.56 3.305 46.632 ;
     RECT  3.233 52.176 3.305 52.2 ;
     RECT  3.269 53.28 3.305 57.336 ;
     RECT  3.269 59.808 3.305 62.76 ;
     RECT  3.305 8.784 3.341 11.736 ;
     RECT  3.017 19.872 3.341 19.896 ;
     RECT  3.017 41.904 3.341 42.024 ;
     RECT  3.161 48.192 3.341 48.216 ;
     RECT  3.125 50.352 3.341 50.952 ;
     RECT  3.305 0.72 3.377 3.672 ;
     RECT  3.017 38.736 3.377 39.576 ;
     RECT  3.305 55.392 3.413 57.336 ;
     RECT  3.305 53.28 3.443 54.168 ;
     RECT  3.341 50.352 3.485 50.712 ;
     RECT  3.305 61.2 3.485 62.76 ;
     RECT  3.305 59.808 3.737 59.832 ;
     RECT  3.197 20.928 3.841 20.952 ;
     RECT  3.233 21.984 3.841 22.872 ;
     RECT  3.197 28.656 3.841 37.608 ;
     RECT  3.305 4.752 3.877 6.12 ;
     RECT  2.945 14.112 3.877 15.816 ;
     RECT  3.485 61.488 3.989 62.76 ;
     RECT  3.305 46.56 4.061 46.584 ;
     RECT  3.017 18.48 4.165 18.792 ;
     RECT  3.841 20.928 4.309 22.872 ;
     RECT  4.268 47.568 4.309 47.592 ;
     RECT  4.309 20.592 4.412 22.872 ;
     RECT  3.877 14.112 4.417 16.296 ;
     RECT  4.417 13.632 4.489 16.296 ;
     RECT  4.412 19.92 4.489 22.872 ;
     RECT  3.377 0.72 4.529 2.856 ;
     RECT  4.309 47.568 4.633 48.504 ;
     RECT  3.989 61.488 4.741 62.376 ;
     RECT  4.165 17.952 4.813 18.792 ;
     RECT  4.489 19.92 4.813 23.592 ;
     RECT  4.633 47.568 4.849 48.696 ;
     RECT  4.381 52.224 4.849 52.248 ;
     RECT  4.529 1.056 4.961 2.856 ;
     RECT  3.341 41.904 5.065 41.976 ;
     RECT  4.961 1.44 5.108 2.856 ;
     RECT  3.877 4.752 5.108 6.312 ;
     RECT  3.305 7.344 5.108 7.368 ;
     RECT  3.341 9.072 5.108 11.736 ;
     RECT  4.489 12.864 5.108 16.392 ;
     RECT  4.813 17.952 5.108 23.592 ;
     RECT  3.125 25.152 5.108 27.336 ;
     RECT  3.841 28.656 5.108 38.184 ;
     RECT  3.377 39.552 5.108 39.576 ;
     RECT  5.065 41.904 5.108 42.024 ;
     RECT  3.305 44.064 5.108 44.376 ;
     RECT  4.849 47.04 5.108 48.696 ;
     RECT  3.485 50.352 5.108 50.376 ;
     RECT  4.849 51.696 5.108 52.248 ;
     RECT  3.443 53.28 5.108 54.12 ;
     RECT  3.413 55.392 5.108 55.416 ;
     RECT  3.413 56.496 5.108 57.336 ;
     RECT  4.849 59.568 5.108 59.592 ;
     RECT  4.741 60.816 5.108 62.376 ;
     RECT  5.108 1.44 5.212 62.652 ;
     RECT  5.212 1.44 5.285 62.472 ;
     RECT  5.285 2.418 5.404 62.472 ;
     RECT  5.404 44.064 5.933 44.424 ;
     RECT  5.852 0.096 5.939 0.12 ;
     RECT  5.404 4.752 6.649 6.312 ;
     RECT  5.404 25.2 6.685 27.192 ;
     RECT  5.404 39.552 6.721 39.576 ;
     RECT  5.404 41.904 6.721 42.024 ;
     RECT  5.404 48.192 6.721 48.696 ;
     RECT  5.404 17.952 6.829 23.592 ;
     RECT  5.404 47.04 6.829 47.064 ;
     RECT  6.721 48.192 6.829 48.792 ;
     RECT  6.649 4.752 6.833 6.696 ;
     RECT  6.829 47.04 6.833 48.792 ;
     RECT  5.404 2.496 6.937 2.808 ;
     RECT  5.404 50.352 7.189 50.376 ;
     RECT  5.404 59.568 7.261 59.592 ;
     RECT  5.404 60.816 7.513 62.472 ;
     RECT  5.404 51.696 7.657 52.248 ;
     RECT  5.404 53.28 7.657 54.12 ;
     RECT  6.937 2.496 7.765 2.904 ;
     RECT  5.404 12.864 7.765 16.392 ;
     RECT  7.261 59.52 7.765 59.592 ;
     RECT  7.765 2.064 7.808 2.904 ;
     RECT  6.833 4.752 7.808 6.312 ;
     RECT  5.404 9.072 7.808 11.736 ;
     RECT  7.765 12.816 7.808 16.392 ;
     RECT  6.829 17.52 7.808 23.592 ;
     RECT  6.685 25.2 7.808 27.336 ;
     RECT  5.404 29.232 7.808 38.184 ;
     RECT  6.721 39.456 7.808 39.576 ;
     RECT  6.721 41.904 7.808 42.072 ;
     RECT  5.933 44.16 7.808 44.424 ;
     RECT  6.833 47.04 7.808 48.696 ;
     RECT  7.189 50.112 7.808 50.376 ;
     RECT  7.657 51.696 7.808 54.12 ;
     RECT  5.404 56.496 7.808 57.336 ;
     RECT  7.765 59.232 7.808 59.592 ;
     RECT  7.513 60.816 7.808 62.568 ;
     RECT  7.808 2.064 7.912 62.652 ;
     RECT  7.912 2.064 8.104 62.568 ;
     RECT  8.104 51.552 8.201 52.248 ;
     RECT  8.104 55.536 8.417 56.088 ;
     RECT  8.104 2.064 8.531 27.192 ;
     RECT  8.531 17.904 8.597 27.192 ;
     RECT  8.201 51.552 8.597 52.2 ;
     RECT  8.597 17.904 9.029 26.904 ;
     RECT  8.104 47.136 9.097 49.08 ;
     RECT  8.104 50.112 9.097 50.136 ;
     RECT  8.417 56.064 9.097 56.088 ;
     RECT  8.104 59.232 9.109 59.544 ;
     RECT  8.104 60.816 9.109 62.568 ;
     RECT  8.104 28.944 9.133 38.184 ;
     RECT  8.104 39.552 9.133 39.576 ;
     RECT  9.097 47.136 9.133 50.136 ;
     RECT  8.597 51.552 9.133 52.152 ;
     RECT  8.104 57.312 9.133 57.336 ;
     RECT  9.029 17.904 9.173 20.184 ;
     RECT  9.133 47.136 9.173 52.152 ;
     RECT  8.104 41.76 9.205 42.12 ;
     RECT  8.104 43.344 9.251 45.576 ;
     RECT  9.097 56.064 9.277 56.328 ;
     RECT  9.133 57.312 9.277 57.432 ;
     RECT  9.205 41.04 9.349 42.12 ;
     RECT  9.133 54.672 9.452 54.696 ;
     RECT  8.531 2.064 9.589 16.872 ;
     RECT  9.133 28.944 9.961 39.576 ;
     RECT  9.251 43.392 9.961 45.576 ;
     RECT  9.277 56.064 9.961 57.432 ;
     RECT  9.029 21.168 10.033 26.904 ;
     RECT  9.961 28.944 10.033 39.816 ;
     RECT  9.349 41.04 10.033 42.168 ;
     RECT  9.961 43.392 10.033 46.056 ;
     RECT  8.104 53.376 10.033 53.4 ;
     RECT  9.961 56.064 10.033 58.248 ;
     RECT  9.109 59.232 10.033 62.568 ;
     RECT  10.033 43.392 10.069 46.104 ;
     RECT  9.173 47.136 10.069 52.056 ;
     RECT  9.589 2.064 10.141 16.92 ;
     RECT  9.173 17.952 10.141 20.184 ;
     RECT  10.033 21.168 10.141 27.096 ;
     RECT  10.033 53.28 10.141 53.4 ;
     RECT  9.452 54.528 10.141 54.696 ;
     RECT  10.033 56.064 10.141 62.568 ;
     RECT  10.141 2.064 10.177 27.192 ;
     RECT  10.033 28.704 10.177 42.168 ;
     RECT  10.069 43.392 10.177 52.056 ;
     RECT  10.141 53.28 10.177 62.568 ;
     RECT  10.177 2.064 10.249 42.168 ;
     RECT  10.249 2.064 10.285 42.264 ;
     RECT  10.177 43.392 10.285 62.616 ;
     RECT  10.285 2.064 10.508 62.616 ;
     RECT  10.508 2.064 10.612 62.652 ;
     RECT  10.612 2.064 11.981 62.568 ;
     RECT  11.981 2.064 13.208 62.328 ;
     RECT  13.208 2.064 13.312 62.652 ;
     RECT  13.312 2.064 13.993 62.52 ;
     RECT  13.993 1.152 14.461 62.52 ;
     RECT  14.461 0.96 14.569 62.52 ;
     RECT  14.569 0.96 16.441 62.76 ;
     RECT  16.441 0.72 19.357 62.76 ;
     RECT  19.357 0.624 21.516 0.648 ;
     RECT  19.357 0.648 21.564 0.72 ;
     RECT  19.357 0.72 21.516 0.744 ;
     RECT  19.357 0.744 21.564 0.816 ;
     RECT  19.357 0.816 21.516 0.84 ;
     RECT  19.357 0.84 21.564 0.96 ;
     RECT  19.357 0.96 21.516 0.984 ;
     RECT  19.357 0.984 21.564 1.056 ;
     RECT  19.357 1.056 21.516 1.08 ;
     RECT  19.357 1.08 21.564 1.152 ;
     RECT  19.357 1.152 21.516 1.176 ;
     RECT  19.357 1.176 21.564 1.248 ;
     RECT  19.357 1.248 21.516 1.272 ;
     RECT  19.357 1.272 21.564 1.344 ;
     RECT  19.357 1.344 21.516 1.368 ;
     RECT  19.357 1.368 21.564 1.44 ;
     RECT  19.357 1.44 21.516 1.464 ;
     RECT  19.357 1.464 21.564 1.536 ;
     RECT  19.357 1.536 21.516 1.56 ;
     RECT  19.357 1.56 21.564 1.632 ;
     RECT  19.357 1.632 21.516 1.656 ;
     RECT  19.357 1.656 21.564 1.728 ;
     RECT  19.357 1.728 21.516 1.752 ;
     RECT  19.357 1.752 21.564 1.824 ;
     RECT  19.357 1.824 21.516 1.848 ;
     RECT  19.357 1.848 21.564 1.92 ;
     RECT  19.357 1.92 21.516 1.944 ;
     RECT  19.357 1.944 21.564 2.016 ;
     RECT  19.357 2.016 21.516 2.04 ;
     RECT  19.357 2.04 21.564 2.112 ;
     RECT  19.357 2.112 21.516 2.136 ;
     RECT  19.357 2.136 21.564 2.256 ;
     RECT  19.357 2.256 21.516 2.28 ;
     RECT  19.357 2.28 21.564 2.352 ;
     RECT  19.357 2.352 21.516 2.376 ;
     RECT  19.357 2.376 21.564 2.448 ;
     RECT  19.357 2.448 21.516 2.472 ;
     RECT  19.357 2.472 21.564 2.544 ;
     RECT  19.357 2.544 21.516 2.568 ;
     RECT  19.357 2.568 21.564 2.64 ;
     RECT  19.357 2.64 21.516 2.664 ;
     RECT  19.357 2.664 21.564 2.736 ;
     RECT  19.357 2.736 21.516 2.76 ;
     RECT  19.357 2.76 21.564 2.832 ;
     RECT  19.357 2.832 21.516 2.856 ;
     RECT  19.357 2.856 21.564 2.928 ;
     RECT  19.357 2.928 21.516 2.952 ;
     RECT  19.357 2.952 21.564 3.024 ;
     RECT  19.357 3.024 21.516 3.048 ;
     RECT  19.357 3.048 21.564 3.12 ;
     RECT  19.357 3.12 21.516 3.144 ;
     RECT  19.357 3.144 21.564 3.216 ;
     RECT  19.357 3.216 21.516 3.24 ;
     RECT  19.357 3.24 21.564 3.312 ;
     RECT  19.357 3.312 21.516 3.336 ;
     RECT  19.357 3.336 21.564 3.408 ;
     RECT  19.357 3.408 21.516 3.432 ;
     RECT  19.357 3.432 21.564 3.552 ;
     RECT  19.357 3.552 21.516 3.576 ;
     RECT  19.357 3.576 21.564 3.648 ;
     RECT  19.357 3.648 21.516 3.672 ;
     RECT  19.357 3.672 21.564 3.744 ;
     RECT  19.357 3.744 21.516 3.768 ;
     RECT  19.357 3.768 21.564 3.84 ;
     RECT  19.357 3.84 21.516 3.864 ;
     RECT  19.357 3.864 21.564 3.936 ;
     RECT  19.357 3.936 21.516 3.96 ;
     RECT  19.357 3.96 21.564 4.032 ;
     RECT  19.357 4.032 21.516 4.056 ;
     RECT  19.357 4.056 21.564 4.128 ;
     RECT  19.357 4.128 21.516 4.152 ;
     RECT  19.357 4.152 21.564 4.224 ;
     RECT  19.357 4.224 21.516 4.248 ;
     RECT  19.357 4.248 21.564 4.32 ;
     RECT  19.357 4.32 21.516 4.344 ;
     RECT  19.357 4.344 21.564 4.416 ;
     RECT  19.357 4.416 21.516 4.44 ;
     RECT  19.357 4.44 21.564 4.512 ;
     RECT  19.357 4.512 21.516 4.536 ;
     RECT  19.357 4.536 21.564 4.608 ;
     RECT  19.357 4.608 21.516 4.632 ;
     RECT  19.357 4.632 21.564 4.704 ;
     RECT  19.357 4.704 21.516 4.728 ;
     RECT  19.357 4.728 21.564 4.848 ;
     RECT  19.357 4.848 21.516 4.872 ;
     RECT  19.357 4.872 21.564 4.944 ;
     RECT  19.357 4.944 21.516 4.968 ;
     RECT  19.357 4.968 21.564 5.04 ;
     RECT  19.357 5.04 21.516 5.064 ;
     RECT  19.357 5.064 21.564 5.136 ;
     RECT  19.357 5.136 21.516 5.16 ;
     RECT  19.357 5.16 21.564 5.232 ;
     RECT  19.357 5.232 21.516 5.256 ;
     RECT  19.357 5.256 21.564 5.328 ;
     RECT  19.357 5.328 21.516 5.352 ;
     RECT  19.357 5.352 21.564 5.424 ;
     RECT  19.357 5.424 21.516 5.448 ;
     RECT  19.357 5.448 21.564 5.52 ;
     RECT  19.357 5.52 21.516 5.544 ;
     RECT  19.357 5.544 21.564 5.616 ;
     RECT  19.357 5.616 21.516 5.64 ;
     RECT  19.357 5.64 21.564 5.712 ;
     RECT  19.357 5.712 21.516 5.736 ;
     RECT  19.357 5.736 21.564 5.808 ;
     RECT  19.357 5.808 21.516 5.832 ;
     RECT  19.357 5.832 21.564 5.904 ;
     RECT  19.357 5.904 21.516 5.928 ;
     RECT  19.357 5.928 21.564 6 ;
     RECT  19.357 6 21.516 6.024 ;
     RECT  19.357 6.024 21.564 6.144 ;
     RECT  19.357 6.144 21.516 6.168 ;
     RECT  19.357 6.168 21.564 6.24 ;
     RECT  19.357 6.24 21.516 6.264 ;
     RECT  19.357 6.264 21.564 6.336 ;
     RECT  19.357 6.336 21.516 6.36 ;
     RECT  19.357 6.36 21.564 6.432 ;
     RECT  19.357 6.432 21.516 6.456 ;
     RECT  19.357 6.456 21.564 6.528 ;
     RECT  19.357 6.528 21.516 6.552 ;
     RECT  19.357 6.552 21.564 6.624 ;
     RECT  19.357 6.624 21.516 6.648 ;
     RECT  19.357 6.648 21.564 6.72 ;
     RECT  19.357 6.72 21.516 6.744 ;
     RECT  19.357 6.744 21.564 6.816 ;
     RECT  19.357 6.816 21.516 6.84 ;
     RECT  19.357 6.84 21.564 6.912 ;
     RECT  19.357 6.912 21.516 6.936 ;
     RECT  19.357 6.936 21.564 7.008 ;
     RECT  19.357 7.008 21.516 7.032 ;
     RECT  19.357 7.032 21.564 7.104 ;
     RECT  19.357 7.104 21.516 7.128 ;
     RECT  19.357 7.128 21.564 7.2 ;
     RECT  19.357 7.2 21.516 7.224 ;
     RECT  19.357 7.224 21.564 7.296 ;
     RECT  19.357 7.296 21.516 7.32 ;
     RECT  19.357 7.32 21.564 7.44 ;
     RECT  19.357 7.44 21.516 7.464 ;
     RECT  19.357 7.464 21.564 7.536 ;
     RECT  19.357 7.536 21.516 7.56 ;
     RECT  19.357 7.56 21.564 7.632 ;
     RECT  19.357 7.632 21.516 7.656 ;
     RECT  19.357 7.656 21.564 7.728 ;
     RECT  19.357 7.728 21.516 7.752 ;
     RECT  19.357 7.752 21.564 7.824 ;
     RECT  19.357 7.824 21.516 7.848 ;
     RECT  19.357 7.848 21.564 7.92 ;
     RECT  19.357 7.92 21.516 7.944 ;
     RECT  19.357 7.944 21.564 8.016 ;
     RECT  19.357 8.016 21.516 8.04 ;
     RECT  19.357 8.04 21.564 8.112 ;
     RECT  19.357 8.112 21.516 8.136 ;
     RECT  19.357 8.136 21.564 8.208 ;
     RECT  19.357 8.208 21.516 8.232 ;
     RECT  19.357 8.232 21.564 8.304 ;
     RECT  19.357 8.304 21.516 8.328 ;
     RECT  19.357 8.328 21.564 8.4 ;
     RECT  19.357 8.4 21.516 8.424 ;
     RECT  19.357 8.424 21.564 8.496 ;
     RECT  19.357 8.496 21.516 8.52 ;
     RECT  19.357 8.52 21.564 8.592 ;
     RECT  19.357 8.592 21.516 8.616 ;
     RECT  19.357 8.616 21.564 8.736 ;
     RECT  19.357 8.736 21.516 8.76 ;
     RECT  19.357 8.76 21.564 8.832 ;
     RECT  19.357 8.832 21.516 8.856 ;
     RECT  19.357 8.856 21.564 8.928 ;
     RECT  19.357 8.928 21.516 8.952 ;
     RECT  19.357 8.952 21.564 9.024 ;
     RECT  19.357 9.024 21.516 9.048 ;
     RECT  19.357 9.048 21.564 9.12 ;
     RECT  19.357 9.12 21.516 9.144 ;
     RECT  19.357 9.144 21.564 9.216 ;
     RECT  19.357 9.216 21.516 9.24 ;
     RECT  19.357 9.24 21.564 9.312 ;
     RECT  19.357 9.312 21.516 9.336 ;
     RECT  19.357 9.336 21.564 9.408 ;
     RECT  19.357 9.408 21.516 9.432 ;
     RECT  19.357 9.432 21.564 9.504 ;
     RECT  19.357 9.504 21.516 9.528 ;
     RECT  19.357 9.528 21.564 9.6 ;
     RECT  19.357 9.6 21.516 9.624 ;
     RECT  19.357 9.624 21.564 9.696 ;
     RECT  19.357 9.696 21.516 9.72 ;
     RECT  19.357 9.72 21.564 9.792 ;
     RECT  19.357 9.792 21.516 9.816 ;
     RECT  19.357 9.816 21.564 9.888 ;
     RECT  19.357 9.888 21.516 9.912 ;
     RECT  19.357 9.912 21.564 10.032 ;
     RECT  19.357 10.032 21.516 10.056 ;
     RECT  19.357 10.056 21.564 10.128 ;
     RECT  19.357 10.128 21.516 10.152 ;
     RECT  19.357 10.152 21.564 10.224 ;
     RECT  19.357 10.224 21.516 10.248 ;
     RECT  19.357 10.248 21.564 10.32 ;
     RECT  19.357 10.32 21.516 10.344 ;
     RECT  19.357 10.344 21.564 10.416 ;
     RECT  19.357 10.416 21.516 10.44 ;
     RECT  19.357 10.44 21.564 10.512 ;
     RECT  19.357 10.512 21.516 10.536 ;
     RECT  19.357 10.536 21.564 10.608 ;
     RECT  19.357 10.608 21.516 10.632 ;
     RECT  19.357 10.632 21.564 10.704 ;
     RECT  19.357 10.704 21.516 10.728 ;
     RECT  19.357 10.728 21.564 10.8 ;
     RECT  19.357 10.8 21.516 10.824 ;
     RECT  19.357 10.824 21.564 10.896 ;
     RECT  19.357 10.896 21.516 10.92 ;
     RECT  19.357 10.92 21.564 10.992 ;
     RECT  19.357 10.992 21.516 11.016 ;
     RECT  19.357 11.016 21.564 11.088 ;
     RECT  19.357 11.088 21.516 11.112 ;
     RECT  19.357 11.112 21.564 11.184 ;
     RECT  19.357 11.184 21.516 11.208 ;
     RECT  19.357 11.208 21.564 11.328 ;
     RECT  19.357 11.328 21.516 11.352 ;
     RECT  19.357 11.352 21.564 11.424 ;
     RECT  19.357 11.424 21.516 11.448 ;
     RECT  19.357 11.448 21.564 11.52 ;
     RECT  19.357 11.52 21.516 11.544 ;
     RECT  19.357 11.544 21.564 11.616 ;
     RECT  19.357 11.616 21.516 11.64 ;
     RECT  19.357 11.64 21.564 11.712 ;
     RECT  19.357 11.712 21.516 11.736 ;
     RECT  19.357 11.736 21.564 11.808 ;
     RECT  19.357 11.808 21.516 11.832 ;
     RECT  19.357 11.832 21.564 11.904 ;
     RECT  19.357 11.904 21.516 11.928 ;
     RECT  19.357 11.928 21.564 12 ;
     RECT  19.357 12 21.516 12.024 ;
     RECT  19.357 12.024 21.564 12.096 ;
     RECT  19.357 12.096 21.516 12.12 ;
     RECT  19.357 12.12 21.564 12.192 ;
     RECT  19.357 12.192 21.516 12.216 ;
     RECT  19.357 12.216 21.564 12.288 ;
     RECT  19.357 12.288 21.516 12.312 ;
     RECT  19.357 12.312 21.564 12.384 ;
     RECT  19.357 12.384 21.516 12.408 ;
     RECT  19.357 12.408 21.564 12.48 ;
     RECT  19.357 12.48 21.516 12.504 ;
     RECT  19.357 12.504 21.564 12.576 ;
     RECT  19.357 12.576 21.516 12.6 ;
     RECT  19.357 12.6 21.564 12.72 ;
     RECT  19.357 12.72 21.516 12.744 ;
     RECT  19.357 12.744 21.564 12.816 ;
     RECT  19.357 12.816 21.516 12.84 ;
     RECT  19.357 12.84 21.564 12.912 ;
     RECT  19.357 12.912 21.516 12.936 ;
     RECT  19.357 12.936 21.564 13.008 ;
     RECT  19.357 13.008 21.516 13.032 ;
     RECT  19.357 13.032 21.564 13.104 ;
     RECT  19.357 13.104 21.516 13.128 ;
     RECT  19.357 13.128 21.564 13.2 ;
     RECT  19.357 13.2 21.516 13.224 ;
     RECT  19.357 13.224 21.564 13.296 ;
     RECT  19.357 13.296 21.516 13.32 ;
     RECT  19.357 13.32 21.564 13.392 ;
     RECT  19.357 13.392 21.516 13.416 ;
     RECT  19.357 13.416 21.564 13.488 ;
     RECT  19.357 13.488 21.516 13.512 ;
     RECT  19.357 13.512 21.564 13.584 ;
     RECT  19.357 13.584 21.516 13.608 ;
     RECT  19.357 13.608 21.564 13.68 ;
     RECT  19.357 13.68 21.516 13.704 ;
     RECT  19.357 13.704 21.564 13.776 ;
     RECT  19.357 13.776 21.516 13.8 ;
     RECT  19.357 13.8 21.564 13.872 ;
     RECT  19.357 13.872 21.516 13.896 ;
     RECT  19.357 13.896 21.564 14.016 ;
     RECT  19.357 14.016 21.516 14.04 ;
     RECT  19.357 14.04 21.564 14.112 ;
     RECT  19.357 14.112 21.516 14.136 ;
     RECT  19.357 14.136 21.564 14.208 ;
     RECT  19.357 14.208 21.516 14.232 ;
     RECT  19.357 14.232 21.564 14.304 ;
     RECT  19.357 14.304 21.516 14.328 ;
     RECT  19.357 14.328 21.564 14.4 ;
     RECT  19.357 14.4 21.516 14.424 ;
     RECT  19.357 14.424 21.564 14.496 ;
     RECT  19.357 14.496 21.516 14.52 ;
     RECT  19.357 14.52 21.564 14.592 ;
     RECT  19.357 14.592 21.516 14.616 ;
     RECT  19.357 14.616 21.564 14.688 ;
     RECT  19.357 14.688 21.516 14.712 ;
     RECT  19.357 14.712 21.564 14.784 ;
     RECT  19.357 14.784 21.516 14.808 ;
     RECT  19.357 14.808 21.564 14.88 ;
     RECT  19.357 14.88 21.516 14.904 ;
     RECT  19.357 14.904 21.564 14.976 ;
     RECT  19.357 14.976 21.516 15 ;
     RECT  19.357 15 21.564 15.072 ;
     RECT  19.357 15.072 21.516 15.096 ;
     RECT  19.357 15.096 21.564 15.168 ;
     RECT  19.357 15.168 21.516 15.192 ;
     RECT  19.357 15.192 21.564 15.312 ;
     RECT  19.357 15.312 21.516 15.336 ;
     RECT  19.357 15.336 21.564 15.408 ;
     RECT  19.357 15.408 21.516 15.432 ;
     RECT  19.357 15.432 21.564 15.504 ;
     RECT  19.357 15.504 21.516 15.528 ;
     RECT  19.357 15.528 21.564 15.6 ;
     RECT  19.357 15.6 21.516 15.624 ;
     RECT  19.357 15.624 21.564 15.696 ;
     RECT  19.357 15.696 21.516 15.72 ;
     RECT  19.357 15.72 21.564 15.792 ;
     RECT  19.357 15.792 21.516 15.816 ;
     RECT  19.357 15.816 21.564 15.888 ;
     RECT  19.357 15.888 21.516 15.912 ;
     RECT  19.357 15.912 21.564 15.984 ;
     RECT  19.357 15.984 21.516 16.008 ;
     RECT  19.357 16.008 21.564 16.08 ;
     RECT  19.357 16.08 21.516 16.104 ;
     RECT  19.357 16.104 21.564 16.176 ;
     RECT  19.357 16.176 21.516 16.2 ;
     RECT  19.357 16.2 21.564 16.272 ;
     RECT  19.357 16.272 21.516 16.296 ;
     RECT  19.357 16.296 21.564 16.368 ;
     RECT  19.357 16.368 21.516 16.392 ;
     RECT  19.357 16.392 21.564 16.464 ;
     RECT  19.357 16.464 21.516 16.488 ;
     RECT  19.357 16.488 21.564 16.608 ;
     RECT  19.357 16.608 21.516 16.632 ;
     RECT  19.357 16.632 21.564 16.704 ;
     RECT  19.357 16.704 21.516 16.728 ;
     RECT  19.357 16.728 21.564 16.8 ;
     RECT  19.357 16.8 21.516 16.824 ;
     RECT  19.357 16.824 21.564 16.896 ;
     RECT  19.357 16.896 21.516 16.92 ;
     RECT  19.357 16.92 21.564 16.992 ;
     RECT  19.357 16.992 21.516 17.016 ;
     RECT  19.357 17.016 21.564 17.088 ;
     RECT  19.357 17.088 21.516 17.112 ;
     RECT  19.357 17.112 21.564 17.184 ;
     RECT  19.357 17.184 21.516 17.208 ;
     RECT  19.357 17.208 21.564 17.28 ;
     RECT  19.357 17.28 21.516 17.304 ;
     RECT  19.357 17.304 21.564 17.376 ;
     RECT  19.357 17.376 21.516 17.4 ;
     RECT  19.357 17.4 21.564 17.472 ;
     RECT  19.357 17.472 21.516 17.496 ;
     RECT  19.357 17.496 21.564 17.568 ;
     RECT  19.357 17.568 21.516 17.592 ;
     RECT  19.357 17.592 21.564 17.664 ;
     RECT  19.357 17.664 21.516 17.688 ;
     RECT  19.357 17.688 21.564 17.76 ;
     RECT  19.357 17.76 21.516 17.784 ;
     RECT  19.357 17.784 21.564 17.904 ;
     RECT  19.357 17.904 21.516 17.928 ;
     RECT  19.357 17.928 21.564 18 ;
     RECT  19.357 18 21.516 18.024 ;
     RECT  19.357 18.024 21.564 18.096 ;
     RECT  19.357 18.096 21.516 18.12 ;
     RECT  19.357 18.12 21.564 18.192 ;
     RECT  19.357 18.192 21.516 18.216 ;
     RECT  19.357 18.216 21.564 18.288 ;
     RECT  19.357 18.288 21.516 18.312 ;
     RECT  19.357 18.312 21.564 18.384 ;
     RECT  19.357 18.384 21.516 18.408 ;
     RECT  19.357 18.408 21.564 18.48 ;
     RECT  19.357 18.48 21.516 18.504 ;
     RECT  19.357 18.504 21.564 18.576 ;
     RECT  19.357 18.576 21.516 18.6 ;
     RECT  19.357 18.6 21.564 18.672 ;
     RECT  19.357 18.672 21.516 18.696 ;
     RECT  19.357 18.696 21.564 18.768 ;
     RECT  19.357 18.768 21.516 18.792 ;
     RECT  19.357 18.792 21.564 18.864 ;
     RECT  19.357 18.864 21.516 18.888 ;
     RECT  19.357 18.888 21.564 18.96 ;
     RECT  19.357 18.96 21.516 18.984 ;
     RECT  19.357 18.984 21.564 19.056 ;
     RECT  19.357 19.056 21.516 19.08 ;
     RECT  19.357 19.08 21.564 19.2 ;
     RECT  19.357 19.2 21.516 19.224 ;
     RECT  19.357 19.224 21.564 19.296 ;
     RECT  19.357 19.296 21.516 19.32 ;
     RECT  19.357 19.32 21.564 19.392 ;
     RECT  19.357 19.392 21.516 19.416 ;
     RECT  19.357 19.416 21.564 19.488 ;
     RECT  19.357 19.488 21.516 19.512 ;
     RECT  19.357 19.512 21.564 19.584 ;
     RECT  19.357 19.584 21.516 19.608 ;
     RECT  19.357 19.608 21.564 19.68 ;
     RECT  19.357 19.68 21.516 19.704 ;
     RECT  19.357 19.704 21.564 19.776 ;
     RECT  19.357 19.776 21.516 19.8 ;
     RECT  19.357 19.8 21.564 19.872 ;
     RECT  19.357 19.872 21.516 19.896 ;
     RECT  19.357 19.896 21.564 19.968 ;
     RECT  19.357 19.968 21.516 19.992 ;
     RECT  19.357 19.992 21.564 20.064 ;
     RECT  19.357 20.064 21.516 20.088 ;
     RECT  19.357 20.088 21.564 20.16 ;
     RECT  19.357 20.16 21.516 20.184 ;
     RECT  19.357 20.184 21.564 20.256 ;
     RECT  19.357 20.256 21.516 20.28 ;
     RECT  19.357 20.28 21.564 20.352 ;
     RECT  19.357 20.352 21.516 20.376 ;
     RECT  19.357 20.376 21.564 20.496 ;
     RECT  19.357 20.496 21.516 20.52 ;
     RECT  19.357 20.52 21.564 20.592 ;
     RECT  19.357 20.592 21.516 20.616 ;
     RECT  19.357 20.616 21.564 20.688 ;
     RECT  19.357 20.688 21.516 20.712 ;
     RECT  19.357 20.712 21.564 20.784 ;
     RECT  19.357 20.784 21.516 20.808 ;
     RECT  19.357 20.808 21.564 20.88 ;
     RECT  19.357 20.88 21.516 20.904 ;
     RECT  19.357 20.904 21.564 20.976 ;
     RECT  19.357 20.976 21.516 21 ;
     RECT  19.357 21 21.564 21.072 ;
     RECT  19.357 21.072 21.516 21.096 ;
     RECT  19.357 21.096 21.564 21.168 ;
     RECT  19.357 21.168 21.516 21.192 ;
     RECT  19.357 21.192 21.564 21.264 ;
     RECT  19.357 21.264 21.516 21.288 ;
     RECT  19.357 21.288 21.564 21.36 ;
     RECT  19.357 21.36 21.516 21.384 ;
     RECT  19.357 21.384 21.564 21.456 ;
     RECT  19.357 21.456 21.516 21.48 ;
     RECT  19.357 21.48 21.564 21.552 ;
     RECT  19.357 21.552 21.516 21.576 ;
     RECT  19.357 21.576 21.564 21.648 ;
     RECT  19.357 21.648 21.516 21.672 ;
     RECT  19.357 21.672 21.564 21.792 ;
     RECT  19.357 21.792 21.516 21.816 ;
     RECT  19.357 21.816 21.564 21.888 ;
     RECT  19.357 21.888 21.516 21.912 ;
     RECT  19.357 21.912 21.564 21.984 ;
     RECT  19.357 21.984 21.516 22.008 ;
     RECT  19.357 22.008 21.564 22.08 ;
     RECT  19.357 22.08 21.516 22.104 ;
     RECT  19.357 22.104 21.564 22.176 ;
     RECT  19.357 22.176 21.516 22.2 ;
     RECT  19.357 22.2 21.564 22.272 ;
     RECT  19.357 22.272 21.516 22.296 ;
     RECT  19.357 22.296 21.564 22.368 ;
     RECT  19.357 22.368 21.516 22.392 ;
     RECT  19.357 22.392 21.564 22.464 ;
     RECT  19.357 22.464 21.516 22.488 ;
     RECT  19.357 22.488 21.564 22.56 ;
     RECT  19.357 22.56 21.516 22.584 ;
     RECT  19.357 22.584 21.564 22.656 ;
     RECT  19.357 22.656 21.516 22.68 ;
     RECT  19.357 22.68 21.564 22.752 ;
     RECT  19.357 22.752 21.516 22.776 ;
     RECT  19.357 22.776 21.564 22.848 ;
     RECT  19.357 22.848 21.516 22.872 ;
     RECT  19.357 22.872 21.564 22.944 ;
     RECT  19.357 22.944 21.516 22.968 ;
     RECT  19.357 22.968 21.564 23.088 ;
     RECT  19.357 23.088 21.516 23.112 ;
     RECT  19.357 23.112 21.564 23.184 ;
     RECT  19.357 23.184 21.516 23.208 ;
     RECT  19.357 23.208 21.564 23.28 ;
     RECT  19.357 23.28 21.516 23.304 ;
     RECT  19.357 23.304 21.564 23.376 ;
     RECT  19.357 23.376 21.516 23.4 ;
     RECT  19.357 23.4 21.564 23.472 ;
     RECT  19.357 23.472 21.516 23.496 ;
     RECT  19.357 23.496 21.564 23.568 ;
     RECT  19.357 23.568 21.516 23.592 ;
     RECT  19.357 23.592 21.564 23.664 ;
     RECT  19.357 23.664 21.516 23.688 ;
     RECT  19.357 23.688 21.564 23.76 ;
     RECT  19.357 23.76 21.516 23.784 ;
     RECT  19.357 23.784 21.564 23.856 ;
     RECT  19.357 23.856 21.516 23.88 ;
     RECT  19.357 23.88 21.564 23.952 ;
     RECT  19.357 23.952 21.516 23.976 ;
     RECT  19.357 23.976 21.564 24.048 ;
     RECT  19.357 24.048 21.516 24.072 ;
     RECT  19.357 24.072 21.564 24.144 ;
     RECT  19.357 24.144 21.516 24.168 ;
     RECT  19.357 24.168 21.564 24.24 ;
     RECT  19.357 24.24 21.516 24.264 ;
     RECT  19.357 24.264 21.564 24.384 ;
     RECT  19.357 24.384 21.516 24.408 ;
     RECT  19.357 24.408 21.564 24.48 ;
     RECT  19.357 24.48 21.516 24.504 ;
     RECT  19.357 24.504 21.564 24.576 ;
     RECT  19.357 24.576 21.516 24.6 ;
     RECT  19.357 24.6 21.564 24.672 ;
     RECT  19.357 24.672 21.516 24.696 ;
     RECT  19.357 24.696 21.564 24.768 ;
     RECT  19.357 24.768 21.516 24.792 ;
     RECT  19.357 24.792 21.564 24.864 ;
     RECT  19.357 24.864 21.516 24.888 ;
     RECT  19.357 24.888 21.564 24.96 ;
     RECT  19.357 24.96 21.516 24.984 ;
     RECT  19.357 24.984 21.564 25.056 ;
     RECT  19.357 25.056 21.516 25.08 ;
     RECT  19.357 25.08 21.564 25.152 ;
     RECT  19.357 25.152 21.516 25.176 ;
     RECT  19.357 25.176 21.564 25.248 ;
     RECT  19.357 25.248 21.516 25.272 ;
     RECT  19.357 25.272 21.564 25.344 ;
     RECT  19.357 25.344 21.516 25.368 ;
     RECT  19.357 25.368 21.564 25.44 ;
     RECT  19.357 25.44 21.516 25.464 ;
     RECT  19.357 25.464 21.564 25.536 ;
     RECT  19.357 25.536 21.516 25.56 ;
     RECT  19.357 25.56 21.564 25.68 ;
     RECT  19.357 25.68 21.516 25.704 ;
     RECT  19.357 25.704 21.564 25.776 ;
     RECT  19.357 25.776 21.516 25.8 ;
     RECT  19.357 25.8 21.564 25.872 ;
     RECT  19.357 25.872 21.516 25.896 ;
     RECT  19.357 25.896 21.564 25.968 ;
     RECT  19.357 25.968 21.516 25.992 ;
     RECT  19.357 25.992 21.564 26.064 ;
     RECT  19.357 26.064 21.516 26.088 ;
     RECT  19.357 26.088 21.564 26.16 ;
     RECT  19.357 26.16 21.516 26.184 ;
     RECT  19.357 26.184 21.564 26.256 ;
     RECT  19.357 26.256 21.516 26.28 ;
     RECT  19.357 26.28 21.564 26.352 ;
     RECT  19.357 26.352 21.516 26.376 ;
     RECT  19.357 26.376 21.564 26.448 ;
     RECT  19.357 26.448 21.516 26.472 ;
     RECT  19.357 26.472 21.564 26.544 ;
     RECT  19.357 26.544 21.516 26.568 ;
     RECT  19.357 26.568 21.564 26.64 ;
     RECT  19.357 26.64 21.516 26.664 ;
     RECT  19.357 26.664 21.564 26.736 ;
     RECT  19.357 26.736 21.516 26.76 ;
     RECT  19.357 26.76 21.564 26.832 ;
     RECT  19.357 26.832 21.516 26.856 ;
     RECT  19.357 26.856 21.564 26.976 ;
     RECT  19.357 26.976 21.516 27 ;
     RECT  19.357 27 21.564 27.072 ;
     RECT  19.357 27.072 21.516 27.096 ;
     RECT  19.357 27.096 21.564 27.168 ;
     RECT  19.357 27.168 21.516 27.192 ;
     RECT  19.357 27.192 21.564 27.264 ;
     RECT  19.357 27.264 21.516 27.288 ;
     RECT  19.357 27.288 21.564 27.36 ;
     RECT  19.357 27.36 21.516 27.384 ;
     RECT  19.357 27.384 21.564 27.456 ;
     RECT  19.357 27.456 21.516 27.48 ;
     RECT  19.357 27.48 21.564 27.552 ;
     RECT  19.357 27.552 21.516 27.576 ;
     RECT  19.357 27.576 21.564 27.648 ;
     RECT  19.357 27.648 21.516 27.672 ;
     RECT  19.357 27.672 21.564 27.744 ;
     RECT  19.357 27.744 21.516 27.768 ;
     RECT  19.357 27.768 21.564 27.84 ;
     RECT  19.357 27.84 21.516 27.864 ;
     RECT  19.357 27.864 21.564 27.936 ;
     RECT  19.357 27.936 21.516 27.96 ;
     RECT  19.357 27.96 21.564 28.032 ;
     RECT  19.357 28.032 21.516 28.056 ;
     RECT  19.357 28.056 21.564 28.128 ;
     RECT  19.357 28.128 21.516 28.152 ;
     RECT  19.357 28.152 21.564 28.272 ;
     RECT  19.357 28.272 21.516 28.296 ;
     RECT  19.357 28.296 21.564 28.368 ;
     RECT  19.357 28.368 21.516 28.392 ;
     RECT  19.357 28.392 21.564 28.464 ;
     RECT  19.357 28.464 21.516 28.488 ;
     RECT  19.357 28.488 21.564 28.56 ;
     RECT  19.357 28.56 21.516 28.584 ;
     RECT  19.357 28.584 21.564 28.656 ;
     RECT  19.357 28.656 21.516 28.68 ;
     RECT  19.357 28.68 21.564 28.752 ;
     RECT  19.357 28.752 21.516 28.776 ;
     RECT  19.357 28.776 21.564 28.848 ;
     RECT  19.357 28.848 21.516 28.872 ;
     RECT  19.357 28.872 21.564 28.944 ;
     RECT  19.357 28.944 21.516 28.968 ;
     RECT  19.357 28.968 21.564 29.04 ;
     RECT  19.357 29.04 21.516 29.064 ;
     RECT  19.357 29.064 21.564 29.136 ;
     RECT  19.357 29.136 21.516 29.16 ;
     RECT  19.357 29.16 21.564 29.232 ;
     RECT  19.357 29.232 21.516 29.256 ;
     RECT  19.357 29.256 21.564 29.328 ;
     RECT  19.357 29.328 21.516 29.352 ;
     RECT  19.357 29.352 21.564 29.424 ;
     RECT  19.357 29.424 21.516 29.448 ;
     RECT  19.357 29.448 21.564 29.568 ;
     RECT  19.357 29.568 21.516 29.592 ;
     RECT  19.357 29.592 21.564 29.664 ;
     RECT  19.357 29.664 21.516 29.688 ;
     RECT  19.357 29.688 21.564 29.76 ;
     RECT  19.357 29.76 21.516 29.784 ;
     RECT  19.357 29.784 21.564 29.856 ;
     RECT  19.357 29.856 21.516 29.88 ;
     RECT  19.357 29.88 21.564 29.952 ;
     RECT  19.357 29.952 21.516 29.976 ;
     RECT  19.357 29.976 21.564 30.048 ;
     RECT  19.357 30.048 21.516 30.072 ;
     RECT  19.357 30.072 21.564 30.144 ;
     RECT  19.357 30.144 21.516 30.168 ;
     RECT  19.357 30.168 21.564 30.24 ;
     RECT  19.357 30.24 21.516 30.264 ;
     RECT  19.357 30.264 21.564 30.336 ;
     RECT  19.357 30.336 21.516 30.36 ;
     RECT  19.357 30.36 21.564 30.432 ;
     RECT  19.357 30.432 21.516 30.456 ;
     RECT  19.357 30.456 21.564 30.528 ;
     RECT  19.357 30.528 21.516 30.552 ;
     RECT  19.357 30.552 21.564 30.624 ;
     RECT  19.357 30.624 21.516 30.648 ;
     RECT  19.357 30.648 21.564 30.72 ;
     RECT  19.357 30.72 21.516 30.744 ;
     RECT  19.357 30.744 21.564 30.864 ;
     RECT  19.357 30.864 21.516 30.888 ;
     RECT  19.357 30.888 21.564 30.96 ;
     RECT  19.357 30.96 21.516 30.984 ;
     RECT  19.357 30.984 21.564 31.056 ;
     RECT  19.357 31.056 21.516 31.08 ;
     RECT  19.357 31.08 21.564 31.152 ;
     RECT  19.357 31.152 21.516 31.176 ;
     RECT  19.357 31.176 21.564 31.248 ;
     RECT  19.357 31.248 21.516 31.272 ;
     RECT  19.357 31.272 21.564 31.344 ;
     RECT  19.357 31.344 21.516 31.368 ;
     RECT  19.357 31.368 21.564 31.44 ;
     RECT  19.357 31.44 21.516 31.464 ;
     RECT  19.357 31.464 21.564 31.536 ;
     RECT  19.357 31.536 21.516 31.56 ;
     RECT  19.357 31.56 21.564 31.632 ;
     RECT  19.357 31.632 21.516 31.656 ;
     RECT  19.357 31.656 21.564 31.728 ;
     RECT  19.357 31.728 21.516 31.752 ;
     RECT  19.357 31.752 21.564 31.824 ;
     RECT  19.357 31.824 21.516 31.848 ;
     RECT  19.357 31.848 21.564 31.92 ;
     RECT  19.357 31.92 21.516 31.944 ;
     RECT  19.357 31.944 21.564 32.016 ;
     RECT  19.357 32.016 21.516 32.04 ;
     RECT  19.357 32.04 21.564 32.16 ;
     RECT  19.357 32.16 21.516 32.184 ;
     RECT  19.357 32.184 21.564 32.256 ;
     RECT  19.357 32.256 21.516 32.28 ;
     RECT  19.357 32.28 21.564 32.352 ;
     RECT  19.357 32.352 21.516 32.376 ;
     RECT  19.357 32.376 21.564 32.448 ;
     RECT  19.357 32.448 21.516 32.472 ;
     RECT  19.357 32.472 21.564 32.544 ;
     RECT  19.357 32.544 21.516 32.568 ;
     RECT  19.357 32.568 21.564 32.64 ;
     RECT  19.357 32.64 21.516 32.664 ;
     RECT  19.357 32.664 21.564 32.736 ;
     RECT  19.357 32.736 21.516 32.76 ;
     RECT  19.357 32.76 21.564 32.832 ;
     RECT  19.357 32.832 21.516 32.856 ;
     RECT  19.357 32.856 21.564 32.928 ;
     RECT  19.357 32.928 21.516 32.952 ;
     RECT  19.357 32.952 21.564 33.024 ;
     RECT  19.357 33.024 21.516 33.048 ;
     RECT  19.357 33.048 21.564 33.12 ;
     RECT  19.357 33.12 21.516 33.144 ;
     RECT  19.357 33.144 21.564 33.216 ;
     RECT  19.357 33.216 21.516 33.24 ;
     RECT  19.357 33.24 21.564 33.312 ;
     RECT  19.357 33.312 21.516 33.336 ;
     RECT  19.357 33.336 21.564 33.456 ;
     RECT  19.357 33.456 21.516 33.48 ;
     RECT  19.357 33.48 21.564 33.552 ;
     RECT  19.357 33.552 21.516 33.576 ;
     RECT  19.357 33.576 21.564 33.648 ;
     RECT  19.357 33.648 21.516 33.672 ;
     RECT  19.357 33.672 21.564 33.744 ;
     RECT  19.357 33.744 21.516 33.768 ;
     RECT  19.357 33.768 21.564 33.84 ;
     RECT  19.357 33.84 21.516 33.864 ;
     RECT  19.357 33.864 21.564 33.936 ;
     RECT  19.357 33.936 21.516 33.96 ;
     RECT  19.357 33.96 21.564 34.032 ;
     RECT  19.357 34.032 21.516 34.056 ;
     RECT  19.357 34.056 21.564 34.128 ;
     RECT  19.357 34.128 21.516 34.152 ;
     RECT  19.357 34.152 21.564 34.224 ;
     RECT  19.357 34.224 21.516 34.248 ;
     RECT  19.357 34.248 21.564 34.32 ;
     RECT  19.357 34.32 21.516 34.344 ;
     RECT  19.357 34.344 21.564 34.416 ;
     RECT  19.357 34.416 21.516 34.44 ;
     RECT  19.357 34.44 21.564 34.512 ;
     RECT  19.357 34.512 21.516 34.536 ;
     RECT  19.357 34.536 21.564 34.608 ;
     RECT  19.357 34.608 21.516 34.632 ;
     RECT  19.357 34.632 21.564 34.752 ;
     RECT  19.357 34.752 21.516 34.776 ;
     RECT  19.357 34.776 21.564 34.848 ;
     RECT  19.357 34.848 21.516 34.872 ;
     RECT  19.357 34.872 21.564 34.944 ;
     RECT  19.357 34.944 21.516 34.968 ;
     RECT  19.357 34.968 21.564 35.04 ;
     RECT  19.357 35.04 21.516 35.064 ;
     RECT  19.357 35.064 21.564 35.136 ;
     RECT  19.357 35.136 21.516 35.16 ;
     RECT  19.357 35.16 21.564 35.232 ;
     RECT  19.357 35.232 21.516 35.256 ;
     RECT  19.357 35.256 21.564 35.328 ;
     RECT  19.357 35.328 21.516 35.352 ;
     RECT  19.357 35.352 21.564 35.424 ;
     RECT  19.357 35.424 21.516 35.448 ;
     RECT  19.357 35.448 21.564 35.52 ;
     RECT  19.357 35.52 21.516 35.544 ;
     RECT  19.357 35.544 21.564 35.616 ;
     RECT  19.357 35.616 21.516 35.64 ;
     RECT  19.357 35.64 21.564 35.712 ;
     RECT  19.357 35.712 21.516 35.736 ;
     RECT  19.357 35.736 21.564 35.808 ;
     RECT  19.357 35.808 21.516 35.832 ;
     RECT  19.357 35.832 21.564 35.904 ;
     RECT  19.357 35.904 21.516 35.928 ;
     RECT  19.357 35.928 21.564 36.048 ;
     RECT  19.357 36.048 21.516 36.072 ;
     RECT  19.357 36.072 21.564 36.144 ;
     RECT  19.357 36.144 21.516 36.168 ;
     RECT  19.357 36.168 21.564 36.24 ;
     RECT  19.357 36.24 21.516 36.264 ;
     RECT  19.357 36.264 21.564 36.336 ;
     RECT  19.357 36.336 21.516 36.36 ;
     RECT  19.357 36.36 21.564 36.432 ;
     RECT  19.357 36.432 21.516 36.456 ;
     RECT  19.357 36.456 21.564 36.528 ;
     RECT  19.357 36.528 21.516 36.552 ;
     RECT  19.357 36.552 21.564 36.624 ;
     RECT  19.357 36.624 21.516 36.648 ;
     RECT  19.357 36.648 21.564 36.72 ;
     RECT  19.357 36.72 21.516 36.744 ;
     RECT  19.357 36.744 21.564 36.816 ;
     RECT  19.357 36.816 21.516 36.84 ;
     RECT  19.357 36.84 21.564 36.912 ;
     RECT  19.357 36.912 21.516 36.936 ;
     RECT  19.357 36.936 21.564 37.008 ;
     RECT  19.357 37.008 21.516 37.032 ;
     RECT  19.357 37.032 21.564 37.104 ;
     RECT  19.357 37.104 21.516 37.128 ;
     RECT  19.357 37.128 21.564 37.2 ;
     RECT  19.357 37.2 21.516 37.224 ;
     RECT  19.357 37.224 21.564 37.344 ;
     RECT  19.357 37.344 21.516 37.368 ;
     RECT  19.357 37.368 21.564 37.44 ;
     RECT  19.357 37.44 21.516 37.464 ;
     RECT  19.357 37.464 21.564 37.536 ;
     RECT  19.357 37.536 21.516 37.56 ;
     RECT  19.357 37.56 21.564 37.632 ;
     RECT  19.357 37.632 21.516 37.656 ;
     RECT  19.357 37.656 21.564 37.728 ;
     RECT  19.357 37.728 21.516 37.752 ;
     RECT  19.357 37.752 21.564 37.824 ;
     RECT  19.357 37.824 21.516 37.848 ;
     RECT  19.357 37.848 21.564 37.92 ;
     RECT  19.357 37.92 21.516 37.944 ;
     RECT  19.357 37.944 21.564 38.016 ;
     RECT  19.357 38.016 21.516 38.04 ;
     RECT  19.357 38.04 21.564 38.112 ;
     RECT  19.357 38.112 21.516 38.136 ;
     RECT  19.357 38.136 21.564 38.208 ;
     RECT  19.357 38.208 21.516 38.232 ;
     RECT  19.357 38.232 21.564 38.304 ;
     RECT  19.357 38.304 21.516 38.328 ;
     RECT  19.357 38.328 21.564 38.4 ;
     RECT  19.357 38.4 21.516 38.424 ;
     RECT  19.357 38.424 21.564 38.496 ;
     RECT  19.357 38.496 21.516 38.52 ;
     RECT  19.357 38.52 21.564 38.64 ;
     RECT  19.357 38.64 21.516 38.664 ;
     RECT  19.357 38.664 21.564 38.736 ;
     RECT  19.357 38.736 21.516 38.76 ;
     RECT  19.357 38.76 21.564 38.832 ;
     RECT  19.357 38.832 21.516 38.856 ;
     RECT  19.357 38.856 21.564 38.928 ;
     RECT  19.357 38.928 21.516 38.952 ;
     RECT  19.357 38.952 21.564 39.024 ;
     RECT  19.357 39.024 21.516 39.048 ;
     RECT  19.357 39.048 21.564 39.12 ;
     RECT  19.357 39.12 21.516 39.144 ;
     RECT  19.357 39.144 21.564 39.216 ;
     RECT  19.357 39.216 21.516 39.24 ;
     RECT  19.357 39.24 21.564 39.312 ;
     RECT  19.357 39.312 21.516 39.336 ;
     RECT  19.357 39.336 21.564 39.408 ;
     RECT  19.357 39.408 21.516 39.432 ;
     RECT  19.357 39.432 21.564 39.504 ;
     RECT  19.357 39.504 21.516 39.528 ;
     RECT  19.357 39.528 21.564 39.6 ;
     RECT  19.357 39.6 21.516 39.624 ;
     RECT  19.357 39.624 21.564 39.696 ;
     RECT  19.357 39.696 21.516 39.72 ;
     RECT  19.357 39.72 21.564 39.792 ;
     RECT  19.357 39.792 21.516 39.816 ;
     RECT  19.357 39.816 21.564 39.936 ;
     RECT  19.357 39.936 21.516 39.96 ;
     RECT  19.357 39.96 21.564 40.032 ;
     RECT  19.357 40.032 21.516 40.056 ;
     RECT  19.357 40.056 21.564 40.128 ;
     RECT  19.357 40.128 21.516 40.152 ;
     RECT  19.357 40.152 21.564 40.224 ;
     RECT  19.357 40.224 21.516 40.248 ;
     RECT  19.357 40.248 21.564 40.32 ;
     RECT  19.357 40.32 21.516 40.344 ;
     RECT  19.357 40.344 21.564 40.416 ;
     RECT  19.357 40.416 21.516 40.44 ;
     RECT  19.357 40.44 21.564 40.512 ;
     RECT  19.357 40.512 21.516 40.536 ;
     RECT  19.357 40.536 21.564 40.608 ;
     RECT  19.357 40.608 21.516 40.632 ;
     RECT  19.357 40.632 21.564 40.704 ;
     RECT  19.357 40.704 21.516 40.728 ;
     RECT  19.357 40.728 21.564 40.8 ;
     RECT  19.357 40.8 21.516 40.824 ;
     RECT  19.357 40.824 21.564 40.896 ;
     RECT  19.357 40.896 21.516 40.92 ;
     RECT  19.357 40.92 21.564 40.992 ;
     RECT  19.357 40.992 21.516 41.016 ;
     RECT  19.357 41.016 21.564 41.088 ;
     RECT  19.357 41.088 21.516 41.112 ;
     RECT  19.357 41.112 21.564 41.184 ;
     RECT  19.357 41.184 21.516 41.208 ;
     RECT  19.357 41.208 21.564 41.328 ;
     RECT  19.357 41.328 21.516 41.352 ;
     RECT  19.357 41.352 21.564 41.424 ;
     RECT  19.357 41.424 21.516 41.448 ;
     RECT  19.357 41.448 21.564 41.52 ;
     RECT  19.357 41.52 21.516 41.544 ;
     RECT  19.357 41.544 21.564 41.616 ;
     RECT  19.357 41.616 21.516 41.64 ;
     RECT  19.357 41.64 21.564 41.712 ;
     RECT  19.357 41.712 21.516 41.736 ;
     RECT  19.357 41.736 21.564 41.808 ;
     RECT  19.357 41.808 21.516 41.832 ;
     RECT  19.357 41.832 21.564 41.904 ;
     RECT  19.357 41.904 21.516 41.928 ;
     RECT  19.357 41.928 21.564 42 ;
     RECT  19.357 42 21.516 42.024 ;
     RECT  19.357 42.024 21.564 42.096 ;
     RECT  19.357 42.096 21.516 42.12 ;
     RECT  19.357 42.12 21.564 42.192 ;
     RECT  19.357 42.192 21.516 42.216 ;
     RECT  19.357 42.216 21.564 42.288 ;
     RECT  19.357 42.288 21.516 42.312 ;
     RECT  19.357 42.312 21.564 42.384 ;
     RECT  19.357 42.384 21.516 42.408 ;
     RECT  19.357 42.408 21.564 42.48 ;
     RECT  19.357 42.48 21.516 42.504 ;
     RECT  19.357 42.504 21.564 42.624 ;
     RECT  19.357 42.624 21.516 42.648 ;
     RECT  19.357 42.648 21.564 42.72 ;
     RECT  19.357 42.72 21.516 42.744 ;
     RECT  19.357 42.744 21.564 42.816 ;
     RECT  19.357 42.816 21.516 42.84 ;
     RECT  19.357 42.84 21.564 42.912 ;
     RECT  19.357 42.912 21.516 42.936 ;
     RECT  19.357 42.936 21.564 43.008 ;
     RECT  19.357 43.008 21.516 43.032 ;
     RECT  19.357 43.032 21.564 43.104 ;
     RECT  19.357 43.104 21.516 43.128 ;
     RECT  19.357 43.128 21.564 43.2 ;
     RECT  19.357 43.2 21.516 43.224 ;
     RECT  19.357 43.224 21.564 43.296 ;
     RECT  19.357 43.296 21.516 43.32 ;
     RECT  19.357 43.32 21.564 43.392 ;
     RECT  19.357 43.392 21.516 43.416 ;
     RECT  19.357 43.416 21.564 43.488 ;
     RECT  19.357 43.488 21.516 43.512 ;
     RECT  19.357 43.512 21.564 43.584 ;
     RECT  19.357 43.584 21.516 43.608 ;
     RECT  19.357 43.608 21.564 43.68 ;
     RECT  19.357 43.68 21.516 43.704 ;
     RECT  19.357 43.704 21.564 43.776 ;
     RECT  19.357 43.776 21.516 43.8 ;
     RECT  19.357 43.8 21.564 43.92 ;
     RECT  19.357 43.92 21.516 43.944 ;
     RECT  19.357 43.944 21.564 44.016 ;
     RECT  19.357 44.016 21.516 44.04 ;
     RECT  19.357 44.04 21.564 44.112 ;
     RECT  19.357 44.112 21.516 44.136 ;
     RECT  19.357 44.136 21.564 44.208 ;
     RECT  19.357 44.208 21.516 44.232 ;
     RECT  19.357 44.232 21.564 44.304 ;
     RECT  19.357 44.304 21.516 44.328 ;
     RECT  19.357 44.328 21.564 44.4 ;
     RECT  19.357 44.4 21.516 44.424 ;
     RECT  19.357 44.424 21.564 44.496 ;
     RECT  19.357 44.496 21.516 44.52 ;
     RECT  19.357 44.52 21.564 44.592 ;
     RECT  19.357 44.592 21.516 44.616 ;
     RECT  19.357 44.616 21.564 44.688 ;
     RECT  19.357 44.688 21.516 44.712 ;
     RECT  19.357 44.712 21.564 44.784 ;
     RECT  19.357 44.784 21.516 44.808 ;
     RECT  19.357 44.808 21.564 44.88 ;
     RECT  19.357 44.88 21.516 44.904 ;
     RECT  19.357 44.904 21.564 44.976 ;
     RECT  19.357 44.976 21.516 45 ;
     RECT  19.357 45 21.564 45.072 ;
     RECT  19.357 45.072 21.516 45.096 ;
     RECT  19.357 45.096 21.564 45.216 ;
     RECT  19.357 45.216 21.516 45.24 ;
     RECT  19.357 45.24 21.564 45.312 ;
     RECT  19.357 45.312 21.516 45.336 ;
     RECT  19.357 45.336 21.564 45.408 ;
     RECT  19.357 45.408 21.516 45.432 ;
     RECT  19.357 45.432 21.564 45.504 ;
     RECT  19.357 45.504 21.516 45.528 ;
     RECT  19.357 45.528 21.564 45.6 ;
     RECT  19.357 45.6 21.516 45.624 ;
     RECT  19.357 45.624 21.564 45.696 ;
     RECT  19.357 45.696 21.516 45.72 ;
     RECT  19.357 45.72 21.564 45.792 ;
     RECT  19.357 45.792 21.516 45.816 ;
     RECT  19.357 45.816 21.564 45.888 ;
     RECT  19.357 45.888 21.516 45.912 ;
     RECT  19.357 45.912 21.564 45.984 ;
     RECT  19.357 45.984 21.516 46.008 ;
     RECT  19.357 46.008 21.564 46.08 ;
     RECT  19.357 46.08 21.516 46.104 ;
     RECT  19.357 46.104 21.564 46.176 ;
     RECT  19.357 46.176 21.516 46.2 ;
     RECT  19.357 46.2 21.564 46.272 ;
     RECT  19.357 46.272 21.516 46.296 ;
     RECT  19.357 46.296 21.564 46.368 ;
     RECT  19.357 46.368 21.516 46.392 ;
     RECT  19.357 46.392 21.564 46.512 ;
     RECT  19.357 46.512 21.516 46.536 ;
     RECT  19.357 46.536 21.564 46.608 ;
     RECT  19.357 46.608 21.516 46.632 ;
     RECT  19.357 46.632 21.564 46.704 ;
     RECT  19.357 46.704 21.516 46.728 ;
     RECT  19.357 46.728 21.564 46.8 ;
     RECT  19.357 46.8 21.516 46.824 ;
     RECT  19.357 46.824 21.564 46.896 ;
     RECT  19.357 46.896 21.516 46.92 ;
     RECT  19.357 46.92 21.564 46.992 ;
     RECT  19.357 46.992 21.516 47.016 ;
     RECT  19.357 47.016 21.564 47.088 ;
     RECT  19.357 47.088 21.516 47.112 ;
     RECT  19.357 47.112 21.564 47.184 ;
     RECT  19.357 47.184 21.516 47.208 ;
     RECT  19.357 47.208 21.564 47.28 ;
     RECT  19.357 47.28 21.516 47.304 ;
     RECT  19.357 47.304 21.564 47.376 ;
     RECT  19.357 47.376 21.516 47.4 ;
     RECT  19.357 47.4 21.564 47.472 ;
     RECT  19.357 47.472 21.516 47.496 ;
     RECT  19.357 47.496 21.564 47.568 ;
     RECT  19.357 47.568 21.516 47.592 ;
     RECT  19.357 47.592 21.564 47.664 ;
     RECT  19.357 47.664 21.516 47.688 ;
     RECT  19.357 47.688 21.564 47.808 ;
     RECT  19.357 47.808 21.516 47.832 ;
     RECT  19.357 47.832 21.564 47.904 ;
     RECT  19.357 47.904 21.516 47.928 ;
     RECT  19.357 47.928 21.564 48 ;
     RECT  19.357 48 21.516 48.024 ;
     RECT  19.357 48.024 21.564 48.096 ;
     RECT  19.357 48.096 21.516 48.12 ;
     RECT  19.357 48.12 21.564 48.192 ;
     RECT  19.357 48.192 21.516 48.216 ;
     RECT  19.357 48.216 21.564 48.288 ;
     RECT  19.357 48.288 21.516 48.312 ;
     RECT  19.357 48.312 21.564 48.384 ;
     RECT  19.357 48.384 21.516 48.408 ;
     RECT  19.357 48.408 21.564 48.48 ;
     RECT  19.357 48.48 21.516 48.504 ;
     RECT  19.357 48.504 21.564 48.576 ;
     RECT  19.357 48.576 21.516 48.6 ;
     RECT  19.357 48.6 21.564 48.672 ;
     RECT  19.357 48.672 21.516 48.696 ;
     RECT  19.357 48.696 21.564 48.768 ;
     RECT  19.357 48.768 21.516 48.792 ;
     RECT  19.357 48.792 21.564 48.864 ;
     RECT  19.357 48.864 21.516 48.888 ;
     RECT  19.357 48.888 21.564 48.96 ;
     RECT  19.357 48.96 21.516 48.984 ;
     RECT  19.357 48.984 21.564 49.104 ;
     RECT  19.357 49.104 21.516 49.128 ;
     RECT  19.357 49.128 21.564 49.2 ;
     RECT  19.357 49.2 21.516 49.224 ;
     RECT  19.357 49.224 21.564 49.296 ;
     RECT  19.357 49.296 21.516 49.32 ;
     RECT  19.357 49.32 21.564 49.392 ;
     RECT  19.357 49.392 21.516 49.416 ;
     RECT  19.357 49.416 21.564 49.488 ;
     RECT  19.357 49.488 21.516 49.512 ;
     RECT  19.357 49.512 21.564 49.584 ;
     RECT  19.357 49.584 21.516 49.608 ;
     RECT  19.357 49.608 21.564 49.68 ;
     RECT  19.357 49.68 21.516 49.704 ;
     RECT  19.357 49.704 21.564 49.776 ;
     RECT  19.357 49.776 21.516 49.8 ;
     RECT  19.357 49.8 21.564 49.872 ;
     RECT  19.357 49.872 21.516 49.896 ;
     RECT  19.357 49.896 21.564 49.968 ;
     RECT  19.357 49.968 21.516 49.992 ;
     RECT  19.357 49.992 21.564 50.064 ;
     RECT  19.357 50.064 21.516 50.088 ;
     RECT  19.357 50.088 21.564 50.16 ;
     RECT  19.357 50.16 21.516 50.184 ;
     RECT  19.357 50.184 21.564 50.256 ;
     RECT  19.357 50.256 21.516 50.28 ;
     RECT  19.357 50.28 21.564 50.4 ;
     RECT  19.357 50.4 21.516 50.424 ;
     RECT  19.357 50.424 21.564 50.496 ;
     RECT  19.357 50.496 21.516 50.52 ;
     RECT  19.357 50.52 21.564 50.592 ;
     RECT  19.357 50.592 21.516 50.616 ;
     RECT  19.357 50.616 21.564 50.688 ;
     RECT  19.357 50.688 21.516 50.712 ;
     RECT  19.357 50.712 21.564 50.784 ;
     RECT  19.357 50.784 21.516 50.808 ;
     RECT  19.357 50.808 21.564 50.88 ;
     RECT  19.357 50.88 21.516 50.904 ;
     RECT  19.357 50.904 21.564 50.976 ;
     RECT  19.357 50.976 21.516 51 ;
     RECT  19.357 51 21.564 51.072 ;
     RECT  19.357 51.072 21.516 51.096 ;
     RECT  19.357 51.096 21.564 51.168 ;
     RECT  19.357 51.168 21.516 51.192 ;
     RECT  19.357 51.192 21.564 51.264 ;
     RECT  19.357 51.264 21.516 51.288 ;
     RECT  19.357 51.288 21.564 51.36 ;
     RECT  19.357 51.36 21.516 51.384 ;
     RECT  19.357 51.384 21.564 51.456 ;
     RECT  19.357 51.456 21.516 51.48 ;
     RECT  19.357 51.48 21.564 51.552 ;
     RECT  19.357 51.552 21.516 51.576 ;
     RECT  19.357 51.576 21.564 51.696 ;
     RECT  19.357 51.696 21.516 51.72 ;
     RECT  19.357 51.72 21.564 51.792 ;
     RECT  19.357 51.792 21.516 51.816 ;
     RECT  19.357 51.816 21.564 51.888 ;
     RECT  19.357 51.888 21.516 51.912 ;
     RECT  19.357 51.912 21.564 51.984 ;
     RECT  19.357 51.984 21.516 52.008 ;
     RECT  19.357 52.008 21.564 52.08 ;
     RECT  19.357 52.08 21.516 52.104 ;
     RECT  19.357 52.104 21.564 52.176 ;
     RECT  19.357 52.176 21.516 52.2 ;
     RECT  19.357 52.2 21.564 52.272 ;
     RECT  19.357 52.272 21.516 52.296 ;
     RECT  19.357 52.296 21.564 52.368 ;
     RECT  19.357 52.368 21.516 52.392 ;
     RECT  19.357 52.392 21.564 52.464 ;
     RECT  19.357 52.464 21.516 52.488 ;
     RECT  19.357 52.488 21.564 52.56 ;
     RECT  19.357 52.56 21.516 52.584 ;
     RECT  19.357 52.584 21.564 52.656 ;
     RECT  19.357 52.656 21.516 52.68 ;
     RECT  19.357 52.68 21.564 52.752 ;
     RECT  19.357 52.752 21.516 52.776 ;
     RECT  19.357 52.776 21.564 52.848 ;
     RECT  19.357 52.848 21.516 52.872 ;
     RECT  19.357 52.872 21.564 52.992 ;
     RECT  19.357 52.992 21.516 53.016 ;
     RECT  19.357 53.016 21.564 53.088 ;
     RECT  19.357 53.088 21.516 53.112 ;
     RECT  19.357 53.112 21.564 53.184 ;
     RECT  19.357 53.184 21.516 53.208 ;
     RECT  19.357 53.208 21.564 53.28 ;
     RECT  19.357 53.28 21.516 53.304 ;
     RECT  19.357 53.304 21.564 53.376 ;
     RECT  19.357 53.376 21.516 53.4 ;
     RECT  19.357 53.4 21.564 53.472 ;
     RECT  19.357 53.472 21.516 53.496 ;
     RECT  19.357 53.496 21.564 53.568 ;
     RECT  19.357 53.568 21.516 53.592 ;
     RECT  19.357 53.592 21.564 53.664 ;
     RECT  19.357 53.664 21.516 53.688 ;
     RECT  19.357 53.688 21.564 53.76 ;
     RECT  19.357 53.76 21.516 53.784 ;
     RECT  19.357 53.784 21.564 53.856 ;
     RECT  19.357 53.856 21.516 53.88 ;
     RECT  19.357 53.88 21.564 53.952 ;
     RECT  19.357 53.952 21.516 53.976 ;
     RECT  19.357 53.976 21.564 54.048 ;
     RECT  19.357 54.048 21.516 54.072 ;
     RECT  19.357 54.072 21.564 54.144 ;
     RECT  19.357 54.144 21.516 54.168 ;
     RECT  19.357 54.168 21.564 54.288 ;
     RECT  19.357 54.288 21.516 54.312 ;
     RECT  19.357 54.312 21.564 54.384 ;
     RECT  19.357 54.384 21.516 54.408 ;
     RECT  19.357 54.408 21.564 54.48 ;
     RECT  19.357 54.48 21.516 54.504 ;
     RECT  19.357 54.504 21.564 54.576 ;
     RECT  19.357 54.576 21.516 54.6 ;
     RECT  19.357 54.6 21.564 54.672 ;
     RECT  19.357 54.672 21.516 54.696 ;
     RECT  19.357 54.696 21.564 54.768 ;
     RECT  19.357 54.768 21.516 54.792 ;
     RECT  19.357 54.792 21.564 54.864 ;
     RECT  19.357 54.864 21.516 54.888 ;
     RECT  19.357 54.888 21.564 54.96 ;
     RECT  19.357 54.96 21.516 54.984 ;
     RECT  19.357 54.984 21.564 55.056 ;
     RECT  19.357 55.056 21.516 55.08 ;
     RECT  19.357 55.08 21.564 55.152 ;
     RECT  19.357 55.152 21.516 55.176 ;
     RECT  19.357 55.176 21.564 55.248 ;
     RECT  19.357 55.248 21.516 55.272 ;
     RECT  19.357 55.272 21.564 55.344 ;
     RECT  19.357 55.344 21.516 55.368 ;
     RECT  19.357 55.368 21.564 55.44 ;
     RECT  19.357 55.44 21.516 55.464 ;
     RECT  19.357 55.464 21.564 55.584 ;
     RECT  19.357 55.584 21.516 55.608 ;
     RECT  19.357 55.608 21.564 55.68 ;
     RECT  19.357 55.68 21.516 55.704 ;
     RECT  19.357 55.704 21.564 55.776 ;
     RECT  19.357 55.776 21.516 55.8 ;
     RECT  19.357 55.8 21.564 55.872 ;
     RECT  19.357 55.872 21.516 55.896 ;
     RECT  19.357 55.896 21.564 55.968 ;
     RECT  19.357 55.968 21.516 55.992 ;
     RECT  19.357 55.992 21.564 56.064 ;
     RECT  19.357 56.064 21.516 56.088 ;
     RECT  19.357 56.088 21.564 56.16 ;
     RECT  19.357 56.16 21.516 56.184 ;
     RECT  19.357 56.184 21.564 56.256 ;
     RECT  19.357 56.256 21.516 56.28 ;
     RECT  19.357 56.28 21.564 56.352 ;
     RECT  19.357 56.352 21.516 56.376 ;
     RECT  19.357 56.376 21.564 56.448 ;
     RECT  19.357 56.448 21.516 56.472 ;
     RECT  19.357 56.472 21.564 56.544 ;
     RECT  19.357 56.544 21.516 56.568 ;
     RECT  19.357 56.568 21.564 56.64 ;
     RECT  19.357 56.64 21.516 56.664 ;
     RECT  19.357 56.664 21.564 56.736 ;
     RECT  19.357 56.736 21.516 56.76 ;
     RECT  19.357 56.76 21.564 56.88 ;
     RECT  19.357 56.88 21.516 56.904 ;
     RECT  19.357 56.904 21.564 56.976 ;
     RECT  19.357 56.976 21.516 57 ;
     RECT  19.357 57 21.564 57.072 ;
     RECT  19.357 57.072 21.516 57.096 ;
     RECT  19.357 57.096 21.564 57.168 ;
     RECT  19.357 57.168 21.516 57.192 ;
     RECT  19.357 57.192 21.564 57.264 ;
     RECT  19.357 57.264 21.516 57.288 ;
     RECT  19.357 57.288 21.564 57.36 ;
     RECT  19.357 57.36 21.516 57.384 ;
     RECT  19.357 57.384 21.564 57.456 ;
     RECT  19.357 57.456 21.516 57.48 ;
     RECT  19.357 57.48 21.564 57.552 ;
     RECT  19.357 57.552 21.516 57.576 ;
     RECT  19.357 57.576 21.564 57.648 ;
     RECT  19.357 57.648 21.516 57.672 ;
     RECT  19.357 57.672 21.564 57.744 ;
     RECT  19.357 57.744 21.516 57.768 ;
     RECT  19.357 57.768 21.564 57.84 ;
     RECT  19.357 57.84 21.516 57.864 ;
     RECT  19.357 57.864 21.564 57.936 ;
     RECT  19.357 57.936 21.516 57.96 ;
     RECT  19.357 57.96 21.564 58.032 ;
     RECT  19.357 58.032 21.516 58.056 ;
     RECT  19.357 58.056 21.564 58.176 ;
     RECT  19.357 58.176 21.516 58.2 ;
     RECT  19.357 58.2 21.564 58.272 ;
     RECT  19.357 58.272 21.516 58.296 ;
     RECT  19.357 58.296 21.564 58.368 ;
     RECT  19.357 58.368 21.516 58.392 ;
     RECT  19.357 58.392 21.564 58.464 ;
     RECT  19.357 58.464 21.516 58.488 ;
     RECT  19.357 58.488 21.564 58.56 ;
     RECT  19.357 58.56 21.516 58.584 ;
     RECT  19.357 58.584 21.564 58.656 ;
     RECT  19.357 58.656 21.516 58.68 ;
     RECT  19.357 58.68 21.564 58.752 ;
     RECT  19.357 58.752 21.516 58.776 ;
     RECT  19.357 58.776 21.564 58.848 ;
     RECT  19.357 58.848 21.516 58.872 ;
     RECT  19.357 58.872 21.564 58.944 ;
     RECT  19.357 58.944 21.516 58.968 ;
     RECT  19.357 58.968 21.564 59.04 ;
     RECT  19.357 59.04 21.516 59.064 ;
     RECT  19.357 59.064 21.564 59.136 ;
     RECT  19.357 59.136 21.516 59.16 ;
     RECT  19.357 59.16 21.564 59.232 ;
     RECT  19.357 59.232 21.516 59.256 ;
     RECT  19.357 59.256 21.564 59.328 ;
     RECT  19.357 59.328 21.516 59.352 ;
     RECT  19.357 59.352 21.564 59.472 ;
     RECT  19.357 59.472 21.516 59.496 ;
     RECT  19.357 59.496 21.564 59.568 ;
     RECT  19.357 59.568 21.516 59.592 ;
     RECT  19.357 59.592 21.564 59.664 ;
     RECT  19.357 59.664 21.516 59.688 ;
     RECT  19.357 59.688 21.564 59.76 ;
     RECT  19.357 59.76 21.516 59.784 ;
     RECT  19.357 59.784 21.564 59.856 ;
     RECT  19.357 59.856 21.516 59.88 ;
     RECT  19.357 59.88 21.564 59.952 ;
     RECT  19.357 59.952 21.516 59.976 ;
     RECT  19.357 59.976 21.564 60.048 ;
     RECT  19.357 60.048 21.516 60.072 ;
     RECT  19.357 60.072 21.564 60.144 ;
     RECT  19.357 60.144 21.516 60.168 ;
     RECT  19.357 60.168 21.564 60.24 ;
     RECT  19.357 60.24 21.516 60.264 ;
     RECT  19.357 60.264 21.564 60.336 ;
     RECT  19.357 60.336 21.516 60.36 ;
     RECT  19.357 60.36 21.564 60.432 ;
     RECT  19.357 60.432 21.516 60.456 ;
     RECT  19.357 60.456 21.564 60.528 ;
     RECT  19.357 60.528 21.516 60.552 ;
     RECT  19.357 60.552 21.564 60.624 ;
     RECT  19.357 60.624 21.516 60.648 ;
     RECT  19.357 60.648 21.564 60.768 ;
     RECT  19.357 60.768 21.516 60.792 ;
     RECT  19.357 60.792 21.564 60.864 ;
     RECT  19.357 60.864 21.516 60.888 ;
     RECT  19.357 60.888 21.564 60.96 ;
     RECT  19.357 60.96 21.516 60.984 ;
     RECT  19.357 60.984 21.564 61.056 ;
     RECT  19.357 61.056 21.516 61.08 ;
     RECT  19.357 61.08 21.564 61.152 ;
     RECT  19.357 61.152 21.516 61.176 ;
     RECT  19.357 61.176 21.564 61.248 ;
     RECT  19.357 61.248 21.516 61.272 ;
     RECT  19.357 61.272 21.564 61.344 ;
     RECT  19.357 61.344 21.516 61.368 ;
     RECT  19.357 61.368 21.564 61.44 ;
     RECT  19.357 61.44 21.516 61.464 ;
     RECT  19.357 61.464 21.564 61.536 ;
     RECT  19.357 61.536 21.516 61.56 ;
     RECT  19.357 61.56 21.564 61.632 ;
     RECT  19.357 61.632 21.516 61.656 ;
     RECT  19.357 61.656 21.564 61.728 ;
     RECT  19.357 61.728 21.516 61.752 ;
     RECT  19.357 61.752 21.564 61.824 ;
     RECT  19.357 61.824 21.516 61.848 ;
     RECT  19.357 61.848 21.564 61.92 ;
     RECT  19.357 61.92 21.516 61.944 ;
     RECT  19.357 61.944 21.564 62.064 ;
     RECT  19.357 62.064 21.516 62.088 ;
     RECT  19.357 62.088 21.564 62.16 ;
     RECT  19.357 62.16 21.516 62.184 ;
     RECT  19.357 62.184 21.564 62.256 ;
     RECT  19.357 62.256 21.516 62.28 ;
     RECT  19.357 62.28 21.564 62.352 ;
     RECT  19.357 62.352 21.516 62.376 ;
     RECT  19.357 62.376 21.564 62.448 ;
     RECT  19.357 62.448 21.516 62.472 ;
     RECT  19.357 62.472 21.564 62.544 ;
     RECT  19.357 62.544 21.516 62.568 ;
     RECT  19.357 62.568 21.564 62.64 ;
     RECT  19.357 62.64 21.516 62.664 ;
     RECT  19.357 62.664 21.564 62.736 ;
     RECT  19.357 62.736 21.516 62.76 ;
    LAYER M5 ;
     RECT  5.904 0.085 5.928 2.137 ;
     RECT  2.4 2.137 2.52 2.151 ;
     RECT  7.8 2.137 7.92 2.151 ;
     RECT  10.5 2.137 10.62 2.151 ;
     RECT  13.2 2.137 13.32 2.151 ;
     RECT  15.696 2.137 16.02 2.151 ;
     RECT  18.6 2.137 18.72 2.151 ;
     RECT  0.144 2.053 0.168 2.291 ;
     RECT  15.696 2.151 16.212 2.341 ;
     RECT  18.6 2.151 18.912 2.677 ;
     RECT  18.48 2.677 18.912 3.301 ;
     RECT  15.696 2.341 17.016 3.397 ;
     RECT  11.952 2.725 11.976 3.443 ;
     RECT  10.5 2.151 10.812 3.445 ;
     RECT  15.696 3.397 17.16 3.733 ;
     RECT  18.192 3.301 18.912 3.733 ;
     RECT  15.696 3.733 18.912 3.923 ;
     RECT  13.2 2.151 13.512 3.925 ;
     RECT  13.2 3.925 13.608 4.597 ;
     RECT  13.104 4.597 13.608 4.835 ;
     RECT  9.456 4.741 9.48 5.027 ;
     RECT  10.5 3.445 11.832 5.029 ;
     RECT  15.696 3.923 16.344 5.125 ;
     RECT  17.472 3.923 18.912 5.125 ;
     RECT  10.5 5.029 11.976 5.171 ;
     RECT  15.696 5.125 18.912 5.315 ;
     RECT  17.472 5.315 18.912 5.363 ;
     RECT  17.568 5.363 18.912 5.843 ;
     RECT  9.12 5.701 9.144 5.939 ;
     RECT  18.48 5.843 18.912 6.083 ;
     RECT  0.144 4.933 0.168 6.131 ;
     RECT  10.5 5.171 11.736 6.323 ;
     RECT  7.8 2.151 8.112 6.805 ;
     RECT  7.8 6.805 9 6.947 ;
     RECT  15.696 5.315 16.212 6.995 ;
     RECT  21.408 6.613 21.432 7.139 ;
     RECT  0.192 7.573 0.216 7.763 ;
     RECT  17.52 7.669 17.544 7.955 ;
     RECT  15.9 6.995 16.212 8.005 ;
     RECT  10.5 6.323 11.64 8.341 ;
     RECT  13.104 4.835 13.512 8.485 ;
     RECT  18.6 6.083 18.912 8.581 ;
     RECT  15.9 8.005 17.064 8.965 ;
     RECT  13.104 8.485 13.608 9.013 ;
     RECT  15.9 8.965 17.112 9.013 ;
     RECT  18.48 8.581 18.912 9.013 ;
     RECT  7.8 6.947 8.112 9.541 ;
     RECT  9.648 8.341 11.64 9.541 ;
     RECT  15.9 9.013 17.208 9.925 ;
     RECT  18.288 9.013 18.912 9.925 ;
     RECT  15.9 9.925 18.912 10.069 ;
     RECT  15.744 10.069 18.912 10.117 ;
     RECT  0.144 8.149 0.168 10.163 ;
     RECT  15.648 10.117 18.912 10.307 ;
     RECT  7.8 9.541 11.64 10.309 ;
     RECT  7.8 10.309 11.688 10.355 ;
     RECT  15.648 10.307 17.448 10.499 ;
     RECT  17.424 10.499 17.448 10.835 ;
     RECT  15.648 10.499 16.344 11.315 ;
     RECT  10.5 10.355 11.688 11.365 ;
     RECT  10.5 11.365 11.736 11.461 ;
     RECT  13.056 9.013 13.608 11.651 ;
     RECT  3.936 10.789 3.96 11.699 ;
     RECT  13.104 11.651 13.608 11.843 ;
     RECT  15.648 11.315 16.212 12.035 ;
     RECT  13.2 11.843 13.608 12.757 ;
     RECT  15.744 12.035 16.212 13.139 ;
     RECT  15.9 13.139 16.212 13.189 ;
     RECT  13.2 12.757 13.656 13.955 ;
     RECT  15.9 13.189 16.536 13.957 ;
     RECT  15.9 13.957 17.112 14.005 ;
     RECT  18.6 10.307 18.912 14.005 ;
     RECT  15.9 14.005 18.912 14.147 ;
     RECT  7.8 10.355 9.048 14.725 ;
     RECT  10.5 11.461 11.832 14.725 ;
     RECT  7.8 14.725 11.832 14.771 ;
     RECT  0.192 14.629 0.216 14.819 ;
     RECT  15.9 14.147 17.4 15.155 ;
     RECT  17.328 15.155 17.4 15.205 ;
     RECT  18.6 14.147 18.912 15.205 ;
     RECT  13.2 13.955 13.608 15.253 ;
     RECT  15.9 15.155 16.344 15.395 ;
     RECT  17.328 15.205 18.912 15.395 ;
     RECT  0.144 15.541 0.168 15.827 ;
     RECT  13.2 15.253 14.232 16.019 ;
     RECT  9.6 14.771 11.832 16.067 ;
     RECT  17.328 15.395 17.352 16.259 ;
     RECT  13.2 16.019 13.512 16.309 ;
     RECT  18.48 15.395 18.912 16.453 ;
     RECT  7.8 14.771 8.112 16.837 ;
     RECT  9.6 16.067 11.736 16.931 ;
     RECT  18.48 16.453 19.032 16.931 ;
     RECT  13.008 16.309 13.512 16.981 ;
     RECT  10.5 16.931 11.736 17.029 ;
     RECT  12.912 16.981 13.512 17.123 ;
     RECT  18.48 16.931 18.912 17.653 ;
     RECT  7.8 16.837 8.52 17.699 ;
     RECT  17.616 17.653 18.912 17.939 ;
     RECT  13.2 17.123 13.512 18.085 ;
     RECT  10.5 17.029 11.832 18.181 ;
     RECT  21.36 18.037 21.384 18.227 ;
     RECT  21.408 18.469 21.432 18.659 ;
     RECT  18.6 17.939 18.912 19.621 ;
     RECT  18.192 19.621 18.912 19.717 ;
     RECT  13.104 18.085 13.512 19.813 ;
     RECT  17.904 19.717 18.912 19.907 ;
     RECT  5.1 2.137 5.928 19.909 ;
     RECT  18.192 19.907 18.912 20.149 ;
     RECT  18.192 20.149 19.8 20.339 ;
     RECT  4.464 19.909 5.928 20.387 ;
     RECT  15.9 15.395 16.212 20.437 ;
     RECT  10.272 18.181 11.832 20.485 ;
     RECT  13.104 19.813 13.656 20.485 ;
     RECT  15.9 20.437 16.392 20.579 ;
     RECT  10.272 20.485 12.072 21.299 ;
     RECT  10.272 21.299 11.832 21.733 ;
     RECT  15.9 20.579 16.212 21.733 ;
     RECT  15.9 21.733 17.16 21.875 ;
     RECT  3.936 21.541 3.96 22.019 ;
     RECT  21.408 20.245 21.432 22.019 ;
     RECT  2.4 2.151 2.712 22.117 ;
     RECT  5.1 20.387 5.928 22.165 ;
     RECT  9.648 21.733 11.832 22.259 ;
     RECT  10.272 22.259 11.832 22.307 ;
     RECT  18.192 20.339 18.912 22.549 ;
     RECT  13.104 20.485 14.04 22.595 ;
     RECT  0.144 21.637 0.168 22.787 ;
     RECT  2.4 22.117 3.432 22.883 ;
     RECT  18.096 22.549 18.912 22.885 ;
     RECT  10.368 22.307 11.832 23.317 ;
     RECT  4.992 22.165 5.928 23.363 ;
     RECT  15.9 21.875 16.212 23.893 ;
     RECT  17.184 22.885 18.912 23.893 ;
     RECT  13.2 22.595 14.04 23.987 ;
     RECT  10.128 23.317 11.832 24.373 ;
     RECT  7.8 17.699 8.112 24.421 ;
     RECT  9.648 24.373 11.832 24.421 ;
     RECT  15.9 23.893 18.912 24.755 ;
     RECT  17.28 24.755 18.912 25.043 ;
     RECT  7.8 24.421 11.832 25.045 ;
     RECT  7.8 25.045 12.024 25.139 ;
     RECT  10.368 25.139 12.024 25.621 ;
     RECT  13.2 23.987 13.656 25.621 ;
     RECT  7.8 25.139 9.096 25.715 ;
     RECT  7.8 25.715 9.048 26.243 ;
     RECT  10.368 25.621 13.656 26.243 ;
     RECT  10.368 26.243 12.024 26.437 ;
     RECT  3.936 26.293 3.96 26.819 ;
     RECT  10.32 26.437 12.024 26.819 ;
     RECT  18.096 25.043 18.912 26.965 ;
     RECT  5.1 23.363 5.928 27.061 ;
     RECT  7.8 26.243 8.112 27.061 ;
     RECT  17.76 26.965 18.912 27.107 ;
     RECT  5.1 27.061 8.112 27.203 ;
     RECT  21.408 27.445 21.432 27.635 ;
     RECT  13.2 26.243 13.656 27.731 ;
     RECT  10.32 26.819 11.544 27.877 ;
     RECT  13.2 27.731 13.608 28.451 ;
     RECT  10.32 27.877 11.736 28.453 ;
     RECT  18.48 27.107 18.912 28.597 ;
     RECT  15.9 24.755 16.212 28.645 ;
     RECT  15.9 28.645 16.44 28.741 ;
     RECT  17.904 28.597 18.912 28.787 ;
     RECT  10.32 28.453 11.976 29.221 ;
     RECT  9.648 29.221 11.976 29.363 ;
     RECT  15.792 28.741 16.44 29.461 ;
     RECT  0.144 28.741 0.168 29.603 ;
     RECT  9.648 29.363 11.736 29.699 ;
     RECT  15.504 29.461 16.44 29.701 ;
     RECT  18.48 28.787 18.912 29.749 ;
     RECT  7.8 27.203 8.112 30.085 ;
     RECT  15.504 29.701 16.584 30.133 ;
     RECT  15.504 30.133 17.112 30.181 ;
     RECT  15.504 30.181 17.304 30.229 ;
     RECT  15.504 30.229 17.4 30.467 ;
     RECT  17.376 30.467 17.4 30.517 ;
     RECT  18.432 29.749 18.912 30.517 ;
     RECT  21.408 29.989 21.432 30.659 ;
     RECT  2.4 22.883 2.712 30.709 ;
     RECT  17.376 30.517 18.912 30.755 ;
     RECT  5.1 27.203 5.928 30.853 ;
     RECT  7.8 30.085 9.096 30.853 ;
     RECT  5.1 30.853 9.096 30.899 ;
     RECT  10.272 29.699 11.736 30.949 ;
     RECT  6.816 30.899 9.096 30.995 ;
     RECT  2.4 30.709 3.672 31.427 ;
     RECT  15.504 30.467 16.212 31.429 ;
     RECT  15.504 31.429 17.16 31.619 ;
     RECT  0.144 31.477 0.168 31.763 ;
     RECT  7.8 30.995 9.096 32.099 ;
     RECT  18.48 30.755 18.912 32.149 ;
     RECT  15.504 31.619 16.968 32.725 ;
     RECT  18.192 32.149 18.912 32.725 ;
     RECT  15.504 32.725 18.912 32.867 ;
     RECT  15.504 32.867 16.968 32.915 ;
     RECT  15.504 32.915 16.872 32.963 ;
     RECT  18 32.867 18.912 33.203 ;
     RECT  10.272 30.949 11.976 33.301 ;
     RECT  13.2 28.451 13.512 33.301 ;
     RECT  7.8 32.099 8.112 33.445 ;
     RECT  10.272 33.301 13.512 33.683 ;
     RECT  7.44 33.445 8.112 33.877 ;
     RECT  0.144 32.773 0.168 34.163 ;
     RECT  18.192 33.203 18.912 34.259 ;
     RECT  15.504 32.963 16.344 34.307 ;
     RECT  10.272 33.683 10.812 34.403 ;
     RECT  7.44 33.877 9.096 34.451 ;
     RECT  7.68 34.451 9.096 34.835 ;
     RECT  11.952 33.683 13.512 34.835 ;
     RECT  18.48 34.259 18.912 34.933 ;
     RECT  13.2 34.835 13.512 35.269 ;
     RECT  15.504 34.307 16.212 35.317 ;
     RECT  18.48 34.933 19.128 35.411 ;
     RECT  2.4 31.427 2.712 35.461 ;
     RECT  18.6 35.411 19.128 35.747 ;
     RECT  0.192 35.413 0.216 35.891 ;
     RECT  2.4 35.461 3.432 35.939 ;
     RECT  7.8 34.835 9.048 36.037 ;
     RECT  15.504 35.317 16.536 36.229 ;
     RECT  11.952 34.835 11.976 36.421 ;
     RECT  7.8 36.037 9.096 36.515 ;
     RECT  5.1 30.899 5.412 36.565 ;
     RECT  7.8 36.515 8.112 36.613 ;
     RECT  0.144 36.229 0.168 36.995 ;
     RECT  4.512 36.565 5.412 37.091 ;
     RECT  7.68 36.613 8.112 37.091 ;
     RECT  15.504 36.229 17.112 37.093 ;
     RECT  15.504 37.093 17.4 37.475 ;
     RECT  10.368 34.403 10.812 37.525 ;
     RECT  11.952 36.421 12.072 37.525 ;
     RECT  18.6 35.747 19.032 38.197 ;
     RECT  15.504 37.475 16.536 38.243 ;
     RECT  17.952 38.197 19.032 38.243 ;
     RECT  0.144 38.485 0.168 38.627 ;
     RECT  15.504 38.243 16.344 38.627 ;
     RECT  10.368 37.525 12.072 38.819 ;
     RECT  17.952 38.243 18.912 39.587 ;
     RECT  18.288 39.587 18.912 39.635 ;
     RECT  17.28 39.685 17.304 39.923 ;
     RECT  13.2 35.269 13.656 40.357 ;
     RECT  10.368 38.819 11.976 40.981 ;
     RECT  15.504 38.627 16.212 41.075 ;
     RECT  15.792 41.075 16.212 41.125 ;
     RECT  0.144 41.173 0.168 41.315 ;
     RECT  18.6 39.635 18.912 41.317 ;
     RECT  10.272 40.981 11.976 41.651 ;
     RECT  15.792 41.125 17.16 41.747 ;
     RECT  13.2 40.357 13.704 41.989 ;
     RECT  15.792 41.747 16.212 42.085 ;
     RECT  13.104 41.989 13.704 42.275 ;
     RECT  21.408 41.989 21.432 42.467 ;
     RECT  15.744 42.085 16.212 42.659 ;
     RECT  17.184 42.421 17.208 42.659 ;
     RECT  18.192 41.317 18.912 42.709 ;
     RECT  13.104 42.275 13.608 42.803 ;
     RECT  13.2 42.803 13.608 43.285 ;
     RECT  9.216 41.029 9.24 43.379 ;
     RECT  18.192 42.709 19.032 43.573 ;
     RECT  15.9 42.659 16.212 43.669 ;
     RECT  17.952 43.573 19.032 43.669 ;
     RECT  15.792 43.669 19.032 43.955 ;
     RECT  15.9 43.955 19.032 44.149 ;
     RECT  9.12 44.197 9.144 44.387 ;
     RECT  15.9 44.149 19.08 44.435 ;
     RECT  10.368 41.651 11.976 44.437 ;
     RECT  13.2 43.285 14.232 44.483 ;
     RECT  17.232 44.435 19.08 44.531 ;
     RECT  10.272 44.437 11.976 44.629 ;
     RECT  13.2 44.483 13.512 44.629 ;
     RECT  10.272 44.629 13.512 44.675 ;
     RECT  10.272 44.675 11.592 44.725 ;
     RECT  0.24 44.677 0.264 44.867 ;
     RECT  17.328 44.531 19.08 44.915 ;
     RECT  17.376 44.915 19.08 45.011 ;
     RECT  12.768 44.675 13.512 45.155 ;
     RECT  17.808 45.011 19.08 45.587 ;
     RECT  10.176 44.725 11.592 45.973 ;
     RECT  17.952 45.587 19.08 46.067 ;
     RECT  0.144 46.309 0.168 46.643 ;
     RECT  10.176 45.973 11.976 46.787 ;
     RECT  18.6 46.067 19.08 46.787 ;
     RECT  10.176 46.787 11.736 46.883 ;
     RECT  15.9 44.435 16.212 47.077 ;
     RECT  15.9 47.077 16.824 47.509 ;
     RECT  5.1 37.091 5.412 47.557 ;
     RECT  0.144 47.653 0.168 47.795 ;
     RECT  15.9 47.509 17.064 48.133 ;
     RECT  18.6 46.787 18.912 48.133 ;
     RECT  0.24 48.181 0.264 48.371 ;
     RECT  13.2 45.155 13.512 48.469 ;
     RECT  4.32 47.557 5.412 48.515 ;
     RECT  15.9 48.133 18.912 48.563 ;
     RECT  15.9 48.563 17.112 48.709 ;
     RECT  15.36 48.709 17.112 49.187 ;
     RECT  10.5 46.883 11.736 49.381 ;
     RECT  0.144 49.333 0.168 49.523 ;
     RECT  15.36 49.187 17.016 49.523 ;
     RECT  15.36 49.523 16.44 49.811 ;
     RECT  13.104 48.469 13.512 49.907 ;
     RECT  10.5 49.381 11.832 50.101 ;
     RECT  18.24 48.563 18.912 50.197 ;
     RECT  15.36 49.811 16.212 50.483 ;
     RECT  13.2 49.907 13.512 50.677 ;
     RECT  17.664 50.197 18.912 50.771 ;
     RECT  13.2 50.677 13.608 50.869 ;
     RECT  13.008 50.869 13.608 51.011 ;
     RECT  10.224 50.101 11.832 51.395 ;
     RECT  9.216 47.845 9.24 51.541 ;
     RECT  9.216 51.541 9.528 51.587 ;
     RECT  7.8 37.091 8.112 51.973 ;
     RECT  13.2 51.011 13.608 52.165 ;
     RECT  15.9 50.483 16.212 52.261 ;
     RECT  18.096 50.771 18.912 52.261 ;
     RECT  15.9 52.261 18.912 52.357 ;
     RECT  0.192 52.261 0.216 52.451 ;
     RECT  15.9 52.357 19.032 52.643 ;
     RECT  17.232 52.643 19.032 52.739 ;
     RECT  7.68 51.973 8.112 53.075 ;
     RECT  10.5 51.395 11.832 53.075 ;
     RECT  2.4 35.939 2.712 53.269 ;
     RECT  17.232 52.739 18.912 53.363 ;
     RECT  0.144 53.557 0.168 53.747 ;
     RECT  2.4 53.269 3.432 54.179 ;
     RECT  10.5 53.075 11.784 54.661 ;
     RECT  17.712 53.363 18.912 54.949 ;
     RECT  0.192 54.901 0.216 55.187 ;
     RECT  15.9 52.643 16.212 55.861 ;
     RECT  17.616 54.949 18.912 55.861 ;
     RECT  0.144 56.245 0.168 56.435 ;
     RECT  10.5 54.661 11.976 56.531 ;
     RECT  9.504 51.587 9.528 57.059 ;
     RECT  15.9 55.861 18.912 57.253 ;
     RECT  13.2 52.165 13.992 57.301 ;
     RECT  15.792 57.253 18.912 57.923 ;
     RECT  13.104 57.301 13.992 58.163 ;
     RECT  10.5 56.531 11.736 58.211 ;
     RECT  13.104 58.163 13.512 58.643 ;
     RECT  0.144 58.501 0.168 58.691 ;
     RECT  10.5 58.211 11.4 59.219 ;
     RECT  10.5 59.219 10.812 59.221 ;
     RECT  9.12 59.269 9.144 59.317 ;
     RECT  15.9 57.923 18.912 59.989 ;
     RECT  9.12 59.317 9.336 60.131 ;
     RECT  12 59.797 12.024 60.277 ;
     RECT  11.952 60.277 12.024 60.661 ;
     RECT  15.9 59.989 19.08 60.755 ;
     RECT  11.952 60.661 12.168 60.851 ;
     RECT  11.952 60.851 12.024 60.853 ;
     RECT  9.12 60.131 9.144 60.995 ;
     RECT  10.368 59.221 10.812 61.187 ;
     RECT  15.9 60.755 17.208 61.283 ;
     RECT  0.144 61.189 0.168 61.379 ;
     RECT  11.808 60.853 12.024 61.619 ;
     RECT  17.184 61.283 17.208 61.957 ;
     RECT  18.6 60.755 19.08 62.195 ;
     RECT  11.808 61.619 11.832 62.243 ;
     RECT  17.184 61.957 17.592 62.243 ;
     RECT  17.568 62.243 17.592 62.435 ;
     RECT  2.4 54.179 2.712 62.649 ;
     RECT  5.1 48.515 5.412 62.649 ;
     RECT  7.8 53.075 8.112 62.649 ;
     RECT  10.5 61.187 10.812 62.649 ;
     RECT  13.2 58.643 13.512 62.649 ;
     RECT  15.9 61.283 16.212 62.649 ;
     RECT  18.6 62.195 18.912 62.649 ;
     RECT  2.4 62.649 2.52 62.663 ;
     RECT  5.1 62.649 5.22 62.663 ;
     RECT  7.8 62.649 7.92 62.663 ;
     RECT  10.5 62.649 10.62 62.663 ;
     RECT  13.2 62.649 13.32 62.663 ;
     RECT  15.9 62.649 16.02 62.663 ;
     RECT  18.6 62.649 18.72 62.663 ;
     RECT  17.016 2.677 18.48 3.301 ;
     RECT  10.812 2.725 11.952 3.443 ;
     RECT  11.976 2.725 13.2 3.443 ;
     RECT  17.016 3.301 18.192 3.397 ;
     RECT  17.16 3.397 18.192 3.733 ;
     RECT  10.812 3.443 13.2 3.445 ;
     RECT  11.832 3.445 13.2 4.597 ;
     RECT  16.344 3.923 17.472 5.125 ;
     RECT  11.832 4.597 13.104 5.029 ;
     RECT  8.112 4.741 9.456 5.027 ;
     RECT  9.48 4.741 10.5 5.027 ;
     RECT  8.112 5.027 10.5 5.701 ;
     RECT  11.976 5.029 13.104 5.171 ;
     RECT  11.736 5.171 13.104 6.323 ;
     RECT  16.212 5.315 17.472 5.363 ;
     RECT  16.212 5.363 17.568 5.843 ;
     RECT  8.112 5.701 9.12 5.939 ;
     RECT  9.144 5.701 10.5 5.939 ;
     RECT  8.112 5.939 10.5 6.805 ;
     RECT  11.64 6.323 13.104 9.013 ;
     RECT  9 6.805 10.5 6.947 ;
     RECT  9.648 6.947 10.5 8.341 ;
     RECT  16.212 7.669 17.52 7.955 ;
     RECT  17.544 7.669 18.6 7.955 ;
     RECT  16.212 7.955 18.6 8.005 ;
     RECT  17.064 8.005 18.6 8.581 ;
     RECT  17.064 8.581 18.48 8.965 ;
     RECT  17.112 8.965 18.48 9.013 ;
     RECT  11.64 9.013 13.056 10.309 ;
     RECT  17.208 9.013 18.288 9.925 ;
     RECT  17.448 10.307 18.6 10.835 ;
     RECT  11.688 10.309 13.056 11.365 ;
     RECT  9.048 10.355 10.5 14.725 ;
     RECT  16.344 10.499 17.424 10.835 ;
     RECT  2.712 10.789 3.936 11.699 ;
     RECT  3.96 10.789 5.1 11.699 ;
     RECT  11.736 11.365 13.056 11.461 ;
     RECT  11.832 11.461 13.056 11.651 ;
     RECT  11.832 11.651 13.104 11.843 ;
     RECT  11.832 11.843 13.2 16.067 ;
     RECT  13.608 13.955 13.656 15.253 ;
     RECT  17.112 13.957 18.6 14.005 ;
     RECT  17.4 14.147 18.6 15.205 ;
     RECT  8.112 14.771 9.6 16.837 ;
     RECT  16.344 15.155 17.328 15.395 ;
     RECT  16.212 15.395 17.328 16.259 ;
     RECT  17.352 15.395 18.48 16.259 ;
     RECT  11.736 16.067 13.2 16.309 ;
     RECT  16.212 16.259 18.48 17.653 ;
     RECT  11.736 16.309 13.008 16.981 ;
     RECT  8.52 16.837 9.6 16.931 ;
     RECT  10.272 16.931 10.5 18.181 ;
     RECT  11.736 16.981 12.912 17.029 ;
     RECT  11.832 17.029 12.912 17.123 ;
     RECT  11.832 17.123 13.2 18.085 ;
     RECT  16.212 17.653 17.616 17.939 ;
     RECT  11.832 18.085 13.104 20.485 ;
     RECT  4.464 20.387 5.1 21.541 ;
     RECT  12.072 20.485 13.104 21.299 ;
     RECT  16.212 20.579 16.392 21.733 ;
     RECT  11.832 21.299 13.104 22.595 ;
     RECT  2.712 21.541 3.936 22.019 ;
     RECT  3.96 21.541 5.1 22.019 ;
     RECT  17.16 21.733 18.192 21.875 ;
     RECT  16.212 21.875 18.192 22.549 ;
     RECT  2.712 22.019 3.432 22.117 ;
     RECT  4.992 22.019 5.1 22.165 ;
     RECT  10.128 22.259 10.272 22.307 ;
     RECT  10.128 22.307 10.368 23.317 ;
     RECT  16.212 22.549 18.096 22.885 ;
     RECT  11.832 22.595 13.2 25.045 ;
     RECT  16.212 22.885 17.184 23.893 ;
     RECT  16.212 24.755 17.28 25.043 ;
     RECT  12.024 25.045 13.2 25.621 ;
     RECT  9.096 25.139 10.368 25.715 ;
     RECT  9.048 25.715 10.368 26.243 ;
     RECT  10.32 26.243 10.368 26.437 ;
     RECT  12.024 26.243 13.2 26.819 ;
     RECT  2.712 26.293 3.936 26.819 ;
     RECT  3.96 26.293 5.1 26.819 ;
     RECT  11.544 26.819 13.2 27.877 ;
     RECT  17.904 27.107 18.48 28.597 ;
     RECT  11.736 27.877 13.2 28.453 ;
     RECT  11.976 28.453 13.2 29.363 ;
     RECT  16.44 28.645 17.904 28.787 ;
     RECT  16.44 28.787 18.48 29.701 ;
     RECT  11.736 29.363 13.2 30.949 ;
     RECT  9.648 29.699 10.272 30.085 ;
     RECT  16.584 29.701 18.48 29.749 ;
     RECT  16.584 29.749 18.432 30.133 ;
     RECT  9.096 30.085 10.272 32.099 ;
     RECT  17.112 30.133 18.432 30.181 ;
     RECT  17.304 30.181 18.432 30.229 ;
     RECT  17.4 30.229 18.432 30.517 ;
     RECT  16.212 30.467 17.376 30.755 ;
     RECT  3.672 30.709 5.1 31.427 ;
     RECT  16.212 30.755 18.48 31.429 ;
     RECT  5.412 30.899 6.816 30.995 ;
     RECT  11.976 30.949 13.2 33.301 ;
     RECT  17.16 31.429 18.48 31.619 ;
     RECT  16.968 31.619 18.48 32.149 ;
     RECT  16.968 32.149 18.192 32.725 ;
     RECT  16.968 32.867 18 32.915 ;
     RECT  16.872 32.915 18 32.963 ;
     RECT  10.812 33.683 11.952 37.525 ;
     RECT  9.096 33.877 10.272 34.403 ;
     RECT  16.212 34.307 16.344 35.317 ;
     RECT  9.096 34.403 10.368 34.835 ;
     RECT  9.048 34.835 10.368 36.037 ;
     RECT  11.976 34.835 13.2 36.421 ;
     RECT  18.48 35.411 18.6 36.229 ;
     RECT  9.096 36.037 10.368 36.515 ;
     RECT  17.112 36.229 18.6 37.093 ;
     RECT  12.072 36.421 13.2 38.819 ;
     RECT  17.4 37.093 18.6 37.475 ;
     RECT  16.536 37.475 18.6 38.197 ;
     RECT  16.536 38.197 17.952 38.243 ;
     RECT  16.344 38.243 17.952 38.627 ;
     RECT  16.212 38.627 17.952 39.587 ;
     RECT  11.976 38.819 13.2 41.989 ;
     RECT  16.212 39.587 18.288 39.635 ;
     RECT  16.212 39.635 18.6 39.685 ;
     RECT  16.212 39.685 17.28 39.923 ;
     RECT  17.304 39.685 18.6 39.923 ;
     RECT  16.212 39.923 18.6 41.125 ;
     RECT  8.112 41.029 9.216 43.379 ;
     RECT  9.24 41.029 10.272 41.651 ;
     RECT  15.744 41.075 15.792 42.085 ;
     RECT  17.16 41.125 18.6 41.317 ;
     RECT  17.16 41.317 18.192 41.747 ;
     RECT  9.24 41.651 10.368 43.379 ;
     RECT  16.212 41.747 18.192 42.421 ;
     RECT  11.976 41.989 13.104 42.803 ;
     RECT  13.608 42.275 13.704 43.285 ;
     RECT  16.212 42.421 17.184 42.659 ;
     RECT  17.208 42.421 18.192 42.659 ;
     RECT  15.792 42.659 15.9 43.669 ;
     RECT  16.212 42.659 18.192 43.573 ;
     RECT  11.976 42.803 13.2 44.629 ;
     RECT  8.112 43.379 10.368 44.197 ;
     RECT  16.212 43.573 17.952 43.669 ;
     RECT  8.112 44.197 9.12 44.387 ;
     RECT  9.144 44.197 10.368 44.387 ;
     RECT  10.176 44.387 10.368 44.437 ;
     RECT  16.212 44.435 17.232 44.531 ;
     RECT  10.176 44.437 10.272 44.725 ;
     RECT  16.212 44.531 17.328 44.915 ;
     RECT  11.592 44.675 12.768 45.155 ;
     RECT  16.212 44.915 17.376 45.011 ;
     RECT  11.592 45.155 13.2 45.973 ;
     RECT  11.976 45.973 13.2 46.787 ;
     RECT  11.736 46.787 13.2 48.469 ;
     RECT  10.176 46.883 10.5 47.845 ;
     RECT  8.112 47.845 9.216 51.587 ;
     RECT  9.24 47.845 10.5 50.101 ;
     RECT  11.736 48.469 13.104 49.381 ;
     RECT  17.112 48.563 18.24 49.187 ;
     RECT  17.016 49.187 18.24 49.523 ;
     RECT  11.832 49.381 13.104 49.907 ;
     RECT  16.44 49.523 18.24 49.811 ;
     RECT  16.212 49.811 18.24 50.197 ;
     RECT  11.832 49.907 13.2 50.869 ;
     RECT  9.24 50.101 10.224 51.395 ;
     RECT  16.212 50.197 17.664 50.771 ;
     RECT  16.212 50.771 18.096 52.261 ;
     RECT  11.832 50.869 13.008 51.011 ;
     RECT  11.832 51.011 13.2 53.075 ;
     RECT  9.24 51.395 10.5 51.541 ;
     RECT  9.528 51.541 10.5 57.059 ;
     RECT  8.112 51.587 9.504 57.059 ;
     RECT  16.212 52.643 17.232 53.363 ;
     RECT  11.784 53.075 13.2 54.661 ;
     RECT  16.212 53.363 17.712 54.949 ;
     RECT  11.976 54.661 13.2 56.531 ;
     RECT  16.212 54.949 17.616 55.861 ;
     RECT  11.736 56.531 13.2 57.301 ;
     RECT  11.736 57.301 13.104 58.211 ;
     RECT  13.104 58.643 13.2 59.797 ;
     RECT  10.812 59.219 11.4 59.797 ;
     RECT  8.112 59.269 9.12 60.995 ;
     RECT  9.144 59.269 10.368 59.317 ;
     RECT  9.336 59.317 10.368 60.131 ;
     RECT  10.812 59.797 12 60.277 ;
     RECT  12.024 59.797 13.2 60.661 ;
     RECT  9.144 60.131 10.368 60.995 ;
     RECT  10.812 60.277 11.952 60.853 ;
     RECT  12.168 60.661 13.2 60.851 ;
     RECT  17.208 60.755 18.6 61.957 ;
     RECT  12.024 60.851 13.2 61.619 ;
     RECT  10.812 60.853 11.808 62.243 ;
     RECT  16.212 61.283 17.184 62.243 ;
     RECT  11.832 61.619 13.2 62.243 ;
     RECT  17.592 61.957 18.6 62.435 ;
     RECT  16.212 62.243 17.568 62.435 ;
  END
END hbfd_rly_624_WE_rr
END LIBRARY
